VERSION 5.8 ;
BUSBITCHARS "[]" ;
DIVIDERCHAR "/" ;
UNITS
    DATABASE MICRONS 1000 ;
END UNITS

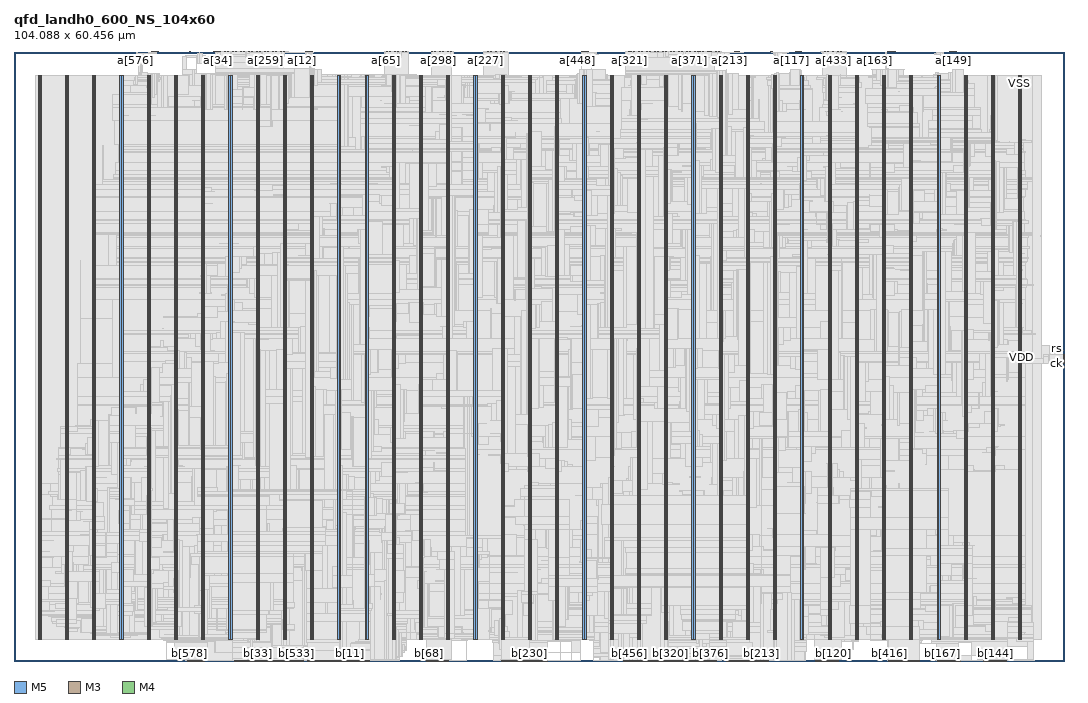
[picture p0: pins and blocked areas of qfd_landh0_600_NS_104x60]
MACRO qfd_landh0_600_NS_104x60
  FOREIGN qfd_landh0_600_NS_104x60 0 0 ;
  CLASS BLOCK ;
  SIZE 104.088 BY 60.456 ;
  PIN a[0]
    DIRECTION INPUT ;
    USE SIGNAL ;
    PORT
      LAYER M5 ;
        RECT  27.408 60.372 27.432 60.456 ;
    END
  END a[0]
  PIN a[100]
    DIRECTION INPUT ;
    USE SIGNAL ;
    PORT
      LAYER M5 ;
        RECT  75.408 60.372 75.432 60.456 ;
    END
  END a[100]
  PIN a[101]
    DIRECTION INPUT ;
    USE SIGNAL ;
    PORT
      LAYER M5 ;
        RECT  75.504 60.372 75.528 60.456 ;
    END
  END a[101]
  PIN a[102]
    DIRECTION INPUT ;
    USE SIGNAL ;
    PORT
      LAYER M5 ;
        RECT  75.6 60.372 75.624 60.456 ;
    END
  END a[102]
  PIN a[103]
    DIRECTION INPUT ;
    USE SIGNAL ;
    PORT
      LAYER M5 ;
        RECT  75.696 60.372 75.72 60.456 ;
    END
  END a[103]
  PIN a[104]
    DIRECTION INPUT ;
    USE SIGNAL ;
    PORT
      LAYER M5 ;
        RECT  75.792 60.372 75.816 60.456 ;
    END
  END a[104]
  PIN a[105]
    DIRECTION INPUT ;
    USE SIGNAL ;
    PORT
      LAYER M5 ;
        RECT  75.888 60.372 75.912 60.456 ;
    END
  END a[105]
  PIN a[106]
    DIRECTION INPUT ;
    USE SIGNAL ;
    PORT
      LAYER M5 ;
        RECT  75.984 60.372 76.008 60.456 ;
    END
  END a[106]
  PIN a[107]
    DIRECTION INPUT ;
    USE SIGNAL ;
    PORT
      LAYER M5 ;
        RECT  76.08 60.372 76.104 60.456 ;
    END
  END a[107]
  PIN a[108]
    DIRECTION INPUT ;
    USE SIGNAL ;
    PORT
      LAYER M5 ;
        RECT  76.176 60.372 76.2 60.456 ;
    END
  END a[108]
  PIN a[109]
    DIRECTION INPUT ;
    USE SIGNAL ;
    PORT
      LAYER M5 ;
        RECT  76.272 60.372 76.296 60.456 ;
    END
  END a[109]
  PIN a[10]
    DIRECTION INPUT ;
    USE SIGNAL ;
    PORT
      LAYER M5 ;
        RECT  28.368 60.372 28.392 60.456 ;
    END
  END a[10]
  PIN a[110]
    DIRECTION INPUT ;
    USE SIGNAL ;
    PORT
      LAYER M5 ;
        RECT  76.368 60.372 76.392 60.456 ;
    END
  END a[110]
  PIN a[111]
    DIRECTION INPUT ;
    USE SIGNAL ;
    PORT
      LAYER M5 ;
        RECT  76.464 60.372 76.488 60.456 ;
    END
  END a[111]
  PIN a[112]
    DIRECTION INPUT ;
    USE SIGNAL ;
    PORT
      LAYER M5 ;
        RECT  76.56 60.372 76.584 60.456 ;
    END
  END a[112]
  PIN a[113]
    DIRECTION INPUT ;
    USE SIGNAL ;
    PORT
      LAYER M5 ;
        RECT  76.656 60.372 76.68 60.456 ;
    END
  END a[113]
  PIN a[114]
    DIRECTION INPUT ;
    USE SIGNAL ;
    PORT
      LAYER M5 ;
        RECT  76.752 60.372 76.776 60.456 ;
    END
  END a[114]
  PIN a[115]
    DIRECTION INPUT ;
    USE SIGNAL ;
    PORT
      LAYER M5 ;
        RECT  76.848 60.372 76.872 60.456 ;
    END
  END a[115]
  PIN a[116]
    DIRECTION INPUT ;
    USE SIGNAL ;
    PORT
      LAYER M5 ;
        RECT  76.944 60.372 76.968 60.456 ;
    END
  END a[116]
  PIN a[117]
    DIRECTION INPUT ;
    USE SIGNAL ;
    PORT
      LAYER M5 ;
        RECT  77.04 60.372 77.064 60.456 ;
    END
  END a[117]
  PIN a[118]
    DIRECTION INPUT ;
    USE SIGNAL ;
    PORT
      LAYER M5 ;
        RECT  77.136 60.372 77.16 60.456 ;
    END
  END a[118]
  PIN a[119]
    DIRECTION INPUT ;
    USE SIGNAL ;
    PORT
      LAYER M5 ;
        RECT  77.232 60.372 77.256 60.456 ;
    END
  END a[119]
  PIN a[11]
    DIRECTION INPUT ;
    USE SIGNAL ;
    PORT
      LAYER M5 ;
        RECT  28.464 60.372 28.488 60.456 ;
    END
  END a[11]
  PIN a[120]
    DIRECTION INPUT ;
    USE SIGNAL ;
    PORT
      LAYER M5 ;
        RECT  77.328 60.372 77.352 60.456 ;
    END
  END a[120]
  PIN a[121]
    DIRECTION INPUT ;
    USE SIGNAL ;
    PORT
      LAYER M5 ;
        RECT  77.424 60.372 77.448 60.456 ;
    END
  END a[121]
  PIN a[122]
    DIRECTION INPUT ;
    USE SIGNAL ;
    PORT
      LAYER M5 ;
        RECT  77.52 60.372 77.544 60.456 ;
    END
  END a[122]
  PIN a[123]
    DIRECTION INPUT ;
    USE SIGNAL ;
    PORT
      LAYER M5 ;
        RECT  77.616 60.372 77.64 60.456 ;
    END
  END a[123]
  PIN a[124]
    DIRECTION INPUT ;
    USE SIGNAL ;
    PORT
      LAYER M5 ;
        RECT  77.712 60.372 77.736 60.456 ;
    END
  END a[124]
  PIN a[125]
    DIRECTION INPUT ;
    USE SIGNAL ;
    PORT
      LAYER M5 ;
        RECT  77.808 60.372 77.832 60.456 ;
    END
  END a[125]
  PIN a[126]
    DIRECTION INPUT ;
    USE SIGNAL ;
    PORT
      LAYER M5 ;
        RECT  77.904 60.372 77.928 60.456 ;
    END
  END a[126]
  PIN a[127]
    DIRECTION INPUT ;
    USE SIGNAL ;
    PORT
      LAYER M5 ;
        RECT  78 60.372 78.024 60.456 ;
    END
  END a[127]
  PIN a[128]
    DIRECTION INPUT ;
    USE SIGNAL ;
    PORT
      LAYER M5 ;
        RECT  91.152 60.372 91.176 60.456 ;
    END
  END a[128]
  PIN a[129]
    DIRECTION INPUT ;
    USE SIGNAL ;
    PORT
      LAYER M5 ;
        RECT  91.248 60.372 91.272 60.456 ;
    END
  END a[129]
  PIN a[12]
    DIRECTION INPUT ;
    USE SIGNAL ;
    PORT
      LAYER M5 ;
        RECT  28.56 60.372 28.584 60.456 ;
    END
  END a[12]
  PIN a[130]
    DIRECTION INPUT ;
    USE SIGNAL ;
    PORT
      LAYER M5 ;
        RECT  91.344 60.372 91.368 60.456 ;
    END
  END a[130]
  PIN a[131]
    DIRECTION INPUT ;
    USE SIGNAL ;
    PORT
      LAYER M5 ;
        RECT  91.44 60.372 91.464 60.456 ;
    END
  END a[131]
  PIN a[132]
    DIRECTION INPUT ;
    USE SIGNAL ;
    PORT
      LAYER M5 ;
        RECT  91.536 60.372 91.56 60.456 ;
    END
  END a[132]
  PIN a[133]
    DIRECTION INPUT ;
    USE SIGNAL ;
    PORT
      LAYER M5 ;
        RECT  91.632 60.372 91.656 60.456 ;
    END
  END a[133]
  PIN a[134]
    DIRECTION INPUT ;
    USE SIGNAL ;
    PORT
      LAYER M5 ;
        RECT  91.728 60.372 91.752 60.456 ;
    END
  END a[134]
  PIN a[135]
    DIRECTION INPUT ;
    USE SIGNAL ;
    PORT
      LAYER M5 ;
        RECT  91.824 60.372 91.848 60.456 ;
    END
  END a[135]
  PIN a[136]
    DIRECTION INPUT ;
    USE SIGNAL ;
    PORT
      LAYER M5 ;
        RECT  91.92 60.372 91.944 60.456 ;
    END
  END a[136]
  PIN a[137]
    DIRECTION INPUT ;
    USE SIGNAL ;
    PORT
      LAYER M5 ;
        RECT  92.016 60.372 92.04 60.456 ;
    END
  END a[137]
  PIN a[138]
    DIRECTION INPUT ;
    USE SIGNAL ;
    PORT
      LAYER M5 ;
        RECT  92.112 60.372 92.136 60.456 ;
    END
  END a[138]
  PIN a[139]
    DIRECTION INPUT ;
    USE SIGNAL ;
    PORT
      LAYER M5 ;
        RECT  92.208 60.372 92.232 60.456 ;
    END
  END a[139]
  PIN a[13]
    DIRECTION INPUT ;
    USE SIGNAL ;
    PORT
      LAYER M5 ;
        RECT  28.656 60.372 28.68 60.456 ;
    END
  END a[13]
  PIN a[140]
    DIRECTION INPUT ;
    USE SIGNAL ;
    PORT
      LAYER M5 ;
        RECT  92.304 60.372 92.328 60.456 ;
    END
  END a[140]
  PIN a[141]
    DIRECTION INPUT ;
    USE SIGNAL ;
    PORT
      LAYER M5 ;
        RECT  92.4 60.372 92.424 60.456 ;
    END
  END a[141]
  PIN a[142]
    DIRECTION INPUT ;
    USE SIGNAL ;
    PORT
      LAYER M5 ;
        RECT  92.496 60.372 92.52 60.456 ;
    END
  END a[142]
  PIN a[143]
    DIRECTION INPUT ;
    USE SIGNAL ;
    PORT
      LAYER M5 ;
        RECT  92.592 60.372 92.616 60.456 ;
    END
  END a[143]
  PIN a[144]
    DIRECTION INPUT ;
    USE SIGNAL ;
    PORT
      LAYER M5 ;
        RECT  92.688 60.372 92.712 60.456 ;
    END
  END a[144]
  PIN a[145]
    DIRECTION INPUT ;
    USE SIGNAL ;
    PORT
      LAYER M5 ;
        RECT  92.784 60.372 92.808 60.456 ;
    END
  END a[145]
  PIN a[146]
    DIRECTION INPUT ;
    USE SIGNAL ;
    PORT
      LAYER M5 ;
        RECT  92.88 60.372 92.904 60.456 ;
    END
  END a[146]
  PIN a[147]
    DIRECTION INPUT ;
    USE SIGNAL ;
    PORT
      LAYER M5 ;
        RECT  92.976 60.372 93 60.456 ;
    END
  END a[147]
  PIN a[148]
    DIRECTION INPUT ;
    USE SIGNAL ;
    PORT
      LAYER M5 ;
        RECT  93.072 60.372 93.096 60.456 ;
    END
  END a[148]
  PIN a[149]
    DIRECTION INPUT ;
    USE SIGNAL ;
    PORT
      LAYER M5 ;
        RECT  93.168 60.372 93.192 60.456 ;
    END
  END a[149]
  PIN a[14]
    DIRECTION INPUT ;
    USE SIGNAL ;
    PORT
      LAYER M5 ;
        RECT  28.752 60.372 28.776 60.456 ;
    END
  END a[14]
  PIN a[150]
    DIRECTION INPUT ;
    USE SIGNAL ;
    PORT
      LAYER M5 ;
        RECT  93.264 60.372 93.288 60.456 ;
    END
  END a[150]
  PIN a[151]
    DIRECTION INPUT ;
    USE SIGNAL ;
    PORT
      LAYER M5 ;
        RECT  93.36 60.372 93.384 60.456 ;
    END
  END a[151]
  PIN a[152]
    DIRECTION INPUT ;
    USE SIGNAL ;
    PORT
      LAYER M5 ;
        RECT  93.456 60.372 93.48 60.456 ;
    END
  END a[152]
  PIN a[153]
    DIRECTION INPUT ;
    USE SIGNAL ;
    PORT
      LAYER M5 ;
        RECT  93.552 60.372 93.576 60.456 ;
    END
  END a[153]
  PIN a[154]
    DIRECTION INPUT ;
    USE SIGNAL ;
    PORT
      LAYER M5 ;
        RECT  93.648 60.372 93.672 60.456 ;
    END
  END a[154]
  PIN a[155]
    DIRECTION INPUT ;
    USE SIGNAL ;
    PORT
      LAYER M5 ;
        RECT  93.744 60.372 93.768 60.456 ;
    END
  END a[155]
  PIN a[156]
    DIRECTION INPUT ;
    USE SIGNAL ;
    PORT
      LAYER M5 ;
        RECT  93.84 60.372 93.864 60.456 ;
    END
  END a[156]
  PIN a[157]
    DIRECTION INPUT ;
    USE SIGNAL ;
    PORT
      LAYER M5 ;
        RECT  93.936 60.372 93.96 60.456 ;
    END
  END a[157]
  PIN a[158]
    DIRECTION INPUT ;
    USE SIGNAL ;
    PORT
      LAYER M5 ;
        RECT  94.032 60.372 94.056 60.456 ;
    END
  END a[158]
  PIN a[159]
    DIRECTION INPUT ;
    USE SIGNAL ;
    PORT
      LAYER M5 ;
        RECT  94.128 60.372 94.152 60.456 ;
    END
  END a[159]
  PIN a[15]
    DIRECTION INPUT ;
    USE SIGNAL ;
    PORT
      LAYER M5 ;
        RECT  28.848 60.372 28.872 60.456 ;
    END
  END a[15]
  PIN a[160]
    DIRECTION INPUT ;
    USE SIGNAL ;
    PORT
      LAYER M5 ;
        RECT  85.008 60.372 85.032 60.456 ;
    END
  END a[160]
  PIN a[161]
    DIRECTION INPUT ;
    USE SIGNAL ;
    PORT
      LAYER M5 ;
        RECT  85.104 60.372 85.128 60.456 ;
    END
  END a[161]
  PIN a[162]
    DIRECTION INPUT ;
    USE SIGNAL ;
    PORT
      LAYER M5 ;
        RECT  85.2 60.372 85.224 60.456 ;
    END
  END a[162]
  PIN a[163]
    DIRECTION INPUT ;
    USE SIGNAL ;
    PORT
      LAYER M5 ;
        RECT  85.296 60.372 85.32 60.456 ;
    END
  END a[163]
  PIN a[164]
    DIRECTION INPUT ;
    USE SIGNAL ;
    PORT
      LAYER M5 ;
        RECT  85.392 60.372 85.416 60.456 ;
    END
  END a[164]
  PIN a[165]
    DIRECTION INPUT ;
    USE SIGNAL ;
    PORT
      LAYER M5 ;
        RECT  85.488 60.372 85.512 60.456 ;
    END
  END a[165]
  PIN a[166]
    DIRECTION INPUT ;
    USE SIGNAL ;
    PORT
      LAYER M5 ;
        RECT  85.584 60.372 85.608 60.456 ;
    END
  END a[166]
  PIN a[167]
    DIRECTION INPUT ;
    USE SIGNAL ;
    PORT
      LAYER M5 ;
        RECT  85.68 60.372 85.704 60.456 ;
    END
  END a[167]
  PIN a[168]
    DIRECTION INPUT ;
    USE SIGNAL ;
    PORT
      LAYER M5 ;
        RECT  85.776 60.372 85.8 60.456 ;
    END
  END a[168]
  PIN a[169]
    DIRECTION INPUT ;
    USE SIGNAL ;
    PORT
      LAYER M5 ;
        RECT  85.872 60.372 85.896 60.456 ;
    END
  END a[169]
  PIN a[16]
    DIRECTION INPUT ;
    USE SIGNAL ;
    PORT
      LAYER M5 ;
        RECT  28.944 60.372 28.968 60.456 ;
    END
  END a[16]
  PIN a[170]
    DIRECTION INPUT ;
    USE SIGNAL ;
    PORT
      LAYER M5 ;
        RECT  85.968 60.372 85.992 60.456 ;
    END
  END a[170]
  PIN a[171]
    DIRECTION INPUT ;
    USE SIGNAL ;
    PORT
      LAYER M5 ;
        RECT  86.064 60.372 86.088 60.456 ;
    END
  END a[171]
  PIN a[172]
    DIRECTION INPUT ;
    USE SIGNAL ;
    PORT
      LAYER M5 ;
        RECT  86.16 60.372 86.184 60.456 ;
    END
  END a[172]
  PIN a[173]
    DIRECTION INPUT ;
    USE SIGNAL ;
    PORT
      LAYER M5 ;
        RECT  86.256 60.372 86.28 60.456 ;
    END
  END a[173]
  PIN a[174]
    DIRECTION INPUT ;
    USE SIGNAL ;
    PORT
      LAYER M5 ;
        RECT  86.352 60.372 86.376 60.456 ;
    END
  END a[174]
  PIN a[175]
    DIRECTION INPUT ;
    USE SIGNAL ;
    PORT
      LAYER M5 ;
        RECT  86.448 60.372 86.472 60.456 ;
    END
  END a[175]
  PIN a[176]
    DIRECTION INPUT ;
    USE SIGNAL ;
    PORT
      LAYER M5 ;
        RECT  86.544 60.372 86.568 60.456 ;
    END
  END a[176]
  PIN a[177]
    DIRECTION INPUT ;
    USE SIGNAL ;
    PORT
      LAYER M5 ;
        RECT  86.64 60.372 86.664 60.456 ;
    END
  END a[177]
  PIN a[178]
    DIRECTION INPUT ;
    USE SIGNAL ;
    PORT
      LAYER M5 ;
        RECT  86.736 60.372 86.76 60.456 ;
    END
  END a[178]
  PIN a[179]
    DIRECTION INPUT ;
    USE SIGNAL ;
    PORT
      LAYER M5 ;
        RECT  86.832 60.372 86.856 60.456 ;
    END
  END a[179]
  PIN a[17]
    DIRECTION INPUT ;
    USE SIGNAL ;
    PORT
      LAYER M5 ;
        RECT  29.04 60.372 29.064 60.456 ;
    END
  END a[17]
  PIN a[180]
    DIRECTION INPUT ;
    USE SIGNAL ;
    PORT
      LAYER M5 ;
        RECT  86.928 60.372 86.952 60.456 ;
    END
  END a[180]
  PIN a[181]
    DIRECTION INPUT ;
    USE SIGNAL ;
    PORT
      LAYER M5 ;
        RECT  87.024 60.372 87.048 60.456 ;
    END
  END a[181]
  PIN a[182]
    DIRECTION INPUT ;
    USE SIGNAL ;
    PORT
      LAYER M5 ;
        RECT  87.12 60.372 87.144 60.456 ;
    END
  END a[182]
  PIN a[183]
    DIRECTION INPUT ;
    USE SIGNAL ;
    PORT
      LAYER M5 ;
        RECT  87.216 60.372 87.24 60.456 ;
    END
  END a[183]
  PIN a[184]
    DIRECTION INPUT ;
    USE SIGNAL ;
    PORT
      LAYER M5 ;
        RECT  87.312 60.372 87.336 60.456 ;
    END
  END a[184]
  PIN a[185]
    DIRECTION INPUT ;
    USE SIGNAL ;
    PORT
      LAYER M5 ;
        RECT  87.408 60.372 87.432 60.456 ;
    END
  END a[185]
  PIN a[186]
    DIRECTION INPUT ;
    USE SIGNAL ;
    PORT
      LAYER M5 ;
        RECT  87.504 60.372 87.528 60.456 ;
    END
  END a[186]
  PIN a[187]
    DIRECTION INPUT ;
    USE SIGNAL ;
    PORT
      LAYER M5 ;
        RECT  87.6 60.372 87.624 60.456 ;
    END
  END a[187]
  PIN a[188]
    DIRECTION INPUT ;
    USE SIGNAL ;
    PORT
      LAYER M5 ;
        RECT  87.696 60.372 87.72 60.456 ;
    END
  END a[188]
  PIN a[189]
    DIRECTION INPUT ;
    USE SIGNAL ;
    PORT
      LAYER M5 ;
        RECT  87.792 60.372 87.816 60.456 ;
    END
  END a[189]
  PIN a[18]
    DIRECTION INPUT ;
    USE SIGNAL ;
    PORT
      LAYER M5 ;
        RECT  29.136 60.372 29.16 60.456 ;
    END
  END a[18]
  PIN a[190]
    DIRECTION INPUT ;
    USE SIGNAL ;
    PORT
      LAYER M5 ;
        RECT  87.888 60.372 87.912 60.456 ;
    END
  END a[190]
  PIN a[191]
    DIRECTION INPUT ;
    USE SIGNAL ;
    PORT
      LAYER M5 ;
        RECT  87.984 60.372 88.008 60.456 ;
    END
  END a[191]
  PIN a[192]
    DIRECTION INPUT ;
    USE SIGNAL ;
    PORT
      LAYER M5 ;
        RECT  68.88 60.372 68.904 60.456 ;
    END
  END a[192]
  PIN a[193]
    DIRECTION INPUT ;
    USE SIGNAL ;
    PORT
      LAYER M5 ;
        RECT  68.976 60.372 69 60.456 ;
    END
  END a[193]
  PIN a[194]
    DIRECTION INPUT ;
    USE SIGNAL ;
    PORT
      LAYER M5 ;
        RECT  69.072 60.372 69.096 60.456 ;
    END
  END a[194]
  PIN a[195]
    DIRECTION INPUT ;
    USE SIGNAL ;
    PORT
      LAYER M5 ;
        RECT  69.168 60.372 69.192 60.456 ;
    END
  END a[195]
  PIN a[196]
    DIRECTION INPUT ;
    USE SIGNAL ;
    PORT
      LAYER M5 ;
        RECT  69.264 60.372 69.288 60.456 ;
    END
  END a[196]
  PIN a[197]
    DIRECTION INPUT ;
    USE SIGNAL ;
    PORT
      LAYER M5 ;
        RECT  69.36 60.372 69.384 60.456 ;
    END
  END a[197]
  PIN a[198]
    DIRECTION INPUT ;
    USE SIGNAL ;
    PORT
      LAYER M5 ;
        RECT  69.456 60.372 69.48 60.456 ;
    END
  END a[198]
  PIN a[199]
    DIRECTION INPUT ;
    USE SIGNAL ;
    PORT
      LAYER M5 ;
        RECT  69.552 60.372 69.576 60.456 ;
    END
  END a[199]
  PIN a[19]
    DIRECTION INPUT ;
    USE SIGNAL ;
    PORT
      LAYER M5 ;
        RECT  29.232 60.372 29.256 60.456 ;
    END
  END a[19]
  PIN a[1]
    DIRECTION INPUT ;
    USE SIGNAL ;
    PORT
      LAYER M5 ;
        RECT  27.504 60.372 27.528 60.456 ;
    END
  END a[1]
  PIN a[200]
    DIRECTION INPUT ;
    USE SIGNAL ;
    PORT
      LAYER M5 ;
        RECT  69.648 60.372 69.672 60.456 ;
    END
  END a[200]
  PIN a[201]
    DIRECTION INPUT ;
    USE SIGNAL ;
    PORT
      LAYER M5 ;
        RECT  69.744 60.372 69.768 60.456 ;
    END
  END a[201]
  PIN a[202]
    DIRECTION INPUT ;
    USE SIGNAL ;
    PORT
      LAYER M5 ;
        RECT  69.84 60.372 69.864 60.456 ;
    END
  END a[202]
  PIN a[203]
    DIRECTION INPUT ;
    USE SIGNAL ;
    PORT
      LAYER M5 ;
        RECT  69.936 60.372 69.96 60.456 ;
    END
  END a[203]
  PIN a[204]
    DIRECTION INPUT ;
    USE SIGNAL ;
    PORT
      LAYER M5 ;
        RECT  70.032 60.372 70.056 60.456 ;
    END
  END a[204]
  PIN a[205]
    DIRECTION INPUT ;
    USE SIGNAL ;
    PORT
      LAYER M5 ;
        RECT  70.128 60.372 70.152 60.456 ;
    END
  END a[205]
  PIN a[206]
    DIRECTION INPUT ;
    USE SIGNAL ;
    PORT
      LAYER M5 ;
        RECT  70.224 60.372 70.248 60.456 ;
    END
  END a[206]
  PIN a[207]
    DIRECTION INPUT ;
    USE SIGNAL ;
    PORT
      LAYER M5 ;
        RECT  70.32 60.372 70.344 60.456 ;
    END
  END a[207]
  PIN a[208]
    DIRECTION INPUT ;
    USE SIGNAL ;
    PORT
      LAYER M5 ;
        RECT  70.416 60.372 70.44 60.456 ;
    END
  END a[208]
  PIN a[209]
    DIRECTION INPUT ;
    USE SIGNAL ;
    PORT
      LAYER M5 ;
        RECT  70.512 60.372 70.536 60.456 ;
    END
  END a[209]
  PIN a[20]
    DIRECTION INPUT ;
    USE SIGNAL ;
    PORT
      LAYER M5 ;
        RECT  29.328 60.372 29.352 60.456 ;
    END
  END a[20]
  PIN a[210]
    DIRECTION INPUT ;
    USE SIGNAL ;
    PORT
      LAYER M5 ;
        RECT  70.608 60.372 70.632 60.456 ;
    END
  END a[210]
  PIN a[211]
    DIRECTION INPUT ;
    USE SIGNAL ;
    PORT
      LAYER M5 ;
        RECT  70.704 60.372 70.728 60.456 ;
    END
  END a[211]
  PIN a[212]
    DIRECTION INPUT ;
    USE SIGNAL ;
    PORT
      LAYER M5 ;
        RECT  70.8 60.372 70.824 60.456 ;
    END
  END a[212]
  PIN a[213]
    DIRECTION INPUT ;
    USE SIGNAL ;
    PORT
      LAYER M5 ;
        RECT  70.896 60.372 70.92 60.456 ;
    END
  END a[213]
  PIN a[214]
    DIRECTION INPUT ;
    USE SIGNAL ;
    PORT
      LAYER M5 ;
        RECT  70.992 60.372 71.016 60.456 ;
    END
  END a[214]
  PIN a[215]
    DIRECTION INPUT ;
    USE SIGNAL ;
    PORT
      LAYER M5 ;
        RECT  71.088 60.372 71.112 60.456 ;
    END
  END a[215]
  PIN a[216]
    DIRECTION INPUT ;
    USE SIGNAL ;
    PORT
      LAYER M5 ;
        RECT  71.184 60.372 71.208 60.456 ;
    END
  END a[216]
  PIN a[217]
    DIRECTION INPUT ;
    USE SIGNAL ;
    PORT
      LAYER M5 ;
        RECT  71.28 60.372 71.304 60.456 ;
    END
  END a[217]
  PIN a[218]
    DIRECTION INPUT ;
    USE SIGNAL ;
    PORT
      LAYER M5 ;
        RECT  71.376 60.372 71.4 60.456 ;
    END
  END a[218]
  PIN a[219]
    DIRECTION INPUT ;
    USE SIGNAL ;
    PORT
      LAYER M5 ;
        RECT  71.472 60.372 71.496 60.456 ;
    END
  END a[219]
  PIN a[21]
    DIRECTION INPUT ;
    USE SIGNAL ;
    PORT
      LAYER M5 ;
        RECT  29.424 60.372 29.448 60.456 ;
    END
  END a[21]
  PIN a[220]
    DIRECTION INPUT ;
    USE SIGNAL ;
    PORT
      LAYER M5 ;
        RECT  71.568 60.372 71.592 60.456 ;
    END
  END a[220]
  PIN a[221]
    DIRECTION INPUT ;
    USE SIGNAL ;
    PORT
      LAYER M5 ;
        RECT  71.664 60.372 71.688 60.456 ;
    END
  END a[221]
  PIN a[222]
    DIRECTION INPUT ;
    USE SIGNAL ;
    PORT
      LAYER M5 ;
        RECT  71.76 60.372 71.784 60.456 ;
    END
  END a[222]
  PIN a[223]
    DIRECTION INPUT ;
    USE SIGNAL ;
    PORT
      LAYER M5 ;
        RECT  71.856 60.372 71.88 60.456 ;
    END
  END a[223]
  PIN a[224]
    DIRECTION INPUT ;
    USE SIGNAL ;
    PORT
      LAYER M3 ;
        RECT  46.548 60.419 46.566 60.456 ;
    END
  END a[224]
  PIN a[225]
    DIRECTION INPUT ;
    USE SIGNAL ;
    PORT
      LAYER M3 ;
        RECT  46.62 60.419 46.638 60.456 ;
    END
  END a[225]
  PIN a[226]
    DIRECTION INPUT ;
    USE SIGNAL ;
    PORT
      LAYER M3 ;
        RECT  46.692 60.419 46.71 60.456 ;
    END
  END a[226]
  PIN a[227]
    DIRECTION INPUT ;
    USE SIGNAL ;
    PORT
      LAYER M3 ;
        RECT  46.764 60.419 46.782 60.456 ;
    END
  END a[227]
  PIN a[228]
    DIRECTION INPUT ;
    USE SIGNAL ;
    PORT
      LAYER M3 ;
        RECT  46.836 60.419 46.854 60.456 ;
    END
  END a[228]
  PIN a[229]
    DIRECTION INPUT ;
    USE SIGNAL ;
    PORT
      LAYER M3 ;
        RECT  46.908 60.419 46.926 60.456 ;
    END
  END a[229]
  PIN a[22]
    DIRECTION INPUT ;
    USE SIGNAL ;
    PORT
      LAYER M5 ;
        RECT  29.52 60.372 29.544 60.456 ;
    END
  END a[22]
  PIN a[230]
    DIRECTION INPUT ;
    USE SIGNAL ;
    PORT
      LAYER M3 ;
        RECT  46.98 60.419 46.998 60.456 ;
    END
  END a[230]
  PIN a[231]
    DIRECTION INPUT ;
    USE SIGNAL ;
    PORT
      LAYER M3 ;
        RECT  47.052 60.419 47.07 60.456 ;
    END
  END a[231]
  PIN a[232]
    DIRECTION INPUT ;
    USE SIGNAL ;
    PORT
      LAYER M3 ;
        RECT  47.124 60.419 47.142 60.456 ;
    END
  END a[232]
  PIN a[233]
    DIRECTION INPUT ;
    USE SIGNAL ;
    PORT
      LAYER M3 ;
        RECT  47.196 60.419 47.214 60.456 ;
    END
  END a[233]
  PIN a[234]
    DIRECTION INPUT ;
    USE SIGNAL ;
    PORT
      LAYER M3 ;
        RECT  47.268 60.419 47.286 60.456 ;
    END
  END a[234]
  PIN a[235]
    DIRECTION INPUT ;
    USE SIGNAL ;
    PORT
      LAYER M3 ;
        RECT  47.34 60.419 47.358 60.456 ;
    END
  END a[235]
  PIN a[236]
    DIRECTION INPUT ;
    USE SIGNAL ;
    PORT
      LAYER M3 ;
        RECT  47.412 60.419 47.43 60.456 ;
    END
  END a[236]
  PIN a[237]
    DIRECTION INPUT ;
    USE SIGNAL ;
    PORT
      LAYER M3 ;
        RECT  47.484 60.419 47.502 60.456 ;
    END
  END a[237]
  PIN a[238]
    DIRECTION INPUT ;
    USE SIGNAL ;
    PORT
      LAYER M3 ;
        RECT  47.556 60.419 47.574 60.456 ;
    END
  END a[238]
  PIN a[239]
    DIRECTION INPUT ;
    USE SIGNAL ;
    PORT
      LAYER M3 ;
        RECT  47.628 60.419 47.646 60.456 ;
    END
  END a[239]
  PIN a[23]
    DIRECTION INPUT ;
    USE SIGNAL ;
    PORT
      LAYER M5 ;
        RECT  29.616 60.372 29.64 60.456 ;
    END
  END a[23]
  PIN a[240]
    DIRECTION INPUT ;
    USE SIGNAL ;
    PORT
      LAYER M3 ;
        RECT  47.7 60.419 47.718 60.456 ;
    END
  END a[240]
  PIN a[241]
    DIRECTION INPUT ;
    USE SIGNAL ;
    PORT
      LAYER M3 ;
        RECT  47.772 60.419 47.79 60.456 ;
    END
  END a[241]
  PIN a[242]
    DIRECTION INPUT ;
    USE SIGNAL ;
    PORT
      LAYER M3 ;
        RECT  47.844 60.419 47.862 60.456 ;
    END
  END a[242]
  PIN a[243]
    DIRECTION INPUT ;
    USE SIGNAL ;
    PORT
      LAYER M3 ;
        RECT  47.916 60.419 47.934 60.456 ;
    END
  END a[243]
  PIN a[244]
    DIRECTION INPUT ;
    USE SIGNAL ;
    PORT
      LAYER M3 ;
        RECT  47.988 60.419 48.006 60.456 ;
    END
  END a[244]
  PIN a[245]
    DIRECTION INPUT ;
    USE SIGNAL ;
    PORT
      LAYER M3 ;
        RECT  48.06 60.419 48.078 60.456 ;
    END
  END a[245]
  PIN a[246]
    DIRECTION INPUT ;
    USE SIGNAL ;
    PORT
      LAYER M3 ;
        RECT  48.132 60.419 48.15 60.456 ;
    END
  END a[246]
  PIN a[247]
    DIRECTION INPUT ;
    USE SIGNAL ;
    PORT
      LAYER M3 ;
        RECT  48.204 60.419 48.222 60.456 ;
    END
  END a[247]
  PIN a[248]
    DIRECTION INPUT ;
    USE SIGNAL ;
    PORT
      LAYER M3 ;
        RECT  48.276 60.419 48.294 60.456 ;
    END
  END a[248]
  PIN a[249]
    DIRECTION INPUT ;
    USE SIGNAL ;
    PORT
      LAYER M3 ;
        RECT  48.348 60.419 48.366 60.456 ;
    END
  END a[249]
  PIN a[24]
    DIRECTION INPUT ;
    USE SIGNAL ;
    PORT
      LAYER M5 ;
        RECT  29.712 60.372 29.736 60.456 ;
    END
  END a[24]
  PIN a[250]
    DIRECTION INPUT ;
    USE SIGNAL ;
    PORT
      LAYER M3 ;
        RECT  48.42 60.419 48.438 60.456 ;
    END
  END a[250]
  PIN a[251]
    DIRECTION INPUT ;
    USE SIGNAL ;
    PORT
      LAYER M3 ;
        RECT  48.492 60.419 48.51 60.456 ;
    END
  END a[251]
  PIN a[252]
    DIRECTION INPUT ;
    USE SIGNAL ;
    PORT
      LAYER M3 ;
        RECT  48.564 60.419 48.582 60.456 ;
    END
  END a[252]
  PIN a[253]
    DIRECTION INPUT ;
    USE SIGNAL ;
    PORT
      LAYER M3 ;
        RECT  48.636 60.419 48.654 60.456 ;
    END
  END a[253]
  PIN a[254]
    DIRECTION INPUT ;
    USE SIGNAL ;
    PORT
      LAYER M3 ;
        RECT  48.708 60.419 48.726 60.456 ;
    END
  END a[254]
  PIN a[255]
    DIRECTION INPUT ;
    USE SIGNAL ;
    PORT
      LAYER M3 ;
        RECT  48.78 60.419 48.798 60.456 ;
    END
  END a[255]
  PIN a[256]
    DIRECTION INPUT ;
    USE SIGNAL ;
    PORT
      LAYER M3 ;
        RECT  24.66 60.419 24.678 60.456 ;
    END
  END a[256]
  PIN a[257]
    DIRECTION INPUT ;
    USE SIGNAL ;
    PORT
      LAYER M3 ;
        RECT  24.732 60.419 24.75 60.456 ;
    END
  END a[257]
  PIN a[258]
    DIRECTION INPUT ;
    USE SIGNAL ;
    PORT
      LAYER M3 ;
        RECT  24.804 60.419 24.822 60.456 ;
    END
  END a[258]
  PIN a[259]
    DIRECTION INPUT ;
    USE SIGNAL ;
    PORT
      LAYER M3 ;
        RECT  24.876 60.419 24.894 60.456 ;
    END
  END a[259]
  PIN a[25]
    DIRECTION INPUT ;
    USE SIGNAL ;
    PORT
      LAYER M5 ;
        RECT  29.808 60.372 29.832 60.456 ;
    END
  END a[25]
  PIN a[260]
    DIRECTION INPUT ;
    USE SIGNAL ;
    PORT
      LAYER M3 ;
        RECT  24.948 60.419 24.966 60.456 ;
    END
  END a[260]
  PIN a[261]
    DIRECTION INPUT ;
    USE SIGNAL ;
    PORT
      LAYER M3 ;
        RECT  25.02 60.419 25.038 60.456 ;
    END
  END a[261]
  PIN a[262]
    DIRECTION INPUT ;
    USE SIGNAL ;
    PORT
      LAYER M3 ;
        RECT  25.092 60.419 25.11 60.456 ;
    END
  END a[262]
  PIN a[263]
    DIRECTION INPUT ;
    USE SIGNAL ;
    PORT
      LAYER M3 ;
        RECT  25.164 60.419 25.182 60.456 ;
    END
  END a[263]
  PIN a[264]
    DIRECTION INPUT ;
    USE SIGNAL ;
    PORT
      LAYER M3 ;
        RECT  25.236 60.419 25.254 60.456 ;
    END
  END a[264]
  PIN a[265]
    DIRECTION INPUT ;
    USE SIGNAL ;
    PORT
      LAYER M3 ;
        RECT  25.308 60.419 25.326 60.456 ;
    END
  END a[265]
  PIN a[266]
    DIRECTION INPUT ;
    USE SIGNAL ;
    PORT
      LAYER M3 ;
        RECT  25.38 60.419 25.398 60.456 ;
    END
  END a[266]
  PIN a[267]
    DIRECTION INPUT ;
    USE SIGNAL ;
    PORT
      LAYER M3 ;
        RECT  25.452 60.419 25.47 60.456 ;
    END
  END a[267]
  PIN a[268]
    DIRECTION INPUT ;
    USE SIGNAL ;
    PORT
      LAYER M3 ;
        RECT  25.524 60.419 25.542 60.456 ;
    END
  END a[268]
  PIN a[269]
    DIRECTION INPUT ;
    USE SIGNAL ;
    PORT
      LAYER M3 ;
        RECT  25.596 60.419 25.614 60.456 ;
    END
  END a[269]
  PIN a[26]
    DIRECTION INPUT ;
    USE SIGNAL ;
    PORT
      LAYER M5 ;
        RECT  29.904 60.372 29.928 60.456 ;
    END
  END a[26]
  PIN a[270]
    DIRECTION INPUT ;
    USE SIGNAL ;
    PORT
      LAYER M3 ;
        RECT  25.668 60.419 25.686 60.456 ;
    END
  END a[270]
  PIN a[271]
    DIRECTION INPUT ;
    USE SIGNAL ;
    PORT
      LAYER M3 ;
        RECT  25.74 60.419 25.758 60.456 ;
    END
  END a[271]
  PIN a[272]
    DIRECTION INPUT ;
    USE SIGNAL ;
    PORT
      LAYER M3 ;
        RECT  25.812 60.419 25.83 60.456 ;
    END
  END a[272]
  PIN a[273]
    DIRECTION INPUT ;
    USE SIGNAL ;
    PORT
      LAYER M3 ;
        RECT  25.884 60.419 25.902 60.456 ;
    END
  END a[273]
  PIN a[274]
    DIRECTION INPUT ;
    USE SIGNAL ;
    PORT
      LAYER M3 ;
        RECT  25.956 60.419 25.974 60.456 ;
    END
  END a[274]
  PIN a[275]
    DIRECTION INPUT ;
    USE SIGNAL ;
    PORT
      LAYER M3 ;
        RECT  26.028 60.419 26.046 60.456 ;
    END
  END a[275]
  PIN a[276]
    DIRECTION INPUT ;
    USE SIGNAL ;
    PORT
      LAYER M3 ;
        RECT  26.1 60.419 26.118 60.456 ;
    END
  END a[276]
  PIN a[277]
    DIRECTION INPUT ;
    USE SIGNAL ;
    PORT
      LAYER M3 ;
        RECT  26.172 60.419 26.19 60.456 ;
    END
  END a[277]
  PIN a[278]
    DIRECTION INPUT ;
    USE SIGNAL ;
    PORT
      LAYER M3 ;
        RECT  26.244 60.419 26.262 60.456 ;
    END
  END a[278]
  PIN a[279]
    DIRECTION INPUT ;
    USE SIGNAL ;
    PORT
      LAYER M3 ;
        RECT  26.316 60.419 26.334 60.456 ;
    END
  END a[279]
  PIN a[27]
    DIRECTION INPUT ;
    USE SIGNAL ;
    PORT
      LAYER M5 ;
        RECT  30 60.372 30.024 60.456 ;
    END
  END a[27]
  PIN a[280]
    DIRECTION INPUT ;
    USE SIGNAL ;
    PORT
      LAYER M3 ;
        RECT  26.388 60.419 26.406 60.456 ;
    END
  END a[280]
  PIN a[281]
    DIRECTION INPUT ;
    USE SIGNAL ;
    PORT
      LAYER M3 ;
        RECT  26.46 60.419 26.478 60.456 ;
    END
  END a[281]
  PIN a[282]
    DIRECTION INPUT ;
    USE SIGNAL ;
    PORT
      LAYER M3 ;
        RECT  26.532 60.419 26.55 60.456 ;
    END
  END a[282]
  PIN a[283]
    DIRECTION INPUT ;
    USE SIGNAL ;
    PORT
      LAYER M3 ;
        RECT  26.604 60.419 26.622 60.456 ;
    END
  END a[283]
  PIN a[284]
    DIRECTION INPUT ;
    USE SIGNAL ;
    PORT
      LAYER M3 ;
        RECT  26.676 60.419 26.694 60.456 ;
    END
  END a[284]
  PIN a[285]
    DIRECTION INPUT ;
    USE SIGNAL ;
    PORT
      LAYER M3 ;
        RECT  26.748 60.419 26.766 60.456 ;
    END
  END a[285]
  PIN a[286]
    DIRECTION INPUT ;
    USE SIGNAL ;
    PORT
      LAYER M3 ;
        RECT  26.82 60.419 26.838 60.456 ;
    END
  END a[286]
  PIN a[287]
    DIRECTION INPUT ;
    USE SIGNAL ;
    PORT
      LAYER M3 ;
        RECT  26.892 60.419 26.91 60.456 ;
    END
  END a[287]
  PIN a[288]
    DIRECTION INPUT ;
    USE SIGNAL ;
    PORT
      LAYER M3 ;
        RECT  41.364 60.419 41.382 60.456 ;
    END
  END a[288]
  PIN a[289]
    DIRECTION INPUT ;
    USE SIGNAL ;
    PORT
      LAYER M3 ;
        RECT  41.436 60.419 41.454 60.456 ;
    END
  END a[289]
  PIN a[28]
    DIRECTION INPUT ;
    USE SIGNAL ;
    PORT
      LAYER M5 ;
        RECT  30.096 60.372 30.12 60.456 ;
    END
  END a[28]
  PIN a[290]
    DIRECTION INPUT ;
    USE SIGNAL ;
    PORT
      LAYER M3 ;
        RECT  41.508 60.419 41.526 60.456 ;
    END
  END a[290]
  PIN a[291]
    DIRECTION INPUT ;
    USE SIGNAL ;
    PORT
      LAYER M3 ;
        RECT  41.58 60.419 41.598 60.456 ;
    END
  END a[291]
  PIN a[292]
    DIRECTION INPUT ;
    USE SIGNAL ;
    PORT
      LAYER M3 ;
        RECT  41.652 60.419 41.67 60.456 ;
    END
  END a[292]
  PIN a[293]
    DIRECTION INPUT ;
    USE SIGNAL ;
    PORT
      LAYER M3 ;
        RECT  41.724 60.419 41.742 60.456 ;
    END
  END a[293]
  PIN a[294]
    DIRECTION INPUT ;
    USE SIGNAL ;
    PORT
      LAYER M3 ;
        RECT  41.796 60.419 41.814 60.456 ;
    END
  END a[294]
  PIN a[295]
    DIRECTION INPUT ;
    USE SIGNAL ;
    PORT
      LAYER M3 ;
        RECT  41.868 60.419 41.886 60.456 ;
    END
  END a[295]
  PIN a[296]
    DIRECTION INPUT ;
    USE SIGNAL ;
    PORT
      LAYER M3 ;
        RECT  41.94 60.419 41.958 60.456 ;
    END
  END a[296]
  PIN a[297]
    DIRECTION INPUT ;
    USE SIGNAL ;
    PORT
      LAYER M3 ;
        RECT  42.012 60.419 42.03 60.456 ;
    END
  END a[297]
  PIN a[298]
    DIRECTION INPUT ;
    USE SIGNAL ;
    PORT
      LAYER M3 ;
        RECT  42.084 60.419 42.102 60.456 ;
    END
  END a[298]
  PIN a[299]
    DIRECTION INPUT ;
    USE SIGNAL ;
    PORT
      LAYER M3 ;
        RECT  42.156 60.419 42.174 60.456 ;
    END
  END a[299]
  PIN a[29]
    DIRECTION INPUT ;
    USE SIGNAL ;
    PORT
      LAYER M5 ;
        RECT  30.192 60.372 30.216 60.456 ;
    END
  END a[29]
  PIN a[2]
    DIRECTION INPUT ;
    USE SIGNAL ;
    PORT
      LAYER M5 ;
        RECT  27.6 60.372 27.624 60.456 ;
    END
  END a[2]
  PIN a[300]
    DIRECTION INPUT ;
    USE SIGNAL ;
    PORT
      LAYER M3 ;
        RECT  42.228 60.419 42.246 60.456 ;
    END
  END a[300]
  PIN a[301]
    DIRECTION INPUT ;
    USE SIGNAL ;
    PORT
      LAYER M3 ;
        RECT  42.3 60.419 42.318 60.456 ;
    END
  END a[301]
  PIN a[302]
    DIRECTION INPUT ;
    USE SIGNAL ;
    PORT
      LAYER M3 ;
        RECT  42.372 60.419 42.39 60.456 ;
    END
  END a[302]
  PIN a[303]
    DIRECTION INPUT ;
    USE SIGNAL ;
    PORT
      LAYER M3 ;
        RECT  42.444 60.419 42.462 60.456 ;
    END
  END a[303]
  PIN a[304]
    DIRECTION INPUT ;
    USE SIGNAL ;
    PORT
      LAYER M3 ;
        RECT  42.516 60.419 42.534 60.456 ;
    END
  END a[304]
  PIN a[305]
    DIRECTION INPUT ;
    USE SIGNAL ;
    PORT
      LAYER M3 ;
        RECT  42.588 60.419 42.606 60.456 ;
    END
  END a[305]
  PIN a[306]
    DIRECTION INPUT ;
    USE SIGNAL ;
    PORT
      LAYER M3 ;
        RECT  42.66 60.419 42.678 60.456 ;
    END
  END a[306]
  PIN a[307]
    DIRECTION INPUT ;
    USE SIGNAL ;
    PORT
      LAYER M3 ;
        RECT  42.732 60.419 42.75 60.456 ;
    END
  END a[307]
  PIN a[308]
    DIRECTION INPUT ;
    USE SIGNAL ;
    PORT
      LAYER M3 ;
        RECT  42.804 60.419 42.822 60.456 ;
    END
  END a[308]
  PIN a[309]
    DIRECTION INPUT ;
    USE SIGNAL ;
    PORT
      LAYER M3 ;
        RECT  42.876 60.419 42.894 60.456 ;
    END
  END a[309]
  PIN a[30]
    DIRECTION INPUT ;
    USE SIGNAL ;
    PORT
      LAYER M5 ;
        RECT  30.288 60.372 30.312 60.456 ;
    END
  END a[30]
  PIN a[310]
    DIRECTION INPUT ;
    USE SIGNAL ;
    PORT
      LAYER M3 ;
        RECT  42.948 60.419 42.966 60.456 ;
    END
  END a[310]
  PIN a[311]
    DIRECTION INPUT ;
    USE SIGNAL ;
    PORT
      LAYER M3 ;
        RECT  43.02 60.419 43.038 60.456 ;
    END
  END a[311]
  PIN a[312]
    DIRECTION INPUT ;
    USE SIGNAL ;
    PORT
      LAYER M3 ;
        RECT  43.092 60.419 43.11 60.456 ;
    END
  END a[312]
  PIN a[313]
    DIRECTION INPUT ;
    USE SIGNAL ;
    PORT
      LAYER M3 ;
        RECT  43.164 60.419 43.182 60.456 ;
    END
  END a[313]
  PIN a[314]
    DIRECTION INPUT ;
    USE SIGNAL ;
    PORT
      LAYER M3 ;
        RECT  43.236 60.419 43.254 60.456 ;
    END
  END a[314]
  PIN a[315]
    DIRECTION INPUT ;
    USE SIGNAL ;
    PORT
      LAYER M3 ;
        RECT  43.308 60.419 43.326 60.456 ;
    END
  END a[315]
  PIN a[316]
    DIRECTION INPUT ;
    USE SIGNAL ;
    PORT
      LAYER M3 ;
        RECT  43.38 60.419 43.398 60.456 ;
    END
  END a[316]
  PIN a[317]
    DIRECTION INPUT ;
    USE SIGNAL ;
    PORT
      LAYER M3 ;
        RECT  43.452 60.419 43.47 60.456 ;
    END
  END a[317]
  PIN a[318]
    DIRECTION INPUT ;
    USE SIGNAL ;
    PORT
      LAYER M3 ;
        RECT  43.524 60.419 43.542 60.456 ;
    END
  END a[318]
  PIN a[319]
    DIRECTION INPUT ;
    USE SIGNAL ;
    PORT
      LAYER M3 ;
        RECT  43.596 60.419 43.614 60.456 ;
    END
  END a[319]
  PIN a[31]
    DIRECTION INPUT ;
    USE SIGNAL ;
    PORT
      LAYER M5 ;
        RECT  30.384 60.372 30.408 60.456 ;
    END
  END a[31]
  PIN a[320]
    DIRECTION INPUT ;
    USE SIGNAL ;
    PORT
      LAYER M3 ;
        RECT  60.948 60.419 60.966 60.456 ;
    END
  END a[320]
  PIN a[321]
    DIRECTION INPUT ;
    USE SIGNAL ;
    PORT
      LAYER M3 ;
        RECT  61.02 60.419 61.038 60.456 ;
    END
  END a[321]
  PIN a[322]
    DIRECTION INPUT ;
    USE SIGNAL ;
    PORT
      LAYER M3 ;
        RECT  61.092 60.419 61.11 60.456 ;
    END
  END a[322]
  PIN a[323]
    DIRECTION INPUT ;
    USE SIGNAL ;
    PORT
      LAYER M3 ;
        RECT  61.164 60.419 61.182 60.456 ;
    END
  END a[323]
  PIN a[324]
    DIRECTION INPUT ;
    USE SIGNAL ;
    PORT
      LAYER M3 ;
        RECT  61.236 60.419 61.254 60.456 ;
    END
  END a[324]
  PIN a[325]
    DIRECTION INPUT ;
    USE SIGNAL ;
    PORT
      LAYER M3 ;
        RECT  61.308 60.419 61.326 60.456 ;
    END
  END a[325]
  PIN a[326]
    DIRECTION INPUT ;
    USE SIGNAL ;
    PORT
      LAYER M3 ;
        RECT  61.38 60.419 61.398 60.456 ;
    END
  END a[326]
  PIN a[327]
    DIRECTION INPUT ;
    USE SIGNAL ;
    PORT
      LAYER M3 ;
        RECT  61.452 60.419 61.47 60.456 ;
    END
  END a[327]
  PIN a[328]
    DIRECTION INPUT ;
    USE SIGNAL ;
    PORT
      LAYER M3 ;
        RECT  61.524 60.419 61.542 60.456 ;
    END
  END a[328]
  PIN a[329]
    DIRECTION INPUT ;
    USE SIGNAL ;
    PORT
      LAYER M3 ;
        RECT  61.596 60.419 61.614 60.456 ;
    END
  END a[329]
  PIN a[32]
    DIRECTION INPUT ;
    USE SIGNAL ;
    PORT
      LAYER M3 ;
        RECT  20.052 60.419 20.07 60.456 ;
    END
  END a[32]
  PIN a[330]
    DIRECTION INPUT ;
    USE SIGNAL ;
    PORT
      LAYER M3 ;
        RECT  61.668 60.419 61.686 60.456 ;
    END
  END a[330]
  PIN a[331]
    DIRECTION INPUT ;
    USE SIGNAL ;
    PORT
      LAYER M3 ;
        RECT  61.74 60.419 61.758 60.456 ;
    END
  END a[331]
  PIN a[332]
    DIRECTION INPUT ;
    USE SIGNAL ;
    PORT
      LAYER M3 ;
        RECT  61.812 60.419 61.83 60.456 ;
    END
  END a[332]
  PIN a[333]
    DIRECTION INPUT ;
    USE SIGNAL ;
    PORT
      LAYER M3 ;
        RECT  61.884 60.419 61.902 60.456 ;
    END
  END a[333]
  PIN a[334]
    DIRECTION INPUT ;
    USE SIGNAL ;
    PORT
      LAYER M3 ;
        RECT  61.956 60.419 61.974 60.456 ;
    END
  END a[334]
  PIN a[335]
    DIRECTION INPUT ;
    USE SIGNAL ;
    PORT
      LAYER M3 ;
        RECT  62.028 60.419 62.046 60.456 ;
    END
  END a[335]
  PIN a[336]
    DIRECTION INPUT ;
    USE SIGNAL ;
    PORT
      LAYER M3 ;
        RECT  62.1 60.419 62.118 60.456 ;
    END
  END a[336]
  PIN a[337]
    DIRECTION INPUT ;
    USE SIGNAL ;
    PORT
      LAYER M3 ;
        RECT  62.172 60.419 62.19 60.456 ;
    END
  END a[337]
  PIN a[338]
    DIRECTION INPUT ;
    USE SIGNAL ;
    PORT
      LAYER M3 ;
        RECT  62.244 60.419 62.262 60.456 ;
    END
  END a[338]
  PIN a[339]
    DIRECTION INPUT ;
    USE SIGNAL ;
    PORT
      LAYER M3 ;
        RECT  62.316 60.419 62.334 60.456 ;
    END
  END a[339]
  PIN a[33]
    DIRECTION INPUT ;
    USE SIGNAL ;
    PORT
      LAYER M3 ;
        RECT  20.124 60.419 20.142 60.456 ;
    END
  END a[33]
  PIN a[340]
    DIRECTION INPUT ;
    USE SIGNAL ;
    PORT
      LAYER M3 ;
        RECT  62.388 60.419 62.406 60.456 ;
    END
  END a[340]
  PIN a[341]
    DIRECTION INPUT ;
    USE SIGNAL ;
    PORT
      LAYER M3 ;
        RECT  62.46 60.419 62.478 60.456 ;
    END
  END a[341]
  PIN a[342]
    DIRECTION INPUT ;
    USE SIGNAL ;
    PORT
      LAYER M3 ;
        RECT  62.532 60.419 62.55 60.456 ;
    END
  END a[342]
  PIN a[343]
    DIRECTION INPUT ;
    USE SIGNAL ;
    PORT
      LAYER M3 ;
        RECT  62.604 60.419 62.622 60.456 ;
    END
  END a[343]
  PIN a[344]
    DIRECTION INPUT ;
    USE SIGNAL ;
    PORT
      LAYER M3 ;
        RECT  62.676 60.419 62.694 60.456 ;
    END
  END a[344]
  PIN a[345]
    DIRECTION INPUT ;
    USE SIGNAL ;
    PORT
      LAYER M3 ;
        RECT  62.748 60.419 62.766 60.456 ;
    END
  END a[345]
  PIN a[346]
    DIRECTION INPUT ;
    USE SIGNAL ;
    PORT
      LAYER M3 ;
        RECT  62.82 60.419 62.838 60.456 ;
    END
  END a[346]
  PIN a[347]
    DIRECTION INPUT ;
    USE SIGNAL ;
    PORT
      LAYER M3 ;
        RECT  62.892 60.419 62.91 60.456 ;
    END
  END a[347]
  PIN a[348]
    DIRECTION INPUT ;
    USE SIGNAL ;
    PORT
      LAYER M3 ;
        RECT  62.964 60.419 62.982 60.456 ;
    END
  END a[348]
  PIN a[349]
    DIRECTION INPUT ;
    USE SIGNAL ;
    PORT
      LAYER M3 ;
        RECT  63.036 60.419 63.054 60.456 ;
    END
  END a[349]
  PIN a[34]
    DIRECTION INPUT ;
    USE SIGNAL ;
    PORT
      LAYER M3 ;
        RECT  20.196 60.419 20.214 60.456 ;
    END
  END a[34]
  PIN a[350]
    DIRECTION INPUT ;
    USE SIGNAL ;
    PORT
      LAYER M3 ;
        RECT  63.108 60.419 63.126 60.456 ;
    END
  END a[350]
  PIN a[351]
    DIRECTION INPUT ;
    USE SIGNAL ;
    PORT
      LAYER M3 ;
        RECT  63.18 60.419 63.198 60.456 ;
    END
  END a[351]
  PIN a[352]
    DIRECTION INPUT ;
    USE SIGNAL ;
    PORT
      LAYER M3 ;
        RECT  65.556 60.419 65.574 60.456 ;
    END
  END a[352]
  PIN a[353]
    DIRECTION INPUT ;
    USE SIGNAL ;
    PORT
      LAYER M3 ;
        RECT  65.628 60.419 65.646 60.456 ;
    END
  END a[353]
  PIN a[354]
    DIRECTION INPUT ;
    USE SIGNAL ;
    PORT
      LAYER M3 ;
        RECT  65.7 60.419 65.718 60.456 ;
    END
  END a[354]
  PIN a[355]
    DIRECTION INPUT ;
    USE SIGNAL ;
    PORT
      LAYER M3 ;
        RECT  65.772 60.419 65.79 60.456 ;
    END
  END a[355]
  PIN a[356]
    DIRECTION INPUT ;
    USE SIGNAL ;
    PORT
      LAYER M3 ;
        RECT  65.844 60.419 65.862 60.456 ;
    END
  END a[356]
  PIN a[357]
    DIRECTION INPUT ;
    USE SIGNAL ;
    PORT
      LAYER M3 ;
        RECT  65.916 60.419 65.934 60.456 ;
    END
  END a[357]
  PIN a[358]
    DIRECTION INPUT ;
    USE SIGNAL ;
    PORT
      LAYER M3 ;
        RECT  65.988 60.419 66.006 60.456 ;
    END
  END a[358]
  PIN a[359]
    DIRECTION INPUT ;
    USE SIGNAL ;
    PORT
      LAYER M3 ;
        RECT  66.06 60.419 66.078 60.456 ;
    END
  END a[359]
  PIN a[35]
    DIRECTION INPUT ;
    USE SIGNAL ;
    PORT
      LAYER M3 ;
        RECT  20.268 60.419 20.286 60.456 ;
    END
  END a[35]
  PIN a[360]
    DIRECTION INPUT ;
    USE SIGNAL ;
    PORT
      LAYER M3 ;
        RECT  66.132 60.419 66.15 60.456 ;
    END
  END a[360]
  PIN a[361]
    DIRECTION INPUT ;
    USE SIGNAL ;
    PORT
      LAYER M3 ;
        RECT  66.204 60.419 66.222 60.456 ;
    END
  END a[361]
  PIN a[362]
    DIRECTION INPUT ;
    USE SIGNAL ;
    PORT
      LAYER M3 ;
        RECT  66.276 60.419 66.294 60.456 ;
    END
  END a[362]
  PIN a[363]
    DIRECTION INPUT ;
    USE SIGNAL ;
    PORT
      LAYER M3 ;
        RECT  66.348 60.419 66.366 60.456 ;
    END
  END a[363]
  PIN a[364]
    DIRECTION INPUT ;
    USE SIGNAL ;
    PORT
      LAYER M3 ;
        RECT  66.42 60.419 66.438 60.456 ;
    END
  END a[364]
  PIN a[365]
    DIRECTION INPUT ;
    USE SIGNAL ;
    PORT
      LAYER M3 ;
        RECT  66.492 60.419 66.51 60.456 ;
    END
  END a[365]
  PIN a[366]
    DIRECTION INPUT ;
    USE SIGNAL ;
    PORT
      LAYER M3 ;
        RECT  66.564 60.419 66.582 60.456 ;
    END
  END a[366]
  PIN a[367]
    DIRECTION INPUT ;
    USE SIGNAL ;
    PORT
      LAYER M3 ;
        RECT  66.636 60.419 66.654 60.456 ;
    END
  END a[367]
  PIN a[368]
    DIRECTION INPUT ;
    USE SIGNAL ;
    PORT
      LAYER M3 ;
        RECT  66.708 60.419 66.726 60.456 ;
    END
  END a[368]
  PIN a[369]
    DIRECTION INPUT ;
    USE SIGNAL ;
    PORT
      LAYER M3 ;
        RECT  66.78 60.419 66.798 60.456 ;
    END
  END a[369]
  PIN a[36]
    DIRECTION INPUT ;
    USE SIGNAL ;
    PORT
      LAYER M3 ;
        RECT  20.34 60.419 20.358 60.456 ;
    END
  END a[36]
  PIN a[370]
    DIRECTION INPUT ;
    USE SIGNAL ;
    PORT
      LAYER M3 ;
        RECT  66.852 60.419 66.87 60.456 ;
    END
  END a[370]
  PIN a[371]
    DIRECTION INPUT ;
    USE SIGNAL ;
    PORT
      LAYER M3 ;
        RECT  66.924 60.419 66.942 60.456 ;
    END
  END a[371]
  PIN a[372]
    DIRECTION INPUT ;
    USE SIGNAL ;
    PORT
      LAYER M3 ;
        RECT  66.996 60.419 67.014 60.456 ;
    END
  END a[372]
  PIN a[373]
    DIRECTION INPUT ;
    USE SIGNAL ;
    PORT
      LAYER M3 ;
        RECT  67.068 60.419 67.086 60.456 ;
    END
  END a[373]
  PIN a[374]
    DIRECTION INPUT ;
    USE SIGNAL ;
    PORT
      LAYER M3 ;
        RECT  67.14 60.419 67.158 60.456 ;
    END
  END a[374]
  PIN a[375]
    DIRECTION INPUT ;
    USE SIGNAL ;
    PORT
      LAYER M3 ;
        RECT  67.212 60.419 67.23 60.456 ;
    END
  END a[375]
  PIN a[376]
    DIRECTION INPUT ;
    USE SIGNAL ;
    PORT
      LAYER M3 ;
        RECT  67.284 60.419 67.302 60.456 ;
    END
  END a[376]
  PIN a[377]
    DIRECTION INPUT ;
    USE SIGNAL ;
    PORT
      LAYER M3 ;
        RECT  67.356 60.419 67.374 60.456 ;
    END
  END a[377]
  PIN a[378]
    DIRECTION INPUT ;
    USE SIGNAL ;
    PORT
      LAYER M3 ;
        RECT  67.428 60.419 67.446 60.456 ;
    END
  END a[378]
  PIN a[379]
    DIRECTION INPUT ;
    USE SIGNAL ;
    PORT
      LAYER M3 ;
        RECT  67.5 60.419 67.518 60.456 ;
    END
  END a[379]
  PIN a[37]
    DIRECTION INPUT ;
    USE SIGNAL ;
    PORT
      LAYER M3 ;
        RECT  20.412 60.419 20.43 60.456 ;
    END
  END a[37]
  PIN a[380]
    DIRECTION INPUT ;
    USE SIGNAL ;
    PORT
      LAYER M3 ;
        RECT  67.572 60.419 67.59 60.456 ;
    END
  END a[380]
  PIN a[381]
    DIRECTION INPUT ;
    USE SIGNAL ;
    PORT
      LAYER M3 ;
        RECT  67.644 60.419 67.662 60.456 ;
    END
  END a[381]
  PIN a[382]
    DIRECTION INPUT ;
    USE SIGNAL ;
    PORT
      LAYER M3 ;
        RECT  67.716 60.419 67.734 60.456 ;
    END
  END a[382]
  PIN a[383]
    DIRECTION INPUT ;
    USE SIGNAL ;
    PORT
      LAYER M3 ;
        RECT  67.788 60.419 67.806 60.456 ;
    END
  END a[383]
  PIN a[384]
    DIRECTION INPUT ;
    USE SIGNAL ;
    PORT
      LAYER M3 ;
        RECT  67.86 60.419 67.878 60.456 ;
    END
  END a[384]
  PIN a[385]
    DIRECTION INPUT ;
    USE SIGNAL ;
    PORT
      LAYER M3 ;
        RECT  67.932 60.419 67.95 60.456 ;
    END
  END a[385]
  PIN a[386]
    DIRECTION INPUT ;
    USE SIGNAL ;
    PORT
      LAYER M3 ;
        RECT  68.004 60.419 68.022 60.456 ;
    END
  END a[386]
  PIN a[387]
    DIRECTION INPUT ;
    USE SIGNAL ;
    PORT
      LAYER M3 ;
        RECT  68.076 60.419 68.094 60.456 ;
    END
  END a[387]
  PIN a[388]
    DIRECTION INPUT ;
    USE SIGNAL ;
    PORT
      LAYER M3 ;
        RECT  68.148 60.419 68.166 60.456 ;
    END
  END a[388]
  PIN a[389]
    DIRECTION INPUT ;
    USE SIGNAL ;
    PORT
      LAYER M3 ;
        RECT  68.22 60.419 68.238 60.456 ;
    END
  END a[389]
  PIN a[38]
    DIRECTION INPUT ;
    USE SIGNAL ;
    PORT
      LAYER M3 ;
        RECT  20.484 60.419 20.502 60.456 ;
    END
  END a[38]
  PIN a[390]
    DIRECTION INPUT ;
    USE SIGNAL ;
    PORT
      LAYER M3 ;
        RECT  68.292 60.419 68.31 60.456 ;
    END
  END a[390]
  PIN a[391]
    DIRECTION INPUT ;
    USE SIGNAL ;
    PORT
      LAYER M3 ;
        RECT  68.364 60.419 68.382 60.456 ;
    END
  END a[391]
  PIN a[392]
    DIRECTION INPUT ;
    USE SIGNAL ;
    PORT
      LAYER M3 ;
        RECT  68.436 60.419 68.454 60.456 ;
    END
  END a[392]
  PIN a[393]
    DIRECTION INPUT ;
    USE SIGNAL ;
    PORT
      LAYER M3 ;
        RECT  68.508 60.419 68.526 60.456 ;
    END
  END a[393]
  PIN a[394]
    DIRECTION INPUT ;
    USE SIGNAL ;
    PORT
      LAYER M3 ;
        RECT  68.58 60.419 68.598 60.456 ;
    END
  END a[394]
  PIN a[395]
    DIRECTION INPUT ;
    USE SIGNAL ;
    PORT
      LAYER M3 ;
        RECT  68.652 60.419 68.67 60.456 ;
    END
  END a[395]
  PIN a[396]
    DIRECTION INPUT ;
    USE SIGNAL ;
    PORT
      LAYER M3 ;
        RECT  68.724 60.419 68.742 60.456 ;
    END
  END a[396]
  PIN a[397]
    DIRECTION INPUT ;
    USE SIGNAL ;
    PORT
      LAYER M3 ;
        RECT  68.796 60.419 68.814 60.456 ;
    END
  END a[397]
  PIN a[398]
    DIRECTION INPUT ;
    USE SIGNAL ;
    PORT
      LAYER M3 ;
        RECT  68.868 60.419 68.886 60.456 ;
    END
  END a[398]
  PIN a[399]
    DIRECTION INPUT ;
    USE SIGNAL ;
    PORT
      LAYER M3 ;
        RECT  68.94 60.419 68.958 60.456 ;
    END
  END a[399]
  PIN a[39]
    DIRECTION INPUT ;
    USE SIGNAL ;
    PORT
      LAYER M3 ;
        RECT  20.556 60.419 20.574 60.456 ;
    END
  END a[39]
  PIN a[3]
    DIRECTION INPUT ;
    USE SIGNAL ;
    PORT
      LAYER M5 ;
        RECT  27.696 60.372 27.72 60.456 ;
    END
  END a[3]
  PIN a[400]
    DIRECTION INPUT ;
    USE SIGNAL ;
    PORT
      LAYER M3 ;
        RECT  69.012 60.419 69.03 60.456 ;
    END
  END a[400]
  PIN a[401]
    DIRECTION INPUT ;
    USE SIGNAL ;
    PORT
      LAYER M3 ;
        RECT  69.084 60.419 69.102 60.456 ;
    END
  END a[401]
  PIN a[402]
    DIRECTION INPUT ;
    USE SIGNAL ;
    PORT
      LAYER M3 ;
        RECT  69.156 60.419 69.174 60.456 ;
    END
  END a[402]
  PIN a[403]
    DIRECTION INPUT ;
    USE SIGNAL ;
    PORT
      LAYER M3 ;
        RECT  69.228 60.419 69.246 60.456 ;
    END
  END a[403]
  PIN a[404]
    DIRECTION INPUT ;
    USE SIGNAL ;
    PORT
      LAYER M3 ;
        RECT  69.3 60.419 69.318 60.456 ;
    END
  END a[404]
  PIN a[405]
    DIRECTION INPUT ;
    USE SIGNAL ;
    PORT
      LAYER M3 ;
        RECT  69.372 60.419 69.39 60.456 ;
    END
  END a[405]
  PIN a[406]
    DIRECTION INPUT ;
    USE SIGNAL ;
    PORT
      LAYER M3 ;
        RECT  69.444 60.419 69.462 60.456 ;
    END
  END a[406]
  PIN a[407]
    DIRECTION INPUT ;
    USE SIGNAL ;
    PORT
      LAYER M3 ;
        RECT  69.516 60.419 69.534 60.456 ;
    END
  END a[407]
  PIN a[408]
    DIRECTION INPUT ;
    USE SIGNAL ;
    PORT
      LAYER M3 ;
        RECT  69.588 60.419 69.606 60.456 ;
    END
  END a[408]
  PIN a[409]
    DIRECTION INPUT ;
    USE SIGNAL ;
    PORT
      LAYER M3 ;
        RECT  69.66 60.419 69.678 60.456 ;
    END
  END a[409]
  PIN a[40]
    DIRECTION INPUT ;
    USE SIGNAL ;
    PORT
      LAYER M3 ;
        RECT  20.628 60.419 20.646 60.456 ;
    END
  END a[40]
  PIN a[410]
    DIRECTION INPUT ;
    USE SIGNAL ;
    PORT
      LAYER M3 ;
        RECT  69.732 60.419 69.75 60.456 ;
    END
  END a[410]
  PIN a[411]
    DIRECTION INPUT ;
    USE SIGNAL ;
    PORT
      LAYER M3 ;
        RECT  69.804 60.419 69.822 60.456 ;
    END
  END a[411]
  PIN a[412]
    DIRECTION INPUT ;
    USE SIGNAL ;
    PORT
      LAYER M3 ;
        RECT  69.876 60.419 69.894 60.456 ;
    END
  END a[412]
  PIN a[413]
    DIRECTION INPUT ;
    USE SIGNAL ;
    PORT
      LAYER M3 ;
        RECT  69.948 60.419 69.966 60.456 ;
    END
  END a[413]
  PIN a[414]
    DIRECTION INPUT ;
    USE SIGNAL ;
    PORT
      LAYER M3 ;
        RECT  70.02 60.419 70.038 60.456 ;
    END
  END a[414]
  PIN a[415]
    DIRECTION INPUT ;
    USE SIGNAL ;
    PORT
      LAYER M3 ;
        RECT  70.092 60.419 70.11 60.456 ;
    END
  END a[415]
  PIN a[416]
    DIRECTION INPUT ;
    USE SIGNAL ;
    PORT
      LAYER M3 ;
        RECT  79.956 60.419 79.974 60.456 ;
    END
  END a[416]
  PIN a[417]
    DIRECTION INPUT ;
    USE SIGNAL ;
    PORT
      LAYER M3 ;
        RECT  80.028 60.419 80.046 60.456 ;
    END
  END a[417]
  PIN a[418]
    DIRECTION INPUT ;
    USE SIGNAL ;
    PORT
      LAYER M3 ;
        RECT  80.1 60.419 80.118 60.456 ;
    END
  END a[418]
  PIN a[419]
    DIRECTION INPUT ;
    USE SIGNAL ;
    PORT
      LAYER M3 ;
        RECT  80.172 60.419 80.19 60.456 ;
    END
  END a[419]
  PIN a[41]
    DIRECTION INPUT ;
    USE SIGNAL ;
    PORT
      LAYER M3 ;
        RECT  20.7 60.419 20.718 60.456 ;
    END
  END a[41]
  PIN a[420]
    DIRECTION INPUT ;
    USE SIGNAL ;
    PORT
      LAYER M3 ;
        RECT  80.244 60.419 80.262 60.456 ;
    END
  END a[420]
  PIN a[421]
    DIRECTION INPUT ;
    USE SIGNAL ;
    PORT
      LAYER M3 ;
        RECT  80.316 60.419 80.334 60.456 ;
    END
  END a[421]
  PIN a[422]
    DIRECTION INPUT ;
    USE SIGNAL ;
    PORT
      LAYER M3 ;
        RECT  80.388 60.419 80.406 60.456 ;
    END
  END a[422]
  PIN a[423]
    DIRECTION INPUT ;
    USE SIGNAL ;
    PORT
      LAYER M3 ;
        RECT  80.46 60.419 80.478 60.456 ;
    END
  END a[423]
  PIN a[424]
    DIRECTION INPUT ;
    USE SIGNAL ;
    PORT
      LAYER M3 ;
        RECT  80.532 60.419 80.55 60.456 ;
    END
  END a[424]
  PIN a[425]
    DIRECTION INPUT ;
    USE SIGNAL ;
    PORT
      LAYER M3 ;
        RECT  80.604 60.419 80.622 60.456 ;
    END
  END a[425]
  PIN a[426]
    DIRECTION INPUT ;
    USE SIGNAL ;
    PORT
      LAYER M3 ;
        RECT  80.676 60.419 80.694 60.456 ;
    END
  END a[426]
  PIN a[427]
    DIRECTION INPUT ;
    USE SIGNAL ;
    PORT
      LAYER M3 ;
        RECT  80.748 60.419 80.766 60.456 ;
    END
  END a[427]
  PIN a[428]
    DIRECTION INPUT ;
    USE SIGNAL ;
    PORT
      LAYER M3 ;
        RECT  80.82 60.419 80.838 60.456 ;
    END
  END a[428]
  PIN a[429]
    DIRECTION INPUT ;
    USE SIGNAL ;
    PORT
      LAYER M3 ;
        RECT  80.892 60.419 80.91 60.456 ;
    END
  END a[429]
  PIN a[42]
    DIRECTION INPUT ;
    USE SIGNAL ;
    PORT
      LAYER M3 ;
        RECT  20.772 60.419 20.79 60.456 ;
    END
  END a[42]
  PIN a[430]
    DIRECTION INPUT ;
    USE SIGNAL ;
    PORT
      LAYER M3 ;
        RECT  80.964 60.419 80.982 60.456 ;
    END
  END a[430]
  PIN a[431]
    DIRECTION INPUT ;
    USE SIGNAL ;
    PORT
      LAYER M3 ;
        RECT  81.036 60.419 81.054 60.456 ;
    END
  END a[431]
  PIN a[432]
    DIRECTION INPUT ;
    USE SIGNAL ;
    PORT
      LAYER M3 ;
        RECT  81.108 60.419 81.126 60.456 ;
    END
  END a[432]
  PIN a[433]
    DIRECTION INPUT ;
    USE SIGNAL ;
    PORT
      LAYER M3 ;
        RECT  81.18 60.419 81.198 60.456 ;
    END
  END a[433]
  PIN a[434]
    DIRECTION INPUT ;
    USE SIGNAL ;
    PORT
      LAYER M3 ;
        RECT  81.252 60.419 81.27 60.456 ;
    END
  END a[434]
  PIN a[435]
    DIRECTION INPUT ;
    USE SIGNAL ;
    PORT
      LAYER M3 ;
        RECT  81.324 60.419 81.342 60.456 ;
    END
  END a[435]
  PIN a[436]
    DIRECTION INPUT ;
    USE SIGNAL ;
    PORT
      LAYER M3 ;
        RECT  81.396 60.419 81.414 60.456 ;
    END
  END a[436]
  PIN a[437]
    DIRECTION INPUT ;
    USE SIGNAL ;
    PORT
      LAYER M3 ;
        RECT  81.468 60.419 81.486 60.456 ;
    END
  END a[437]
  PIN a[438]
    DIRECTION INPUT ;
    USE SIGNAL ;
    PORT
      LAYER M3 ;
        RECT  81.54 60.419 81.558 60.456 ;
    END
  END a[438]
  PIN a[439]
    DIRECTION INPUT ;
    USE SIGNAL ;
    PORT
      LAYER M3 ;
        RECT  81.612 60.419 81.63 60.456 ;
    END
  END a[439]
  PIN a[43]
    DIRECTION INPUT ;
    USE SIGNAL ;
    PORT
      LAYER M3 ;
        RECT  20.844 60.419 20.862 60.456 ;
    END
  END a[43]
  PIN a[440]
    DIRECTION INPUT ;
    USE SIGNAL ;
    PORT
      LAYER M3 ;
        RECT  81.684 60.419 81.702 60.456 ;
    END
  END a[440]
  PIN a[441]
    DIRECTION INPUT ;
    USE SIGNAL ;
    PORT
      LAYER M3 ;
        RECT  81.756 60.419 81.774 60.456 ;
    END
  END a[441]
  PIN a[442]
    DIRECTION INPUT ;
    USE SIGNAL ;
    PORT
      LAYER M3 ;
        RECT  81.828 60.419 81.846 60.456 ;
    END
  END a[442]
  PIN a[443]
    DIRECTION INPUT ;
    USE SIGNAL ;
    PORT
      LAYER M3 ;
        RECT  81.9 60.419 81.918 60.456 ;
    END
  END a[443]
  PIN a[444]
    DIRECTION INPUT ;
    USE SIGNAL ;
    PORT
      LAYER M3 ;
        RECT  81.972 60.419 81.99 60.456 ;
    END
  END a[444]
  PIN a[445]
    DIRECTION INPUT ;
    USE SIGNAL ;
    PORT
      LAYER M3 ;
        RECT  82.044 60.419 82.062 60.456 ;
    END
  END a[445]
  PIN a[446]
    DIRECTION INPUT ;
    USE SIGNAL ;
    PORT
      LAYER M3 ;
        RECT  82.116 60.419 82.134 60.456 ;
    END
  END a[446]
  PIN a[447]
    DIRECTION INPUT ;
    USE SIGNAL ;
    PORT
      LAYER M3 ;
        RECT  82.188 60.419 82.206 60.456 ;
    END
  END a[447]
  PIN a[448]
    DIRECTION INPUT ;
    USE SIGNAL ;
    PORT
      LAYER M5 ;
        RECT  55.824 60.372 55.848 60.456 ;
    END
  END a[448]
  PIN a[449]
    DIRECTION INPUT ;
    USE SIGNAL ;
    PORT
      LAYER M5 ;
        RECT  55.92 60.372 55.944 60.456 ;
    END
  END a[449]
  PIN a[44]
    DIRECTION INPUT ;
    USE SIGNAL ;
    PORT
      LAYER M3 ;
        RECT  20.916 60.419 20.934 60.456 ;
    END
  END a[44]
  PIN a[450]
    DIRECTION INPUT ;
    USE SIGNAL ;
    PORT
      LAYER M5 ;
        RECT  56.016 60.372 56.04 60.456 ;
    END
  END a[450]
  PIN a[451]
    DIRECTION INPUT ;
    USE SIGNAL ;
    PORT
      LAYER M5 ;
        RECT  56.112 60.372 56.136 60.456 ;
    END
  END a[451]
  PIN a[452]
    DIRECTION INPUT ;
    USE SIGNAL ;
    PORT
      LAYER M5 ;
        RECT  56.208 60.372 56.232 60.456 ;
    END
  END a[452]
  PIN a[453]
    DIRECTION INPUT ;
    USE SIGNAL ;
    PORT
      LAYER M5 ;
        RECT  56.304 60.372 56.328 60.456 ;
    END
  END a[453]
  PIN a[454]
    DIRECTION INPUT ;
    USE SIGNAL ;
    PORT
      LAYER M5 ;
        RECT  56.4 60.372 56.424 60.456 ;
    END
  END a[454]
  PIN a[455]
    DIRECTION INPUT ;
    USE SIGNAL ;
    PORT
      LAYER M5 ;
        RECT  56.496 60.372 56.52 60.456 ;
    END
  END a[455]
  PIN a[456]
    DIRECTION INPUT ;
    USE SIGNAL ;
    PORT
      LAYER M5 ;
        RECT  56.592 60.372 56.616 60.456 ;
    END
  END a[456]
  PIN a[457]
    DIRECTION INPUT ;
    USE SIGNAL ;
    PORT
      LAYER M5 ;
        RECT  56.688 60.372 56.712 60.456 ;
    END
  END a[457]
  PIN a[458]
    DIRECTION INPUT ;
    USE SIGNAL ;
    PORT
      LAYER M5 ;
        RECT  56.784 60.372 56.808 60.456 ;
    END
  END a[458]
  PIN a[459]
    DIRECTION INPUT ;
    USE SIGNAL ;
    PORT
      LAYER M5 ;
        RECT  56.88 60.372 56.904 60.456 ;
    END
  END a[459]
  PIN a[45]
    DIRECTION INPUT ;
    USE SIGNAL ;
    PORT
      LAYER M3 ;
        RECT  20.988 60.419 21.006 60.456 ;
    END
  END a[45]
  PIN a[460]
    DIRECTION INPUT ;
    USE SIGNAL ;
    PORT
      LAYER M5 ;
        RECT  56.976 60.372 57 60.456 ;
    END
  END a[460]
  PIN a[461]
    DIRECTION INPUT ;
    USE SIGNAL ;
    PORT
      LAYER M5 ;
        RECT  57.072 60.372 57.096 60.456 ;
    END
  END a[461]
  PIN a[462]
    DIRECTION INPUT ;
    USE SIGNAL ;
    PORT
      LAYER M5 ;
        RECT  57.168 60.372 57.192 60.456 ;
    END
  END a[462]
  PIN a[463]
    DIRECTION INPUT ;
    USE SIGNAL ;
    PORT
      LAYER M5 ;
        RECT  57.264 60.372 57.288 60.456 ;
    END
  END a[463]
  PIN a[464]
    DIRECTION INPUT ;
    USE SIGNAL ;
    PORT
      LAYER M5 ;
        RECT  57.36 60.372 57.384 60.456 ;
    END
  END a[464]
  PIN a[465]
    DIRECTION INPUT ;
    USE SIGNAL ;
    PORT
      LAYER M5 ;
        RECT  57.456 60.372 57.48 60.456 ;
    END
  END a[465]
  PIN a[466]
    DIRECTION INPUT ;
    USE SIGNAL ;
    PORT
      LAYER M5 ;
        RECT  57.552 60.372 57.576 60.456 ;
    END
  END a[466]
  PIN a[467]
    DIRECTION INPUT ;
    USE SIGNAL ;
    PORT
      LAYER M5 ;
        RECT  57.648 60.372 57.672 60.456 ;
    END
  END a[467]
  PIN a[468]
    DIRECTION INPUT ;
    USE SIGNAL ;
    PORT
      LAYER M5 ;
        RECT  57.744 60.372 57.768 60.456 ;
    END
  END a[468]
  PIN a[469]
    DIRECTION INPUT ;
    USE SIGNAL ;
    PORT
      LAYER M5 ;
        RECT  57.84 60.372 57.864 60.456 ;
    END
  END a[469]
  PIN a[46]
    DIRECTION INPUT ;
    USE SIGNAL ;
    PORT
      LAYER M3 ;
        RECT  21.06 60.419 21.078 60.456 ;
    END
  END a[46]
  PIN a[470]
    DIRECTION INPUT ;
    USE SIGNAL ;
    PORT
      LAYER M5 ;
        RECT  57.936 60.372 57.96 60.456 ;
    END
  END a[470]
  PIN a[471]
    DIRECTION INPUT ;
    USE SIGNAL ;
    PORT
      LAYER M5 ;
        RECT  58.032 60.372 58.056 60.456 ;
    END
  END a[471]
  PIN a[472]
    DIRECTION INPUT ;
    USE SIGNAL ;
    PORT
      LAYER M5 ;
        RECT  58.128 60.372 58.152 60.456 ;
    END
  END a[472]
  PIN a[473]
    DIRECTION INPUT ;
    USE SIGNAL ;
    PORT
      LAYER M5 ;
        RECT  58.224 60.372 58.248 60.456 ;
    END
  END a[473]
  PIN a[474]
    DIRECTION INPUT ;
    USE SIGNAL ;
    PORT
      LAYER M5 ;
        RECT  58.32 60.372 58.344 60.456 ;
    END
  END a[474]
  PIN a[475]
    DIRECTION INPUT ;
    USE SIGNAL ;
    PORT
      LAYER M5 ;
        RECT  58.416 60.372 58.44 60.456 ;
    END
  END a[475]
  PIN a[476]
    DIRECTION INPUT ;
    USE SIGNAL ;
    PORT
      LAYER M5 ;
        RECT  58.512 60.372 58.536 60.456 ;
    END
  END a[476]
  PIN a[477]
    DIRECTION INPUT ;
    USE SIGNAL ;
    PORT
      LAYER M5 ;
        RECT  58.608 60.372 58.632 60.456 ;
    END
  END a[477]
  PIN a[478]
    DIRECTION INPUT ;
    USE SIGNAL ;
    PORT
      LAYER M5 ;
        RECT  58.704 60.372 58.728 60.456 ;
    END
  END a[478]
  PIN a[479]
    DIRECTION INPUT ;
    USE SIGNAL ;
    PORT
      LAYER M5 ;
        RECT  58.8 60.372 58.824 60.456 ;
    END
  END a[479]
  PIN a[47]
    DIRECTION INPUT ;
    USE SIGNAL ;
    PORT
      LAYER M3 ;
        RECT  21.132 60.419 21.15 60.456 ;
    END
  END a[47]
  PIN a[480]
    DIRECTION INPUT ;
    USE SIGNAL ;
    PORT
      LAYER M3 ;
        RECT  63.252 60.419 63.27 60.456 ;
    END
  END a[480]
  PIN a[481]
    DIRECTION INPUT ;
    USE SIGNAL ;
    PORT
      LAYER M3 ;
        RECT  63.324 60.419 63.342 60.456 ;
    END
  END a[481]
  PIN a[482]
    DIRECTION INPUT ;
    USE SIGNAL ;
    PORT
      LAYER M3 ;
        RECT  63.396 60.419 63.414 60.456 ;
    END
  END a[482]
  PIN a[483]
    DIRECTION INPUT ;
    USE SIGNAL ;
    PORT
      LAYER M3 ;
        RECT  63.468 60.419 63.486 60.456 ;
    END
  END a[483]
  PIN a[484]
    DIRECTION INPUT ;
    USE SIGNAL ;
    PORT
      LAYER M3 ;
        RECT  63.54 60.419 63.558 60.456 ;
    END
  END a[484]
  PIN a[485]
    DIRECTION INPUT ;
    USE SIGNAL ;
    PORT
      LAYER M3 ;
        RECT  63.612 60.419 63.63 60.456 ;
    END
  END a[485]
  PIN a[486]
    DIRECTION INPUT ;
    USE SIGNAL ;
    PORT
      LAYER M3 ;
        RECT  63.684 60.419 63.702 60.456 ;
    END
  END a[486]
  PIN a[487]
    DIRECTION INPUT ;
    USE SIGNAL ;
    PORT
      LAYER M3 ;
        RECT  63.756 60.419 63.774 60.456 ;
    END
  END a[487]
  PIN a[488]
    DIRECTION INPUT ;
    USE SIGNAL ;
    PORT
      LAYER M3 ;
        RECT  63.828 60.419 63.846 60.456 ;
    END
  END a[488]
  PIN a[489]
    DIRECTION INPUT ;
    USE SIGNAL ;
    PORT
      LAYER M3 ;
        RECT  63.9 60.419 63.918 60.456 ;
    END
  END a[489]
  PIN a[48]
    DIRECTION INPUT ;
    USE SIGNAL ;
    PORT
      LAYER M3 ;
        RECT  21.204 60.419 21.222 60.456 ;
    END
  END a[48]
  PIN a[490]
    DIRECTION INPUT ;
    USE SIGNAL ;
    PORT
      LAYER M3 ;
        RECT  63.972 60.419 63.99 60.456 ;
    END
  END a[490]
  PIN a[491]
    DIRECTION INPUT ;
    USE SIGNAL ;
    PORT
      LAYER M3 ;
        RECT  64.044 60.419 64.062 60.456 ;
    END
  END a[491]
  PIN a[492]
    DIRECTION INPUT ;
    USE SIGNAL ;
    PORT
      LAYER M3 ;
        RECT  64.116 60.419 64.134 60.456 ;
    END
  END a[492]
  PIN a[493]
    DIRECTION INPUT ;
    USE SIGNAL ;
    PORT
      LAYER M3 ;
        RECT  64.188 60.419 64.206 60.456 ;
    END
  END a[493]
  PIN a[494]
    DIRECTION INPUT ;
    USE SIGNAL ;
    PORT
      LAYER M3 ;
        RECT  64.26 60.419 64.278 60.456 ;
    END
  END a[494]
  PIN a[495]
    DIRECTION INPUT ;
    USE SIGNAL ;
    PORT
      LAYER M3 ;
        RECT  64.332 60.419 64.35 60.456 ;
    END
  END a[495]
  PIN a[496]
    DIRECTION INPUT ;
    USE SIGNAL ;
    PORT
      LAYER M3 ;
        RECT  64.404 60.419 64.422 60.456 ;
    END
  END a[496]
  PIN a[497]
    DIRECTION INPUT ;
    USE SIGNAL ;
    PORT
      LAYER M3 ;
        RECT  64.476 60.419 64.494 60.456 ;
    END
  END a[497]
  PIN a[498]
    DIRECTION INPUT ;
    USE SIGNAL ;
    PORT
      LAYER M3 ;
        RECT  64.548 60.419 64.566 60.456 ;
    END
  END a[498]
  PIN a[499]
    DIRECTION INPUT ;
    USE SIGNAL ;
    PORT
      LAYER M3 ;
        RECT  64.62 60.419 64.638 60.456 ;
    END
  END a[499]
  PIN a[49]
    DIRECTION INPUT ;
    USE SIGNAL ;
    PORT
      LAYER M3 ;
        RECT  21.276 60.419 21.294 60.456 ;
    END
  END a[49]
  PIN a[4]
    DIRECTION INPUT ;
    USE SIGNAL ;
    PORT
      LAYER M5 ;
        RECT  27.792 60.372 27.816 60.456 ;
    END
  END a[4]
  PIN a[500]
    DIRECTION INPUT ;
    USE SIGNAL ;
    PORT
      LAYER M3 ;
        RECT  64.692 60.419 64.71 60.456 ;
    END
  END a[500]
  PIN a[501]
    DIRECTION INPUT ;
    USE SIGNAL ;
    PORT
      LAYER M3 ;
        RECT  64.764 60.419 64.782 60.456 ;
    END
  END a[501]
  PIN a[502]
    DIRECTION INPUT ;
    USE SIGNAL ;
    PORT
      LAYER M3 ;
        RECT  64.836 60.419 64.854 60.456 ;
    END
  END a[502]
  PIN a[503]
    DIRECTION INPUT ;
    USE SIGNAL ;
    PORT
      LAYER M3 ;
        RECT  64.908 60.419 64.926 60.456 ;
    END
  END a[503]
  PIN a[504]
    DIRECTION INPUT ;
    USE SIGNAL ;
    PORT
      LAYER M3 ;
        RECT  64.98 60.419 64.998 60.456 ;
    END
  END a[504]
  PIN a[505]
    DIRECTION INPUT ;
    USE SIGNAL ;
    PORT
      LAYER M3 ;
        RECT  65.052 60.419 65.07 60.456 ;
    END
  END a[505]
  PIN a[506]
    DIRECTION INPUT ;
    USE SIGNAL ;
    PORT
      LAYER M3 ;
        RECT  65.124 60.419 65.142 60.456 ;
    END
  END a[506]
  PIN a[507]
    DIRECTION INPUT ;
    USE SIGNAL ;
    PORT
      LAYER M3 ;
        RECT  65.196 60.419 65.214 60.456 ;
    END
  END a[507]
  PIN a[508]
    DIRECTION INPUT ;
    USE SIGNAL ;
    PORT
      LAYER M3 ;
        RECT  65.268 60.419 65.286 60.456 ;
    END
  END a[508]
  PIN a[509]
    DIRECTION INPUT ;
    USE SIGNAL ;
    PORT
      LAYER M3 ;
        RECT  65.34 60.419 65.358 60.456 ;
    END
  END a[509]
  PIN a[50]
    DIRECTION INPUT ;
    USE SIGNAL ;
    PORT
      LAYER M3 ;
        RECT  21.348 60.419 21.366 60.456 ;
    END
  END a[50]
  PIN a[510]
    DIRECTION INPUT ;
    USE SIGNAL ;
    PORT
      LAYER M3 ;
        RECT  65.412 60.419 65.43 60.456 ;
    END
  END a[510]
  PIN a[511]
    DIRECTION INPUT ;
    USE SIGNAL ;
    PORT
      LAYER M3 ;
        RECT  65.484 60.419 65.502 60.456 ;
    END
  END a[511]
  PIN a[512]
    DIRECTION INPUT ;
    USE SIGNAL ;
    PORT
      LAYER M3 ;
        RECT  22.356 60.419 22.374 60.456 ;
    END
  END a[512]
  PIN a[513]
    DIRECTION INPUT ;
    USE SIGNAL ;
    PORT
      LAYER M3 ;
        RECT  22.428 60.419 22.446 60.456 ;
    END
  END a[513]
  PIN a[514]
    DIRECTION INPUT ;
    USE SIGNAL ;
    PORT
      LAYER M3 ;
        RECT  22.5 60.419 22.518 60.456 ;
    END
  END a[514]
  PIN a[515]
    DIRECTION INPUT ;
    USE SIGNAL ;
    PORT
      LAYER M3 ;
        RECT  22.572 60.419 22.59 60.456 ;
    END
  END a[515]
  PIN a[516]
    DIRECTION INPUT ;
    USE SIGNAL ;
    PORT
      LAYER M3 ;
        RECT  22.644 60.419 22.662 60.456 ;
    END
  END a[516]
  PIN a[517]
    DIRECTION INPUT ;
    USE SIGNAL ;
    PORT
      LAYER M3 ;
        RECT  22.716 60.419 22.734 60.456 ;
    END
  END a[517]
  PIN a[518]
    DIRECTION INPUT ;
    USE SIGNAL ;
    PORT
      LAYER M3 ;
        RECT  22.788 60.419 22.806 60.456 ;
    END
  END a[518]
  PIN a[519]
    DIRECTION INPUT ;
    USE SIGNAL ;
    PORT
      LAYER M3 ;
        RECT  22.86 60.419 22.878 60.456 ;
    END
  END a[519]
  PIN a[51]
    DIRECTION INPUT ;
    USE SIGNAL ;
    PORT
      LAYER M3 ;
        RECT  21.42 60.419 21.438 60.456 ;
    END
  END a[51]
  PIN a[520]
    DIRECTION INPUT ;
    USE SIGNAL ;
    PORT
      LAYER M3 ;
        RECT  22.932 60.419 22.95 60.456 ;
    END
  END a[520]
  PIN a[521]
    DIRECTION INPUT ;
    USE SIGNAL ;
    PORT
      LAYER M3 ;
        RECT  23.004 60.419 23.022 60.456 ;
    END
  END a[521]
  PIN a[522]
    DIRECTION INPUT ;
    USE SIGNAL ;
    PORT
      LAYER M3 ;
        RECT  23.076 60.419 23.094 60.456 ;
    END
  END a[522]
  PIN a[523]
    DIRECTION INPUT ;
    USE SIGNAL ;
    PORT
      LAYER M3 ;
        RECT  23.148 60.419 23.166 60.456 ;
    END
  END a[523]
  PIN a[524]
    DIRECTION INPUT ;
    USE SIGNAL ;
    PORT
      LAYER M3 ;
        RECT  23.22 60.419 23.238 60.456 ;
    END
  END a[524]
  PIN a[525]
    DIRECTION INPUT ;
    USE SIGNAL ;
    PORT
      LAYER M3 ;
        RECT  23.292 60.419 23.31 60.456 ;
    END
  END a[525]
  PIN a[526]
    DIRECTION INPUT ;
    USE SIGNAL ;
    PORT
      LAYER M3 ;
        RECT  23.364 60.419 23.382 60.456 ;
    END
  END a[526]
  PIN a[527]
    DIRECTION INPUT ;
    USE SIGNAL ;
    PORT
      LAYER M3 ;
        RECT  23.436 60.419 23.454 60.456 ;
    END
  END a[527]
  PIN a[528]
    DIRECTION INPUT ;
    USE SIGNAL ;
    PORT
      LAYER M3 ;
        RECT  23.508 60.419 23.526 60.456 ;
    END
  END a[528]
  PIN a[529]
    DIRECTION INPUT ;
    USE SIGNAL ;
    PORT
      LAYER M3 ;
        RECT  23.58 60.419 23.598 60.456 ;
    END
  END a[529]
  PIN a[52]
    DIRECTION INPUT ;
    USE SIGNAL ;
    PORT
      LAYER M3 ;
        RECT  21.492 60.419 21.51 60.456 ;
    END
  END a[52]
  PIN a[530]
    DIRECTION INPUT ;
    USE SIGNAL ;
    PORT
      LAYER M3 ;
        RECT  23.652 60.419 23.67 60.456 ;
    END
  END a[530]
  PIN a[531]
    DIRECTION INPUT ;
    USE SIGNAL ;
    PORT
      LAYER M3 ;
        RECT  23.724 60.419 23.742 60.456 ;
    END
  END a[531]
  PIN a[532]
    DIRECTION INPUT ;
    USE SIGNAL ;
    PORT
      LAYER M3 ;
        RECT  23.796 60.419 23.814 60.456 ;
    END
  END a[532]
  PIN a[533]
    DIRECTION INPUT ;
    USE SIGNAL ;
    PORT
      LAYER M3 ;
        RECT  23.868 60.419 23.886 60.456 ;
    END
  END a[533]
  PIN a[534]
    DIRECTION INPUT ;
    USE SIGNAL ;
    PORT
      LAYER M3 ;
        RECT  23.94 60.419 23.958 60.456 ;
    END
  END a[534]
  PIN a[535]
    DIRECTION INPUT ;
    USE SIGNAL ;
    PORT
      LAYER M3 ;
        RECT  24.012 60.419 24.03 60.456 ;
    END
  END a[535]
  PIN a[536]
    DIRECTION INPUT ;
    USE SIGNAL ;
    PORT
      LAYER M3 ;
        RECT  24.084 60.419 24.102 60.456 ;
    END
  END a[536]
  PIN a[537]
    DIRECTION INPUT ;
    USE SIGNAL ;
    PORT
      LAYER M3 ;
        RECT  24.156 60.419 24.174 60.456 ;
    END
  END a[537]
  PIN a[538]
    DIRECTION INPUT ;
    USE SIGNAL ;
    PORT
      LAYER M3 ;
        RECT  24.228 60.419 24.246 60.456 ;
    END
  END a[538]
  PIN a[539]
    DIRECTION INPUT ;
    USE SIGNAL ;
    PORT
      LAYER M3 ;
        RECT  24.3 60.419 24.318 60.456 ;
    END
  END a[539]
  PIN a[53]
    DIRECTION INPUT ;
    USE SIGNAL ;
    PORT
      LAYER M3 ;
        RECT  21.564 60.419 21.582 60.456 ;
    END
  END a[53]
  PIN a[540]
    DIRECTION INPUT ;
    USE SIGNAL ;
    PORT
      LAYER M3 ;
        RECT  24.372 60.419 24.39 60.456 ;
    END
  END a[540]
  PIN a[541]
    DIRECTION INPUT ;
    USE SIGNAL ;
    PORT
      LAYER M3 ;
        RECT  24.444 60.419 24.462 60.456 ;
    END
  END a[541]
  PIN a[542]
    DIRECTION INPUT ;
    USE SIGNAL ;
    PORT
      LAYER M3 ;
        RECT  24.516 60.419 24.534 60.456 ;
    END
  END a[542]
  PIN a[543]
    DIRECTION INPUT ;
    USE SIGNAL ;
    PORT
      LAYER M3 ;
        RECT  24.588 60.419 24.606 60.456 ;
    END
  END a[543]
  PIN a[544]
    DIRECTION INPUT ;
    USE SIGNAL ;
    PORT
      LAYER M5 ;
        RECT  17.424 60.372 17.448 60.456 ;
    END
  END a[544]
  PIN a[545]
    DIRECTION INPUT ;
    USE SIGNAL ;
    PORT
      LAYER M5 ;
        RECT  17.52 60.372 17.544 60.456 ;
    END
  END a[545]
  PIN a[546]
    DIRECTION INPUT ;
    USE SIGNAL ;
    PORT
      LAYER M5 ;
        RECT  17.616 60.372 17.64 60.456 ;
    END
  END a[546]
  PIN a[547]
    DIRECTION INPUT ;
    USE SIGNAL ;
    PORT
      LAYER M5 ;
        RECT  17.712 60.372 17.736 60.456 ;
    END
  END a[547]
  PIN a[548]
    DIRECTION INPUT ;
    USE SIGNAL ;
    PORT
      LAYER M5 ;
        RECT  17.808 60.372 17.832 60.456 ;
    END
  END a[548]
  PIN a[549]
    DIRECTION INPUT ;
    USE SIGNAL ;
    PORT
      LAYER M5 ;
        RECT  17.904 60.372 17.928 60.456 ;
    END
  END a[549]
  PIN a[54]
    DIRECTION INPUT ;
    USE SIGNAL ;
    PORT
      LAYER M3 ;
        RECT  21.636 60.419 21.654 60.456 ;
    END
  END a[54]
  PIN a[550]
    DIRECTION INPUT ;
    USE SIGNAL ;
    PORT
      LAYER M5 ;
        RECT  18 60.372 18.024 60.456 ;
    END
  END a[550]
  PIN a[551]
    DIRECTION INPUT ;
    USE SIGNAL ;
    PORT
      LAYER M5 ;
        RECT  18.096 60.372 18.12 60.456 ;
    END
  END a[551]
  PIN a[552]
    DIRECTION INPUT ;
    USE SIGNAL ;
    PORT
      LAYER M5 ;
        RECT  18.192 60.372 18.216 60.456 ;
    END
  END a[552]
  PIN a[553]
    DIRECTION INPUT ;
    USE SIGNAL ;
    PORT
      LAYER M5 ;
        RECT  18.288 60.372 18.312 60.456 ;
    END
  END a[553]
  PIN a[554]
    DIRECTION INPUT ;
    USE SIGNAL ;
    PORT
      LAYER M5 ;
        RECT  18.384 60.372 18.408 60.456 ;
    END
  END a[554]
  PIN a[555]
    DIRECTION INPUT ;
    USE SIGNAL ;
    PORT
      LAYER M5 ;
        RECT  18.48 60.372 18.504 60.456 ;
    END
  END a[555]
  PIN a[556]
    DIRECTION INPUT ;
    USE SIGNAL ;
    PORT
      LAYER M5 ;
        RECT  18.576 60.372 18.6 60.456 ;
    END
  END a[556]
  PIN a[557]
    DIRECTION INPUT ;
    USE SIGNAL ;
    PORT
      LAYER M5 ;
        RECT  18.672 60.372 18.696 60.456 ;
    END
  END a[557]
  PIN a[558]
    DIRECTION INPUT ;
    USE SIGNAL ;
    PORT
      LAYER M5 ;
        RECT  18.768 60.372 18.792 60.456 ;
    END
  END a[558]
  PIN a[559]
    DIRECTION INPUT ;
    USE SIGNAL ;
    PORT
      LAYER M5 ;
        RECT  18.864 60.372 18.888 60.456 ;
    END
  END a[559]
  PIN a[55]
    DIRECTION INPUT ;
    USE SIGNAL ;
    PORT
      LAYER M3 ;
        RECT  21.708 60.419 21.726 60.456 ;
    END
  END a[55]
  PIN a[560]
    DIRECTION INPUT ;
    USE SIGNAL ;
    PORT
      LAYER M5 ;
        RECT  18.96 60.372 18.984 60.456 ;
    END
  END a[560]
  PIN a[561]
    DIRECTION INPUT ;
    USE SIGNAL ;
    PORT
      LAYER M5 ;
        RECT  19.056 60.372 19.08 60.456 ;
    END
  END a[561]
  PIN a[562]
    DIRECTION INPUT ;
    USE SIGNAL ;
    PORT
      LAYER M5 ;
        RECT  19.152 60.372 19.176 60.456 ;
    END
  END a[562]
  PIN a[563]
    DIRECTION INPUT ;
    USE SIGNAL ;
    PORT
      LAYER M5 ;
        RECT  19.248 60.372 19.272 60.456 ;
    END
  END a[563]
  PIN a[564]
    DIRECTION INPUT ;
    USE SIGNAL ;
    PORT
      LAYER M5 ;
        RECT  19.344 60.372 19.368 60.456 ;
    END
  END a[564]
  PIN a[565]
    DIRECTION INPUT ;
    USE SIGNAL ;
    PORT
      LAYER M5 ;
        RECT  19.44 60.372 19.464 60.456 ;
    END
  END a[565]
  PIN a[566]
    DIRECTION INPUT ;
    USE SIGNAL ;
    PORT
      LAYER M5 ;
        RECT  19.536 60.372 19.56 60.456 ;
    END
  END a[566]
  PIN a[567]
    DIRECTION INPUT ;
    USE SIGNAL ;
    PORT
      LAYER M5 ;
        RECT  19.632 60.372 19.656 60.456 ;
    END
  END a[567]
  PIN a[568]
    DIRECTION INPUT ;
    USE SIGNAL ;
    PORT
      LAYER M5 ;
        RECT  19.728 60.372 19.752 60.456 ;
    END
  END a[568]
  PIN a[569]
    DIRECTION INPUT ;
    USE SIGNAL ;
    PORT
      LAYER M5 ;
        RECT  19.824 60.372 19.848 60.456 ;
    END
  END a[569]
  PIN a[56]
    DIRECTION INPUT ;
    USE SIGNAL ;
    PORT
      LAYER M3 ;
        RECT  21.78 60.419 21.798 60.456 ;
    END
  END a[56]
  PIN a[570]
    DIRECTION INPUT ;
    USE SIGNAL ;
    PORT
      LAYER M5 ;
        RECT  19.92 60.372 19.944 60.456 ;
    END
  END a[570]
  PIN a[571]
    DIRECTION INPUT ;
    USE SIGNAL ;
    PORT
      LAYER M5 ;
        RECT  20.016 60.372 20.04 60.456 ;
    END
  END a[571]
  PIN a[572]
    DIRECTION INPUT ;
    USE SIGNAL ;
    PORT
      LAYER M5 ;
        RECT  20.112 60.372 20.136 60.456 ;
    END
  END a[572]
  PIN a[573]
    DIRECTION INPUT ;
    USE SIGNAL ;
    PORT
      LAYER M5 ;
        RECT  20.208 60.372 20.232 60.456 ;
    END
  END a[573]
  PIN a[574]
    DIRECTION INPUT ;
    USE SIGNAL ;
    PORT
      LAYER M5 ;
        RECT  20.304 60.372 20.328 60.456 ;
    END
  END a[574]
  PIN a[575]
    DIRECTION INPUT ;
    USE SIGNAL ;
    PORT
      LAYER M5 ;
        RECT  20.4 60.372 20.424 60.456 ;
    END
  END a[575]
  PIN a[576]
    DIRECTION INPUT ;
    USE SIGNAL ;
    PORT
      LAYER M5 ;
        RECT  12.048 60.372 12.072 60.456 ;
    END
  END a[576]
  PIN a[577]
    DIRECTION INPUT ;
    USE SIGNAL ;
    PORT
      LAYER M5 ;
        RECT  12.144 60.372 12.168 60.456 ;
    END
  END a[577]
  PIN a[578]
    DIRECTION INPUT ;
    USE SIGNAL ;
    PORT
      LAYER M5 ;
        RECT  12.24 60.372 12.264 60.456 ;
    END
  END a[578]
  PIN a[579]
    DIRECTION INPUT ;
    USE SIGNAL ;
    PORT
      LAYER M5 ;
        RECT  12.336 60.372 12.36 60.456 ;
    END
  END a[579]
  PIN a[57]
    DIRECTION INPUT ;
    USE SIGNAL ;
    PORT
      LAYER M3 ;
        RECT  21.852 60.419 21.87 60.456 ;
    END
  END a[57]
  PIN a[580]
    DIRECTION INPUT ;
    USE SIGNAL ;
    PORT
      LAYER M5 ;
        RECT  12.432 60.372 12.456 60.456 ;
    END
  END a[580]
  PIN a[581]
    DIRECTION INPUT ;
    USE SIGNAL ;
    PORT
      LAYER M5 ;
        RECT  12.528 60.372 12.552 60.456 ;
    END
  END a[581]
  PIN a[582]
    DIRECTION INPUT ;
    USE SIGNAL ;
    PORT
      LAYER M5 ;
        RECT  12.624 60.372 12.648 60.456 ;
    END
  END a[582]
  PIN a[583]
    DIRECTION INPUT ;
    USE SIGNAL ;
    PORT
      LAYER M5 ;
        RECT  12.72 60.372 12.744 60.456 ;
    END
  END a[583]
  PIN a[584]
    DIRECTION INPUT ;
    USE SIGNAL ;
    PORT
      LAYER M5 ;
        RECT  12.816 60.372 12.84 60.456 ;
    END
  END a[584]
  PIN a[585]
    DIRECTION INPUT ;
    USE SIGNAL ;
    PORT
      LAYER M5 ;
        RECT  12.912 60.372 12.936 60.456 ;
    END
  END a[585]
  PIN a[586]
    DIRECTION INPUT ;
    USE SIGNAL ;
    PORT
      LAYER M5 ;
        RECT  13.008 60.372 13.032 60.456 ;
    END
  END a[586]
  PIN a[587]
    DIRECTION INPUT ;
    USE SIGNAL ;
    PORT
      LAYER M5 ;
        RECT  13.104 60.372 13.128 60.456 ;
    END
  END a[587]
  PIN a[588]
    DIRECTION INPUT ;
    USE SIGNAL ;
    PORT
      LAYER M5 ;
        RECT  13.2 60.372 13.224 60.456 ;
    END
  END a[588]
  PIN a[589]
    DIRECTION INPUT ;
    USE SIGNAL ;
    PORT
      LAYER M5 ;
        RECT  13.296 60.372 13.32 60.456 ;
    END
  END a[589]
  PIN a[58]
    DIRECTION INPUT ;
    USE SIGNAL ;
    PORT
      LAYER M3 ;
        RECT  21.924 60.419 21.942 60.456 ;
    END
  END a[58]
  PIN a[590]
    DIRECTION INPUT ;
    USE SIGNAL ;
    PORT
      LAYER M5 ;
        RECT  13.392 60.372 13.416 60.456 ;
    END
  END a[590]
  PIN a[591]
    DIRECTION INPUT ;
    USE SIGNAL ;
    PORT
      LAYER M5 ;
        RECT  13.488 60.372 13.512 60.456 ;
    END
  END a[591]
  PIN a[592]
    DIRECTION INPUT ;
    USE SIGNAL ;
    PORT
      LAYER M5 ;
        RECT  13.584 60.372 13.608 60.456 ;
    END
  END a[592]
  PIN a[593]
    DIRECTION INPUT ;
    USE SIGNAL ;
    PORT
      LAYER M5 ;
        RECT  13.68 60.372 13.704 60.456 ;
    END
  END a[593]
  PIN a[594]
    DIRECTION INPUT ;
    USE SIGNAL ;
    PORT
      LAYER M5 ;
        RECT  13.776 60.372 13.8 60.456 ;
    END
  END a[594]
  PIN a[595]
    DIRECTION INPUT ;
    USE SIGNAL ;
    PORT
      LAYER M5 ;
        RECT  13.872 60.372 13.896 60.456 ;
    END
  END a[595]
  PIN a[596]
    DIRECTION INPUT ;
    USE SIGNAL ;
    PORT
      LAYER M5 ;
        RECT  13.968 60.372 13.992 60.456 ;
    END
  END a[596]
  PIN a[597]
    DIRECTION INPUT ;
    USE SIGNAL ;
    PORT
      LAYER M5 ;
        RECT  14.064 60.372 14.088 60.456 ;
    END
  END a[597]
  PIN a[598]
    DIRECTION INPUT ;
    USE SIGNAL ;
    PORT
      LAYER M5 ;
        RECT  14.16 60.372 14.184 60.456 ;
    END
  END a[598]
  PIN a[599]
    DIRECTION INPUT ;
    USE SIGNAL ;
    PORT
      LAYER M5 ;
        RECT  14.256 60.372 14.28 60.456 ;
    END
  END a[599]
  PIN a[59]
    DIRECTION INPUT ;
    USE SIGNAL ;
    PORT
      LAYER M3 ;
        RECT  21.996 60.419 22.014 60.456 ;
    END
  END a[59]
  PIN a[5]
    DIRECTION INPUT ;
    USE SIGNAL ;
    PORT
      LAYER M5 ;
        RECT  27.888 60.372 27.912 60.456 ;
    END
  END a[5]
  PIN a[60]
    DIRECTION INPUT ;
    USE SIGNAL ;
    PORT
      LAYER M3 ;
        RECT  22.068 60.419 22.086 60.456 ;
    END
  END a[60]
  PIN a[61]
    DIRECTION INPUT ;
    USE SIGNAL ;
    PORT
      LAYER M3 ;
        RECT  22.14 60.419 22.158 60.456 ;
    END
  END a[61]
  PIN a[62]
    DIRECTION INPUT ;
    USE SIGNAL ;
    PORT
      LAYER M3 ;
        RECT  22.212 60.419 22.23 60.456 ;
    END
  END a[62]
  PIN a[63]
    DIRECTION INPUT ;
    USE SIGNAL ;
    PORT
      LAYER M3 ;
        RECT  22.284 60.419 22.302 60.456 ;
    END
  END a[63]
  PIN a[64]
    DIRECTION INPUT ;
    USE SIGNAL ;
    PORT
      LAYER M3 ;
        RECT  36.756 60.419 36.774 60.456 ;
    END
  END a[64]
  PIN a[65]
    DIRECTION INPUT ;
    USE SIGNAL ;
    PORT
      LAYER M3 ;
        RECT  36.828 60.419 36.846 60.456 ;
    END
  END a[65]
  PIN a[66]
    DIRECTION INPUT ;
    USE SIGNAL ;
    PORT
      LAYER M3 ;
        RECT  36.9 60.419 36.918 60.456 ;
    END
  END a[66]
  PIN a[67]
    DIRECTION INPUT ;
    USE SIGNAL ;
    PORT
      LAYER M3 ;
        RECT  36.972 60.419 36.99 60.456 ;
    END
  END a[67]
  PIN a[68]
    DIRECTION INPUT ;
    USE SIGNAL ;
    PORT
      LAYER M3 ;
        RECT  37.044 60.419 37.062 60.456 ;
    END
  END a[68]
  PIN a[69]
    DIRECTION INPUT ;
    USE SIGNAL ;
    PORT
      LAYER M3 ;
        RECT  37.116 60.419 37.134 60.456 ;
    END
  END a[69]
  PIN a[6]
    DIRECTION INPUT ;
    USE SIGNAL ;
    PORT
      LAYER M5 ;
        RECT  27.984 60.372 28.008 60.456 ;
    END
  END a[6]
  PIN a[70]
    DIRECTION INPUT ;
    USE SIGNAL ;
    PORT
      LAYER M3 ;
        RECT  37.188 60.419 37.206 60.456 ;
    END
  END a[70]
  PIN a[71]
    DIRECTION INPUT ;
    USE SIGNAL ;
    PORT
      LAYER M3 ;
        RECT  37.26 60.419 37.278 60.456 ;
    END
  END a[71]
  PIN a[72]
    DIRECTION INPUT ;
    USE SIGNAL ;
    PORT
      LAYER M3 ;
        RECT  37.332 60.419 37.35 60.456 ;
    END
  END a[72]
  PIN a[73]
    DIRECTION INPUT ;
    USE SIGNAL ;
    PORT
      LAYER M3 ;
        RECT  37.404 60.419 37.422 60.456 ;
    END
  END a[73]
  PIN a[74]
    DIRECTION INPUT ;
    USE SIGNAL ;
    PORT
      LAYER M3 ;
        RECT  37.476 60.419 37.494 60.456 ;
    END
  END a[74]
  PIN a[75]
    DIRECTION INPUT ;
    USE SIGNAL ;
    PORT
      LAYER M3 ;
        RECT  37.548 60.419 37.566 60.456 ;
    END
  END a[75]
  PIN a[76]
    DIRECTION INPUT ;
    USE SIGNAL ;
    PORT
      LAYER M3 ;
        RECT  37.62 60.419 37.638 60.456 ;
    END
  END a[76]
  PIN a[77]
    DIRECTION INPUT ;
    USE SIGNAL ;
    PORT
      LAYER M3 ;
        RECT  37.692 60.419 37.71 60.456 ;
    END
  END a[77]
  PIN a[78]
    DIRECTION INPUT ;
    USE SIGNAL ;
    PORT
      LAYER M3 ;
        RECT  37.764 60.419 37.782 60.456 ;
    END
  END a[78]
  PIN a[79]
    DIRECTION INPUT ;
    USE SIGNAL ;
    PORT
      LAYER M3 ;
        RECT  37.836 60.419 37.854 60.456 ;
    END
  END a[79]
  PIN a[7]
    DIRECTION INPUT ;
    USE SIGNAL ;
    PORT
      LAYER M5 ;
        RECT  28.08 60.372 28.104 60.456 ;
    END
  END a[7]
  PIN a[80]
    DIRECTION INPUT ;
    USE SIGNAL ;
    PORT
      LAYER M3 ;
        RECT  37.908 60.419 37.926 60.456 ;
    END
  END a[80]
  PIN a[81]
    DIRECTION INPUT ;
    USE SIGNAL ;
    PORT
      LAYER M3 ;
        RECT  37.98 60.419 37.998 60.456 ;
    END
  END a[81]
  PIN a[82]
    DIRECTION INPUT ;
    USE SIGNAL ;
    PORT
      LAYER M3 ;
        RECT  38.052 60.419 38.07 60.456 ;
    END
  END a[82]
  PIN a[83]
    DIRECTION INPUT ;
    USE SIGNAL ;
    PORT
      LAYER M3 ;
        RECT  38.124 60.419 38.142 60.456 ;
    END
  END a[83]
  PIN a[84]
    DIRECTION INPUT ;
    USE SIGNAL ;
    PORT
      LAYER M3 ;
        RECT  38.196 60.419 38.214 60.456 ;
    END
  END a[84]
  PIN a[85]
    DIRECTION INPUT ;
    USE SIGNAL ;
    PORT
      LAYER M3 ;
        RECT  38.268 60.419 38.286 60.456 ;
    END
  END a[85]
  PIN a[86]
    DIRECTION INPUT ;
    USE SIGNAL ;
    PORT
      LAYER M3 ;
        RECT  38.34 60.419 38.358 60.456 ;
    END
  END a[86]
  PIN a[87]
    DIRECTION INPUT ;
    USE SIGNAL ;
    PORT
      LAYER M3 ;
        RECT  38.412 60.419 38.43 60.456 ;
    END
  END a[87]
  PIN a[88]
    DIRECTION INPUT ;
    USE SIGNAL ;
    PORT
      LAYER M3 ;
        RECT  38.484 60.419 38.502 60.456 ;
    END
  END a[88]
  PIN a[89]
    DIRECTION INPUT ;
    USE SIGNAL ;
    PORT
      LAYER M3 ;
        RECT  38.556 60.419 38.574 60.456 ;
    END
  END a[89]
  PIN a[8]
    DIRECTION INPUT ;
    USE SIGNAL ;
    PORT
      LAYER M5 ;
        RECT  28.176 60.372 28.2 60.456 ;
    END
  END a[8]
  PIN a[90]
    DIRECTION INPUT ;
    USE SIGNAL ;
    PORT
      LAYER M3 ;
        RECT  38.628 60.419 38.646 60.456 ;
    END
  END a[90]
  PIN a[91]
    DIRECTION INPUT ;
    USE SIGNAL ;
    PORT
      LAYER M3 ;
        RECT  38.7 60.419 38.718 60.456 ;
    END
  END a[91]
  PIN a[92]
    DIRECTION INPUT ;
    USE SIGNAL ;
    PORT
      LAYER M3 ;
        RECT  38.772 60.419 38.79 60.456 ;
    END
  END a[92]
  PIN a[93]
    DIRECTION INPUT ;
    USE SIGNAL ;
    PORT
      LAYER M3 ;
        RECT  38.844 60.419 38.862 60.456 ;
    END
  END a[93]
  PIN a[94]
    DIRECTION INPUT ;
    USE SIGNAL ;
    PORT
      LAYER M3 ;
        RECT  38.916 60.419 38.934 60.456 ;
    END
  END a[94]
  PIN a[95]
    DIRECTION INPUT ;
    USE SIGNAL ;
    PORT
      LAYER M3 ;
        RECT  38.988 60.419 39.006 60.456 ;
    END
  END a[95]
  PIN a[96]
    DIRECTION INPUT ;
    USE SIGNAL ;
    PORT
      LAYER M5 ;
        RECT  75.024 60.372 75.048 60.456 ;
    END
  END a[96]
  PIN a[97]
    DIRECTION INPUT ;
    USE SIGNAL ;
    PORT
      LAYER M5 ;
        RECT  75.12 60.372 75.144 60.456 ;
    END
  END a[97]
  PIN a[98]
    DIRECTION INPUT ;
    USE SIGNAL ;
    PORT
      LAYER M5 ;
        RECT  75.216 60.372 75.24 60.456 ;
    END
  END a[98]
  PIN a[99]
    DIRECTION INPUT ;
    USE SIGNAL ;
    PORT
      LAYER M5 ;
        RECT  75.312 60.372 75.336 60.456 ;
    END
  END a[99]
  PIN a[9]
    DIRECTION INPUT ;
    USE SIGNAL ;
    PORT
      LAYER M5 ;
        RECT  28.272 60.372 28.296 60.456 ;
    END
  END a[9]
  PIN b[0]
    DIRECTION OUTPUT ;
    USE SIGNAL ;
    PORT
      LAYER M5 ;
        RECT  32.208 0 32.232 0.084 ;
    END
  END b[0]
  PIN b[100]
    DIRECTION OUTPUT ;
    USE SIGNAL ;
    PORT
      LAYER M3 ;
        RECT  79.74 0 79.758 0.037 ;
    END
  END b[100]
  PIN b[101]
    DIRECTION OUTPUT ;
    USE SIGNAL ;
    PORT
      LAYER M3 ;
        RECT  79.812 0 79.83 0.037 ;
    END
  END b[101]
  PIN b[102]
    DIRECTION OUTPUT ;
    USE SIGNAL ;
    PORT
      LAYER M3 ;
        RECT  79.884 0 79.902 0.037 ;
    END
  END b[102]
  PIN b[103]
    DIRECTION OUTPUT ;
    USE SIGNAL ;
    PORT
      LAYER M3 ;
        RECT  79.956 0 79.974 0.037 ;
    END
  END b[103]
  PIN b[104]
    DIRECTION OUTPUT ;
    USE SIGNAL ;
    PORT
      LAYER M3 ;
        RECT  80.028 0 80.046 0.037 ;
    END
  END b[104]
  PIN b[105]
    DIRECTION OUTPUT ;
    USE SIGNAL ;
    PORT
      LAYER M3 ;
        RECT  80.1 0 80.118 0.037 ;
    END
  END b[105]
  PIN b[106]
    DIRECTION OUTPUT ;
    USE SIGNAL ;
    PORT
      LAYER M3 ;
        RECT  80.172 0 80.19 0.037 ;
    END
  END b[106]
  PIN b[107]
    DIRECTION OUTPUT ;
    USE SIGNAL ;
    PORT
      LAYER M3 ;
        RECT  80.244 0 80.262 0.037 ;
    END
  END b[107]
  PIN b[108]
    DIRECTION OUTPUT ;
    USE SIGNAL ;
    PORT
      LAYER M3 ;
        RECT  80.316 0 80.334 0.037 ;
    END
  END b[108]
  PIN b[109]
    DIRECTION OUTPUT ;
    USE SIGNAL ;
    PORT
      LAYER M3 ;
        RECT  80.388 0 80.406 0.037 ;
    END
  END b[109]
  PIN b[10]
    DIRECTION OUTPUT ;
    USE SIGNAL ;
    PORT
      LAYER M5 ;
        RECT  33.168 0 33.192 0.084 ;
    END
  END b[10]
  PIN b[110]
    DIRECTION OUTPUT ;
    USE SIGNAL ;
    PORT
      LAYER M3 ;
        RECT  80.46 0 80.478 0.037 ;
    END
  END b[110]
  PIN b[111]
    DIRECTION OUTPUT ;
    USE SIGNAL ;
    PORT
      LAYER M3 ;
        RECT  80.532 0 80.55 0.037 ;
    END
  END b[111]
  PIN b[112]
    DIRECTION OUTPUT ;
    USE SIGNAL ;
    PORT
      LAYER M3 ;
        RECT  80.604 0 80.622 0.037 ;
    END
  END b[112]
  PIN b[113]
    DIRECTION OUTPUT ;
    USE SIGNAL ;
    PORT
      LAYER M3 ;
        RECT  80.676 0 80.694 0.037 ;
    END
  END b[113]
  PIN b[114]
    DIRECTION OUTPUT ;
    USE SIGNAL ;
    PORT
      LAYER M3 ;
        RECT  80.748 0 80.766 0.037 ;
    END
  END b[114]
  PIN b[115]
    DIRECTION OUTPUT ;
    USE SIGNAL ;
    PORT
      LAYER M3 ;
        RECT  80.82 0 80.838 0.037 ;
    END
  END b[115]
  PIN b[116]
    DIRECTION OUTPUT ;
    USE SIGNAL ;
    PORT
      LAYER M3 ;
        RECT  80.892 0 80.91 0.037 ;
    END
  END b[116]
  PIN b[117]
    DIRECTION OUTPUT ;
    USE SIGNAL ;
    PORT
      LAYER M3 ;
        RECT  80.964 0 80.982 0.037 ;
    END
  END b[117]
  PIN b[118]
    DIRECTION OUTPUT ;
    USE SIGNAL ;
    PORT
      LAYER M3 ;
        RECT  81.036 0 81.054 0.037 ;
    END
  END b[118]
  PIN b[119]
    DIRECTION OUTPUT ;
    USE SIGNAL ;
    PORT
      LAYER M3 ;
        RECT  81.108 0 81.126 0.037 ;
    END
  END b[119]
  PIN b[11]
    DIRECTION OUTPUT ;
    USE SIGNAL ;
    PORT
      LAYER M5 ;
        RECT  33.264 0 33.288 0.084 ;
    END
  END b[11]
  PIN b[120]
    DIRECTION OUTPUT ;
    USE SIGNAL ;
    PORT
      LAYER M3 ;
        RECT  81.18 0 81.198 0.037 ;
    END
  END b[120]
  PIN b[121]
    DIRECTION OUTPUT ;
    USE SIGNAL ;
    PORT
      LAYER M3 ;
        RECT  81.252 0 81.27 0.037 ;
    END
  END b[121]
  PIN b[122]
    DIRECTION OUTPUT ;
    USE SIGNAL ;
    PORT
      LAYER M3 ;
        RECT  81.324 0 81.342 0.037 ;
    END
  END b[122]
  PIN b[123]
    DIRECTION OUTPUT ;
    USE SIGNAL ;
    PORT
      LAYER M3 ;
        RECT  81.396 0 81.414 0.037 ;
    END
  END b[123]
  PIN b[124]
    DIRECTION OUTPUT ;
    USE SIGNAL ;
    PORT
      LAYER M3 ;
        RECT  81.468 0 81.486 0.037 ;
    END
  END b[124]
  PIN b[125]
    DIRECTION OUTPUT ;
    USE SIGNAL ;
    PORT
      LAYER M3 ;
        RECT  81.54 0 81.558 0.037 ;
    END
  END b[125]
  PIN b[126]
    DIRECTION OUTPUT ;
    USE SIGNAL ;
    PORT
      LAYER M3 ;
        RECT  81.612 0 81.63 0.037 ;
    END
  END b[126]
  PIN b[127]
    DIRECTION OUTPUT ;
    USE SIGNAL ;
    PORT
      LAYER M3 ;
        RECT  81.684 0 81.702 0.037 ;
    END
  END b[127]
  PIN b[128]
    DIRECTION OUTPUT ;
    USE SIGNAL ;
    PORT
      LAYER M3 ;
        RECT  96.156 0 96.174 0.037 ;
    END
  END b[128]
  PIN b[129]
    DIRECTION OUTPUT ;
    USE SIGNAL ;
    PORT
      LAYER M3 ;
        RECT  96.228 0 96.246 0.037 ;
    END
  END b[129]
  PIN b[12]
    DIRECTION OUTPUT ;
    USE SIGNAL ;
    PORT
      LAYER M5 ;
        RECT  33.36 0 33.384 0.084 ;
    END
  END b[12]
  PIN b[130]
    DIRECTION OUTPUT ;
    USE SIGNAL ;
    PORT
      LAYER M3 ;
        RECT  96.3 0 96.318 0.037 ;
    END
  END b[130]
  PIN b[131]
    DIRECTION OUTPUT ;
    USE SIGNAL ;
    PORT
      LAYER M3 ;
        RECT  96.372 0 96.39 0.037 ;
    END
  END b[131]
  PIN b[132]
    DIRECTION OUTPUT ;
    USE SIGNAL ;
    PORT
      LAYER M3 ;
        RECT  96.444 0 96.462 0.037 ;
    END
  END b[132]
  PIN b[133]
    DIRECTION OUTPUT ;
    USE SIGNAL ;
    PORT
      LAYER M3 ;
        RECT  96.516 0 96.534 0.037 ;
    END
  END b[133]
  PIN b[134]
    DIRECTION OUTPUT ;
    USE SIGNAL ;
    PORT
      LAYER M3 ;
        RECT  96.588 0 96.606 0.037 ;
    END
  END b[134]
  PIN b[135]
    DIRECTION OUTPUT ;
    USE SIGNAL ;
    PORT
      LAYER M3 ;
        RECT  96.66 0 96.678 0.037 ;
    END
  END b[135]
  PIN b[136]
    DIRECTION OUTPUT ;
    USE SIGNAL ;
    PORT
      LAYER M3 ;
        RECT  96.732 0 96.75 0.037 ;
    END
  END b[136]
  PIN b[137]
    DIRECTION OUTPUT ;
    USE SIGNAL ;
    PORT
      LAYER M3 ;
        RECT  96.804 0 96.822 0.037 ;
    END
  END b[137]
  PIN b[138]
    DIRECTION OUTPUT ;
    USE SIGNAL ;
    PORT
      LAYER M3 ;
        RECT  96.876 0 96.894 0.037 ;
    END
  END b[138]
  PIN b[139]
    DIRECTION OUTPUT ;
    USE SIGNAL ;
    PORT
      LAYER M3 ;
        RECT  96.948 0 96.966 0.037 ;
    END
  END b[139]
  PIN b[13]
    DIRECTION OUTPUT ;
    USE SIGNAL ;
    PORT
      LAYER M5 ;
        RECT  33.456 0 33.48 0.084 ;
    END
  END b[13]
  PIN b[140]
    DIRECTION OUTPUT ;
    USE SIGNAL ;
    PORT
      LAYER M3 ;
        RECT  97.02 0 97.038 0.037 ;
    END
  END b[140]
  PIN b[141]
    DIRECTION OUTPUT ;
    USE SIGNAL ;
    PORT
      LAYER M3 ;
        RECT  97.092 0 97.11 0.037 ;
    END
  END b[141]
  PIN b[142]
    DIRECTION OUTPUT ;
    USE SIGNAL ;
    PORT
      LAYER M3 ;
        RECT  97.164 0 97.182 0.037 ;
    END
  END b[142]
  PIN b[143]
    DIRECTION OUTPUT ;
    USE SIGNAL ;
    PORT
      LAYER M3 ;
        RECT  97.236 0 97.254 0.037 ;
    END
  END b[143]
  PIN b[144]
    DIRECTION OUTPUT ;
    USE SIGNAL ;
    PORT
      LAYER M3 ;
        RECT  97.308 0 97.326 0.037 ;
    END
  END b[144]
  PIN b[145]
    DIRECTION OUTPUT ;
    USE SIGNAL ;
    PORT
      LAYER M3 ;
        RECT  97.38 0 97.398 0.037 ;
    END
  END b[145]
  PIN b[146]
    DIRECTION OUTPUT ;
    USE SIGNAL ;
    PORT
      LAYER M3 ;
        RECT  97.452 0 97.47 0.037 ;
    END
  END b[146]
  PIN b[147]
    DIRECTION OUTPUT ;
    USE SIGNAL ;
    PORT
      LAYER M3 ;
        RECT  97.524 0 97.542 0.037 ;
    END
  END b[147]
  PIN b[148]
    DIRECTION OUTPUT ;
    USE SIGNAL ;
    PORT
      LAYER M3 ;
        RECT  97.596 0 97.614 0.037 ;
    END
  END b[148]
  PIN b[149]
    DIRECTION OUTPUT ;
    USE SIGNAL ;
    PORT
      LAYER M3 ;
        RECT  97.668 0 97.686 0.037 ;
    END
  END b[149]
  PIN b[14]
    DIRECTION OUTPUT ;
    USE SIGNAL ;
    PORT
      LAYER M5 ;
        RECT  33.552 0 33.576 0.084 ;
    END
  END b[14]
  PIN b[150]
    DIRECTION OUTPUT ;
    USE SIGNAL ;
    PORT
      LAYER M3 ;
        RECT  97.74 0 97.758 0.037 ;
    END
  END b[150]
  PIN b[151]
    DIRECTION OUTPUT ;
    USE SIGNAL ;
    PORT
      LAYER M3 ;
        RECT  97.812 0 97.83 0.037 ;
    END
  END b[151]
  PIN b[152]
    DIRECTION OUTPUT ;
    USE SIGNAL ;
    PORT
      LAYER M3 ;
        RECT  97.884 0 97.902 0.037 ;
    END
  END b[152]
  PIN b[153]
    DIRECTION OUTPUT ;
    USE SIGNAL ;
    PORT
      LAYER M3 ;
        RECT  97.956 0 97.974 0.037 ;
    END
  END b[153]
  PIN b[154]
    DIRECTION OUTPUT ;
    USE SIGNAL ;
    PORT
      LAYER M3 ;
        RECT  98.028 0 98.046 0.037 ;
    END
  END b[154]
  PIN b[155]
    DIRECTION OUTPUT ;
    USE SIGNAL ;
    PORT
      LAYER M3 ;
        RECT  98.1 0 98.118 0.037 ;
    END
  END b[155]
  PIN b[156]
    DIRECTION OUTPUT ;
    USE SIGNAL ;
    PORT
      LAYER M3 ;
        RECT  98.172 0 98.19 0.037 ;
    END
  END b[156]
  PIN b[157]
    DIRECTION OUTPUT ;
    USE SIGNAL ;
    PORT
      LAYER M3 ;
        RECT  98.244 0 98.262 0.037 ;
    END
  END b[157]
  PIN b[158]
    DIRECTION OUTPUT ;
    USE SIGNAL ;
    PORT
      LAYER M3 ;
        RECT  98.316 0 98.334 0.037 ;
    END
  END b[158]
  PIN b[159]
    DIRECTION OUTPUT ;
    USE SIGNAL ;
    PORT
      LAYER M3 ;
        RECT  98.388 0 98.406 0.037 ;
    END
  END b[159]
  PIN b[15]
    DIRECTION OUTPUT ;
    USE SIGNAL ;
    PORT
      LAYER M5 ;
        RECT  33.648 0 33.672 0.084 ;
    END
  END b[15]
  PIN b[160]
    DIRECTION OUTPUT ;
    USE SIGNAL ;
    PORT
      LAYER M3 ;
        RECT  91.548 0 91.566 0.037 ;
    END
  END b[160]
  PIN b[161]
    DIRECTION OUTPUT ;
    USE SIGNAL ;
    PORT
      LAYER M3 ;
        RECT  91.62 0 91.638 0.037 ;
    END
  END b[161]
  PIN b[162]
    DIRECTION OUTPUT ;
    USE SIGNAL ;
    PORT
      LAYER M3 ;
        RECT  91.692 0 91.71 0.037 ;
    END
  END b[162]
  PIN b[163]
    DIRECTION OUTPUT ;
    USE SIGNAL ;
    PORT
      LAYER M3 ;
        RECT  91.764 0 91.782 0.037 ;
    END
  END b[163]
  PIN b[164]
    DIRECTION OUTPUT ;
    USE SIGNAL ;
    PORT
      LAYER M3 ;
        RECT  91.836 0 91.854 0.037 ;
    END
  END b[164]
  PIN b[165]
    DIRECTION OUTPUT ;
    USE SIGNAL ;
    PORT
      LAYER M3 ;
        RECT  91.908 0 91.926 0.037 ;
    END
  END b[165]
  PIN b[166]
    DIRECTION OUTPUT ;
    USE SIGNAL ;
    PORT
      LAYER M3 ;
        RECT  91.98 0 91.998 0.037 ;
    END
  END b[166]
  PIN b[167]
    DIRECTION OUTPUT ;
    USE SIGNAL ;
    PORT
      LAYER M3 ;
        RECT  92.052 0 92.07 0.037 ;
    END
  END b[167]
  PIN b[168]
    DIRECTION OUTPUT ;
    USE SIGNAL ;
    PORT
      LAYER M3 ;
        RECT  92.124 0 92.142 0.037 ;
    END
  END b[168]
  PIN b[169]
    DIRECTION OUTPUT ;
    USE SIGNAL ;
    PORT
      LAYER M3 ;
        RECT  92.196 0 92.214 0.037 ;
    END
  END b[169]
  PIN b[16]
    DIRECTION OUTPUT ;
    USE SIGNAL ;
    PORT
      LAYER M5 ;
        RECT  33.744 0 33.768 0.084 ;
    END
  END b[16]
  PIN b[170]
    DIRECTION OUTPUT ;
    USE SIGNAL ;
    PORT
      LAYER M3 ;
        RECT  92.268 0 92.286 0.037 ;
    END
  END b[170]
  PIN b[171]
    DIRECTION OUTPUT ;
    USE SIGNAL ;
    PORT
      LAYER M3 ;
        RECT  92.34 0 92.358 0.037 ;
    END
  END b[171]
  PIN b[172]
    DIRECTION OUTPUT ;
    USE SIGNAL ;
    PORT
      LAYER M3 ;
        RECT  92.412 0 92.43 0.037 ;
    END
  END b[172]
  PIN b[173]
    DIRECTION OUTPUT ;
    USE SIGNAL ;
    PORT
      LAYER M3 ;
        RECT  92.484 0 92.502 0.037 ;
    END
  END b[173]
  PIN b[174]
    DIRECTION OUTPUT ;
    USE SIGNAL ;
    PORT
      LAYER M3 ;
        RECT  92.556 0 92.574 0.037 ;
    END
  END b[174]
  PIN b[175]
    DIRECTION OUTPUT ;
    USE SIGNAL ;
    PORT
      LAYER M3 ;
        RECT  92.628 0 92.646 0.037 ;
    END
  END b[175]
  PIN b[176]
    DIRECTION OUTPUT ;
    USE SIGNAL ;
    PORT
      LAYER M3 ;
        RECT  92.7 0 92.718 0.037 ;
    END
  END b[176]
  PIN b[177]
    DIRECTION OUTPUT ;
    USE SIGNAL ;
    PORT
      LAYER M3 ;
        RECT  92.772 0 92.79 0.037 ;
    END
  END b[177]
  PIN b[178]
    DIRECTION OUTPUT ;
    USE SIGNAL ;
    PORT
      LAYER M3 ;
        RECT  92.844 0 92.862 0.037 ;
    END
  END b[178]
  PIN b[179]
    DIRECTION OUTPUT ;
    USE SIGNAL ;
    PORT
      LAYER M3 ;
        RECT  92.916 0 92.934 0.037 ;
    END
  END b[179]
  PIN b[17]
    DIRECTION OUTPUT ;
    USE SIGNAL ;
    PORT
      LAYER M5 ;
        RECT  33.84 0 33.864 0.084 ;
    END
  END b[17]
  PIN b[180]
    DIRECTION OUTPUT ;
    USE SIGNAL ;
    PORT
      LAYER M3 ;
        RECT  92.988 0 93.006 0.037 ;
    END
  END b[180]
  PIN b[181]
    DIRECTION OUTPUT ;
    USE SIGNAL ;
    PORT
      LAYER M3 ;
        RECT  93.06 0 93.078 0.037 ;
    END
  END b[181]
  PIN b[182]
    DIRECTION OUTPUT ;
    USE SIGNAL ;
    PORT
      LAYER M3 ;
        RECT  93.132 0 93.15 0.037 ;
    END
  END b[182]
  PIN b[183]
    DIRECTION OUTPUT ;
    USE SIGNAL ;
    PORT
      LAYER M3 ;
        RECT  93.204 0 93.222 0.037 ;
    END
  END b[183]
  PIN b[184]
    DIRECTION OUTPUT ;
    USE SIGNAL ;
    PORT
      LAYER M3 ;
        RECT  93.276 0 93.294 0.037 ;
    END
  END b[184]
  PIN b[185]
    DIRECTION OUTPUT ;
    USE SIGNAL ;
    PORT
      LAYER M3 ;
        RECT  93.348 0 93.366 0.037 ;
    END
  END b[185]
  PIN b[186]
    DIRECTION OUTPUT ;
    USE SIGNAL ;
    PORT
      LAYER M3 ;
        RECT  93.42 0 93.438 0.037 ;
    END
  END b[186]
  PIN b[187]
    DIRECTION OUTPUT ;
    USE SIGNAL ;
    PORT
      LAYER M3 ;
        RECT  93.492 0 93.51 0.037 ;
    END
  END b[187]
  PIN b[188]
    DIRECTION OUTPUT ;
    USE SIGNAL ;
    PORT
      LAYER M3 ;
        RECT  93.564 0 93.582 0.037 ;
    END
  END b[188]
  PIN b[189]
    DIRECTION OUTPUT ;
    USE SIGNAL ;
    PORT
      LAYER M3 ;
        RECT  93.636 0 93.654 0.037 ;
    END
  END b[189]
  PIN b[18]
    DIRECTION OUTPUT ;
    USE SIGNAL ;
    PORT
      LAYER M5 ;
        RECT  33.936 0 33.96 0.084 ;
    END
  END b[18]
  PIN b[190]
    DIRECTION OUTPUT ;
    USE SIGNAL ;
    PORT
      LAYER M3 ;
        RECT  93.708 0 93.726 0.037 ;
    END
  END b[190]
  PIN b[191]
    DIRECTION OUTPUT ;
    USE SIGNAL ;
    PORT
      LAYER M3 ;
        RECT  93.78 0 93.798 0.037 ;
    END
  END b[191]
  PIN b[192]
    DIRECTION OUTPUT ;
    USE SIGNAL ;
    PORT
      LAYER M3 ;
        RECT  72.54 0 72.558 0.037 ;
    END
  END b[192]
  PIN b[193]
    DIRECTION OUTPUT ;
    USE SIGNAL ;
    PORT
      LAYER M3 ;
        RECT  72.612 0 72.63 0.037 ;
    END
  END b[193]
  PIN b[194]
    DIRECTION OUTPUT ;
    USE SIGNAL ;
    PORT
      LAYER M3 ;
        RECT  72.684 0 72.702 0.037 ;
    END
  END b[194]
  PIN b[195]
    DIRECTION OUTPUT ;
    USE SIGNAL ;
    PORT
      LAYER M3 ;
        RECT  72.756 0 72.774 0.037 ;
    END
  END b[195]
  PIN b[196]
    DIRECTION OUTPUT ;
    USE SIGNAL ;
    PORT
      LAYER M3 ;
        RECT  72.828 0 72.846 0.037 ;
    END
  END b[196]
  PIN b[197]
    DIRECTION OUTPUT ;
    USE SIGNAL ;
    PORT
      LAYER M3 ;
        RECT  72.9 0 72.918 0.037 ;
    END
  END b[197]
  PIN b[198]
    DIRECTION OUTPUT ;
    USE SIGNAL ;
    PORT
      LAYER M3 ;
        RECT  72.972 0 72.99 0.037 ;
    END
  END b[198]
  PIN b[199]
    DIRECTION OUTPUT ;
    USE SIGNAL ;
    PORT
      LAYER M3 ;
        RECT  73.044 0 73.062 0.037 ;
    END
  END b[199]
  PIN b[19]
    DIRECTION OUTPUT ;
    USE SIGNAL ;
    PORT
      LAYER M5 ;
        RECT  34.032 0 34.056 0.084 ;
    END
  END b[19]
  PIN b[1]
    DIRECTION OUTPUT ;
    USE SIGNAL ;
    PORT
      LAYER M5 ;
        RECT  32.304 0 32.328 0.084 ;
    END
  END b[1]
  PIN b[200]
    DIRECTION OUTPUT ;
    USE SIGNAL ;
    PORT
      LAYER M3 ;
        RECT  73.116 0 73.134 0.037 ;
    END
  END b[200]
  PIN b[201]
    DIRECTION OUTPUT ;
    USE SIGNAL ;
    PORT
      LAYER M3 ;
        RECT  73.188 0 73.206 0.037 ;
    END
  END b[201]
  PIN b[202]
    DIRECTION OUTPUT ;
    USE SIGNAL ;
    PORT
      LAYER M3 ;
        RECT  73.26 0 73.278 0.037 ;
    END
  END b[202]
  PIN b[203]
    DIRECTION OUTPUT ;
    USE SIGNAL ;
    PORT
      LAYER M3 ;
        RECT  73.332 0 73.35 0.037 ;
    END
  END b[203]
  PIN b[204]
    DIRECTION OUTPUT ;
    USE SIGNAL ;
    PORT
      LAYER M3 ;
        RECT  73.404 0 73.422 0.037 ;
    END
  END b[204]
  PIN b[205]
    DIRECTION OUTPUT ;
    USE SIGNAL ;
    PORT
      LAYER M3 ;
        RECT  73.476 0 73.494 0.037 ;
    END
  END b[205]
  PIN b[206]
    DIRECTION OUTPUT ;
    USE SIGNAL ;
    PORT
      LAYER M3 ;
        RECT  73.548 0 73.566 0.037 ;
    END
  END b[206]
  PIN b[207]
    DIRECTION OUTPUT ;
    USE SIGNAL ;
    PORT
      LAYER M3 ;
        RECT  73.62 0 73.638 0.037 ;
    END
  END b[207]
  PIN b[208]
    DIRECTION OUTPUT ;
    USE SIGNAL ;
    PORT
      LAYER M3 ;
        RECT  73.692 0 73.71 0.037 ;
    END
  END b[208]
  PIN b[209]
    DIRECTION OUTPUT ;
    USE SIGNAL ;
    PORT
      LAYER M3 ;
        RECT  73.764 0 73.782 0.037 ;
    END
  END b[209]
  PIN b[20]
    DIRECTION OUTPUT ;
    USE SIGNAL ;
    PORT
      LAYER M5 ;
        RECT  34.128 0 34.152 0.084 ;
    END
  END b[20]
  PIN b[210]
    DIRECTION OUTPUT ;
    USE SIGNAL ;
    PORT
      LAYER M3 ;
        RECT  73.836 0 73.854 0.037 ;
    END
  END b[210]
  PIN b[211]
    DIRECTION OUTPUT ;
    USE SIGNAL ;
    PORT
      LAYER M3 ;
        RECT  73.908 0 73.926 0.037 ;
    END
  END b[211]
  PIN b[212]
    DIRECTION OUTPUT ;
    USE SIGNAL ;
    PORT
      LAYER M3 ;
        RECT  73.98 0 73.998 0.037 ;
    END
  END b[212]
  PIN b[213]
    DIRECTION OUTPUT ;
    USE SIGNAL ;
    PORT
      LAYER M3 ;
        RECT  74.052 0 74.07 0.037 ;
    END
  END b[213]
  PIN b[214]
    DIRECTION OUTPUT ;
    USE SIGNAL ;
    PORT
      LAYER M3 ;
        RECT  74.124 0 74.142 0.037 ;
    END
  END b[214]
  PIN b[215]
    DIRECTION OUTPUT ;
    USE SIGNAL ;
    PORT
      LAYER M3 ;
        RECT  74.196 0 74.214 0.037 ;
    END
  END b[215]
  PIN b[216]
    DIRECTION OUTPUT ;
    USE SIGNAL ;
    PORT
      LAYER M3 ;
        RECT  74.268 0 74.286 0.037 ;
    END
  END b[216]
  PIN b[217]
    DIRECTION OUTPUT ;
    USE SIGNAL ;
    PORT
      LAYER M3 ;
        RECT  74.34 0 74.358 0.037 ;
    END
  END b[217]
  PIN b[218]
    DIRECTION OUTPUT ;
    USE SIGNAL ;
    PORT
      LAYER M3 ;
        RECT  74.412 0 74.43 0.037 ;
    END
  END b[218]
  PIN b[219]
    DIRECTION OUTPUT ;
    USE SIGNAL ;
    PORT
      LAYER M3 ;
        RECT  74.484 0 74.502 0.037 ;
    END
  END b[219]
  PIN b[21]
    DIRECTION OUTPUT ;
    USE SIGNAL ;
    PORT
      LAYER M5 ;
        RECT  34.224 0 34.248 0.084 ;
    END
  END b[21]
  PIN b[220]
    DIRECTION OUTPUT ;
    USE SIGNAL ;
    PORT
      LAYER M3 ;
        RECT  74.556 0 74.574 0.037 ;
    END
  END b[220]
  PIN b[221]
    DIRECTION OUTPUT ;
    USE SIGNAL ;
    PORT
      LAYER M3 ;
        RECT  74.628 0 74.646 0.037 ;
    END
  END b[221]
  PIN b[222]
    DIRECTION OUTPUT ;
    USE SIGNAL ;
    PORT
      LAYER M3 ;
        RECT  74.7 0 74.718 0.037 ;
    END
  END b[222]
  PIN b[223]
    DIRECTION OUTPUT ;
    USE SIGNAL ;
    PORT
      LAYER M3 ;
        RECT  74.772 0 74.79 0.037 ;
    END
  END b[223]
  PIN b[224]
    DIRECTION OUTPUT ;
    USE SIGNAL ;
    PORT
      LAYER M3 ;
        RECT  50.652 0 50.67 0.037 ;
    END
  END b[224]
  PIN b[225]
    DIRECTION OUTPUT ;
    USE SIGNAL ;
    PORT
      LAYER M3 ;
        RECT  50.724 0 50.742 0.037 ;
    END
  END b[225]
  PIN b[226]
    DIRECTION OUTPUT ;
    USE SIGNAL ;
    PORT
      LAYER M3 ;
        RECT  50.796 0 50.814 0.037 ;
    END
  END b[226]
  PIN b[227]
    DIRECTION OUTPUT ;
    USE SIGNAL ;
    PORT
      LAYER M3 ;
        RECT  50.868 0 50.886 0.037 ;
    END
  END b[227]
  PIN b[228]
    DIRECTION OUTPUT ;
    USE SIGNAL ;
    PORT
      LAYER M3 ;
        RECT  50.94 0 50.958 0.037 ;
    END
  END b[228]
  PIN b[229]
    DIRECTION OUTPUT ;
    USE SIGNAL ;
    PORT
      LAYER M3 ;
        RECT  51.012 0 51.03 0.037 ;
    END
  END b[229]
  PIN b[22]
    DIRECTION OUTPUT ;
    USE SIGNAL ;
    PORT
      LAYER M5 ;
        RECT  34.32 0 34.344 0.084 ;
    END
  END b[22]
  PIN b[230]
    DIRECTION OUTPUT ;
    USE SIGNAL ;
    PORT
      LAYER M3 ;
        RECT  51.084 0 51.102 0.037 ;
    END
  END b[230]
  PIN b[231]
    DIRECTION OUTPUT ;
    USE SIGNAL ;
    PORT
      LAYER M3 ;
        RECT  51.156 0 51.174 0.037 ;
    END
  END b[231]
  PIN b[232]
    DIRECTION OUTPUT ;
    USE SIGNAL ;
    PORT
      LAYER M3 ;
        RECT  51.228 0 51.246 0.037 ;
    END
  END b[232]
  PIN b[233]
    DIRECTION OUTPUT ;
    USE SIGNAL ;
    PORT
      LAYER M3 ;
        RECT  51.3 0 51.318 0.037 ;
    END
  END b[233]
  PIN b[234]
    DIRECTION OUTPUT ;
    USE SIGNAL ;
    PORT
      LAYER M3 ;
        RECT  51.372 0 51.39 0.037 ;
    END
  END b[234]
  PIN b[235]
    DIRECTION OUTPUT ;
    USE SIGNAL ;
    PORT
      LAYER M3 ;
        RECT  51.444 0 51.462 0.037 ;
    END
  END b[235]
  PIN b[236]
    DIRECTION OUTPUT ;
    USE SIGNAL ;
    PORT
      LAYER M3 ;
        RECT  51.516 0 51.534 0.037 ;
    END
  END b[236]
  PIN b[237]
    DIRECTION OUTPUT ;
    USE SIGNAL ;
    PORT
      LAYER M3 ;
        RECT  51.588 0 51.606 0.037 ;
    END
  END b[237]
  PIN b[238]
    DIRECTION OUTPUT ;
    USE SIGNAL ;
    PORT
      LAYER M3 ;
        RECT  51.66 0 51.678 0.037 ;
    END
  END b[238]
  PIN b[239]
    DIRECTION OUTPUT ;
    USE SIGNAL ;
    PORT
      LAYER M3 ;
        RECT  51.732 0 51.75 0.037 ;
    END
  END b[239]
  PIN b[23]
    DIRECTION OUTPUT ;
    USE SIGNAL ;
    PORT
      LAYER M5 ;
        RECT  34.416 0 34.44 0.084 ;
    END
  END b[23]
  PIN b[240]
    DIRECTION OUTPUT ;
    USE SIGNAL ;
    PORT
      LAYER M3 ;
        RECT  51.804 0 51.822 0.037 ;
    END
  END b[240]
  PIN b[241]
    DIRECTION OUTPUT ;
    USE SIGNAL ;
    PORT
      LAYER M3 ;
        RECT  51.876 0 51.894 0.037 ;
    END
  END b[241]
  PIN b[242]
    DIRECTION OUTPUT ;
    USE SIGNAL ;
    PORT
      LAYER M3 ;
        RECT  51.948 0 51.966 0.037 ;
    END
  END b[242]
  PIN b[243]
    DIRECTION OUTPUT ;
    USE SIGNAL ;
    PORT
      LAYER M3 ;
        RECT  52.02 0 52.038 0.037 ;
    END
  END b[243]
  PIN b[244]
    DIRECTION OUTPUT ;
    USE SIGNAL ;
    PORT
      LAYER M3 ;
        RECT  52.092 0 52.11 0.037 ;
    END
  END b[244]
  PIN b[245]
    DIRECTION OUTPUT ;
    USE SIGNAL ;
    PORT
      LAYER M3 ;
        RECT  52.164 0 52.182 0.037 ;
    END
  END b[245]
  PIN b[246]
    DIRECTION OUTPUT ;
    USE SIGNAL ;
    PORT
      LAYER M3 ;
        RECT  52.236 0 52.254 0.037 ;
    END
  END b[246]
  PIN b[247]
    DIRECTION OUTPUT ;
    USE SIGNAL ;
    PORT
      LAYER M3 ;
        RECT  52.308 0 52.326 0.037 ;
    END
  END b[247]
  PIN b[248]
    DIRECTION OUTPUT ;
    USE SIGNAL ;
    PORT
      LAYER M3 ;
        RECT  52.38 0 52.398 0.037 ;
    END
  END b[248]
  PIN b[249]
    DIRECTION OUTPUT ;
    USE SIGNAL ;
    PORT
      LAYER M3 ;
        RECT  52.452 0 52.47 0.037 ;
    END
  END b[249]
  PIN b[24]
    DIRECTION OUTPUT ;
    USE SIGNAL ;
    PORT
      LAYER M5 ;
        RECT  34.512 0 34.536 0.084 ;
    END
  END b[24]
  PIN b[250]
    DIRECTION OUTPUT ;
    USE SIGNAL ;
    PORT
      LAYER M3 ;
        RECT  52.524 0 52.542 0.037 ;
    END
  END b[250]
  PIN b[251]
    DIRECTION OUTPUT ;
    USE SIGNAL ;
    PORT
      LAYER M3 ;
        RECT  52.596 0 52.614 0.037 ;
    END
  END b[251]
  PIN b[252]
    DIRECTION OUTPUT ;
    USE SIGNAL ;
    PORT
      LAYER M3 ;
        RECT  52.668 0 52.686 0.037 ;
    END
  END b[252]
  PIN b[253]
    DIRECTION OUTPUT ;
    USE SIGNAL ;
    PORT
      LAYER M3 ;
        RECT  52.74 0 52.758 0.037 ;
    END
  END b[253]
  PIN b[254]
    DIRECTION OUTPUT ;
    USE SIGNAL ;
    PORT
      LAYER M3 ;
        RECT  52.812 0 52.83 0.037 ;
    END
  END b[254]
  PIN b[255]
    DIRECTION OUTPUT ;
    USE SIGNAL ;
    PORT
      LAYER M3 ;
        RECT  52.884 0 52.902 0.037 ;
    END
  END b[255]
  PIN b[256]
    DIRECTION OUTPUT ;
    USE SIGNAL ;
    PORT
      LAYER M5 ;
        RECT  29.136 0 29.16 0.084 ;
    END
  END b[256]
  PIN b[257]
    DIRECTION OUTPUT ;
    USE SIGNAL ;
    PORT
      LAYER M5 ;
        RECT  29.232 0 29.256 0.084 ;
    END
  END b[257]
  PIN b[258]
    DIRECTION OUTPUT ;
    USE SIGNAL ;
    PORT
      LAYER M5 ;
        RECT  29.328 0 29.352 0.084 ;
    END
  END b[258]
  PIN b[259]
    DIRECTION OUTPUT ;
    USE SIGNAL ;
    PORT
      LAYER M5 ;
        RECT  29.424 0 29.448 0.084 ;
    END
  END b[259]
  PIN b[25]
    DIRECTION OUTPUT ;
    USE SIGNAL ;
    PORT
      LAYER M5 ;
        RECT  34.608 0 34.632 0.084 ;
    END
  END b[25]
  PIN b[260]
    DIRECTION OUTPUT ;
    USE SIGNAL ;
    PORT
      LAYER M5 ;
        RECT  29.52 0 29.544 0.084 ;
    END
  END b[260]
  PIN b[261]
    DIRECTION OUTPUT ;
    USE SIGNAL ;
    PORT
      LAYER M5 ;
        RECT  29.616 0 29.64 0.084 ;
    END
  END b[261]
  PIN b[262]
    DIRECTION OUTPUT ;
    USE SIGNAL ;
    PORT
      LAYER M5 ;
        RECT  29.712 0 29.736 0.084 ;
    END
  END b[262]
  PIN b[263]
    DIRECTION OUTPUT ;
    USE SIGNAL ;
    PORT
      LAYER M5 ;
        RECT  29.808 0 29.832 0.084 ;
    END
  END b[263]
  PIN b[264]
    DIRECTION OUTPUT ;
    USE SIGNAL ;
    PORT
      LAYER M5 ;
        RECT  29.904 0 29.928 0.084 ;
    END
  END b[264]
  PIN b[265]
    DIRECTION OUTPUT ;
    USE SIGNAL ;
    PORT
      LAYER M5 ;
        RECT  30 0 30.024 0.084 ;
    END
  END b[265]
  PIN b[266]
    DIRECTION OUTPUT ;
    USE SIGNAL ;
    PORT
      LAYER M5 ;
        RECT  30.096 0 30.12 0.084 ;
    END
  END b[266]
  PIN b[267]
    DIRECTION OUTPUT ;
    USE SIGNAL ;
    PORT
      LAYER M5 ;
        RECT  30.192 0 30.216 0.084 ;
    END
  END b[267]
  PIN b[268]
    DIRECTION OUTPUT ;
    USE SIGNAL ;
    PORT
      LAYER M5 ;
        RECT  30.288 0 30.312 0.084 ;
    END
  END b[268]
  PIN b[269]
    DIRECTION OUTPUT ;
    USE SIGNAL ;
    PORT
      LAYER M5 ;
        RECT  30.384 0 30.408 0.084 ;
    END
  END b[269]
  PIN b[26]
    DIRECTION OUTPUT ;
    USE SIGNAL ;
    PORT
      LAYER M5 ;
        RECT  34.704 0 34.728 0.084 ;
    END
  END b[26]
  PIN b[270]
    DIRECTION OUTPUT ;
    USE SIGNAL ;
    PORT
      LAYER M5 ;
        RECT  30.48 0 30.504 0.084 ;
    END
  END b[270]
  PIN b[271]
    DIRECTION OUTPUT ;
    USE SIGNAL ;
    PORT
      LAYER M5 ;
        RECT  30.576 0 30.6 0.084 ;
    END
  END b[271]
  PIN b[272]
    DIRECTION OUTPUT ;
    USE SIGNAL ;
    PORT
      LAYER M5 ;
        RECT  30.672 0 30.696 0.084 ;
    END
  END b[272]
  PIN b[273]
    DIRECTION OUTPUT ;
    USE SIGNAL ;
    PORT
      LAYER M5 ;
        RECT  30.768 0 30.792 0.084 ;
    END
  END b[273]
  PIN b[274]
    DIRECTION OUTPUT ;
    USE SIGNAL ;
    PORT
      LAYER M5 ;
        RECT  30.864 0 30.888 0.084 ;
    END
  END b[274]
  PIN b[275]
    DIRECTION OUTPUT ;
    USE SIGNAL ;
    PORT
      LAYER M5 ;
        RECT  30.96 0 30.984 0.084 ;
    END
  END b[275]
  PIN b[276]
    DIRECTION OUTPUT ;
    USE SIGNAL ;
    PORT
      LAYER M5 ;
        RECT  31.056 0 31.08 0.084 ;
    END
  END b[276]
  PIN b[277]
    DIRECTION OUTPUT ;
    USE SIGNAL ;
    PORT
      LAYER M5 ;
        RECT  31.152 0 31.176 0.084 ;
    END
  END b[277]
  PIN b[278]
    DIRECTION OUTPUT ;
    USE SIGNAL ;
    PORT
      LAYER M5 ;
        RECT  31.248 0 31.272 0.084 ;
    END
  END b[278]
  PIN b[279]
    DIRECTION OUTPUT ;
    USE SIGNAL ;
    PORT
      LAYER M5 ;
        RECT  31.344 0 31.368 0.084 ;
    END
  END b[279]
  PIN b[27]
    DIRECTION OUTPUT ;
    USE SIGNAL ;
    PORT
      LAYER M5 ;
        RECT  34.8 0 34.824 0.084 ;
    END
  END b[27]
  PIN b[280]
    DIRECTION OUTPUT ;
    USE SIGNAL ;
    PORT
      LAYER M5 ;
        RECT  31.44 0 31.464 0.084 ;
    END
  END b[280]
  PIN b[281]
    DIRECTION OUTPUT ;
    USE SIGNAL ;
    PORT
      LAYER M5 ;
        RECT  31.536 0 31.56 0.084 ;
    END
  END b[281]
  PIN b[282]
    DIRECTION OUTPUT ;
    USE SIGNAL ;
    PORT
      LAYER M5 ;
        RECT  31.632 0 31.656 0.084 ;
    END
  END b[282]
  PIN b[283]
    DIRECTION OUTPUT ;
    USE SIGNAL ;
    PORT
      LAYER M5 ;
        RECT  31.728 0 31.752 0.084 ;
    END
  END b[283]
  PIN b[284]
    DIRECTION OUTPUT ;
    USE SIGNAL ;
    PORT
      LAYER M5 ;
        RECT  31.824 0 31.848 0.084 ;
    END
  END b[284]
  PIN b[285]
    DIRECTION OUTPUT ;
    USE SIGNAL ;
    PORT
      LAYER M5 ;
        RECT  31.92 0 31.944 0.084 ;
    END
  END b[285]
  PIN b[286]
    DIRECTION OUTPUT ;
    USE SIGNAL ;
    PORT
      LAYER M5 ;
        RECT  32.016 0 32.04 0.084 ;
    END
  END b[286]
  PIN b[287]
    DIRECTION OUTPUT ;
    USE SIGNAL ;
    PORT
      LAYER M5 ;
        RECT  32.112 0 32.136 0.084 ;
    END
  END b[287]
  PIN b[288]
    DIRECTION OUTPUT ;
    USE SIGNAL ;
    PORT
      LAYER M5 ;
        RECT  48.336 0 48.36 0.084 ;
    END
  END b[288]
  PIN b[289]
    DIRECTION OUTPUT ;
    USE SIGNAL ;
    PORT
      LAYER M5 ;
        RECT  48.432 0 48.456 0.084 ;
    END
  END b[289]
  PIN b[28]
    DIRECTION OUTPUT ;
    USE SIGNAL ;
    PORT
      LAYER M5 ;
        RECT  34.896 0 34.92 0.084 ;
    END
  END b[28]
  PIN b[290]
    DIRECTION OUTPUT ;
    USE SIGNAL ;
    PORT
      LAYER M5 ;
        RECT  48.528 0 48.552 0.084 ;
    END
  END b[290]
  PIN b[291]
    DIRECTION OUTPUT ;
    USE SIGNAL ;
    PORT
      LAYER M5 ;
        RECT  48.624 0 48.648 0.084 ;
    END
  END b[291]
  PIN b[292]
    DIRECTION OUTPUT ;
    USE SIGNAL ;
    PORT
      LAYER M5 ;
        RECT  48.72 0 48.744 0.084 ;
    END
  END b[292]
  PIN b[293]
    DIRECTION OUTPUT ;
    USE SIGNAL ;
    PORT
      LAYER M5 ;
        RECT  48.816 0 48.84 0.084 ;
    END
  END b[293]
  PIN b[294]
    DIRECTION OUTPUT ;
    USE SIGNAL ;
    PORT
      LAYER M5 ;
        RECT  48.912 0 48.936 0.084 ;
    END
  END b[294]
  PIN b[295]
    DIRECTION OUTPUT ;
    USE SIGNAL ;
    PORT
      LAYER M5 ;
        RECT  49.008 0 49.032 0.084 ;
    END
  END b[295]
  PIN b[296]
    DIRECTION OUTPUT ;
    USE SIGNAL ;
    PORT
      LAYER M5 ;
        RECT  49.104 0 49.128 0.084 ;
    END
  END b[296]
  PIN b[297]
    DIRECTION OUTPUT ;
    USE SIGNAL ;
    PORT
      LAYER M5 ;
        RECT  49.2 0 49.224 0.084 ;
    END
  END b[297]
  PIN b[298]
    DIRECTION OUTPUT ;
    USE SIGNAL ;
    PORT
      LAYER M5 ;
        RECT  49.296 0 49.32 0.084 ;
    END
  END b[298]
  PIN b[299]
    DIRECTION OUTPUT ;
    USE SIGNAL ;
    PORT
      LAYER M5 ;
        RECT  49.392 0 49.416 0.084 ;
    END
  END b[299]
  PIN b[29]
    DIRECTION OUTPUT ;
    USE SIGNAL ;
    PORT
      LAYER M5 ;
        RECT  34.992 0 35.016 0.084 ;
    END
  END b[29]
  PIN b[2]
    DIRECTION OUTPUT ;
    USE SIGNAL ;
    PORT
      LAYER M5 ;
        RECT  32.4 0 32.424 0.084 ;
    END
  END b[2]
  PIN b[300]
    DIRECTION OUTPUT ;
    USE SIGNAL ;
    PORT
      LAYER M5 ;
        RECT  49.488 0 49.512 0.084 ;
    END
  END b[300]
  PIN b[301]
    DIRECTION OUTPUT ;
    USE SIGNAL ;
    PORT
      LAYER M5 ;
        RECT  49.584 0 49.608 0.084 ;
    END
  END b[301]
  PIN b[302]
    DIRECTION OUTPUT ;
    USE SIGNAL ;
    PORT
      LAYER M5 ;
        RECT  49.68 0 49.704 0.084 ;
    END
  END b[302]
  PIN b[303]
    DIRECTION OUTPUT ;
    USE SIGNAL ;
    PORT
      LAYER M5 ;
        RECT  49.776 0 49.8 0.084 ;
    END
  END b[303]
  PIN b[304]
    DIRECTION OUTPUT ;
    USE SIGNAL ;
    PORT
      LAYER M5 ;
        RECT  49.872 0 49.896 0.084 ;
    END
  END b[304]
  PIN b[305]
    DIRECTION OUTPUT ;
    USE SIGNAL ;
    PORT
      LAYER M5 ;
        RECT  49.968 0 49.992 0.084 ;
    END
  END b[305]
  PIN b[306]
    DIRECTION OUTPUT ;
    USE SIGNAL ;
    PORT
      LAYER M5 ;
        RECT  50.064 0 50.088 0.084 ;
    END
  END b[306]
  PIN b[307]
    DIRECTION OUTPUT ;
    USE SIGNAL ;
    PORT
      LAYER M5 ;
        RECT  50.16 0 50.184 0.084 ;
    END
  END b[307]
  PIN b[308]
    DIRECTION OUTPUT ;
    USE SIGNAL ;
    PORT
      LAYER M5 ;
        RECT  50.256 0 50.28 0.084 ;
    END
  END b[308]
  PIN b[309]
    DIRECTION OUTPUT ;
    USE SIGNAL ;
    PORT
      LAYER M5 ;
        RECT  50.352 0 50.376 0.084 ;
    END
  END b[309]
  PIN b[30]
    DIRECTION OUTPUT ;
    USE SIGNAL ;
    PORT
      LAYER M5 ;
        RECT  35.088 0 35.112 0.084 ;
    END
  END b[30]
  PIN b[310]
    DIRECTION OUTPUT ;
    USE SIGNAL ;
    PORT
      LAYER M5 ;
        RECT  50.448 0 50.472 0.084 ;
    END
  END b[310]
  PIN b[311]
    DIRECTION OUTPUT ;
    USE SIGNAL ;
    PORT
      LAYER M5 ;
        RECT  50.544 0 50.568 0.084 ;
    END
  END b[311]
  PIN b[312]
    DIRECTION OUTPUT ;
    USE SIGNAL ;
    PORT
      LAYER M5 ;
        RECT  50.64 0 50.664 0.084 ;
    END
  END b[312]
  PIN b[313]
    DIRECTION OUTPUT ;
    USE SIGNAL ;
    PORT
      LAYER M5 ;
        RECT  50.736 0 50.76 0.084 ;
    END
  END b[313]
  PIN b[314]
    DIRECTION OUTPUT ;
    USE SIGNAL ;
    PORT
      LAYER M5 ;
        RECT  50.832 0 50.856 0.084 ;
    END
  END b[314]
  PIN b[315]
    DIRECTION OUTPUT ;
    USE SIGNAL ;
    PORT
      LAYER M5 ;
        RECT  50.928 0 50.952 0.084 ;
    END
  END b[315]
  PIN b[316]
    DIRECTION OUTPUT ;
    USE SIGNAL ;
    PORT
      LAYER M5 ;
        RECT  51.024 0 51.048 0.084 ;
    END
  END b[316]
  PIN b[317]
    DIRECTION OUTPUT ;
    USE SIGNAL ;
    PORT
      LAYER M5 ;
        RECT  51.12 0 51.144 0.084 ;
    END
  END b[317]
  PIN b[318]
    DIRECTION OUTPUT ;
    USE SIGNAL ;
    PORT
      LAYER M5 ;
        RECT  51.216 0 51.24 0.084 ;
    END
  END b[318]
  PIN b[319]
    DIRECTION OUTPUT ;
    USE SIGNAL ;
    PORT
      LAYER M5 ;
        RECT  51.312 0 51.336 0.084 ;
    END
  END b[319]
  PIN b[31]
    DIRECTION OUTPUT ;
    USE SIGNAL ;
    PORT
      LAYER M5 ;
        RECT  35.184 0 35.208 0.084 ;
    END
  END b[31]
  PIN b[320]
    DIRECTION OUTPUT ;
    USE SIGNAL ;
    PORT
      LAYER M3 ;
        RECT  65.052 0 65.07 0.037 ;
    END
  END b[320]
  PIN b[321]
    DIRECTION OUTPUT ;
    USE SIGNAL ;
    PORT
      LAYER M3 ;
        RECT  65.124 0 65.142 0.037 ;
    END
  END b[321]
  PIN b[322]
    DIRECTION OUTPUT ;
    USE SIGNAL ;
    PORT
      LAYER M3 ;
        RECT  65.196 0 65.214 0.037 ;
    END
  END b[322]
  PIN b[323]
    DIRECTION OUTPUT ;
    USE SIGNAL ;
    PORT
      LAYER M3 ;
        RECT  65.268 0 65.286 0.037 ;
    END
  END b[323]
  PIN b[324]
    DIRECTION OUTPUT ;
    USE SIGNAL ;
    PORT
      LAYER M3 ;
        RECT  65.34 0 65.358 0.037 ;
    END
  END b[324]
  PIN b[325]
    DIRECTION OUTPUT ;
    USE SIGNAL ;
    PORT
      LAYER M3 ;
        RECT  65.412 0 65.43 0.037 ;
    END
  END b[325]
  PIN b[326]
    DIRECTION OUTPUT ;
    USE SIGNAL ;
    PORT
      LAYER M3 ;
        RECT  65.484 0 65.502 0.037 ;
    END
  END b[326]
  PIN b[327]
    DIRECTION OUTPUT ;
    USE SIGNAL ;
    PORT
      LAYER M3 ;
        RECT  65.556 0 65.574 0.037 ;
    END
  END b[327]
  PIN b[328]
    DIRECTION OUTPUT ;
    USE SIGNAL ;
    PORT
      LAYER M3 ;
        RECT  65.628 0 65.646 0.037 ;
    END
  END b[328]
  PIN b[329]
    DIRECTION OUTPUT ;
    USE SIGNAL ;
    PORT
      LAYER M3 ;
        RECT  65.7 0 65.718 0.037 ;
    END
  END b[329]
  PIN b[32]
    DIRECTION OUTPUT ;
    USE SIGNAL ;
    PORT
      LAYER M3 ;
        RECT  24.156 0 24.174 0.037 ;
    END
  END b[32]
  PIN b[330]
    DIRECTION OUTPUT ;
    USE SIGNAL ;
    PORT
      LAYER M3 ;
        RECT  65.772 0 65.79 0.037 ;
    END
  END b[330]
  PIN b[331]
    DIRECTION OUTPUT ;
    USE SIGNAL ;
    PORT
      LAYER M3 ;
        RECT  65.844 0 65.862 0.037 ;
    END
  END b[331]
  PIN b[332]
    DIRECTION OUTPUT ;
    USE SIGNAL ;
    PORT
      LAYER M3 ;
        RECT  65.916 0 65.934 0.037 ;
    END
  END b[332]
  PIN b[333]
    DIRECTION OUTPUT ;
    USE SIGNAL ;
    PORT
      LAYER M3 ;
        RECT  65.988 0 66.006 0.037 ;
    END
  END b[333]
  PIN b[334]
    DIRECTION OUTPUT ;
    USE SIGNAL ;
    PORT
      LAYER M3 ;
        RECT  66.06 0 66.078 0.037 ;
    END
  END b[334]
  PIN b[335]
    DIRECTION OUTPUT ;
    USE SIGNAL ;
    PORT
      LAYER M3 ;
        RECT  66.132 0 66.15 0.037 ;
    END
  END b[335]
  PIN b[336]
    DIRECTION OUTPUT ;
    USE SIGNAL ;
    PORT
      LAYER M3 ;
        RECT  66.204 0 66.222 0.037 ;
    END
  END b[336]
  PIN b[337]
    DIRECTION OUTPUT ;
    USE SIGNAL ;
    PORT
      LAYER M3 ;
        RECT  66.276 0 66.294 0.037 ;
    END
  END b[337]
  PIN b[338]
    DIRECTION OUTPUT ;
    USE SIGNAL ;
    PORT
      LAYER M3 ;
        RECT  66.348 0 66.366 0.037 ;
    END
  END b[338]
  PIN b[339]
    DIRECTION OUTPUT ;
    USE SIGNAL ;
    PORT
      LAYER M3 ;
        RECT  66.42 0 66.438 0.037 ;
    END
  END b[339]
  PIN b[33]
    DIRECTION OUTPUT ;
    USE SIGNAL ;
    PORT
      LAYER M3 ;
        RECT  24.228 0 24.246 0.037 ;
    END
  END b[33]
  PIN b[340]
    DIRECTION OUTPUT ;
    USE SIGNAL ;
    PORT
      LAYER M3 ;
        RECT  66.492 0 66.51 0.037 ;
    END
  END b[340]
  PIN b[341]
    DIRECTION OUTPUT ;
    USE SIGNAL ;
    PORT
      LAYER M3 ;
        RECT  66.564 0 66.582 0.037 ;
    END
  END b[341]
  PIN b[342]
    DIRECTION OUTPUT ;
    USE SIGNAL ;
    PORT
      LAYER M3 ;
        RECT  66.636 0 66.654 0.037 ;
    END
  END b[342]
  PIN b[343]
    DIRECTION OUTPUT ;
    USE SIGNAL ;
    PORT
      LAYER M3 ;
        RECT  66.708 0 66.726 0.037 ;
    END
  END b[343]
  PIN b[344]
    DIRECTION OUTPUT ;
    USE SIGNAL ;
    PORT
      LAYER M3 ;
        RECT  66.78 0 66.798 0.037 ;
    END
  END b[344]
  PIN b[345]
    DIRECTION OUTPUT ;
    USE SIGNAL ;
    PORT
      LAYER M3 ;
        RECT  66.852 0 66.87 0.037 ;
    END
  END b[345]
  PIN b[346]
    DIRECTION OUTPUT ;
    USE SIGNAL ;
    PORT
      LAYER M3 ;
        RECT  66.924 0 66.942 0.037 ;
    END
  END b[346]
  PIN b[347]
    DIRECTION OUTPUT ;
    USE SIGNAL ;
    PORT
      LAYER M3 ;
        RECT  66.996 0 67.014 0.037 ;
    END
  END b[347]
  PIN b[348]
    DIRECTION OUTPUT ;
    USE SIGNAL ;
    PORT
      LAYER M3 ;
        RECT  67.068 0 67.086 0.037 ;
    END
  END b[348]
  PIN b[349]
    DIRECTION OUTPUT ;
    USE SIGNAL ;
    PORT
      LAYER M3 ;
        RECT  67.14 0 67.158 0.037 ;
    END
  END b[349]
  PIN b[34]
    DIRECTION OUTPUT ;
    USE SIGNAL ;
    PORT
      LAYER M3 ;
        RECT  24.3 0 24.318 0.037 ;
    END
  END b[34]
  PIN b[350]
    DIRECTION OUTPUT ;
    USE SIGNAL ;
    PORT
      LAYER M3 ;
        RECT  67.212 0 67.23 0.037 ;
    END
  END b[350]
  PIN b[351]
    DIRECTION OUTPUT ;
    USE SIGNAL ;
    PORT
      LAYER M3 ;
        RECT  67.284 0 67.302 0.037 ;
    END
  END b[351]
  PIN b[352]
    DIRECTION OUTPUT ;
    USE SIGNAL ;
    PORT
      LAYER M3 ;
        RECT  67.356 0 67.374 0.037 ;
    END
  END b[352]
  PIN b[353]
    DIRECTION OUTPUT ;
    USE SIGNAL ;
    PORT
      LAYER M3 ;
        RECT  67.428 0 67.446 0.037 ;
    END
  END b[353]
  PIN b[354]
    DIRECTION OUTPUT ;
    USE SIGNAL ;
    PORT
      LAYER M3 ;
        RECT  67.5 0 67.518 0.037 ;
    END
  END b[354]
  PIN b[355]
    DIRECTION OUTPUT ;
    USE SIGNAL ;
    PORT
      LAYER M3 ;
        RECT  67.572 0 67.59 0.037 ;
    END
  END b[355]
  PIN b[356]
    DIRECTION OUTPUT ;
    USE SIGNAL ;
    PORT
      LAYER M3 ;
        RECT  67.644 0 67.662 0.037 ;
    END
  END b[356]
  PIN b[357]
    DIRECTION OUTPUT ;
    USE SIGNAL ;
    PORT
      LAYER M3 ;
        RECT  67.716 0 67.734 0.037 ;
    END
  END b[357]
  PIN b[358]
    DIRECTION OUTPUT ;
    USE SIGNAL ;
    PORT
      LAYER M3 ;
        RECT  67.788 0 67.806 0.037 ;
    END
  END b[358]
  PIN b[359]
    DIRECTION OUTPUT ;
    USE SIGNAL ;
    PORT
      LAYER M3 ;
        RECT  67.86 0 67.878 0.037 ;
    END
  END b[359]
  PIN b[35]
    DIRECTION OUTPUT ;
    USE SIGNAL ;
    PORT
      LAYER M3 ;
        RECT  24.372 0 24.39 0.037 ;
    END
  END b[35]
  PIN b[360]
    DIRECTION OUTPUT ;
    USE SIGNAL ;
    PORT
      LAYER M3 ;
        RECT  67.932 0 67.95 0.037 ;
    END
  END b[360]
  PIN b[361]
    DIRECTION OUTPUT ;
    USE SIGNAL ;
    PORT
      LAYER M3 ;
        RECT  68.004 0 68.022 0.037 ;
    END
  END b[361]
  PIN b[362]
    DIRECTION OUTPUT ;
    USE SIGNAL ;
    PORT
      LAYER M3 ;
        RECT  68.076 0 68.094 0.037 ;
    END
  END b[362]
  PIN b[363]
    DIRECTION OUTPUT ;
    USE SIGNAL ;
    PORT
      LAYER M3 ;
        RECT  68.148 0 68.166 0.037 ;
    END
  END b[363]
  PIN b[364]
    DIRECTION OUTPUT ;
    USE SIGNAL ;
    PORT
      LAYER M3 ;
        RECT  68.22 0 68.238 0.037 ;
    END
  END b[364]
  PIN b[365]
    DIRECTION OUTPUT ;
    USE SIGNAL ;
    PORT
      LAYER M3 ;
        RECT  68.292 0 68.31 0.037 ;
    END
  END b[365]
  PIN b[366]
    DIRECTION OUTPUT ;
    USE SIGNAL ;
    PORT
      LAYER M3 ;
        RECT  68.364 0 68.382 0.037 ;
    END
  END b[366]
  PIN b[367]
    DIRECTION OUTPUT ;
    USE SIGNAL ;
    PORT
      LAYER M3 ;
        RECT  68.436 0 68.454 0.037 ;
    END
  END b[367]
  PIN b[368]
    DIRECTION OUTPUT ;
    USE SIGNAL ;
    PORT
      LAYER M3 ;
        RECT  68.508 0 68.526 0.037 ;
    END
  END b[368]
  PIN b[369]
    DIRECTION OUTPUT ;
    USE SIGNAL ;
    PORT
      LAYER M3 ;
        RECT  68.58 0 68.598 0.037 ;
    END
  END b[369]
  PIN b[36]
    DIRECTION OUTPUT ;
    USE SIGNAL ;
    PORT
      LAYER M3 ;
        RECT  24.444 0 24.462 0.037 ;
    END
  END b[36]
  PIN b[370]
    DIRECTION OUTPUT ;
    USE SIGNAL ;
    PORT
      LAYER M3 ;
        RECT  68.652 0 68.67 0.037 ;
    END
  END b[370]
  PIN b[371]
    DIRECTION OUTPUT ;
    USE SIGNAL ;
    PORT
      LAYER M3 ;
        RECT  68.724 0 68.742 0.037 ;
    END
  END b[371]
  PIN b[372]
    DIRECTION OUTPUT ;
    USE SIGNAL ;
    PORT
      LAYER M3 ;
        RECT  68.796 0 68.814 0.037 ;
    END
  END b[372]
  PIN b[373]
    DIRECTION OUTPUT ;
    USE SIGNAL ;
    PORT
      LAYER M3 ;
        RECT  68.868 0 68.886 0.037 ;
    END
  END b[373]
  PIN b[374]
    DIRECTION OUTPUT ;
    USE SIGNAL ;
    PORT
      LAYER M3 ;
        RECT  68.94 0 68.958 0.037 ;
    END
  END b[374]
  PIN b[375]
    DIRECTION OUTPUT ;
    USE SIGNAL ;
    PORT
      LAYER M3 ;
        RECT  69.012 0 69.03 0.037 ;
    END
  END b[375]
  PIN b[376]
    DIRECTION OUTPUT ;
    USE SIGNAL ;
    PORT
      LAYER M3 ;
        RECT  69.084 0 69.102 0.037 ;
    END
  END b[376]
  PIN b[377]
    DIRECTION OUTPUT ;
    USE SIGNAL ;
    PORT
      LAYER M3 ;
        RECT  69.156 0 69.174 0.037 ;
    END
  END b[377]
  PIN b[378]
    DIRECTION OUTPUT ;
    USE SIGNAL ;
    PORT
      LAYER M3 ;
        RECT  69.228 0 69.246 0.037 ;
    END
  END b[378]
  PIN b[379]
    DIRECTION OUTPUT ;
    USE SIGNAL ;
    PORT
      LAYER M3 ;
        RECT  69.3 0 69.318 0.037 ;
    END
  END b[379]
  PIN b[37]
    DIRECTION OUTPUT ;
    USE SIGNAL ;
    PORT
      LAYER M3 ;
        RECT  24.516 0 24.534 0.037 ;
    END
  END b[37]
  PIN b[380]
    DIRECTION OUTPUT ;
    USE SIGNAL ;
    PORT
      LAYER M3 ;
        RECT  69.372 0 69.39 0.037 ;
    END
  END b[380]
  PIN b[381]
    DIRECTION OUTPUT ;
    USE SIGNAL ;
    PORT
      LAYER M3 ;
        RECT  69.444 0 69.462 0.037 ;
    END
  END b[381]
  PIN b[382]
    DIRECTION OUTPUT ;
    USE SIGNAL ;
    PORT
      LAYER M3 ;
        RECT  69.516 0 69.534 0.037 ;
    END
  END b[382]
  PIN b[383]
    DIRECTION OUTPUT ;
    USE SIGNAL ;
    PORT
      LAYER M3 ;
        RECT  69.588 0 69.606 0.037 ;
    END
  END b[383]
  PIN b[384]
    DIRECTION OUTPUT ;
    USE SIGNAL ;
    PORT
      LAYER M5 ;
        RECT  70.608 0 70.632 0.084 ;
    END
  END b[384]
  PIN b[385]
    DIRECTION OUTPUT ;
    USE SIGNAL ;
    PORT
      LAYER M5 ;
        RECT  70.704 0 70.728 0.084 ;
    END
  END b[385]
  PIN b[386]
    DIRECTION OUTPUT ;
    USE SIGNAL ;
    PORT
      LAYER M5 ;
        RECT  70.8 0 70.824 0.084 ;
    END
  END b[386]
  PIN b[387]
    DIRECTION OUTPUT ;
    USE SIGNAL ;
    PORT
      LAYER M5 ;
        RECT  70.896 0 70.92 0.084 ;
    END
  END b[387]
  PIN b[388]
    DIRECTION OUTPUT ;
    USE SIGNAL ;
    PORT
      LAYER M5 ;
        RECT  70.992 0 71.016 0.084 ;
    END
  END b[388]
  PIN b[389]
    DIRECTION OUTPUT ;
    USE SIGNAL ;
    PORT
      LAYER M5 ;
        RECT  71.088 0 71.112 0.084 ;
    END
  END b[389]
  PIN b[38]
    DIRECTION OUTPUT ;
    USE SIGNAL ;
    PORT
      LAYER M3 ;
        RECT  24.588 0 24.606 0.037 ;
    END
  END b[38]
  PIN b[390]
    DIRECTION OUTPUT ;
    USE SIGNAL ;
    PORT
      LAYER M5 ;
        RECT  71.184 0 71.208 0.084 ;
    END
  END b[390]
  PIN b[391]
    DIRECTION OUTPUT ;
    USE SIGNAL ;
    PORT
      LAYER M5 ;
        RECT  71.28 0 71.304 0.084 ;
    END
  END b[391]
  PIN b[392]
    DIRECTION OUTPUT ;
    USE SIGNAL ;
    PORT
      LAYER M5 ;
        RECT  71.376 0 71.4 0.084 ;
    END
  END b[392]
  PIN b[393]
    DIRECTION OUTPUT ;
    USE SIGNAL ;
    PORT
      LAYER M5 ;
        RECT  71.472 0 71.496 0.084 ;
    END
  END b[393]
  PIN b[394]
    DIRECTION OUTPUT ;
    USE SIGNAL ;
    PORT
      LAYER M5 ;
        RECT  71.568 0 71.592 0.084 ;
    END
  END b[394]
  PIN b[395]
    DIRECTION OUTPUT ;
    USE SIGNAL ;
    PORT
      LAYER M5 ;
        RECT  71.664 0 71.688 0.084 ;
    END
  END b[395]
  PIN b[396]
    DIRECTION OUTPUT ;
    USE SIGNAL ;
    PORT
      LAYER M5 ;
        RECT  71.76 0 71.784 0.084 ;
    END
  END b[396]
  PIN b[397]
    DIRECTION OUTPUT ;
    USE SIGNAL ;
    PORT
      LAYER M5 ;
        RECT  71.856 0 71.88 0.084 ;
    END
  END b[397]
  PIN b[398]
    DIRECTION OUTPUT ;
    USE SIGNAL ;
    PORT
      LAYER M5 ;
        RECT  71.952 0 71.976 0.084 ;
    END
  END b[398]
  PIN b[399]
    DIRECTION OUTPUT ;
    USE SIGNAL ;
    PORT
      LAYER M5 ;
        RECT  72.048 0 72.072 0.084 ;
    END
  END b[399]
  PIN b[39]
    DIRECTION OUTPUT ;
    USE SIGNAL ;
    PORT
      LAYER M3 ;
        RECT  24.66 0 24.678 0.037 ;
    END
  END b[39]
  PIN b[3]
    DIRECTION OUTPUT ;
    USE SIGNAL ;
    PORT
      LAYER M5 ;
        RECT  32.496 0 32.52 0.084 ;
    END
  END b[3]
  PIN b[400]
    DIRECTION OUTPUT ;
    USE SIGNAL ;
    PORT
      LAYER M5 ;
        RECT  72.144 0 72.168 0.084 ;
    END
  END b[400]
  PIN b[401]
    DIRECTION OUTPUT ;
    USE SIGNAL ;
    PORT
      LAYER M5 ;
        RECT  72.24 0 72.264 0.084 ;
    END
  END b[401]
  PIN b[402]
    DIRECTION OUTPUT ;
    USE SIGNAL ;
    PORT
      LAYER M5 ;
        RECT  72.336 0 72.36 0.084 ;
    END
  END b[402]
  PIN b[403]
    DIRECTION OUTPUT ;
    USE SIGNAL ;
    PORT
      LAYER M5 ;
        RECT  72.432 0 72.456 0.084 ;
    END
  END b[403]
  PIN b[404]
    DIRECTION OUTPUT ;
    USE SIGNAL ;
    PORT
      LAYER M5 ;
        RECT  72.528 0 72.552 0.084 ;
    END
  END b[404]
  PIN b[405]
    DIRECTION OUTPUT ;
    USE SIGNAL ;
    PORT
      LAYER M5 ;
        RECT  72.624 0 72.648 0.084 ;
    END
  END b[405]
  PIN b[406]
    DIRECTION OUTPUT ;
    USE SIGNAL ;
    PORT
      LAYER M5 ;
        RECT  72.72 0 72.744 0.084 ;
    END
  END b[406]
  PIN b[407]
    DIRECTION OUTPUT ;
    USE SIGNAL ;
    PORT
      LAYER M5 ;
        RECT  72.816 0 72.84 0.084 ;
    END
  END b[407]
  PIN b[408]
    DIRECTION OUTPUT ;
    USE SIGNAL ;
    PORT
      LAYER M5 ;
        RECT  72.912 0 72.936 0.084 ;
    END
  END b[408]
  PIN b[409]
    DIRECTION OUTPUT ;
    USE SIGNAL ;
    PORT
      LAYER M5 ;
        RECT  73.008 0 73.032 0.084 ;
    END
  END b[409]
  PIN b[40]
    DIRECTION OUTPUT ;
    USE SIGNAL ;
    PORT
      LAYER M3 ;
        RECT  24.732 0 24.75 0.037 ;
    END
  END b[40]
  PIN b[410]
    DIRECTION OUTPUT ;
    USE SIGNAL ;
    PORT
      LAYER M5 ;
        RECT  73.104 0 73.128 0.084 ;
    END
  END b[410]
  PIN b[411]
    DIRECTION OUTPUT ;
    USE SIGNAL ;
    PORT
      LAYER M5 ;
        RECT  73.2 0 73.224 0.084 ;
    END
  END b[411]
  PIN b[412]
    DIRECTION OUTPUT ;
    USE SIGNAL ;
    PORT
      LAYER M5 ;
        RECT  73.296 0 73.32 0.084 ;
    END
  END b[412]
  PIN b[413]
    DIRECTION OUTPUT ;
    USE SIGNAL ;
    PORT
      LAYER M5 ;
        RECT  73.392 0 73.416 0.084 ;
    END
  END b[413]
  PIN b[414]
    DIRECTION OUTPUT ;
    USE SIGNAL ;
    PORT
      LAYER M5 ;
        RECT  73.488 0 73.512 0.084 ;
    END
  END b[414]
  PIN b[415]
    DIRECTION OUTPUT ;
    USE SIGNAL ;
    PORT
      LAYER M5 ;
        RECT  73.584 0 73.608 0.084 ;
    END
  END b[415]
  PIN b[416]
    DIRECTION OUTPUT ;
    USE SIGNAL ;
    PORT
      LAYER M5 ;
        RECT  86.736 0 86.76 0.084 ;
    END
  END b[416]
  PIN b[417]
    DIRECTION OUTPUT ;
    USE SIGNAL ;
    PORT
      LAYER M5 ;
        RECT  86.832 0 86.856 0.084 ;
    END
  END b[417]
  PIN b[418]
    DIRECTION OUTPUT ;
    USE SIGNAL ;
    PORT
      LAYER M5 ;
        RECT  86.928 0 86.952 0.084 ;
    END
  END b[418]
  PIN b[419]
    DIRECTION OUTPUT ;
    USE SIGNAL ;
    PORT
      LAYER M5 ;
        RECT  87.024 0 87.048 0.084 ;
    END
  END b[419]
  PIN b[41]
    DIRECTION OUTPUT ;
    USE SIGNAL ;
    PORT
      LAYER M3 ;
        RECT  24.804 0 24.822 0.037 ;
    END
  END b[41]
  PIN b[420]
    DIRECTION OUTPUT ;
    USE SIGNAL ;
    PORT
      LAYER M5 ;
        RECT  87.12 0 87.144 0.084 ;
    END
  END b[420]
  PIN b[421]
    DIRECTION OUTPUT ;
    USE SIGNAL ;
    PORT
      LAYER M5 ;
        RECT  87.216 0 87.24 0.084 ;
    END
  END b[421]
  PIN b[422]
    DIRECTION OUTPUT ;
    USE SIGNAL ;
    PORT
      LAYER M5 ;
        RECT  87.312 0 87.336 0.084 ;
    END
  END b[422]
  PIN b[423]
    DIRECTION OUTPUT ;
    USE SIGNAL ;
    PORT
      LAYER M5 ;
        RECT  87.408 0 87.432 0.084 ;
    END
  END b[423]
  PIN b[424]
    DIRECTION OUTPUT ;
    USE SIGNAL ;
    PORT
      LAYER M5 ;
        RECT  87.504 0 87.528 0.084 ;
    END
  END b[424]
  PIN b[425]
    DIRECTION OUTPUT ;
    USE SIGNAL ;
    PORT
      LAYER M5 ;
        RECT  87.6 0 87.624 0.084 ;
    END
  END b[425]
  PIN b[426]
    DIRECTION OUTPUT ;
    USE SIGNAL ;
    PORT
      LAYER M5 ;
        RECT  87.696 0 87.72 0.084 ;
    END
  END b[426]
  PIN b[427]
    DIRECTION OUTPUT ;
    USE SIGNAL ;
    PORT
      LAYER M5 ;
        RECT  87.792 0 87.816 0.084 ;
    END
  END b[427]
  PIN b[428]
    DIRECTION OUTPUT ;
    USE SIGNAL ;
    PORT
      LAYER M5 ;
        RECT  87.888 0 87.912 0.084 ;
    END
  END b[428]
  PIN b[429]
    DIRECTION OUTPUT ;
    USE SIGNAL ;
    PORT
      LAYER M5 ;
        RECT  87.984 0 88.008 0.084 ;
    END
  END b[429]
  PIN b[42]
    DIRECTION OUTPUT ;
    USE SIGNAL ;
    PORT
      LAYER M3 ;
        RECT  24.876 0 24.894 0.037 ;
    END
  END b[42]
  PIN b[430]
    DIRECTION OUTPUT ;
    USE SIGNAL ;
    PORT
      LAYER M5 ;
        RECT  88.08 0 88.104 0.084 ;
    END
  END b[430]
  PIN b[431]
    DIRECTION OUTPUT ;
    USE SIGNAL ;
    PORT
      LAYER M5 ;
        RECT  88.176 0 88.2 0.084 ;
    END
  END b[431]
  PIN b[432]
    DIRECTION OUTPUT ;
    USE SIGNAL ;
    PORT
      LAYER M5 ;
        RECT  88.272 0 88.296 0.084 ;
    END
  END b[432]
  PIN b[433]
    DIRECTION OUTPUT ;
    USE SIGNAL ;
    PORT
      LAYER M5 ;
        RECT  88.368 0 88.392 0.084 ;
    END
  END b[433]
  PIN b[434]
    DIRECTION OUTPUT ;
    USE SIGNAL ;
    PORT
      LAYER M5 ;
        RECT  88.464 0 88.488 0.084 ;
    END
  END b[434]
  PIN b[435]
    DIRECTION OUTPUT ;
    USE SIGNAL ;
    PORT
      LAYER M5 ;
        RECT  88.56 0 88.584 0.084 ;
    END
  END b[435]
  PIN b[436]
    DIRECTION OUTPUT ;
    USE SIGNAL ;
    PORT
      LAYER M5 ;
        RECT  88.656 0 88.68 0.084 ;
    END
  END b[436]
  PIN b[437]
    DIRECTION OUTPUT ;
    USE SIGNAL ;
    PORT
      LAYER M5 ;
        RECT  88.752 0 88.776 0.084 ;
    END
  END b[437]
  PIN b[438]
    DIRECTION OUTPUT ;
    USE SIGNAL ;
    PORT
      LAYER M5 ;
        RECT  88.848 0 88.872 0.084 ;
    END
  END b[438]
  PIN b[439]
    DIRECTION OUTPUT ;
    USE SIGNAL ;
    PORT
      LAYER M5 ;
        RECT  88.944 0 88.968 0.084 ;
    END
  END b[439]
  PIN b[43]
    DIRECTION OUTPUT ;
    USE SIGNAL ;
    PORT
      LAYER M3 ;
        RECT  24.948 0 24.966 0.037 ;
    END
  END b[43]
  PIN b[440]
    DIRECTION OUTPUT ;
    USE SIGNAL ;
    PORT
      LAYER M5 ;
        RECT  89.04 0 89.064 0.084 ;
    END
  END b[440]
  PIN b[441]
    DIRECTION OUTPUT ;
    USE SIGNAL ;
    PORT
      LAYER M5 ;
        RECT  89.136 0 89.16 0.084 ;
    END
  END b[441]
  PIN b[442]
    DIRECTION OUTPUT ;
    USE SIGNAL ;
    PORT
      LAYER M5 ;
        RECT  89.232 0 89.256 0.084 ;
    END
  END b[442]
  PIN b[443]
    DIRECTION OUTPUT ;
    USE SIGNAL ;
    PORT
      LAYER M5 ;
        RECT  89.328 0 89.352 0.084 ;
    END
  END b[443]
  PIN b[444]
    DIRECTION OUTPUT ;
    USE SIGNAL ;
    PORT
      LAYER M5 ;
        RECT  89.424 0 89.448 0.084 ;
    END
  END b[444]
  PIN b[445]
    DIRECTION OUTPUT ;
    USE SIGNAL ;
    PORT
      LAYER M5 ;
        RECT  89.52 0 89.544 0.084 ;
    END
  END b[445]
  PIN b[446]
    DIRECTION OUTPUT ;
    USE SIGNAL ;
    PORT
      LAYER M5 ;
        RECT  89.616 0 89.64 0.084 ;
    END
  END b[446]
  PIN b[447]
    DIRECTION OUTPUT ;
    USE SIGNAL ;
    PORT
      LAYER M5 ;
        RECT  89.712 0 89.736 0.084 ;
    END
  END b[447]
  PIN b[448]
    DIRECTION OUTPUT ;
    USE SIGNAL ;
    PORT
      LAYER M3 ;
        RECT  60.444 0 60.462 0.037 ;
    END
  END b[448]
  PIN b[449]
    DIRECTION OUTPUT ;
    USE SIGNAL ;
    PORT
      LAYER M3 ;
        RECT  60.516 0 60.534 0.037 ;
    END
  END b[449]
  PIN b[44]
    DIRECTION OUTPUT ;
    USE SIGNAL ;
    PORT
      LAYER M3 ;
        RECT  25.02 0 25.038 0.037 ;
    END
  END b[44]
  PIN b[450]
    DIRECTION OUTPUT ;
    USE SIGNAL ;
    PORT
      LAYER M3 ;
        RECT  60.588 0 60.606 0.037 ;
    END
  END b[450]
  PIN b[451]
    DIRECTION OUTPUT ;
    USE SIGNAL ;
    PORT
      LAYER M3 ;
        RECT  60.66 0 60.678 0.037 ;
    END
  END b[451]
  PIN b[452]
    DIRECTION OUTPUT ;
    USE SIGNAL ;
    PORT
      LAYER M3 ;
        RECT  60.732 0 60.75 0.037 ;
    END
  END b[452]
  PIN b[453]
    DIRECTION OUTPUT ;
    USE SIGNAL ;
    PORT
      LAYER M3 ;
        RECT  60.804 0 60.822 0.037 ;
    END
  END b[453]
  PIN b[454]
    DIRECTION OUTPUT ;
    USE SIGNAL ;
    PORT
      LAYER M3 ;
        RECT  60.876 0 60.894 0.037 ;
    END
  END b[454]
  PIN b[455]
    DIRECTION OUTPUT ;
    USE SIGNAL ;
    PORT
      LAYER M3 ;
        RECT  60.948 0 60.966 0.037 ;
    END
  END b[455]
  PIN b[456]
    DIRECTION OUTPUT ;
    USE SIGNAL ;
    PORT
      LAYER M3 ;
        RECT  61.02 0 61.038 0.037 ;
    END
  END b[456]
  PIN b[457]
    DIRECTION OUTPUT ;
    USE SIGNAL ;
    PORT
      LAYER M3 ;
        RECT  61.092 0 61.11 0.037 ;
    END
  END b[457]
  PIN b[458]
    DIRECTION OUTPUT ;
    USE SIGNAL ;
    PORT
      LAYER M3 ;
        RECT  61.164 0 61.182 0.037 ;
    END
  END b[458]
  PIN b[459]
    DIRECTION OUTPUT ;
    USE SIGNAL ;
    PORT
      LAYER M3 ;
        RECT  61.236 0 61.254 0.037 ;
    END
  END b[459]
  PIN b[45]
    DIRECTION OUTPUT ;
    USE SIGNAL ;
    PORT
      LAYER M3 ;
        RECT  25.092 0 25.11 0.037 ;
    END
  END b[45]
  PIN b[460]
    DIRECTION OUTPUT ;
    USE SIGNAL ;
    PORT
      LAYER M3 ;
        RECT  61.308 0 61.326 0.037 ;
    END
  END b[460]
  PIN b[461]
    DIRECTION OUTPUT ;
    USE SIGNAL ;
    PORT
      LAYER M3 ;
        RECT  61.38 0 61.398 0.037 ;
    END
  END b[461]
  PIN b[462]
    DIRECTION OUTPUT ;
    USE SIGNAL ;
    PORT
      LAYER M3 ;
        RECT  61.452 0 61.47 0.037 ;
    END
  END b[462]
  PIN b[463]
    DIRECTION OUTPUT ;
    USE SIGNAL ;
    PORT
      LAYER M3 ;
        RECT  61.524 0 61.542 0.037 ;
    END
  END b[463]
  PIN b[464]
    DIRECTION OUTPUT ;
    USE SIGNAL ;
    PORT
      LAYER M3 ;
        RECT  61.596 0 61.614 0.037 ;
    END
  END b[464]
  PIN b[465]
    DIRECTION OUTPUT ;
    USE SIGNAL ;
    PORT
      LAYER M3 ;
        RECT  61.668 0 61.686 0.037 ;
    END
  END b[465]
  PIN b[466]
    DIRECTION OUTPUT ;
    USE SIGNAL ;
    PORT
      LAYER M3 ;
        RECT  61.74 0 61.758 0.037 ;
    END
  END b[466]
  PIN b[467]
    DIRECTION OUTPUT ;
    USE SIGNAL ;
    PORT
      LAYER M3 ;
        RECT  61.812 0 61.83 0.037 ;
    END
  END b[467]
  PIN b[468]
    DIRECTION OUTPUT ;
    USE SIGNAL ;
    PORT
      LAYER M3 ;
        RECT  61.884 0 61.902 0.037 ;
    END
  END b[468]
  PIN b[469]
    DIRECTION OUTPUT ;
    USE SIGNAL ;
    PORT
      LAYER M3 ;
        RECT  61.956 0 61.974 0.037 ;
    END
  END b[469]
  PIN b[46]
    DIRECTION OUTPUT ;
    USE SIGNAL ;
    PORT
      LAYER M3 ;
        RECT  25.164 0 25.182 0.037 ;
    END
  END b[46]
  PIN b[470]
    DIRECTION OUTPUT ;
    USE SIGNAL ;
    PORT
      LAYER M3 ;
        RECT  62.028 0 62.046 0.037 ;
    END
  END b[470]
  PIN b[471]
    DIRECTION OUTPUT ;
    USE SIGNAL ;
    PORT
      LAYER M3 ;
        RECT  62.1 0 62.118 0.037 ;
    END
  END b[471]
  PIN b[472]
    DIRECTION OUTPUT ;
    USE SIGNAL ;
    PORT
      LAYER M3 ;
        RECT  62.172 0 62.19 0.037 ;
    END
  END b[472]
  PIN b[473]
    DIRECTION OUTPUT ;
    USE SIGNAL ;
    PORT
      LAYER M3 ;
        RECT  62.244 0 62.262 0.037 ;
    END
  END b[473]
  PIN b[474]
    DIRECTION OUTPUT ;
    USE SIGNAL ;
    PORT
      LAYER M3 ;
        RECT  62.316 0 62.334 0.037 ;
    END
  END b[474]
  PIN b[475]
    DIRECTION OUTPUT ;
    USE SIGNAL ;
    PORT
      LAYER M3 ;
        RECT  62.388 0 62.406 0.037 ;
    END
  END b[475]
  PIN b[476]
    DIRECTION OUTPUT ;
    USE SIGNAL ;
    PORT
      LAYER M3 ;
        RECT  62.46 0 62.478 0.037 ;
    END
  END b[476]
  PIN b[477]
    DIRECTION OUTPUT ;
    USE SIGNAL ;
    PORT
      LAYER M3 ;
        RECT  62.532 0 62.55 0.037 ;
    END
  END b[477]
  PIN b[478]
    DIRECTION OUTPUT ;
    USE SIGNAL ;
    PORT
      LAYER M3 ;
        RECT  62.604 0 62.622 0.037 ;
    END
  END b[478]
  PIN b[479]
    DIRECTION OUTPUT ;
    USE SIGNAL ;
    PORT
      LAYER M3 ;
        RECT  62.676 0 62.694 0.037 ;
    END
  END b[479]
  PIN b[47]
    DIRECTION OUTPUT ;
    USE SIGNAL ;
    PORT
      LAYER M3 ;
        RECT  25.236 0 25.254 0.037 ;
    END
  END b[47]
  PIN b[480]
    DIRECTION OUTPUT ;
    USE SIGNAL ;
    PORT
      LAYER M3 ;
        RECT  62.748 0 62.766 0.037 ;
    END
  END b[480]
  PIN b[481]
    DIRECTION OUTPUT ;
    USE SIGNAL ;
    PORT
      LAYER M3 ;
        RECT  62.82 0 62.838 0.037 ;
    END
  END b[481]
  PIN b[482]
    DIRECTION OUTPUT ;
    USE SIGNAL ;
    PORT
      LAYER M3 ;
        RECT  62.892 0 62.91 0.037 ;
    END
  END b[482]
  PIN b[483]
    DIRECTION OUTPUT ;
    USE SIGNAL ;
    PORT
      LAYER M3 ;
        RECT  62.964 0 62.982 0.037 ;
    END
  END b[483]
  PIN b[484]
    DIRECTION OUTPUT ;
    USE SIGNAL ;
    PORT
      LAYER M3 ;
        RECT  63.036 0 63.054 0.037 ;
    END
  END b[484]
  PIN b[485]
    DIRECTION OUTPUT ;
    USE SIGNAL ;
    PORT
      LAYER M3 ;
        RECT  63.108 0 63.126 0.037 ;
    END
  END b[485]
  PIN b[486]
    DIRECTION OUTPUT ;
    USE SIGNAL ;
    PORT
      LAYER M3 ;
        RECT  63.18 0 63.198 0.037 ;
    END
  END b[486]
  PIN b[487]
    DIRECTION OUTPUT ;
    USE SIGNAL ;
    PORT
      LAYER M3 ;
        RECT  63.252 0 63.27 0.037 ;
    END
  END b[487]
  PIN b[488]
    DIRECTION OUTPUT ;
    USE SIGNAL ;
    PORT
      LAYER M3 ;
        RECT  63.324 0 63.342 0.037 ;
    END
  END b[488]
  PIN b[489]
    DIRECTION OUTPUT ;
    USE SIGNAL ;
    PORT
      LAYER M3 ;
        RECT  63.396 0 63.414 0.037 ;
    END
  END b[489]
  PIN b[48]
    DIRECTION OUTPUT ;
    USE SIGNAL ;
    PORT
      LAYER M3 ;
        RECT  25.308 0 25.326 0.037 ;
    END
  END b[48]
  PIN b[490]
    DIRECTION OUTPUT ;
    USE SIGNAL ;
    PORT
      LAYER M3 ;
        RECT  63.468 0 63.486 0.037 ;
    END
  END b[490]
  PIN b[491]
    DIRECTION OUTPUT ;
    USE SIGNAL ;
    PORT
      LAYER M3 ;
        RECT  63.54 0 63.558 0.037 ;
    END
  END b[491]
  PIN b[492]
    DIRECTION OUTPUT ;
    USE SIGNAL ;
    PORT
      LAYER M3 ;
        RECT  63.612 0 63.63 0.037 ;
    END
  END b[492]
  PIN b[493]
    DIRECTION OUTPUT ;
    USE SIGNAL ;
    PORT
      LAYER M3 ;
        RECT  63.684 0 63.702 0.037 ;
    END
  END b[493]
  PIN b[494]
    DIRECTION OUTPUT ;
    USE SIGNAL ;
    PORT
      LAYER M3 ;
        RECT  63.756 0 63.774 0.037 ;
    END
  END b[494]
  PIN b[495]
    DIRECTION OUTPUT ;
    USE SIGNAL ;
    PORT
      LAYER M3 ;
        RECT  63.828 0 63.846 0.037 ;
    END
  END b[495]
  PIN b[496]
    DIRECTION OUTPUT ;
    USE SIGNAL ;
    PORT
      LAYER M3 ;
        RECT  63.9 0 63.918 0.037 ;
    END
  END b[496]
  PIN b[497]
    DIRECTION OUTPUT ;
    USE SIGNAL ;
    PORT
      LAYER M3 ;
        RECT  63.972 0 63.99 0.037 ;
    END
  END b[497]
  PIN b[498]
    DIRECTION OUTPUT ;
    USE SIGNAL ;
    PORT
      LAYER M3 ;
        RECT  64.044 0 64.062 0.037 ;
    END
  END b[498]
  PIN b[499]
    DIRECTION OUTPUT ;
    USE SIGNAL ;
    PORT
      LAYER M3 ;
        RECT  64.116 0 64.134 0.037 ;
    END
  END b[499]
  PIN b[49]
    DIRECTION OUTPUT ;
    USE SIGNAL ;
    PORT
      LAYER M3 ;
        RECT  25.38 0 25.398 0.037 ;
    END
  END b[49]
  PIN b[4]
    DIRECTION OUTPUT ;
    USE SIGNAL ;
    PORT
      LAYER M5 ;
        RECT  32.592 0 32.616 0.084 ;
    END
  END b[4]
  PIN b[500]
    DIRECTION OUTPUT ;
    USE SIGNAL ;
    PORT
      LAYER M3 ;
        RECT  64.188 0 64.206 0.037 ;
    END
  END b[500]
  PIN b[501]
    DIRECTION OUTPUT ;
    USE SIGNAL ;
    PORT
      LAYER M3 ;
        RECT  64.26 0 64.278 0.037 ;
    END
  END b[501]
  PIN b[502]
    DIRECTION OUTPUT ;
    USE SIGNAL ;
    PORT
      LAYER M3 ;
        RECT  64.332 0 64.35 0.037 ;
    END
  END b[502]
  PIN b[503]
    DIRECTION OUTPUT ;
    USE SIGNAL ;
    PORT
      LAYER M3 ;
        RECT  64.404 0 64.422 0.037 ;
    END
  END b[503]
  PIN b[504]
    DIRECTION OUTPUT ;
    USE SIGNAL ;
    PORT
      LAYER M3 ;
        RECT  64.476 0 64.494 0.037 ;
    END
  END b[504]
  PIN b[505]
    DIRECTION OUTPUT ;
    USE SIGNAL ;
    PORT
      LAYER M3 ;
        RECT  64.548 0 64.566 0.037 ;
    END
  END b[505]
  PIN b[506]
    DIRECTION OUTPUT ;
    USE SIGNAL ;
    PORT
      LAYER M3 ;
        RECT  64.62 0 64.638 0.037 ;
    END
  END b[506]
  PIN b[507]
    DIRECTION OUTPUT ;
    USE SIGNAL ;
    PORT
      LAYER M3 ;
        RECT  64.692 0 64.71 0.037 ;
    END
  END b[507]
  PIN b[508]
    DIRECTION OUTPUT ;
    USE SIGNAL ;
    PORT
      LAYER M3 ;
        RECT  64.764 0 64.782 0.037 ;
    END
  END b[508]
  PIN b[509]
    DIRECTION OUTPUT ;
    USE SIGNAL ;
    PORT
      LAYER M3 ;
        RECT  64.836 0 64.854 0.037 ;
    END
  END b[509]
  PIN b[50]
    DIRECTION OUTPUT ;
    USE SIGNAL ;
    PORT
      LAYER M3 ;
        RECT  25.452 0 25.47 0.037 ;
    END
  END b[50]
  PIN b[510]
    DIRECTION OUTPUT ;
    USE SIGNAL ;
    PORT
      LAYER M3 ;
        RECT  64.908 0 64.926 0.037 ;
    END
  END b[510]
  PIN b[511]
    DIRECTION OUTPUT ;
    USE SIGNAL ;
    PORT
      LAYER M3 ;
        RECT  64.98 0 64.998 0.037 ;
    END
  END b[511]
  PIN b[512]
    DIRECTION OUTPUT ;
    USE SIGNAL ;
    PORT
      LAYER M3 ;
        RECT  26.46 0 26.478 0.037 ;
    END
  END b[512]
  PIN b[513]
    DIRECTION OUTPUT ;
    USE SIGNAL ;
    PORT
      LAYER M3 ;
        RECT  26.532 0 26.55 0.037 ;
    END
  END b[513]
  PIN b[514]
    DIRECTION OUTPUT ;
    USE SIGNAL ;
    PORT
      LAYER M3 ;
        RECT  26.604 0 26.622 0.037 ;
    END
  END b[514]
  PIN b[515]
    DIRECTION OUTPUT ;
    USE SIGNAL ;
    PORT
      LAYER M3 ;
        RECT  26.676 0 26.694 0.037 ;
    END
  END b[515]
  PIN b[516]
    DIRECTION OUTPUT ;
    USE SIGNAL ;
    PORT
      LAYER M3 ;
        RECT  26.748 0 26.766 0.037 ;
    END
  END b[516]
  PIN b[517]
    DIRECTION OUTPUT ;
    USE SIGNAL ;
    PORT
      LAYER M3 ;
        RECT  26.82 0 26.838 0.037 ;
    END
  END b[517]
  PIN b[518]
    DIRECTION OUTPUT ;
    USE SIGNAL ;
    PORT
      LAYER M3 ;
        RECT  26.892 0 26.91 0.037 ;
    END
  END b[518]
  PIN b[519]
    DIRECTION OUTPUT ;
    USE SIGNAL ;
    PORT
      LAYER M3 ;
        RECT  26.964 0 26.982 0.037 ;
    END
  END b[519]
  PIN b[51]
    DIRECTION OUTPUT ;
    USE SIGNAL ;
    PORT
      LAYER M3 ;
        RECT  25.524 0 25.542 0.037 ;
    END
  END b[51]
  PIN b[520]
    DIRECTION OUTPUT ;
    USE SIGNAL ;
    PORT
      LAYER M3 ;
        RECT  27.036 0 27.054 0.037 ;
    END
  END b[520]
  PIN b[521]
    DIRECTION OUTPUT ;
    USE SIGNAL ;
    PORT
      LAYER M3 ;
        RECT  27.108 0 27.126 0.037 ;
    END
  END b[521]
  PIN b[522]
    DIRECTION OUTPUT ;
    USE SIGNAL ;
    PORT
      LAYER M3 ;
        RECT  27.18 0 27.198 0.037 ;
    END
  END b[522]
  PIN b[523]
    DIRECTION OUTPUT ;
    USE SIGNAL ;
    PORT
      LAYER M3 ;
        RECT  27.252 0 27.27 0.037 ;
    END
  END b[523]
  PIN b[524]
    DIRECTION OUTPUT ;
    USE SIGNAL ;
    PORT
      LAYER M3 ;
        RECT  27.324 0 27.342 0.037 ;
    END
  END b[524]
  PIN b[525]
    DIRECTION OUTPUT ;
    USE SIGNAL ;
    PORT
      LAYER M3 ;
        RECT  27.396 0 27.414 0.037 ;
    END
  END b[525]
  PIN b[526]
    DIRECTION OUTPUT ;
    USE SIGNAL ;
    PORT
      LAYER M3 ;
        RECT  27.468 0 27.486 0.037 ;
    END
  END b[526]
  PIN b[527]
    DIRECTION OUTPUT ;
    USE SIGNAL ;
    PORT
      LAYER M3 ;
        RECT  27.54 0 27.558 0.037 ;
    END
  END b[527]
  PIN b[528]
    DIRECTION OUTPUT ;
    USE SIGNAL ;
    PORT
      LAYER M3 ;
        RECT  27.612 0 27.63 0.037 ;
    END
  END b[528]
  PIN b[529]
    DIRECTION OUTPUT ;
    USE SIGNAL ;
    PORT
      LAYER M3 ;
        RECT  27.684 0 27.702 0.037 ;
    END
  END b[529]
  PIN b[52]
    DIRECTION OUTPUT ;
    USE SIGNAL ;
    PORT
      LAYER M3 ;
        RECT  25.596 0 25.614 0.037 ;
    END
  END b[52]
  PIN b[530]
    DIRECTION OUTPUT ;
    USE SIGNAL ;
    PORT
      LAYER M3 ;
        RECT  27.756 0 27.774 0.037 ;
    END
  END b[530]
  PIN b[531]
    DIRECTION OUTPUT ;
    USE SIGNAL ;
    PORT
      LAYER M3 ;
        RECT  27.828 0 27.846 0.037 ;
    END
  END b[531]
  PIN b[532]
    DIRECTION OUTPUT ;
    USE SIGNAL ;
    PORT
      LAYER M3 ;
        RECT  27.9 0 27.918 0.037 ;
    END
  END b[532]
  PIN b[533]
    DIRECTION OUTPUT ;
    USE SIGNAL ;
    PORT
      LAYER M3 ;
        RECT  27.972 0 27.99 0.037 ;
    END
  END b[533]
  PIN b[534]
    DIRECTION OUTPUT ;
    USE SIGNAL ;
    PORT
      LAYER M3 ;
        RECT  28.044 0 28.062 0.037 ;
    END
  END b[534]
  PIN b[535]
    DIRECTION OUTPUT ;
    USE SIGNAL ;
    PORT
      LAYER M3 ;
        RECT  28.116 0 28.134 0.037 ;
    END
  END b[535]
  PIN b[536]
    DIRECTION OUTPUT ;
    USE SIGNAL ;
    PORT
      LAYER M3 ;
        RECT  28.188 0 28.206 0.037 ;
    END
  END b[536]
  PIN b[537]
    DIRECTION OUTPUT ;
    USE SIGNAL ;
    PORT
      LAYER M3 ;
        RECT  28.26 0 28.278 0.037 ;
    END
  END b[537]
  PIN b[538]
    DIRECTION OUTPUT ;
    USE SIGNAL ;
    PORT
      LAYER M3 ;
        RECT  28.332 0 28.35 0.037 ;
    END
  END b[538]
  PIN b[539]
    DIRECTION OUTPUT ;
    USE SIGNAL ;
    PORT
      LAYER M3 ;
        RECT  28.404 0 28.422 0.037 ;
    END
  END b[539]
  PIN b[53]
    DIRECTION OUTPUT ;
    USE SIGNAL ;
    PORT
      LAYER M3 ;
        RECT  25.668 0 25.686 0.037 ;
    END
  END b[53]
  PIN b[540]
    DIRECTION OUTPUT ;
    USE SIGNAL ;
    PORT
      LAYER M3 ;
        RECT  28.476 0 28.494 0.037 ;
    END
  END b[540]
  PIN b[541]
    DIRECTION OUTPUT ;
    USE SIGNAL ;
    PORT
      LAYER M3 ;
        RECT  28.548 0 28.566 0.037 ;
    END
  END b[541]
  PIN b[542]
    DIRECTION OUTPUT ;
    USE SIGNAL ;
    PORT
      LAYER M3 ;
        RECT  28.62 0 28.638 0.037 ;
    END
  END b[542]
  PIN b[543]
    DIRECTION OUTPUT ;
    USE SIGNAL ;
    PORT
      LAYER M3 ;
        RECT  28.692 0 28.71 0.037 ;
    END
  END b[543]
  PIN b[544]
    DIRECTION OUTPUT ;
    USE SIGNAL ;
    PORT
      LAYER M3 ;
        RECT  21.852 0 21.87 0.037 ;
    END
  END b[544]
  PIN b[545]
    DIRECTION OUTPUT ;
    USE SIGNAL ;
    PORT
      LAYER M3 ;
        RECT  21.924 0 21.942 0.037 ;
    END
  END b[545]
  PIN b[546]
    DIRECTION OUTPUT ;
    USE SIGNAL ;
    PORT
      LAYER M3 ;
        RECT  21.996 0 22.014 0.037 ;
    END
  END b[546]
  PIN b[547]
    DIRECTION OUTPUT ;
    USE SIGNAL ;
    PORT
      LAYER M3 ;
        RECT  22.068 0 22.086 0.037 ;
    END
  END b[547]
  PIN b[548]
    DIRECTION OUTPUT ;
    USE SIGNAL ;
    PORT
      LAYER M3 ;
        RECT  22.14 0 22.158 0.037 ;
    END
  END b[548]
  PIN b[549]
    DIRECTION OUTPUT ;
    USE SIGNAL ;
    PORT
      LAYER M3 ;
        RECT  22.212 0 22.23 0.037 ;
    END
  END b[549]
  PIN b[54]
    DIRECTION OUTPUT ;
    USE SIGNAL ;
    PORT
      LAYER M3 ;
        RECT  25.74 0 25.758 0.037 ;
    END
  END b[54]
  PIN b[550]
    DIRECTION OUTPUT ;
    USE SIGNAL ;
    PORT
      LAYER M3 ;
        RECT  22.284 0 22.302 0.037 ;
    END
  END b[550]
  PIN b[551]
    DIRECTION OUTPUT ;
    USE SIGNAL ;
    PORT
      LAYER M3 ;
        RECT  22.356 0 22.374 0.037 ;
    END
  END b[551]
  PIN b[552]
    DIRECTION OUTPUT ;
    USE SIGNAL ;
    PORT
      LAYER M3 ;
        RECT  22.428 0 22.446 0.037 ;
    END
  END b[552]
  PIN b[553]
    DIRECTION OUTPUT ;
    USE SIGNAL ;
    PORT
      LAYER M3 ;
        RECT  22.5 0 22.518 0.037 ;
    END
  END b[553]
  PIN b[554]
    DIRECTION OUTPUT ;
    USE SIGNAL ;
    PORT
      LAYER M3 ;
        RECT  22.572 0 22.59 0.037 ;
    END
  END b[554]
  PIN b[555]
    DIRECTION OUTPUT ;
    USE SIGNAL ;
    PORT
      LAYER M3 ;
        RECT  22.644 0 22.662 0.037 ;
    END
  END b[555]
  PIN b[556]
    DIRECTION OUTPUT ;
    USE SIGNAL ;
    PORT
      LAYER M3 ;
        RECT  22.716 0 22.734 0.037 ;
    END
  END b[556]
  PIN b[557]
    DIRECTION OUTPUT ;
    USE SIGNAL ;
    PORT
      LAYER M3 ;
        RECT  22.788 0 22.806 0.037 ;
    END
  END b[557]
  PIN b[558]
    DIRECTION OUTPUT ;
    USE SIGNAL ;
    PORT
      LAYER M3 ;
        RECT  22.86 0 22.878 0.037 ;
    END
  END b[558]
  PIN b[559]
    DIRECTION OUTPUT ;
    USE SIGNAL ;
    PORT
      LAYER M3 ;
        RECT  22.932 0 22.95 0.037 ;
    END
  END b[559]
  PIN b[55]
    DIRECTION OUTPUT ;
    USE SIGNAL ;
    PORT
      LAYER M3 ;
        RECT  25.812 0 25.83 0.037 ;
    END
  END b[55]
  PIN b[560]
    DIRECTION OUTPUT ;
    USE SIGNAL ;
    PORT
      LAYER M3 ;
        RECT  23.004 0 23.022 0.037 ;
    END
  END b[560]
  PIN b[561]
    DIRECTION OUTPUT ;
    USE SIGNAL ;
    PORT
      LAYER M3 ;
        RECT  23.076 0 23.094 0.037 ;
    END
  END b[561]
  PIN b[562]
    DIRECTION OUTPUT ;
    USE SIGNAL ;
    PORT
      LAYER M3 ;
        RECT  23.148 0 23.166 0.037 ;
    END
  END b[562]
  PIN b[563]
    DIRECTION OUTPUT ;
    USE SIGNAL ;
    PORT
      LAYER M3 ;
        RECT  23.22 0 23.238 0.037 ;
    END
  END b[563]
  PIN b[564]
    DIRECTION OUTPUT ;
    USE SIGNAL ;
    PORT
      LAYER M3 ;
        RECT  23.292 0 23.31 0.037 ;
    END
  END b[564]
  PIN b[565]
    DIRECTION OUTPUT ;
    USE SIGNAL ;
    PORT
      LAYER M3 ;
        RECT  23.364 0 23.382 0.037 ;
    END
  END b[565]
  PIN b[566]
    DIRECTION OUTPUT ;
    USE SIGNAL ;
    PORT
      LAYER M3 ;
        RECT  23.436 0 23.454 0.037 ;
    END
  END b[566]
  PIN b[567]
    DIRECTION OUTPUT ;
    USE SIGNAL ;
    PORT
      LAYER M3 ;
        RECT  23.508 0 23.526 0.037 ;
    END
  END b[567]
  PIN b[568]
    DIRECTION OUTPUT ;
    USE SIGNAL ;
    PORT
      LAYER M3 ;
        RECT  23.58 0 23.598 0.037 ;
    END
  END b[568]
  PIN b[569]
    DIRECTION OUTPUT ;
    USE SIGNAL ;
    PORT
      LAYER M3 ;
        RECT  23.652 0 23.67 0.037 ;
    END
  END b[569]
  PIN b[56]
    DIRECTION OUTPUT ;
    USE SIGNAL ;
    PORT
      LAYER M3 ;
        RECT  25.884 0 25.902 0.037 ;
    END
  END b[56]
  PIN b[570]
    DIRECTION OUTPUT ;
    USE SIGNAL ;
    PORT
      LAYER M3 ;
        RECT  23.724 0 23.742 0.037 ;
    END
  END b[570]
  PIN b[571]
    DIRECTION OUTPUT ;
    USE SIGNAL ;
    PORT
      LAYER M3 ;
        RECT  23.796 0 23.814 0.037 ;
    END
  END b[571]
  PIN b[572]
    DIRECTION OUTPUT ;
    USE SIGNAL ;
    PORT
      LAYER M3 ;
        RECT  23.868 0 23.886 0.037 ;
    END
  END b[572]
  PIN b[573]
    DIRECTION OUTPUT ;
    USE SIGNAL ;
    PORT
      LAYER M3 ;
        RECT  23.94 0 23.958 0.037 ;
    END
  END b[573]
  PIN b[574]
    DIRECTION OUTPUT ;
    USE SIGNAL ;
    PORT
      LAYER M3 ;
        RECT  24.012 0 24.03 0.037 ;
    END
  END b[574]
  PIN b[575]
    DIRECTION OUTPUT ;
    USE SIGNAL ;
    PORT
      LAYER M3 ;
        RECT  24.084 0 24.102 0.037 ;
    END
  END b[575]
  PIN b[576]
    DIRECTION OUTPUT ;
    USE SIGNAL ;
    PORT
      LAYER M3 ;
        RECT  17.244 0 17.262 0.037 ;
    END
  END b[576]
  PIN b[577]
    DIRECTION OUTPUT ;
    USE SIGNAL ;
    PORT
      LAYER M3 ;
        RECT  17.316 0 17.334 0.037 ;
    END
  END b[577]
  PIN b[578]
    DIRECTION OUTPUT ;
    USE SIGNAL ;
    PORT
      LAYER M3 ;
        RECT  17.388 0 17.406 0.037 ;
    END
  END b[578]
  PIN b[579]
    DIRECTION OUTPUT ;
    USE SIGNAL ;
    PORT
      LAYER M3 ;
        RECT  17.46 0 17.478 0.037 ;
    END
  END b[579]
  PIN b[57]
    DIRECTION OUTPUT ;
    USE SIGNAL ;
    PORT
      LAYER M3 ;
        RECT  25.956 0 25.974 0.037 ;
    END
  END b[57]
  PIN b[580]
    DIRECTION OUTPUT ;
    USE SIGNAL ;
    PORT
      LAYER M3 ;
        RECT  17.532 0 17.55 0.037 ;
    END
  END b[580]
  PIN b[581]
    DIRECTION OUTPUT ;
    USE SIGNAL ;
    PORT
      LAYER M3 ;
        RECT  17.604 0 17.622 0.037 ;
    END
  END b[581]
  PIN b[582]
    DIRECTION OUTPUT ;
    USE SIGNAL ;
    PORT
      LAYER M3 ;
        RECT  17.676 0 17.694 0.037 ;
    END
  END b[582]
  PIN b[583]
    DIRECTION OUTPUT ;
    USE SIGNAL ;
    PORT
      LAYER M3 ;
        RECT  17.748 0 17.766 0.037 ;
    END
  END b[583]
  PIN b[584]
    DIRECTION OUTPUT ;
    USE SIGNAL ;
    PORT
      LAYER M3 ;
        RECT  17.82 0 17.838 0.037 ;
    END
  END b[584]
  PIN b[585]
    DIRECTION OUTPUT ;
    USE SIGNAL ;
    PORT
      LAYER M3 ;
        RECT  17.892 0 17.91 0.037 ;
    END
  END b[585]
  PIN b[586]
    DIRECTION OUTPUT ;
    USE SIGNAL ;
    PORT
      LAYER M3 ;
        RECT  17.964 0 17.982 0.037 ;
    END
  END b[586]
  PIN b[587]
    DIRECTION OUTPUT ;
    USE SIGNAL ;
    PORT
      LAYER M3 ;
        RECT  18.036 0 18.054 0.037 ;
    END
  END b[587]
  PIN b[588]
    DIRECTION OUTPUT ;
    USE SIGNAL ;
    PORT
      LAYER M3 ;
        RECT  18.108 0 18.126 0.037 ;
    END
  END b[588]
  PIN b[589]
    DIRECTION OUTPUT ;
    USE SIGNAL ;
    PORT
      LAYER M3 ;
        RECT  18.18 0 18.198 0.037 ;
    END
  END b[589]
  PIN b[58]
    DIRECTION OUTPUT ;
    USE SIGNAL ;
    PORT
      LAYER M3 ;
        RECT  26.028 0 26.046 0.037 ;
    END
  END b[58]
  PIN b[590]
    DIRECTION OUTPUT ;
    USE SIGNAL ;
    PORT
      LAYER M3 ;
        RECT  18.252 0 18.27 0.037 ;
    END
  END b[590]
  PIN b[591]
    DIRECTION OUTPUT ;
    USE SIGNAL ;
    PORT
      LAYER M3 ;
        RECT  18.324 0 18.342 0.037 ;
    END
  END b[591]
  PIN b[592]
    DIRECTION OUTPUT ;
    USE SIGNAL ;
    PORT
      LAYER M3 ;
        RECT  18.396 0 18.414 0.037 ;
    END
  END b[592]
  PIN b[593]
    DIRECTION OUTPUT ;
    USE SIGNAL ;
    PORT
      LAYER M3 ;
        RECT  18.468 0 18.486 0.037 ;
    END
  END b[593]
  PIN b[594]
    DIRECTION OUTPUT ;
    USE SIGNAL ;
    PORT
      LAYER M3 ;
        RECT  18.54 0 18.558 0.037 ;
    END
  END b[594]
  PIN b[595]
    DIRECTION OUTPUT ;
    USE SIGNAL ;
    PORT
      LAYER M3 ;
        RECT  18.612 0 18.63 0.037 ;
    END
  END b[595]
  PIN b[596]
    DIRECTION OUTPUT ;
    USE SIGNAL ;
    PORT
      LAYER M3 ;
        RECT  18.684 0 18.702 0.037 ;
    END
  END b[596]
  PIN b[597]
    DIRECTION OUTPUT ;
    USE SIGNAL ;
    PORT
      LAYER M3 ;
        RECT  18.756 0 18.774 0.037 ;
    END
  END b[597]
  PIN b[598]
    DIRECTION OUTPUT ;
    USE SIGNAL ;
    PORT
      LAYER M3 ;
        RECT  18.828 0 18.846 0.037 ;
    END
  END b[598]
  PIN b[599]
    DIRECTION OUTPUT ;
    USE SIGNAL ;
    PORT
      LAYER M3 ;
        RECT  18.9 0 18.918 0.037 ;
    END
  END b[599]
  PIN b[59]
    DIRECTION OUTPUT ;
    USE SIGNAL ;
    PORT
      LAYER M3 ;
        RECT  26.1 0 26.118 0.037 ;
    END
  END b[59]
  PIN b[5]
    DIRECTION OUTPUT ;
    USE SIGNAL ;
    PORT
      LAYER M5 ;
        RECT  32.688 0 32.712 0.084 ;
    END
  END b[5]
  PIN b[60]
    DIRECTION OUTPUT ;
    USE SIGNAL ;
    PORT
      LAYER M3 ;
        RECT  26.172 0 26.19 0.037 ;
    END
  END b[60]
  PIN b[61]
    DIRECTION OUTPUT ;
    USE SIGNAL ;
    PORT
      LAYER M3 ;
        RECT  26.244 0 26.262 0.037 ;
    END
  END b[61]
  PIN b[62]
    DIRECTION OUTPUT ;
    USE SIGNAL ;
    PORT
      LAYER M3 ;
        RECT  26.316 0 26.334 0.037 ;
    END
  END b[62]
  PIN b[63]
    DIRECTION OUTPUT ;
    USE SIGNAL ;
    PORT
      LAYER M3 ;
        RECT  26.388 0 26.406 0.037 ;
    END
  END b[63]
  PIN b[64]
    DIRECTION OUTPUT ;
    USE SIGNAL ;
    PORT
      LAYER M3 ;
        RECT  40.86 0 40.878 0.037 ;
    END
  END b[64]
  PIN b[65]
    DIRECTION OUTPUT ;
    USE SIGNAL ;
    PORT
      LAYER M3 ;
        RECT  40.932 0 40.95 0.037 ;
    END
  END b[65]
  PIN b[66]
    DIRECTION OUTPUT ;
    USE SIGNAL ;
    PORT
      LAYER M3 ;
        RECT  41.004 0 41.022 0.037 ;
    END
  END b[66]
  PIN b[67]
    DIRECTION OUTPUT ;
    USE SIGNAL ;
    PORT
      LAYER M3 ;
        RECT  41.076 0 41.094 0.037 ;
    END
  END b[67]
  PIN b[68]
    DIRECTION OUTPUT ;
    USE SIGNAL ;
    PORT
      LAYER M3 ;
        RECT  41.148 0 41.166 0.037 ;
    END
  END b[68]
  PIN b[69]
    DIRECTION OUTPUT ;
    USE SIGNAL ;
    PORT
      LAYER M3 ;
        RECT  41.22 0 41.238 0.037 ;
    END
  END b[69]
  PIN b[6]
    DIRECTION OUTPUT ;
    USE SIGNAL ;
    PORT
      LAYER M5 ;
        RECT  32.784 0 32.808 0.084 ;
    END
  END b[6]
  PIN b[70]
    DIRECTION OUTPUT ;
    USE SIGNAL ;
    PORT
      LAYER M3 ;
        RECT  41.292 0 41.31 0.037 ;
    END
  END b[70]
  PIN b[71]
    DIRECTION OUTPUT ;
    USE SIGNAL ;
    PORT
      LAYER M3 ;
        RECT  41.364 0 41.382 0.037 ;
    END
  END b[71]
  PIN b[72]
    DIRECTION OUTPUT ;
    USE SIGNAL ;
    PORT
      LAYER M3 ;
        RECT  41.436 0 41.454 0.037 ;
    END
  END b[72]
  PIN b[73]
    DIRECTION OUTPUT ;
    USE SIGNAL ;
    PORT
      LAYER M3 ;
        RECT  41.508 0 41.526 0.037 ;
    END
  END b[73]
  PIN b[74]
    DIRECTION OUTPUT ;
    USE SIGNAL ;
    PORT
      LAYER M3 ;
        RECT  41.58 0 41.598 0.037 ;
    END
  END b[74]
  PIN b[75]
    DIRECTION OUTPUT ;
    USE SIGNAL ;
    PORT
      LAYER M3 ;
        RECT  41.652 0 41.67 0.037 ;
    END
  END b[75]
  PIN b[76]
    DIRECTION OUTPUT ;
    USE SIGNAL ;
    PORT
      LAYER M3 ;
        RECT  41.724 0 41.742 0.037 ;
    END
  END b[76]
  PIN b[77]
    DIRECTION OUTPUT ;
    USE SIGNAL ;
    PORT
      LAYER M3 ;
        RECT  41.796 0 41.814 0.037 ;
    END
  END b[77]
  PIN b[78]
    DIRECTION OUTPUT ;
    USE SIGNAL ;
    PORT
      LAYER M3 ;
        RECT  41.868 0 41.886 0.037 ;
    END
  END b[78]
  PIN b[79]
    DIRECTION OUTPUT ;
    USE SIGNAL ;
    PORT
      LAYER M3 ;
        RECT  41.94 0 41.958 0.037 ;
    END
  END b[79]
  PIN b[7]
    DIRECTION OUTPUT ;
    USE SIGNAL ;
    PORT
      LAYER M5 ;
        RECT  32.88 0 32.904 0.084 ;
    END
  END b[7]
  PIN b[80]
    DIRECTION OUTPUT ;
    USE SIGNAL ;
    PORT
      LAYER M3 ;
        RECT  42.012 0 42.03 0.037 ;
    END
  END b[80]
  PIN b[81]
    DIRECTION OUTPUT ;
    USE SIGNAL ;
    PORT
      LAYER M3 ;
        RECT  42.084 0 42.102 0.037 ;
    END
  END b[81]
  PIN b[82]
    DIRECTION OUTPUT ;
    USE SIGNAL ;
    PORT
      LAYER M3 ;
        RECT  42.156 0 42.174 0.037 ;
    END
  END b[82]
  PIN b[83]
    DIRECTION OUTPUT ;
    USE SIGNAL ;
    PORT
      LAYER M3 ;
        RECT  42.228 0 42.246 0.037 ;
    END
  END b[83]
  PIN b[84]
    DIRECTION OUTPUT ;
    USE SIGNAL ;
    PORT
      LAYER M3 ;
        RECT  42.3 0 42.318 0.037 ;
    END
  END b[84]
  PIN b[85]
    DIRECTION OUTPUT ;
    USE SIGNAL ;
    PORT
      LAYER M3 ;
        RECT  42.372 0 42.39 0.037 ;
    END
  END b[85]
  PIN b[86]
    DIRECTION OUTPUT ;
    USE SIGNAL ;
    PORT
      LAYER M3 ;
        RECT  42.444 0 42.462 0.037 ;
    END
  END b[86]
  PIN b[87]
    DIRECTION OUTPUT ;
    USE SIGNAL ;
    PORT
      LAYER M3 ;
        RECT  42.516 0 42.534 0.037 ;
    END
  END b[87]
  PIN b[88]
    DIRECTION OUTPUT ;
    USE SIGNAL ;
    PORT
      LAYER M3 ;
        RECT  42.588 0 42.606 0.037 ;
    END
  END b[88]
  PIN b[89]
    DIRECTION OUTPUT ;
    USE SIGNAL ;
    PORT
      LAYER M3 ;
        RECT  42.66 0 42.678 0.037 ;
    END
  END b[89]
  PIN b[8]
    DIRECTION OUTPUT ;
    USE SIGNAL ;
    PORT
      LAYER M5 ;
        RECT  32.976 0 33 0.084 ;
    END
  END b[8]
  PIN b[90]
    DIRECTION OUTPUT ;
    USE SIGNAL ;
    PORT
      LAYER M3 ;
        RECT  42.732 0 42.75 0.037 ;
    END
  END b[90]
  PIN b[91]
    DIRECTION OUTPUT ;
    USE SIGNAL ;
    PORT
      LAYER M3 ;
        RECT  42.804 0 42.822 0.037 ;
    END
  END b[91]
  PIN b[92]
    DIRECTION OUTPUT ;
    USE SIGNAL ;
    PORT
      LAYER M3 ;
        RECT  42.876 0 42.894 0.037 ;
    END
  END b[92]
  PIN b[93]
    DIRECTION OUTPUT ;
    USE SIGNAL ;
    PORT
      LAYER M3 ;
        RECT  42.948 0 42.966 0.037 ;
    END
  END b[93]
  PIN b[94]
    DIRECTION OUTPUT ;
    USE SIGNAL ;
    PORT
      LAYER M3 ;
        RECT  43.02 0 43.038 0.037 ;
    END
  END b[94]
  PIN b[95]
    DIRECTION OUTPUT ;
    USE SIGNAL ;
    PORT
      LAYER M3 ;
        RECT  43.092 0 43.11 0.037 ;
    END
  END b[95]
  PIN b[96]
    DIRECTION OUTPUT ;
    USE SIGNAL ;
    PORT
      LAYER M3 ;
        RECT  79.452 0 79.47 0.037 ;
    END
  END b[96]
  PIN b[97]
    DIRECTION OUTPUT ;
    USE SIGNAL ;
    PORT
      LAYER M3 ;
        RECT  79.524 0 79.542 0.037 ;
    END
  END b[97]
  PIN b[98]
    DIRECTION OUTPUT ;
    USE SIGNAL ;
    PORT
      LAYER M3 ;
        RECT  79.596 0 79.614 0.037 ;
    END
  END b[98]
  PIN b[99]
    DIRECTION OUTPUT ;
    USE SIGNAL ;
    PORT
      LAYER M3 ;
        RECT  79.668 0 79.686 0.037 ;
    END
  END b[99]
  PIN b[9]
    DIRECTION OUTPUT ;
    USE SIGNAL ;
    PORT
      LAYER M5 ;
        RECT  33.072 0 33.096 0.084 ;
    END
  END b[9]
  PIN ck
    DIRECTION INPUT ;
    USE SIGNAL ;
    PORT
      LAYER M4 ;
        RECT  104.004 29.52 104.088 29.544 ;
    END
  END ck
  PIN ck_s
    DIRECTION INPUT ;
    USE SIGNAL ;
    PORT
      LAYER M4 ;
        RECT  104.004 29.616 104.088 29.64 ;
    END
  END ck_s
  PIN en
    DIRECTION INPUT ;
    USE SIGNAL ;
    PORT
      LAYER M4 ;
        RECT  104.004 29.712 104.088 29.736 ;
    END
  END en
  PIN fault
    DIRECTION OUTPUT ;
    USE SIGNAL ;
    PORT
      LAYER M4 ;
        RECT  104.004 29.808 104.088 29.832 ;
    END
  END fault
  PIN k0
    DIRECTION INPUT ;
    USE SIGNAL ;
    PORT
      LAYER M4 ;
        RECT  104.004 29.904 104.088 29.928 ;
    END
  END k0
  PIN k1
    DIRECTION INPUT ;
    USE SIGNAL ;
    PORT
      LAYER M4 ;
        RECT  104.004 30 104.088 30.024 ;
    END
  END k1
  PIN k2
    DIRECTION INPUT ;
    USE SIGNAL ;
    PORT
      LAYER M4 ;
        RECT  104.004 30.096 104.088 30.12 ;
    END
  END k2
  PIN rs
    DIRECTION INPUT ;
    USE SIGNAL ;
    PORT
      LAYER M4 ;
        RECT  104.004 30.192 104.088 30.216 ;
    END
  END rs
  PIN tie_hi
    DIRECTION OUTPUT ;
    USE SIGNAL ;
    PORT
      LAYER M4 ;
        RECT  104.004 30.288 104.088 30.312 ;
    END
  END tie_hi
  PIN tie_lo
    DIRECTION OUTPUT ;
    USE SIGNAL ;
    PORT
      LAYER M4 ;
        RECT  104.004 30.384 104.088 30.408 ;
    END
  END tie_lo
  PIN VDD
    DIRECTION INOUT ;
    USE POWER ;
    PORT
      LAYER M5 ;
        RECT  99.792 2.151 99.912 58.073 ;
        RECT  97.092 2.151 97.212 58.073 ;
        RECT  94.392 2.151 94.512 58.073 ;
        RECT  91.692 2.151 91.812 58.073 ;
        RECT  88.992 2.151 89.112 58.073 ;
        RECT  86.292 2.151 86.412 58.073 ;
        RECT  83.592 2.151 83.712 58.073 ;
        RECT  80.892 2.151 81.012 58.073 ;
        RECT  78.192 2.151 78.312 58.073 ;
        RECT  75.492 2.151 75.612 58.073 ;
        RECT  72.792 2.151 72.912 58.073 ;
        RECT  70.092 2.151 70.212 58.073 ;
        RECT  67.392 2.151 67.512 58.073 ;
        RECT  64.692 2.151 64.812 58.073 ;
        RECT  61.992 2.151 62.112 58.073 ;
        RECT  59.292 2.151 59.412 58.073 ;
        RECT  56.592 2.151 56.712 58.073 ;
        RECT  53.892 2.151 54.012 58.073 ;
        RECT  51.192 2.151 51.312 58.073 ;
        RECT  48.492 2.151 48.612 58.073 ;
        RECT  45.792 2.151 45.912 58.073 ;
        RECT  43.092 2.151 43.212 58.073 ;
        RECT  40.392 2.151 40.512 58.073 ;
        RECT  37.692 2.151 37.812 58.073 ;
        RECT  34.992 2.151 35.112 58.073 ;
        RECT  32.292 2.151 32.412 58.073 ;
        RECT  29.592 2.151 29.712 58.073 ;
        RECT  26.892 2.151 27.012 58.073 ;
        RECT  24.192 2.151 24.312 58.073 ;
        RECT  21.492 2.151 21.612 58.073 ;
        RECT  18.792 2.151 18.912 58.073 ;
        RECT  16.092 2.151 16.212 58.073 ;
        RECT  13.392 2.151 13.512 58.073 ;
        RECT  10.692 2.151 10.812 58.073 ;
        RECT  7.992 2.151 8.112 58.073 ;
        RECT  5.292 2.151 5.412 58.073 ;
        RECT  2.592 2.151 2.712 58.073 ;
    END
  END VDD
  PIN VSS
    DIRECTION INOUT ;
    USE GROUND ;
    PORT
      LAYER M5 ;
        RECT  99.6 2.137 99.72 58.059 ;
        RECT  96.9 2.137 97.02 58.059 ;
        RECT  94.2 2.137 94.32 58.059 ;
        RECT  91.5 2.137 91.62 58.059 ;
        RECT  88.8 2.137 88.92 58.059 ;
        RECT  86.1 2.137 86.22 58.059 ;
        RECT  83.4 2.137 83.52 58.059 ;
        RECT  80.7 2.137 80.82 58.059 ;
        RECT  78 2.137 78.12 58.059 ;
        RECT  75.3 2.137 75.42 58.059 ;
        RECT  72.6 2.137 72.72 58.059 ;
        RECT  69.9 2.137 70.02 58.059 ;
        RECT  67.2 2.137 67.32 58.059 ;
        RECT  64.5 2.137 64.62 58.059 ;
        RECT  61.8 2.137 61.92 58.059 ;
        RECT  59.1 2.137 59.22 58.059 ;
        RECT  56.4 2.137 56.52 58.059 ;
        RECT  53.7 2.137 53.82 58.059 ;
        RECT  51 2.137 51.12 58.059 ;
        RECT  48.3 2.137 48.42 58.059 ;
        RECT  45.6 2.137 45.72 58.059 ;
        RECT  42.9 2.137 43.02 58.059 ;
        RECT  40.2 2.137 40.32 58.059 ;
        RECT  37.5 2.137 37.62 58.059 ;
        RECT  34.8 2.137 34.92 58.059 ;
        RECT  32.1 2.137 32.22 58.059 ;
        RECT  29.4 2.137 29.52 58.059 ;
        RECT  26.7 2.137 26.82 58.059 ;
        RECT  24 2.137 24.12 58.059 ;
        RECT  21.3 2.137 21.42 58.059 ;
        RECT  18.6 2.137 18.72 58.059 ;
        RECT  15.9 2.137 16.02 58.059 ;
        RECT  13.2 2.137 13.32 58.059 ;
        RECT  10.5 2.137 10.62 58.059 ;
        RECT  7.8 2.137 7.92 58.059 ;
        RECT  5.1 2.137 5.22 58.059 ;
        RECT  2.4 2.137 2.52 58.059 ;
    END
  END VSS
  OBS
    LAYER RVTN ;
     RECT  2.16 2.16 101.898 2.295 ;
     RECT  2.16 2.565 101.898 2.835 ;
     RECT  2.16 3.105 101.898 3.375 ;
     RECT  2.16 3.645 101.898 3.915 ;
     RECT  2.16 4.185 101.898 4.455 ;
     RECT  2.16 4.725 101.898 4.995 ;
     RECT  2.16 5.265 101.898 5.535 ;
     RECT  2.16 5.805 101.898 6.075 ;
     RECT  2.16 6.345 101.898 6.615 ;
     RECT  2.16 6.885 101.898 7.155 ;
     RECT  2.16 7.425 101.898 7.695 ;
     RECT  2.16 7.965 101.898 8.235 ;
     RECT  2.16 8.505 101.898 8.775 ;
     RECT  2.16 9.045 101.898 9.315 ;
     RECT  2.16 9.585 101.898 9.855 ;
     RECT  2.16 10.125 101.898 10.395 ;
     RECT  2.16 10.665 101.898 10.935 ;
     RECT  2.16 11.205 101.898 11.475 ;
     RECT  2.16 11.745 101.898 12.015 ;
     RECT  2.16 12.285 101.898 12.555 ;
     RECT  2.16 12.825 101.898 13.095 ;
     RECT  2.16 13.365 101.898 13.635 ;
     RECT  2.16 13.905 101.898 14.175 ;
     RECT  2.16 14.445 101.898 14.715 ;
     RECT  2.16 14.985 101.898 15.255 ;
     RECT  2.16 15.525 101.898 15.795 ;
     RECT  2.16 16.065 101.898 16.335 ;
     RECT  2.16 16.605 101.898 16.875 ;
     RECT  2.16 17.145 101.898 17.415 ;
     RECT  2.16 17.685 101.898 17.955 ;
     RECT  2.16 18.225 101.898 18.495 ;
     RECT  2.16 18.765 101.898 19.035 ;
     RECT  2.16 19.305 101.898 19.575 ;
     RECT  2.16 19.845 101.898 20.115 ;
     RECT  2.16 20.385 101.898 20.655 ;
     RECT  2.16 20.925 101.898 21.195 ;
     RECT  2.16 21.465 101.898 21.735 ;
     RECT  2.16 22.005 101.898 22.275 ;
     RECT  2.16 22.545 101.898 22.815 ;
     RECT  2.16 23.085 101.898 23.355 ;
     RECT  2.16 23.625 101.898 23.895 ;
     RECT  2.16 24.165 101.898 24.435 ;
     RECT  2.16 24.705 101.898 24.975 ;
     RECT  2.16 25.245 101.898 25.515 ;
     RECT  2.16 25.785 101.898 26.055 ;
     RECT  2.16 26.325 101.898 26.595 ;
     RECT  2.16 26.865 101.898 27.135 ;
     RECT  2.16 27.405 101.898 27.675 ;
     RECT  2.16 27.945 101.898 28.215 ;
     RECT  2.16 28.485 101.898 28.755 ;
     RECT  2.16 29.025 101.898 29.295 ;
     RECT  2.16 29.565 101.898 29.835 ;
     RECT  2.16 30.105 101.898 30.375 ;
     RECT  2.16 30.645 101.898 30.915 ;
     RECT  2.16 31.185 101.898 31.455 ;
     RECT  2.16 31.725 101.898 31.995 ;
     RECT  2.16 32.265 101.898 32.535 ;
     RECT  2.16 32.805 101.898 33.075 ;
     RECT  2.16 33.345 101.898 33.615 ;
     RECT  2.16 33.885 101.898 34.155 ;
     RECT  2.16 34.425 101.898 34.695 ;
     RECT  2.16 34.965 101.898 35.235 ;
     RECT  2.16 35.505 101.898 35.775 ;
     RECT  2.16 36.045 101.898 36.315 ;
     RECT  2.16 36.585 101.898 36.855 ;
     RECT  2.16 37.125 101.898 37.395 ;
     RECT  2.16 37.665 101.898 37.935 ;
     RECT  2.16 38.205 101.898 38.475 ;
     RECT  2.16 38.745 101.898 39.015 ;
     RECT  2.16 39.285 101.898 39.555 ;
     RECT  2.16 39.825 101.898 40.095 ;
     RECT  2.16 40.365 101.898 40.635 ;
     RECT  2.16 40.905 101.898 41.175 ;
     RECT  2.16 41.445 101.898 41.715 ;
     RECT  2.16 41.985 101.898 42.255 ;
     RECT  2.16 42.525 101.898 42.795 ;
     RECT  2.16 43.065 101.898 43.335 ;
     RECT  2.16 43.605 101.898 43.875 ;
     RECT  2.16 44.145 101.898 44.415 ;
     RECT  2.16 44.685 101.898 44.955 ;
     RECT  2.16 45.225 101.898 45.495 ;
     RECT  2.16 45.765 101.898 46.035 ;
     RECT  2.16 46.305 101.898 46.575 ;
     RECT  2.16 46.845 101.898 47.115 ;
     RECT  2.16 47.385 101.898 47.655 ;
     RECT  2.16 47.925 101.898 48.195 ;
     RECT  2.16 48.465 101.898 48.735 ;
     RECT  2.16 49.005 101.898 49.275 ;
     RECT  2.16 49.545 101.898 49.815 ;
     RECT  2.16 50.085 101.898 50.355 ;
     RECT  2.16 50.625 101.898 50.895 ;
     RECT  2.16 51.165 101.898 51.435 ;
     RECT  2.16 51.705 101.898 51.975 ;
     RECT  2.16 52.245 101.898 52.515 ;
     RECT  2.16 52.785 101.898 53.055 ;
     RECT  2.16 53.325 101.898 53.595 ;
     RECT  2.16 53.865 101.898 54.135 ;
     RECT  2.16 54.405 101.898 54.675 ;
     RECT  2.16 54.945 101.898 55.215 ;
     RECT  2.16 55.485 101.898 55.755 ;
     RECT  2.16 56.025 101.898 56.295 ;
     RECT  2.16 56.565 101.898 56.835 ;
     RECT  2.16 57.105 101.898 57.375 ;
     RECT  2.16 57.645 101.898 57.915 ;
    LAYER RVTP ;
     RECT  2.16 2.295 101.898 2.565 ;
     RECT  2.16 2.835 101.898 3.105 ;
     RECT  2.16 3.375 101.898 3.645 ;
     RECT  2.16 3.915 101.898 4.185 ;
     RECT  2.16 4.455 101.898 4.725 ;
     RECT  2.16 4.995 101.898 5.265 ;
     RECT  2.16 5.535 101.898 5.805 ;
     RECT  2.16 6.075 101.898 6.345 ;
     RECT  2.16 6.615 101.898 6.885 ;
     RECT  2.16 7.155 101.898 7.425 ;
     RECT  2.16 7.695 101.898 7.965 ;
     RECT  2.16 8.235 101.898 8.505 ;
     RECT  2.16 8.775 101.898 9.045 ;
     RECT  2.16 9.315 101.898 9.585 ;
     RECT  2.16 9.855 101.898 10.125 ;
     RECT  2.16 10.395 101.898 10.665 ;
     RECT  2.16 10.935 101.898 11.205 ;
     RECT  2.16 11.475 101.898 11.745 ;
     RECT  2.16 12.015 101.898 12.285 ;
     RECT  2.16 12.555 101.898 12.825 ;
     RECT  2.16 13.095 101.898 13.365 ;
     RECT  2.16 13.635 101.898 13.905 ;
     RECT  2.16 14.175 101.898 14.445 ;
     RECT  2.16 14.715 101.898 14.985 ;
     RECT  2.16 15.255 101.898 15.525 ;
     RECT  2.16 15.795 101.898 16.065 ;
     RECT  2.16 16.335 101.898 16.605 ;
     RECT  2.16 16.875 101.898 17.145 ;
     RECT  2.16 17.415 101.898 17.685 ;
     RECT  2.16 17.955 101.898 18.225 ;
     RECT  2.16 18.495 101.898 18.765 ;
     RECT  2.16 19.035 101.898 19.305 ;
     RECT  2.16 19.575 101.898 19.845 ;
     RECT  2.16 20.115 101.898 20.385 ;
     RECT  2.16 20.655 101.898 20.925 ;
     RECT  2.16 21.195 101.898 21.465 ;
     RECT  2.16 21.735 101.898 22.005 ;
     RECT  2.16 22.275 101.898 22.545 ;
     RECT  2.16 22.815 101.898 23.085 ;
     RECT  2.16 23.355 101.898 23.625 ;
     RECT  2.16 23.895 101.898 24.165 ;
     RECT  2.16 24.435 101.898 24.705 ;
     RECT  2.16 24.975 101.898 25.245 ;
     RECT  2.16 25.515 101.898 25.785 ;
     RECT  2.16 26.055 101.898 26.325 ;
     RECT  2.16 26.595 101.898 26.865 ;
     RECT  2.16 27.135 101.898 27.405 ;
     RECT  2.16 27.675 101.898 27.945 ;
     RECT  2.16 28.215 101.898 28.485 ;
     RECT  2.16 28.755 101.898 29.025 ;
     RECT  2.16 29.295 101.898 29.565 ;
     RECT  2.16 29.835 101.898 30.105 ;
     RECT  2.16 30.375 101.898 30.645 ;
     RECT  2.16 30.915 101.898 31.185 ;
     RECT  2.16 31.455 101.898 31.725 ;
     RECT  2.16 31.995 101.898 32.265 ;
     RECT  2.16 32.535 101.898 32.805 ;
     RECT  2.16 33.075 101.898 33.345 ;
     RECT  2.16 33.615 101.898 33.885 ;
     RECT  2.16 34.155 101.898 34.425 ;
     RECT  2.16 34.695 101.898 34.965 ;
     RECT  2.16 35.235 101.898 35.505 ;
     RECT  2.16 35.775 101.898 36.045 ;
     RECT  2.16 36.315 101.898 36.585 ;
     RECT  2.16 36.855 101.898 37.125 ;
     RECT  2.16 37.395 101.898 37.665 ;
     RECT  2.16 37.935 101.898 38.205 ;
     RECT  2.16 38.475 101.898 38.745 ;
     RECT  2.16 39.015 101.898 39.285 ;
     RECT  2.16 39.555 101.898 39.825 ;
     RECT  2.16 40.095 101.898 40.365 ;
     RECT  2.16 40.635 101.898 40.905 ;
     RECT  2.16 41.175 101.898 41.445 ;
     RECT  2.16 41.715 101.898 41.985 ;
     RECT  2.16 42.255 101.898 42.525 ;
     RECT  2.16 42.795 101.898 43.065 ;
     RECT  2.16 43.335 101.898 43.605 ;
     RECT  2.16 43.875 101.898 44.145 ;
     RECT  2.16 44.415 101.898 44.685 ;
     RECT  2.16 44.955 101.898 45.225 ;
     RECT  2.16 45.495 101.898 45.765 ;
     RECT  2.16 46.035 101.898 46.305 ;
     RECT  2.16 46.575 101.898 46.845 ;
     RECT  2.16 47.115 101.898 47.385 ;
     RECT  2.16 47.655 101.898 47.925 ;
     RECT  2.16 48.195 101.898 48.465 ;
     RECT  2.16 48.735 101.898 49.005 ;
     RECT  2.16 49.275 101.898 49.545 ;
     RECT  2.16 49.815 101.898 50.085 ;
     RECT  2.16 50.355 101.898 50.625 ;
     RECT  2.16 50.895 101.898 51.165 ;
     RECT  2.16 51.435 101.898 51.705 ;
     RECT  2.16 51.975 101.898 52.245 ;
     RECT  2.16 52.515 101.898 52.785 ;
     RECT  2.16 53.055 101.898 53.325 ;
     RECT  2.16 53.595 101.898 53.865 ;
     RECT  2.16 54.135 101.898 54.405 ;
     RECT  2.16 54.675 101.898 54.945 ;
     RECT  2.16 55.215 101.898 55.485 ;
     RECT  2.16 55.755 101.898 56.025 ;
     RECT  2.16 56.295 101.898 56.565 ;
     RECT  2.16 56.835 101.898 57.105 ;
     RECT  2.16 57.375 101.898 57.645 ;
     RECT  2.16 57.915 101.898 58.05 ;
    LAYER M1 ;
     RECT  2.16 2.151 101.898 58.059 ;
    LAYER M2 ;
     RECT  2.16 2.151 14.647 58.059 ;
     RECT  14.647 2.106 14.827 58.059 ;
     RECT  14.827 2.07 15.187 58.059 ;
     RECT  15.115 0.18 15.871 0.198 ;
     RECT  15.871 0.108 16.303 0.198 ;
     RECT  16.303 0.108 17.023 0.864 ;
     RECT  15.187 1.881 17.095 58.059 ;
     RECT  17.023 0.036 17.167 0.864 ;
     RECT  17.095 1.836 17.167 58.059 ;
     RECT  20.191 60.39 20.227 60.408 ;
     RECT  20.227 60.354 20.551 60.408 ;
     RECT  20.551 60.201 20.731 60.408 ;
     RECT  20.731 60.156 21.343 60.408 ;
     RECT  21.343 59.814 21.631 60.408 ;
     RECT  21.631 59.742 22.703 60.408 ;
     RECT  22.703 60.201 22.811 60.408 ;
     RECT  22.811 60.39 23.575 60.408 ;
     RECT  23.575 60.318 23.675 60.408 ;
     RECT  17.167 0.036 23.935 58.059 ;
     RECT  23.935 0.036 24.079 58.104 ;
     RECT  24.079 0.036 24.179 58.176 ;
     RECT  23.675 60.354 24.431 60.408 ;
     RECT  24.179 0.036 24.827 0.324 ;
     RECT  24.827 0.036 25.115 0.279 ;
     RECT  24.431 60.39 25.231 60.408 ;
     RECT  25.115 0.036 25.259 0.126 ;
     RECT  24.179 1.152 25.295 58.176 ;
     RECT  25.231 60.318 25.411 60.408 ;
     RECT  25.295 2.034 25.447 58.176 ;
     RECT  25.447 2.034 25.511 58.716 ;
     RECT  25.411 60.246 25.835 60.408 ;
     RECT  25.259 0.036 26.275 0.054 ;
     RECT  25.835 60.318 26.375 60.408 ;
     RECT  25.295 1.152 26.447 1.278 ;
     RECT  26.375 60.318 26.519 60.336 ;
     RECT  25.511 2.151 26.527 58.716 ;
     RECT  26.275 0.036 27.175 0.126 ;
     RECT  26.527 1.422 27.275 58.716 ;
     RECT  27.275 1.422 27.571 58.14 ;
     RECT  27.571 1.224 27.679 58.14 ;
     RECT  27.175 0.036 27.823 0.162 ;
     RECT  27.823 0.036 27.895 0.198 ;
     RECT  27.895 0.036 28.255 0.279 ;
     RECT  27.679 1.152 28.255 58.14 ;
     RECT  28.255 0.036 28.499 58.14 ;
     RECT  28.499 0.036 28.643 0.549 ;
     RECT  28.643 0.072 29.731 0.549 ;
     RECT  28.499 1.422 29.731 58.14 ;
     RECT  29.731 0.072 31.127 58.14 ;
     RECT  31.127 0.144 31.559 58.14 ;
     RECT  31.559 0.846 31.919 58.14 ;
     RECT  32.503 0.036 32.791 0.054 ;
     RECT  31.919 0.846 32.791 0.9 ;
     RECT  31.919 1.728 32.791 58.14 ;
     RECT  32.791 0.036 33.071 58.14 ;
     RECT  33.071 1.728 33.431 58.14 ;
     RECT  33.071 0.036 34.375 0.9 ;
     RECT  33.431 1.728 34.375 58.104 ;
     RECT  34.375 0.036 34.475 58.104 ;
     RECT  34.475 1.836 35.167 58.104 ;
     RECT  35.167 1.836 35.375 58.14 ;
     RECT  34.475 0.036 36.383 0.9 ;
     RECT  36.383 0.882 36.499 0.9 ;
     RECT  35.375 1.881 36.499 58.14 ;
     RECT  36.499 0.882 36.599 58.14 ;
     RECT  36.599 1.881 36.779 58.14 ;
     RECT  36.751 60.246 36.895 60.264 ;
     RECT  36.895 60.246 37.075 60.408 ;
     RECT  37.075 59.778 37.247 60.408 ;
     RECT  36.383 0.036 37.931 0.126 ;
     RECT  37.931 0.036 38.003 0.09 ;
     RECT  38.003 0.072 38.219 0.09 ;
     RECT  37.247 60.246 38.335 60.408 ;
     RECT  38.335 59.778 38.435 60.408 ;
     RECT  38.435 60.246 38.507 60.408 ;
     RECT  36.599 0.882 38.687 0.9 ;
     RECT  36.779 1.962 38.903 58.14 ;
     RECT  38.507 60.39 39.155 60.408 ;
     RECT  38.903 2.151 39.263 58.14 ;
     RECT  39.263 2.151 39.947 58.104 ;
     RECT  41.035 0.18 41.071 0.198 ;
     RECT  41.071 0.18 41.143 0.234 ;
     RECT  41.143 0.108 41.215 0.234 ;
     RECT  39.947 2.151 41.431 58.059 ;
     RECT  41.431 2.106 41.683 58.059 ;
     RECT  41.683 1.8 41.719 58.059 ;
     RECT  41.719 1.728 41.863 58.059 ;
     RECT  41.863 1.728 41.927 58.104 ;
     RECT  41.927 2.034 41.935 58.104 ;
     RECT  41.971 60.318 42.007 60.336 ;
     RECT  41.935 2.034 42.035 58.176 ;
     RECT  42.007 60.246 42.107 60.336 ;
     RECT  42.107 60.246 42.115 60.3 ;
     RECT  41.215 0.036 42.655 0.234 ;
     RECT  42.655 0.036 42.755 0.324 ;
     RECT  42.115 60.156 42.827 60.3 ;
     RECT  42.827 60.246 42.835 60.3 ;
     RECT  42.835 60.246 42.943 60.336 ;
     RECT  42.943 60.246 43.079 60.408 ;
     RECT  42.035 2.034 43.087 58.059 ;
     RECT  43.087 2.034 43.259 58.14 ;
     RECT  42.755 0.036 43.295 0.126 ;
     RECT  43.295 0.108 43.331 0.126 ;
     RECT  43.079 60.246 43.331 60.264 ;
     RECT  43.259 2.034 44.663 58.059 ;
     RECT  44.663 2.07 44.951 58.059 ;
     RECT  44.951 2.106 45.203 58.059 ;
     RECT  46.759 60.246 46.831 60.264 ;
     RECT  46.831 60.246 46.903 60.336 ;
     RECT  45.203 2.151 47.155 58.059 ;
     RECT  46.903 60.246 47.291 60.408 ;
     RECT  47.155 2.106 47.407 58.059 ;
     RECT  47.407 1.836 47.947 58.059 ;
     RECT  47.291 60.318 48.947 60.408 ;
     RECT  48.947 60.318 48.983 60.336 ;
     RECT  47.947 1.8 49.559 58.059 ;
     RECT  49.559 1.836 50.279 58.059 ;
     RECT  47.731 0.036 50.719 0.054 ;
     RECT  50.279 2.034 51.035 58.059 ;
     RECT  50.719 0.036 51.439 0.198 ;
     RECT  50.827 1.152 51.439 1.17 ;
     RECT  51.439 0.036 51.647 1.17 ;
     RECT  51.035 2.151 52.087 58.059 ;
     RECT  51.647 0.036 52.403 0.864 ;
     RECT  52.087 2.034 52.447 58.059 ;
     RECT  52.403 0.036 54.203 0.09 ;
     RECT  54.203 0.036 55.319 0.054 ;
     RECT  52.447 1.962 55.355 58.059 ;
     RECT  52.403 0.846 55.787 0.864 ;
     RECT  55.355 2.151 56.731 58.059 ;
     RECT  56.731 2.106 57.019 58.059 ;
     RECT  57.019 2.034 57.487 58.059 ;
     RECT  57.955 1.116 57.991 1.134 ;
     RECT  57.415 0.036 58.027 0.054 ;
     RECT  57.991 0.846 58.027 1.134 ;
     RECT  58.027 0.036 58.099 1.134 ;
     RECT  57.487 1.881 58.099 58.059 ;
     RECT  58.099 0.036 60.539 58.059 ;
     RECT  60.655 60.39 60.971 60.408 ;
     RECT  60.539 0.072 61.339 58.059 ;
     RECT  62.383 59.778 62.483 59.796 ;
     RECT  61.339 0.036 62.491 58.059 ;
     RECT  62.635 59.814 62.743 59.832 ;
     RECT  62.743 59.814 62.771 60.408 ;
     RECT  62.771 60.246 63.059 60.408 ;
     RECT  63.059 60.246 63.275 60.264 ;
     RECT  62.491 0.036 63.347 58.716 ;
     RECT  63.751 59.778 63.851 59.796 ;
     RECT  63.347 0.036 64.759 58.059 ;
     RECT  64.759 0.036 64.895 58.14 ;
     RECT  64.895 0.036 65.111 58.059 ;
     RECT  65.011 60.282 65.119 60.3 ;
     RECT  65.119 60.201 65.299 60.3 ;
     RECT  65.299 60.156 65.371 60.3 ;
     RECT  65.371 60.156 65.435 60.408 ;
     RECT  65.435 60.282 65.795 60.3 ;
     RECT  65.111 0.072 66.199 58.059 ;
     RECT  66.199 0.036 66.407 58.059 ;
     RECT  66.271 60.246 66.559 60.264 ;
     RECT  66.559 60.246 66.991 60.408 ;
     RECT  66.991 60.201 67.091 60.408 ;
     RECT  66.407 0.036 67.135 0.279 ;
     RECT  66.407 1.152 67.135 58.059 ;
     RECT  67.091 60.246 67.199 60.408 ;
     RECT  67.199 60.246 67.235 60.3 ;
     RECT  67.235 60.246 67.667 60.264 ;
     RECT  67.135 0.036 68.287 58.059 ;
     RECT  68.287 0.036 68.711 58.176 ;
     RECT  68.711 2.151 68.863 58.176 ;
     RECT  68.071 60.39 68.863 60.408 ;
     RECT  68.711 0.036 68.927 1.314 ;
     RECT  68.863 2.151 68.963 58.212 ;
     RECT  68.863 60.318 69.079 60.408 ;
     RECT  69.079 60.246 69.467 60.408 ;
     RECT  68.927 0.036 70.123 1.278 ;
     RECT  68.963 2.151 70.123 58.059 ;
     RECT  70.123 0.036 70.151 58.059 ;
     RECT  70.151 0.576 71.051 58.059 ;
     RECT  71.051 1.224 71.303 58.059 ;
     RECT  71.303 1.224 71.735 1.242 ;
     RECT  71.303 2.106 72.139 58.059 ;
     RECT  72.139 2.07 72.391 58.059 ;
     RECT  72.607 0.576 72.643 0.594 ;
     RECT  72.643 0.18 72.679 0.594 ;
     RECT  72.391 1.836 72.751 58.059 ;
     RECT  72.679 0.18 73.039 0.666 ;
     RECT  72.751 1.422 73.039 58.059 ;
     RECT  73.039 0.18 73.255 58.059 ;
     RECT  73.255 0.108 73.327 58.059 ;
     RECT  73.327 0.036 74.831 58.059 ;
     RECT  74.831 0.108 75.011 58.059 ;
     RECT  75.011 0.18 77.027 58.059 ;
     RECT  77.027 0.846 77.927 58.059 ;
     RECT  77.927 0.846 78.359 1.008 ;
     RECT  78.359 0.99 78.539 1.008 ;
     RECT  77.927 1.836 78.575 58.059 ;
     RECT  79.339 0.18 79.519 0.198 ;
     RECT  79.519 0.108 79.591 0.198 ;
     RECT  79.591 0.036 79.691 0.198 ;
     RECT  79.951 60.39 80.023 60.408 ;
     RECT  80.023 60.318 80.159 60.408 ;
     RECT  80.159 60.318 80.195 60.336 ;
     RECT  78.575 2.151 80.383 58.059 ;
     RECT  79.691 0.036 80.455 0.054 ;
     RECT  80.383 2.106 81.175 58.059 ;
     RECT  80.455 0.036 81.239 0.594 ;
     RECT  81.175 2.106 81.247 58.176 ;
     RECT  81.247 2.034 81.391 58.176 ;
     RECT  81.391 2.034 81.463 58.716 ;
     RECT  81.319 60.39 81.607 60.408 ;
     RECT  81.239 0.036 81.779 0.126 ;
     RECT  81.463 1.962 81.887 58.716 ;
     RECT  81.607 60.318 81.895 60.408 ;
     RECT  81.779 0.108 81.995 0.126 ;
     RECT  81.895 60.246 82.067 60.408 ;
     RECT  81.887 1.962 82.283 58.176 ;
     RECT  82.067 60.39 82.499 60.408 ;
     RECT  81.319 1.152 83.183 1.17 ;
     RECT  82.283 1.962 83.723 58.059 ;
     RECT  83.723 2.151 86.575 58.059 ;
     RECT  86.575 2.106 86.935 58.059 ;
     RECT  86.935 2.034 88.007 58.059 ;
     RECT  88.007 2.106 88.735 58.059 ;
     RECT  88.735 2.034 90.095 58.059 ;
     RECT  90.095 2.106 91.471 58.059 ;
     RECT  91.471 1.728 91.571 58.059 ;
     RECT  91.435 0.036 91.759 0.054 ;
     RECT  91.571 2.106 92.407 58.059 ;
     RECT  91.759 0.036 92.551 0.198 ;
     RECT  92.407 2.034 92.983 58.059 ;
     RECT  92.983 1.998 93.055 58.059 ;
     RECT  93.055 1.926 93.343 58.059 ;
     RECT  92.551 0.036 94.955 0.594 ;
     RECT  94.955 0.036 96.367 0.09 ;
     RECT  93.343 1.881 96.511 58.059 ;
     RECT  96.367 0.036 96.727 0.126 ;
     RECT  96.727 0.036 96.863 0.279 ;
     RECT  96.511 1.728 96.907 58.059 ;
     RECT  96.863 0.036 97.151 0.234 ;
     RECT  96.907 1.422 97.231 58.059 ;
     RECT  97.231 1.224 97.303 58.059 ;
     RECT  97.303 1.152 97.475 58.059 ;
     RECT  97.151 0.036 98.311 0.126 ;
     RECT  98.311 0.036 98.411 0.234 ;
     RECT  98.411 0.036 98.483 0.126 ;
     RECT  98.483 0.036 100.327 0.09 ;
     RECT  100.327 0.036 100.715 0.162 ;
     RECT  100.715 0.144 100.859 0.162 ;
     RECT  97.475 1.422 100.931 58.059 ;
     RECT  100.931 2.151 101.898 58.059 ;
     RECT  101.898 29.88 102.623 31.248 ;
     RECT  102.623 30.006 102.659 31.248 ;
     RECT  102.659 30.618 103.199 31.248 ;
     RECT  103.199 31.23 103.235 31.248 ;
    LAYER M3 ;
     RECT  17.244 0.012 18.918 0.031 ;
     RECT  40.86 0.012 43.11 0.031 ;
     RECT  60.444 0.012 69.606 0.031 ;
     RECT  72.54 0.012 74.79 0.031 ;
     RECT  79.452 0.012 81.702 0.031 ;
     RECT  91.548 0.012 93.798 0.031 ;
     RECT  96.156 0.012 98.406 0.031 ;
     RECT  47.736 0.031 47.754 0.043 ;
     RECT  96.084 0.031 98.406 0.043 ;
     RECT  100.692 0.031 100.71 0.043 ;
     RECT  21.852 0.012 28.71 0.067 ;
     RECT  31.068 0.043 31.086 0.067 ;
     RECT  32.508 0.031 32.526 0.067 ;
     RECT  37.98 0.031 37.998 0.067 ;
     RECT  100.692 0.043 101.106 0.067 ;
     RECT  31.068 0.067 31.122 0.091 ;
     RECT  32.508 0.067 32.922 0.091 ;
     RECT  47.52 0.043 47.754 0.091 ;
     RECT  50.652 0.012 52.902 0.091 ;
     RECT  59.652 0.031 70.146 0.091 ;
     RECT  72.54 0.031 74.826 0.091 ;
     RECT  91.44 0.031 93.798 0.095 ;
     RECT  37.98 0.067 38.214 0.103 ;
     RECT  40.86 0.031 43.29 0.103 ;
     RECT  72.18 0.091 74.826 0.103 ;
     RECT  79.452 0.031 81.774 0.103 ;
     RECT  95.508 0.043 98.406 0.103 ;
     RECT  17.028 0.031 18.918 0.139 ;
     RECT  72.18 0.103 75.006 0.139 ;
     RECT  100.332 0.067 101.106 0.167 ;
     RECT  30.924 0.091 32.922 0.173 ;
     RECT  77.292 0.139 77.31 0.175 ;
     RECT  79.452 0.103 81.99 0.175 ;
     RECT  32.904 0.173 32.922 0.187 ;
     RECT  37.908 0.103 38.214 0.187 ;
     RECT  21.708 0.067 28.746 0.203 ;
     RECT  34.38 0.091 34.398 0.235 ;
     RECT  75.96 0.187 75.978 0.235 ;
     RECT  29.736 0.091 29.754 0.256 ;
     RECT  29.736 0.256 29.862 0.301 ;
     RECT  32.904 0.187 33.102 0.317 ;
     RECT  29.736 0.301 30.042 0.373 ;
     RECT  30.924 0.173 32.022 0.373 ;
     RECT  57.42 0.031 57.438 0.373 ;
     RECT  37.08 0.283 37.098 0.379 ;
     RECT  37.872 0.187 38.214 0.379 ;
     RECT  37.08 0.379 38.214 0.427 ;
     RECT  78.48 0.091 78.498 0.427 ;
     RECT  37.08 0.427 38.25 0.475 ;
     RECT  57.42 0.373 58.05 0.481 ;
     RECT  59.436 0.091 70.146 0.481 ;
     RECT  72.072 0.139 75.006 0.523 ;
     RECT  75.96 0.235 76.05 0.523 ;
     RECT  86.616 0.091 86.634 0.523 ;
     RECT  87.408 0.091 87.426 0.523 ;
     RECT  36.288 0.331 36.306 0.571 ;
     RECT  47.52 0.091 48.294 0.571 ;
     RECT  50.256 0.091 52.902 0.571 ;
     RECT  70.956 0.091 70.974 0.571 ;
     RECT  86.616 0.523 87.426 0.571 ;
     RECT  88.668 0.523 88.686 0.571 ;
     RECT  95.508 0.103 98.478 0.571 ;
     RECT  57.42 0.481 70.146 0.715 ;
     RECT  70.956 0.571 71.046 0.715 ;
     RECT  35.64 0.571 36.306 0.763 ;
     RECT  37.08 0.475 38.466 0.763 ;
     RECT  15.876 0.103 15.894 0.841 ;
     RECT  17.028 0.139 19.062 0.841 ;
     RECT  55.296 0.031 55.314 0.841 ;
     RECT  56.16 0.043 56.178 0.841 ;
     RECT  78.444 0.427 78.498 0.841 ;
     RECT  78.336 0.841 78.498 0.859 ;
     RECT  29.736 0.373 32.022 0.869 ;
     RECT  35.64 0.763 38.466 0.877 ;
     RECT  77.004 0.175 77.31 0.913 ;
     RECT  78.156 0.859 78.498 0.913 ;
     RECT  77.004 0.913 78.498 0.955 ;
     RECT  76.968 0.955 78.498 0.985 ;
     RECT  29.772 0.869 32.022 1.003 ;
     RECT  32.904 0.317 32.994 1.003 ;
     RECT  35.64 0.877 38.682 1.003 ;
     RECT  15.876 0.841 19.062 1.147 ;
     RECT  34.092 0.235 34.398 1.147 ;
     RECT  29.772 1.003 32.994 1.219 ;
     RECT  57.42 0.715 71.046 1.219 ;
     RECT  72.072 0.523 76.05 1.219 ;
     RECT  21.708 0.203 28.71 1.291 ;
     RECT  57.42 1.219 76.05 1.417 ;
     RECT  76.968 0.985 78.534 1.417 ;
     RECT  33.804 1.147 34.47 1.531 ;
     RECT  29.772 1.219 33.066 1.675 ;
     RECT  33.804 1.531 34.686 1.675 ;
     RECT  86.616 0.571 89.046 1.723 ;
     RECT  91.44 0.095 93.654 1.723 ;
     RECT  86.616 1.723 89.334 1.771 ;
     RECT  21.672 1.291 28.71 1.831 ;
     RECT  29.772 1.675 34.686 1.831 ;
     RECT  35.64 1.003 38.934 1.831 ;
     RECT  47.52 0.571 52.902 1.831 ;
     RECT  57.42 1.417 78.534 1.831 ;
     RECT  15.12 0.175 15.138 1.876 ;
     RECT  15.876 1.147 19.17 1.876 ;
     RECT  94.932 0.571 98.478 1.921 ;
     RECT  100.476 0.167 101.106 1.921 ;
     RECT  15.12 1.876 19.17 1.957 ;
     RECT  19.908 0.811 19.926 1.957 ;
     RECT  83.16 1.147 83.178 1.957 ;
     RECT  90.936 1.723 93.654 1.957 ;
     RECT  94.86 1.921 98.478 1.957 ;
     RECT  21.672 1.831 38.934 1.993 ;
     RECT  47.412 1.831 52.902 2.011 ;
     RECT  54.18 0.067 54.198 2.011 ;
     RECT  15.12 1.957 19.926 2.029 ;
     RECT  20.844 1.993 38.934 2.029 ;
     RECT  44.856 0.043 44.874 2.029 ;
     RECT  47.412 2.011 54.198 2.029 ;
     RECT  55.296 0.841 56.178 2.029 ;
     RECT  57.42 1.831 78.57 2.029 ;
     RECT  83.16 1.957 83.718 2.029 ;
     RECT  86.616 1.771 89.946 2.029 ;
     RECT  15.12 2.029 38.934 2.065 ;
     RECT  44.64 2.029 44.874 2.065 ;
     RECT  14.832 2.065 38.934 2.101 ;
     RECT  44.64 2.065 44.946 2.101 ;
     RECT  47.412 2.029 56.178 2.101 ;
     RECT  57.024 2.029 78.57 2.101 ;
     RECT  79.344 0.175 81.99 2.101 ;
     RECT  82.98 2.029 83.718 2.101 ;
     RECT  86.616 2.029 90.09 2.101 ;
     RECT  90.936 1.957 98.478 2.101 ;
     RECT  40.86 0.103 43.326 2.143 ;
     RECT  44.388 2.101 45.198 2.143 ;
     RECT  86.58 2.101 98.478 2.143 ;
     RECT  40.215 2.143 43.326 2.191 ;
     RECT  44.388 2.143 45.705 2.191 ;
     RECT  14.652 2.101 38.934 2.219 ;
     RECT  86.115 2.143 98.478 2.227 ;
     RECT  99.36 1.921 101.106 2.227 ;
     RECT  10.515 2.143 10.605 2.299 ;
     RECT  13.215 2.143 13.305 2.299 ;
     RECT  86.115 2.227 101.106 2.299 ;
     RECT  14.652 2.219 38.898 2.335 ;
     RECT  47.16 2.101 78.57 2.335 ;
     RECT  9.576 2.299 9.594 2.371 ;
     RECT  10.332 2.299 10.854 2.371 ;
     RECT  86.076 2.299 101.106 2.371 ;
     RECT  2.415 2.143 2.505 2.413 ;
     RECT  5.115 2.143 5.205 2.413 ;
     RECT  7.815 2.143 7.905 2.413 ;
     RECT  13.215 2.299 13.374 2.413 ;
     RECT  40.215 2.191 45.705 2.413 ;
     RECT  9.576 2.371 11.538 2.497 ;
     RECT  7.815 2.413 8.097 2.569 ;
     RECT  9.036 2.497 12.258 2.569 ;
     RECT  13.215 2.413 13.497 2.605 ;
     RECT  47.088 2.335 78.57 2.605 ;
     RECT  79.344 2.101 83.718 2.605 ;
     RECT  84.888 2.497 84.906 2.605 ;
     RECT  86.04 2.371 101.106 2.605 ;
     RECT  7.815 2.569 12.258 2.641 ;
     RECT  13.104 2.605 13.497 2.641 ;
     RECT  40.215 2.413 45.897 2.641 ;
     RECT  7.815 2.641 13.497 2.731 ;
     RECT  40.032 2.641 45.897 2.731 ;
     RECT  7.632 2.731 13.497 2.803 ;
     RECT  47.088 2.605 83.754 2.861 ;
     RECT  5.115 2.413 5.397 2.875 ;
     RECT  47.088 2.861 56.754 2.875 ;
     RECT  47.052 2.875 56.754 3.029 ;
     RECT  7.524 2.803 13.497 3.037 ;
     RECT  7.524 3.037 13.554 3.109 ;
     RECT  14.436 2.335 38.898 3.109 ;
     RECT  39.996 2.731 45.897 3.145 ;
     RECT  5.115 2.875 6.246 3.181 ;
     RECT  47.196 3.029 56.754 3.299 ;
     RECT  5.115 3.181 6.354 3.307 ;
     RECT  47.232 3.299 56.754 3.341 ;
     RECT  57.528 2.861 83.754 3.379 ;
     RECT  84.528 2.605 101.106 3.379 ;
     RECT  5.004 3.307 6.426 3.415 ;
     RECT  7.524 3.109 38.898 3.415 ;
     RECT  5.004 3.415 38.898 3.613 ;
     RECT  4.608 3.613 38.898 3.685 ;
     RECT  4.32 3.685 38.898 3.721 ;
     RECT  57.528 3.379 101.106 3.839 ;
     RECT  3.852 3.721 39.006 3.869 ;
     RECT  3.852 3.869 13.986 3.875 ;
     RECT  3.852 3.875 13.914 3.883 ;
     RECT  14.796 3.869 39.006 4.261 ;
     RECT  39.744 3.145 45.897 4.261 ;
     RECT  3.744 3.883 13.914 4.351 ;
     RECT  3.708 4.351 13.914 4.423 ;
     RECT  2.415 2.413 2.697 4.495 ;
     RECT  3.42 4.423 13.914 4.495 ;
     RECT  57.528 3.839 100.854 4.649 ;
     RECT  2.415 4.495 13.914 4.657 ;
     RECT  14.796 4.261 45.897 4.657 ;
     RECT  2.415 4.657 45.897 4.973 ;
     RECT  47.304 3.341 56.754 5.071 ;
     RECT  57.528 4.649 100.818 5.071 ;
     RECT  47.304 5.071 100.818 5.197 ;
     RECT  47.016 5.197 100.818 5.233 ;
     RECT  46.728 5.233 100.818 5.341 ;
     RECT  46.62 5.341 100.818 5.459 ;
     RECT  3.528 4.973 45.897 5.611 ;
     RECT  46.62 5.459 100.314 5.611 ;
     RECT  2.415 4.973 2.697 5.845 ;
     RECT  2.415 5.845 2.754 5.881 ;
     RECT  3.528 5.611 100.314 5.881 ;
     RECT  2.415 5.881 100.314 6.125 ;
     RECT  3.42 6.125 100.314 6.683 ;
     RECT  2.415 6.125 2.697 7.699 ;
     RECT  3.456 6.683 100.314 7.699 ;
     RECT  2.415 7.699 100.314 9.239 ;
     RECT  4.68 9.239 100.314 9.581 ;
     RECT  2.415 9.239 3.834 10.291 ;
     RECT  2.415 10.291 3.942 10.399 ;
     RECT  4.716 9.581 100.314 10.399 ;
     RECT  2.415 10.399 100.314 12.479 ;
     RECT  2.415 12.479 44.766 12.857 ;
     RECT  3.708 12.857 44.766 14.059 ;
     RECT  3.672 14.059 44.766 15.025 ;
     RECT  3.564 15.025 44.766 15.449 ;
     RECT  3.78 15.449 44.766 16.339 ;
     RECT  2.415 12.857 2.697 16.501 ;
     RECT  3.636 16.339 44.766 16.501 ;
     RECT  2.415 16.501 44.766 16.541 ;
     RECT  3.42 16.541 44.766 16.835 ;
     RECT  3.6 16.835 44.766 17.597 ;
     RECT  3.852 17.597 44.766 17.645 ;
     RECT  4.392 17.645 44.766 18.805 ;
     RECT  4.356 18.805 44.766 19.103 ;
     RECT  4.392 19.103 44.766 19.963 ;
     RECT  4.212 19.963 44.766 20.039 ;
     RECT  4.392 20.039 44.766 20.381 ;
     RECT  45.615 12.479 100.314 21.001 ;
     RECT  4.428 20.381 44.766 21.029 ;
     RECT  4.428 21.029 44.514 21.149 ;
     RECT  45.504 21.001 100.314 22.207 ;
     RECT  4.608 21.149 44.514 22.585 ;
     RECT  4.608 22.585 44.55 23.045 ;
     RECT  4.608 23.045 5.397 23.279 ;
     RECT  6.12 23.045 44.55 23.351 ;
     RECT  6.3 23.351 44.55 25.285 ;
     RECT  45.36 22.207 100.314 25.285 ;
     RECT  6.3 25.285 100.314 25.439 ;
     RECT  6.3 25.439 44.55 26.221 ;
     RECT  45.432 25.439 100.314 26.221 ;
     RECT  6.3 26.221 100.314 28.139 ;
     RECT  6.3 28.139 9.774 29.489 ;
     RECT  10.515 28.139 100.314 29.731 ;
     RECT  102.6 29.707 102.618 29.803 ;
     RECT  102.6 29.803 102.654 29.899 ;
     RECT  102.6 29.899 103.194 30.091 ;
     RECT  102.6 30.091 103.23 30.187 ;
     RECT  102.024 30.187 103.23 30.407 ;
     RECT  102.636 30.407 103.23 30.443 ;
     RECT  10.515 29.731 100.458 30.451 ;
     RECT  103.176 30.443 103.23 30.641 ;
     RECT  10.515 30.451 100.566 30.721 ;
     RECT  103.212 30.641 103.23 31.253 ;
     RECT  10.515 30.721 100.962 32.341 ;
     RECT  10.515 32.341 101.214 32.459 ;
     RECT  10.515 32.459 100.854 32.729 ;
     RECT  6.552 29.489 9.774 33.917 ;
     RECT  7.815 33.917 9.774 35.815 ;
     RECT  10.515 32.729 100.314 35.815 ;
     RECT  7.815 35.815 100.314 37.021 ;
     RECT  7.815 37.021 100.386 37.201 ;
     RECT  7.815 37.201 101.07 37.319 ;
     RECT  7.815 37.319 100.494 37.859 ;
     RECT  7.815 37.859 100.386 37.895 ;
     RECT  7.815 37.895 100.314 39.209 ;
     RECT  10.152 39.209 100.314 39.487 ;
     RECT  10.152 39.487 100.35 39.631 ;
     RECT  6.552 33.917 6.57 39.749 ;
     RECT  10.152 39.631 100.494 39.865 ;
     RECT  10.152 39.865 100.602 40.019 ;
     RECT  10.152 40.019 100.494 40.909 ;
     RECT  10.152 40.909 100.638 41.099 ;
     RECT  10.152 41.099 100.458 42.025 ;
     RECT  101.736 42.061 101.754 42.179 ;
     RECT  10.152 42.025 100.53 42.187 ;
     RECT  7.815 39.209 9.342 42.295 ;
     RECT  10.152 42.187 100.818 42.295 ;
     RECT  7.815 42.295 100.818 42.331 ;
     RECT  7.815 42.331 100.962 42.449 ;
     RECT  7.815 42.449 100.746 42.485 ;
     RECT  7.815 42.485 100.134 43.411 ;
     RECT  7.815 43.411 100.566 43.673 ;
     RECT  7.815 43.673 100.314 43.799 ;
     RECT  7.815 43.799 100.134 44.609 ;
     RECT  7.815 44.609 100.062 45.967 ;
     RECT  7.815 45.967 100.17 46.075 ;
     RECT  7.815 46.075 100.314 46.741 ;
     RECT  7.815 46.741 100.494 47.219 ;
     RECT  8.82 47.219 100.494 47.551 ;
     RECT  8.82 47.551 100.926 47.759 ;
     RECT  9.9 47.759 100.926 47.849 ;
     RECT  9.9 47.849 100.818 47.885 ;
     RECT  9.9 47.885 100.242 48.227 ;
     RECT  10.08 48.227 100.242 48.659 ;
     RECT  10.08 48.659 100.206 49.379 ;
     RECT  10.404 49.379 100.206 50.359 ;
     RECT  10.404 50.359 100.242 50.549 ;
     RECT  10.404 50.549 100.098 50.729 ;
     RECT  34.776 50.729 100.098 50.819 ;
     RECT  10.404 50.729 33.894 50.999 ;
     RECT  8.82 47.759 8.838 51.089 ;
     RECT  84.708 50.819 100.098 51.125 ;
     RECT  10.404 50.999 32.397 51.205 ;
     RECT  34.776 50.819 83.697 51.269 ;
     RECT  84.96 51.125 100.098 51.355 ;
     RECT  84.96 51.355 100.71 51.389 ;
     RECT  84.96 51.389 98.694 51.395 ;
     RECT  99.576 51.389 100.71 51.395 ;
     RECT  99.615 51.395 100.71 51.403 ;
     RECT  98.496 51.395 98.694 51.431 ;
     RECT  98.676 51.431 98.694 51.467 ;
     RECT  84.96 51.395 97.722 51.539 ;
     RECT  84.96 51.539 97.47 51.629 ;
     RECT  99.615 51.403 100.854 51.629 ;
     RECT  79.92 51.269 83.697 51.637 ;
     RECT  99.615 51.629 100.242 51.665 ;
     RECT  34.776 51.269 79.182 51.773 ;
     RECT  79.92 51.637 83.718 51.809 ;
     RECT  84.96 51.629 97.197 51.809 ;
     RECT  33.12 50.999 33.894 51.899 ;
     RECT  85.032 51.809 97.197 51.935 ;
     RECT  34.776 51.773 59.397 52.015 ;
     RECT  60.12 51.773 79.182 52.015 ;
     RECT  79.92 51.809 83.697 52.015 ;
     RECT  60.12 52.015 83.697 52.439 ;
     RECT  90.648 51.935 97.197 52.439 ;
     RECT  96.66 52.439 97.197 52.511 ;
     RECT  60.12 52.439 74.43 52.709 ;
     RECT  90.648 52.439 95.886 52.709 ;
     RECT  96.732 52.511 97.197 52.709 ;
     RECT  90.648 52.709 95.85 52.817 ;
     RECT  85.032 51.935 89.802 52.861 ;
     RECT  84.852 52.861 89.802 52.987 ;
     RECT  34.308 52.015 59.397 53.249 ;
     RECT  84.636 52.987 89.802 53.249 ;
     RECT  60.192 52.709 74.43 53.519 ;
     RECT  75.24 52.439 83.697 53.519 ;
     RECT  9.936 51.205 32.397 53.563 ;
     RECT  90.648 52.817 95.058 53.627 ;
     RECT  34.308 53.249 54.306 53.789 ;
     RECT  60.192 53.519 73.854 53.789 ;
     RECT  96.768 52.709 97.197 54.059 ;
     RECT  91.008 53.627 95.058 54.103 ;
     RECT  95.832 52.817 95.85 54.103 ;
     RECT  34.308 53.789 54.162 54.329 ;
     RECT  84.636 53.249 89.55 54.329 ;
     RECT  34.308 54.329 40.77 54.509 ;
     RECT  90.144 54.445 90.162 54.679 ;
     RECT  91.008 54.103 95.85 54.679 ;
     RECT  9.792 53.563 32.397 54.869 ;
     RECT  34.38 54.509 40.77 54.869 ;
     RECT  79.884 53.519 83.697 54.869 ;
     RECT  84.636 54.329 89.19 54.869 ;
     RECT  90.144 54.679 95.85 54.869 ;
     RECT  15.192 54.869 32.397 54.941 ;
     RECT  9.792 54.869 14.238 55.139 ;
     RECT  80.172 54.869 83.697 55.139 ;
     RECT  84.636 54.869 89.097 55.255 ;
     RECT  73.8 53.789 73.854 55.409 ;
     RECT  41.508 54.329 54.162 55.517 ;
     RECT  60.192 53.789 73.062 55.525 ;
     RECT  73.836 55.409 73.854 55.679 ;
     RECT  45.615 55.517 54.162 55.795 ;
     RECT  55.116 53.249 59.397 55.795 ;
     RECT  15.336 54.941 32.397 55.949 ;
     RECT  33.12 51.899 33.57 55.993 ;
     RECT  34.815 54.869 40.77 55.993 ;
     RECT  84.42 55.255 89.097 56.065 ;
     RECT  90.144 54.869 95.238 56.065 ;
     RECT  9.792 55.139 14.202 56.129 ;
     RECT  45.615 55.795 59.397 56.219 ;
     RECT  52.74 56.219 59.397 56.291 ;
     RECT  80.244 55.139 83.697 56.335 ;
     RECT  10.515 56.129 14.202 56.399 ;
     RECT  52.74 56.291 54.81 56.489 ;
     RECT  75.24 53.519 79.11 56.605 ;
     RECT  75.204 56.605 79.11 56.759 ;
     RECT  84.42 56.065 95.238 56.759 ;
     RECT  60.192 55.525 73.098 56.867 ;
     RECT  41.508 55.517 44.658 56.875 ;
     RECT  80.136 56.335 83.697 56.875 ;
     RECT  33.12 55.993 40.77 56.911 ;
     RECT  41.508 56.875 44.766 56.911 ;
     RECT  11.52 56.399 14.202 57.029 ;
     RECT  75.204 56.759 78.93 57.029 ;
     RECT  75.204 57.029 78.75 57.073 ;
     RECT  52.776 56.489 54.81 57.145 ;
     RECT  55.584 56.291 59.397 57.145 ;
     RECT  15.915 55.949 32.397 57.181 ;
     RECT  33.12 56.911 44.766 57.181 ;
     RECT  85.068 56.759 95.238 57.209 ;
     RECT  80.136 56.875 84.006 57.299 ;
     RECT  15.915 57.181 44.766 57.379 ;
     RECT  45.615 56.219 51.678 57.379 ;
     RECT  80.136 57.299 83.79 57.415 ;
     RECT  11.556 57.029 14.202 57.451 ;
     RECT  11.556 57.451 14.418 57.569 ;
     RECT  52.776 57.145 59.397 57.569 ;
     RECT  74.736 57.073 78.75 57.569 ;
     RECT  85.068 57.209 94.59 57.569 ;
     RECT  11.7 57.569 14.418 57.581 ;
     RECT  15.915 57.379 51.678 57.641 ;
     RECT  11.988 57.581 14.418 57.685 ;
     RECT  33.12 57.641 51.678 57.685 ;
     RECT  74.736 57.569 78.354 57.685 ;
     RECT  80.1 57.415 83.79 57.685 ;
     RECT  2.415 16.541 2.697 57.797 ;
     RECT  5.115 23.279 5.397 57.797 ;
     RECT  7.815 47.219 8.097 57.797 ;
     RECT  10.515 56.399 10.797 57.797 ;
     RECT  15.915 57.641 32.397 57.797 ;
     RECT  33.12 57.685 51.858 57.797 ;
     RECT  96.915 54.059 97.197 57.797 ;
     RECT  99.615 51.665 99.897 57.797 ;
     RECT  51.156 57.797 51.858 57.811 ;
     RECT  60.552 56.867 73.098 57.811 ;
     RECT  85.068 57.569 94.554 57.811 ;
     RECT  11.988 57.685 14.526 57.839 ;
     RECT  33.12 57.797 50.418 57.839 ;
     RECT  51.156 57.811 52.398 57.839 ;
     RECT  53.388 57.569 59.397 57.839 ;
     RECT  74.556 57.685 78.354 57.839 ;
     RECT  79.56 57.685 83.79 57.839 ;
     RECT  84.744 57.811 94.554 57.839 ;
     RECT  16.107 57.797 32.397 57.875 ;
     RECT  33.12 57.839 50.346 57.875 ;
     RECT  75.168 57.839 78.354 57.875 ;
     RECT  83.304 57.839 83.697 57.875 ;
     RECT  84.744 57.839 90.054 57.875 ;
     RECT  51.156 57.839 51.297 57.911 ;
     RECT  52.38 57.839 52.398 57.911 ;
     RECT  55.044 57.839 59.397 57.911 ;
     RECT  60.552 57.811 73.53 57.911 ;
     RECT  84.744 57.875 89.097 57.911 ;
     RECT  33.12 57.875 33.426 57.92 ;
     RECT  34.236 57.875 35.694 57.947 ;
     RECT  36.432 57.875 43.614 57.947 ;
     RECT  45.807 57.875 50.346 57.947 ;
     RECT  89.928 57.875 90.054 57.947 ;
     RECT  49.788 57.947 49.806 57.983 ;
     RECT  55.332 57.911 59.397 57.983 ;
     RECT  12.06 57.839 14.418 58.013 ;
     RECT  36.684 57.947 43.614 58.013 ;
     RECT  44.352 57.875 44.37 58.013 ;
     RECT  60.552 57.911 72.897 58.013 ;
     RECT  10.656 57.797 10.797 58.019 ;
     RECT  34.704 57.947 35.694 58.019 ;
     RECT  36.684 58.013 43.326 58.019 ;
     RECT  53.388 57.839 53.997 58.019 ;
     RECT  60.552 58.013 71.802 58.019 ;
     RECT  79.668 57.839 82.494 58.019 ;
     RECT  85.068 57.911 89.097 58.019 ;
     RECT  89.928 57.947 89.946 58.019 ;
     RECT  2.607 57.797 2.697 58.067 ;
     RECT  5.307 57.797 5.397 58.067 ;
     RECT  8.007 57.797 8.097 58.067 ;
     RECT  10.707 58.019 10.797 58.067 ;
     RECT  16.107 57.875 30.438 58.067 ;
     RECT  32.148 57.875 32.397 58.067 ;
     RECT  36.684 58.019 40.497 58.067 ;
     RECT  45.807 57.947 48.978 58.067 ;
     RECT  51.207 57.911 51.297 58.067 ;
     RECT  53.907 58.019 53.997 58.067 ;
     RECT  55.764 57.983 59.397 58.067 ;
     RECT  72.807 58.013 72.897 58.067 ;
     RECT  75.204 57.875 78.297 58.067 ;
     RECT  83.607 57.875 83.697 58.067 ;
     RECT  89.007 58.019 89.097 58.067 ;
     RECT  91.188 57.839 94.497 58.067 ;
     RECT  97.107 57.797 97.197 58.067 ;
     RECT  99.807 57.797 99.897 58.067 ;
     RECT  32.148 58.067 32.166 58.109 ;
     RECT  34.704 58.019 35.19 58.109 ;
     RECT  36.684 58.067 39.942 58.109 ;
     RECT  55.764 58.067 58.806 58.109 ;
     RECT  33.408 57.92 33.426 58.145 ;
     RECT  35.172 58.109 35.19 58.145 ;
     RECT  36.756 58.109 39.258 58.145 ;
     RECT  16.668 58.067 30.438 58.157 ;
     RECT  55.764 58.109 58.734 58.157 ;
     RECT  60.66 58.019 71.802 58.157 ;
     RECT  75.204 58.067 77.994 58.157 ;
     RECT  91.188 58.067 94.158 58.157 ;
     RECT  12.348 58.013 14.418 58.205 ;
     RECT  18.936 58.157 28.278 58.205 ;
     RECT  55.908 58.157 57.402 58.205 ;
     RECT  58.248 58.157 58.482 58.205 ;
     RECT  71.712 58.157 71.73 58.205 ;
     RECT  75.456 58.157 75.798 58.205 ;
     RECT  91.332 58.157 94.158 58.205 ;
     RECT  12.348 58.205 13.698 58.253 ;
     RECT  19.08 58.205 19.098 58.253 ;
     RECT  20.016 58.205 28.278 58.253 ;
     RECT  29.052 58.157 30.438 58.253 ;
     RECT  60.66 58.157 70.794 58.253 ;
     RECT  91.404 58.205 94.158 58.253 ;
     RECT  12.348 58.253 13.158 58.301 ;
     RECT  20.016 58.253 27.99 58.301 ;
     RECT  75.744 58.205 75.762 58.301 ;
     RECT  76.896 58.157 77.994 58.301 ;
     RECT  91.404 58.253 91.422 58.301 ;
     RECT  92.844 58.253 94.158 58.301 ;
     RECT  60.66 58.253 70.614 58.445 ;
     RECT  60.66 58.445 69.786 58.541 ;
     RECT  77.148 58.301 77.994 58.541 ;
     RECT  93.204 58.301 94.158 58.589 ;
     RECT  29.232 58.253 30.438 58.637 ;
     RECT  77.148 58.541 77.958 58.637 ;
     RECT  16.668 58.157 18.09 58.685 ;
     RECT  29.304 58.637 30.438 58.685 ;
     RECT  56.124 58.205 57.402 58.685 ;
     RECT  58.248 58.205 58.266 58.685 ;
     RECT  70.596 58.445 70.614 58.685 ;
     RECT  77.148 58.637 77.886 58.685 ;
     RECT  85.068 58.019 88.218 58.685 ;
     RECT  93.24 58.589 94.158 58.685 ;
     RECT  20.016 58.301 27.81 58.721 ;
     RECT  27.792 58.721 27.81 58.733 ;
     RECT  86.436 58.685 86.67 58.733 ;
     RECT  12.348 58.301 12.726 59.309 ;
     RECT  18.072 58.685 18.09 59.309 ;
     RECT  20.016 58.721 26.694 59.309 ;
     RECT  29.34 58.685 29.358 59.309 ;
     RECT  12.42 59.309 12.726 59.357 ;
     RECT  60.66 58.541 69.462 59.803 ;
     RECT  41.364 58.019 43.326 59.851 ;
     RECT  60.66 59.803 70.038 59.851 ;
     RECT  12.42 59.357 12.438 59.885 ;
     RECT  16.668 58.685 17.082 59.885 ;
     RECT  56.268 58.685 56.286 59.885 ;
     RECT  20.052 59.309 26.694 59.899 ;
     RECT  41.364 59.851 43.398 59.899 ;
     RECT  16.668 59.885 17.01 59.933 ;
     RECT  41.364 59.899 43.542 59.947 ;
     RECT  16.992 59.933 17.01 59.981 ;
     RECT  18.18 59.851 18.198 60.029 ;
     RECT  18.972 59.851 18.99 60.029 ;
     RECT  76.212 59.995 76.23 60.043 ;
     RECT  29.448 59.947 29.466 60.091 ;
     RECT  29.376 60.091 29.466 60.139 ;
     RECT  57.276 58.685 57.294 60.139 ;
     RECT  75.672 60.043 76.23 60.173 ;
     RECT  75.672 60.173 75.69 60.221 ;
     RECT  14.004 60.187 14.022 60.235 ;
     RECT  56.88 60.139 57.294 60.235 ;
     RECT  92.052 60.091 92.07 60.235 ;
     RECT  20.052 59.899 26.766 60.283 ;
     RECT  80.1 58.019 82.494 60.313 ;
     RECT  14.004 60.235 14.094 60.317 ;
     RECT  46.548 58.067 48.978 60.341 ;
     RECT  12.168 60.187 12.186 60.365 ;
     RECT  14.076 60.317 14.094 60.365 ;
     RECT  18.36 60.187 18.378 60.365 ;
     RECT  28.944 60.139 29.61 60.365 ;
     RECT  56.88 60.235 57.546 60.365 ;
     RECT  76.5 60.235 76.518 60.365 ;
     RECT  86.436 58.733 86.454 60.365 ;
     RECT  91.44 60.235 92.07 60.365 ;
     RECT  80.028 60.313 82.494 60.385 ;
     RECT  36.756 58.145 39.15 60.413 ;
     RECT  46.548 60.341 48.942 60.413 ;
     RECT  60.66 59.851 70.11 60.413 ;
     RECT  79.956 60.385 82.494 60.413 ;
     RECT  20.052 60.283 26.91 60.444 ;
     RECT  36.756 60.413 39.006 60.444 ;
     RECT  41.364 59.947 43.614 60.444 ;
     RECT  46.548 60.413 48.798 60.444 ;
     RECT  60.948 60.413 70.11 60.444 ;
     RECT  79.956 60.413 82.206 60.444 ;
    LAYER M4 ;
     RECT  2.408 2.148 2.512 57.792 ;
     RECT  2.512 2.418 2.6 57.792 ;
     RECT  2.6 2.418 2.704 58.062 ;
     RECT  2.704 10.848 3.521 10.872 ;
     RECT  2.704 7.392 3.629 7.992 ;
     RECT  2.704 6.096 3.701 6.12 ;
     RECT  2.704 11.952 3.917 11.976 ;
     RECT  2.704 4.944 4.061 4.968 ;
     RECT  3.733 3.888 4.172 3.912 ;
     RECT  4.172 3.888 4.213 4.104 ;
     RECT  2.704 16.512 4.345 16.536 ;
     RECT  2.704 17.568 4.417 17.592 ;
     RECT  4.345 15.984 4.453 16.536 ;
     RECT  4.417 17.568 4.453 18.456 ;
     RECT  4.453 15.984 4.645 18.456 ;
     RECT  4.201 19.968 4.645 19.992 ;
     RECT  4.129 8.688 4.669 8.856 ;
     RECT  3.629 7.392 4.957 7.416 ;
     RECT  4.669 8.688 4.957 9.576 ;
     RECT  4.213 3.408 5.108 4.104 ;
     RECT  4.129 5.184 5.108 5.736 ;
     RECT  4.957 7.392 5.108 9.576 ;
     RECT  2.704 14.064 5.108 14.088 ;
     RECT  4.645 15.984 5.108 19.992 ;
     RECT  4.417 21.12 5.108 21.144 ;
     RECT  5.108 2.148 5.212 57.792 ;
     RECT  5.212 2.418 5.3 57.792 ;
     RECT  5.3 2.418 5.404 58.062 ;
     RECT  5.404 20.448 5.555 21.144 ;
     RECT  5.404 5.184 5.861 9.72 ;
     RECT  5.404 10.848 5.861 11.448 ;
     RECT  5.555 21.12 5.933 21.144 ;
     RECT  5.861 5.184 6.179 9.576 ;
     RECT  5.404 13.92 6.179 18.696 ;
     RECT  5.404 22.8 6.329 23.256 ;
     RECT  6.179 5.712 6.401 9.576 ;
     RECT  5.404 3.312 6.565 4.008 ;
     RECT  6.179 15.936 6.613 18.696 ;
     RECT  6.179 13.92 6.617 14.856 ;
     RECT  6.565 2.832 6.721 4.008 ;
     RECT  6.617 14.832 6.833 14.856 ;
     RECT  6.757 20.976 7.052 21 ;
     RECT  7.052 20.448 7.081 21 ;
     RECT  6.613 15.936 7.093 18.84 ;
     RECT  7.093 15.936 7.141 19.272 ;
     RECT  7.081 20.448 7.297 21.528 ;
     RECT  6.401 5.76 7.429 9.576 ;
     RECT  5.861 11.424 7.429 11.448 ;
     RECT  7.429 5.76 7.585 11.448 ;
     RECT  6.329 23.232 7.585 23.256 ;
     RECT  6.613 12.528 7.621 12.552 ;
     RECT  6.937 13.824 7.621 13.848 ;
     RECT  7.141 15.84 7.801 19.272 ;
     RECT  7.297 20.448 7.801 22.2 ;
     RECT  6.721 2.832 7.808 4.2 ;
     RECT  7.585 5.28 7.808 11.448 ;
     RECT  7.621 12.528 7.808 13.848 ;
     RECT  7.801 15.84 7.808 22.2 ;
     RECT  7.585 23.232 7.808 23.976 ;
     RECT  7.808 2.148 7.912 57.792 ;
     RECT  7.912 2.418 8 57.792 ;
     RECT  8 2.418 8.104 58.062 ;
     RECT  8.104 12.72 8.243 17.112 ;
     RECT  8.104 19.248 8.345 23.88 ;
     RECT  8.104 3.408 8.885 9.096 ;
     RECT  8.104 11.472 9.097 11.688 ;
     RECT  8.885 6.624 9.107 9.096 ;
     RECT  8.104 10.224 9.109 10.248 ;
     RECT  9.097 11.232 9.109 11.688 ;
     RECT  8.104 18.192 9.145 18.216 ;
     RECT  9.109 10.224 9.155 11.688 ;
     RECT  8.885 3.408 9.169 5.64 ;
     RECT  9.107 6.672 9.209 9.096 ;
     RECT  8.243 12.72 9.277 16.872 ;
     RECT  8.345 19.344 9.349 23.88 ;
     RECT  9.349 19.344 9.443 24.408 ;
     RECT  9.277 12.72 9.461 17.16 ;
     RECT  9.443 19.344 9.484 23.304 ;
     RECT  9.169 2.736 9.533 5.64 ;
     RECT  9.209 7.104 9.637 9.096 ;
     RECT  9.443 24.384 9.665 24.408 ;
     RECT  9.484 19.344 9.673 21.672 ;
     RECT  9.637 7.104 10.22 9.72 ;
     RECT  9.155 10.752 10.22 11.688 ;
     RECT  9.461 17.088 10.309 17.16 ;
     RECT  9.673 18.48 10.309 21.672 ;
     RECT  10.309 17.088 10.501 21.672 ;
     RECT  9.484 22.8 10.501 23.304 ;
     RECT  9.533 2.736 10.508 5.592 ;
     RECT  10.22 7.104 10.508 11.688 ;
     RECT  9.461 12.72 10.508 16.104 ;
     RECT  10.501 17.088 10.508 23.304 ;
     RECT  9.665 24.384 10.508 25.128 ;
     RECT  10.508 2.148 10.612 57.792 ;
     RECT  10.612 2.418 10.7 57.792 ;
     RECT  10.7 2.418 10.804 58.062 ;
     RECT  10.804 6.864 10.865 9.528 ;
     RECT  10.804 13.056 10.865 20.088 ;
     RECT  10.804 24.384 10.865 25.272 ;
     RECT  10.865 19.344 11.116 20.088 ;
     RECT  10.804 54.096 11.341 54.12 ;
     RECT  10.865 13.056 11.507 18.216 ;
     RECT  11.116 19.344 11.507 20.04 ;
     RECT  11.507 19.824 11.548 20.04 ;
     RECT  11.507 14.496 11.603 18.216 ;
     RECT  11.548 19.824 11.603 19.848 ;
     RECT  10.804 57.024 11.837 57.576 ;
     RECT  10.804 2.832 11.901 5.832 ;
     RECT  10.865 6.864 11.977 9.096 ;
     RECT  10.804 10.56 11.977 11.928 ;
     RECT  11.603 14.496 11.987 17.688 ;
     RECT  10.865 25.104 12.013 25.272 ;
     RECT  11.837 57.168 12.044 57.576 ;
     RECT  11.901 4.992 12.085 5.832 ;
     RECT  11.977 6.864 12.085 11.928 ;
     RECT  12.085 4.992 12.089 11.928 ;
     RECT  10.804 21.12 12.089 23.352 ;
     RECT  12.013 24.528 12.097 25.272 ;
     RECT  12.085 60.096 12.113 60.12 ;
     RECT  12.089 23.328 12.124 23.352 ;
     RECT  12.113 60.096 12.133 60.36 ;
     RECT  12.089 4.992 12.197 7.416 ;
     RECT  12.133 59.904 12.197 60.36 ;
     RECT  12.044 57.168 12.227 58.008 ;
     RECT  11.507 13.056 12.229 13.08 ;
     RECT  12.197 59.904 12.337 60.264 ;
     RECT  12.229 13.008 12.517 13.08 ;
     RECT  11.987 14.496 12.517 14.52 ;
     RECT  12.373 58.08 12.517 58.152 ;
     RECT  12.337 59.28 12.517 60.264 ;
     RECT  10.804 26.736 12.553 26.76 ;
     RECT  12.517 58.08 12.659 60.264 ;
     RECT  11.987 15.84 12.661 17.688 ;
     RECT  12.089 8.448 12.769 11.928 ;
     RECT  12.517 13.008 12.769 14.52 ;
     RECT  12.659 59.28 12.851 60.264 ;
     RECT  12.553 26.736 12.877 27.384 ;
     RECT  12.089 21.12 13.093 22.248 ;
     RECT  12.097 25.248 13.165 25.272 ;
     RECT  12.659 58.08 13.187 58.296 ;
     RECT  12.985 19.248 13.201 19.272 ;
     RECT  13.093 20.4 13.201 22.248 ;
     RECT  11.901 2.832 13.208 3.96 ;
     RECT  12.197 4.992 13.208 5.064 ;
     RECT  12.197 6.24 13.208 7.416 ;
     RECT  12.769 8.448 13.208 14.52 ;
     RECT  12.661 15.84 13.208 18.168 ;
     RECT  13.201 19.248 13.208 22.248 ;
     RECT  13.165 25.2 13.208 25.272 ;
     RECT  12.877 26.736 13.208 27.912 ;
     RECT  13.093 56.88 13.208 56.904 ;
     RECT  13.187 58.08 13.208 58.248 ;
     RECT  13.208 2.148 13.312 58.248 ;
     RECT  12.851 59.328 13.331 60.264 ;
     RECT  13.331 60.192 13.381 60.264 ;
     RECT  13.312 2.418 13.504 58.248 ;
     RECT  13.504 14.976 13.619 23.16 ;
     RECT  13.504 55.248 13.619 58.248 ;
     RECT  13.504 3.408 13.637 7.368 ;
     RECT  13.504 8.688 13.645 13.704 ;
     RECT  13.637 3.408 13.667 7.272 ;
     RECT  13.645 8.688 13.667 12.264 ;
     RECT  13.504 24.528 13.673 29.064 ;
     RECT  13.619 55.824 13.715 58.248 ;
     RECT  13.667 3.408 13.745 7.224 ;
     RECT  13.667 8.688 13.817 10.296 ;
     RECT  13.817 8.784 13.853 10.296 ;
     RECT  13.715 55.824 13.907 58.2 ;
     RECT  13.381 60.192 14.021 60.312 ;
     RECT  13.745 3.84 14.033 7.224 ;
     RECT  13.504 54.096 14.051 54.12 ;
     RECT  14.021 60.192 14.051 60.36 ;
     RECT  13.619 15.84 14.069 22.824 ;
     RECT  14.051 60.24 14.105 60.36 ;
     RECT  14.033 3.84 14.141 3.864 ;
     RECT  13.907 56.112 14.147 58.2 ;
     RECT  14.105 60.24 14.147 60.264 ;
     RECT  14.147 57.024 14.177 58.2 ;
     RECT  14.033 5.088 14.213 7.224 ;
     RECT  14.177 57.6 14.285 58.2 ;
     RECT  13.853 8.976 14.387 10.296 ;
     RECT  14.285 58.176 14.429 58.2 ;
     RECT  13.673 25.632 14.465 29.064 ;
     RECT  13.504 31.104 14.497 31.128 ;
     RECT  13.667 11.28 14.645 12.264 ;
     RECT  14.465 28.608 14.677 29.064 ;
     RECT  14.645 11.952 14.741 12.264 ;
     RECT  14.497 24.24 14.749 24.264 ;
     RECT  14.465 25.632 14.749 25.704 ;
     RECT  14.387 8.976 14.753 9.528 ;
     RECT  14.677 28.608 14.764 29.496 ;
     RECT  14.213 6.288 14.785 7.224 ;
     RECT  14.753 8.976 14.789 9.048 ;
     RECT  14.497 31.104 14.819 31.8 ;
     RECT  14.069 21.312 14.821 22.824 ;
     RECT  14.749 24.24 14.821 25.704 ;
     RECT  14.741 32.928 14.825 32.952 ;
     RECT  14.069 15.84 14.857 20.184 ;
     RECT  13.645 13.68 15.001 13.704 ;
     RECT  14.764 29.472 15.001 29.496 ;
     RECT  15.001 13.584 15.109 13.704 ;
     RECT  14.213 5.088 15.181 5.256 ;
     RECT  14.741 11.952 15.253 12.552 ;
     RECT  15.109 13.584 15.253 13.992 ;
     RECT  14.819 31.104 15.253 31.128 ;
     RECT  14.857 15.072 15.349 20.184 ;
     RECT  14.821 21.312 15.349 25.704 ;
     RECT  14.785 6.288 15.361 7.8 ;
     RECT  14.789 8.976 15.361 9 ;
     RECT  15.349 15.072 15.505 25.704 ;
     RECT  15.505 15.072 15.589 26.28 ;
     RECT  14.465 27.312 15.589 27.384 ;
     RECT  14.857 10.8 15.793 10.824 ;
     RECT  15.253 11.952 15.793 13.992 ;
     RECT  14.965 2.592 15.908 2.616 ;
     RECT  15.181 4.992 15.908 5.256 ;
     RECT  15.361 6.288 15.908 9 ;
     RECT  15.793 10.8 15.908 13.992 ;
     RECT  15.589 15.072 15.908 27.384 ;
     RECT  15.001 29.472 15.908 29.784 ;
     RECT  15.253 30.816 15.908 31.128 ;
     RECT  14.773 34.08 15.908 34.104 ;
     RECT  15.908 2.148 16.012 57.792 ;
     RECT  16.012 2.418 16.1 57.792 ;
     RECT  16.1 2.418 16.204 58.062 ;
     RECT  16.204 21.408 16.265 24.936 ;
     RECT  16.204 19.296 16.355 19.896 ;
     RECT  16.204 46.368 16.355 46.392 ;
     RECT  16.204 29.04 16.409 30.744 ;
     RECT  16.204 2.544 16.445 12.072 ;
     RECT  16.445 2.544 16.697 11.976 ;
     RECT  16.355 19.296 16.697 19.368 ;
     RECT  16.409 29.04 16.877 30.648 ;
     RECT  16.697 19.296 16.913 19.32 ;
     RECT  16.657 59.904 16.981 59.928 ;
     RECT  16.981 59.904 17.053 59.976 ;
     RECT  16.877 29.04 17.057 30.552 ;
     RECT  16.204 56.112 17.267 58.008 ;
     RECT  16.204 32.016 17.269 32.04 ;
     RECT  16.265 21.408 17.305 24.84 ;
     RECT  16.204 26.016 17.305 27.624 ;
     RECT  17.053 0.24 17.341 0.264 ;
     RECT  17.341 0.048 17.345 0.264 ;
     RECT  17.305 21.408 17.363 27.624 ;
     RECT  16.697 2.544 17.381 11.4 ;
     RECT  17.267 57.024 17.413 58.008 ;
     RECT  17.269 32.016 17.449 32.472 ;
     RECT  17.345 0.048 17.489 0.072 ;
     RECT  17.363 25.248 17.557 27.624 ;
     RECT  17.057 29.04 17.557 30.12 ;
     RECT  17.557 25.248 17.597 30.12 ;
     RECT  16.204 15.84 17.629 17.736 ;
     RECT  16.204 13.584 17.665 13.608 ;
     RECT  17.629 15.84 17.701 18.264 ;
     RECT  17.413 57.024 17.737 58.152 ;
     RECT  17.381 10.56 17.845 11.4 ;
     RECT  17.66 55.536 17.852 55.56 ;
     RECT  17.701 15.84 17.917 19.08 ;
     RECT  17.737 57.024 17.939 58.68 ;
     RECT  17.449 31.968 17.953 32.472 ;
     RECT  17.053 59.856 18.061 59.976 ;
     RECT  18.061 59.28 18.13 59.976 ;
     RECT  16.204 34.08 18.169 34.104 ;
     RECT  18.13 59.28 18.229 60.024 ;
     RECT  17.381 2.544 18.277 9.576 ;
     RECT  18.229 59.28 18.349 60.264 ;
     RECT  18.277 2.352 18.38 9.576 ;
     RECT  17.845 10.56 18.38 11.448 ;
     RECT  18.14 12.48 18.421 12.504 ;
     RECT  17.665 13.584 18.421 14.232 ;
     RECT  18.349 59.28 18.433 60.36 ;
     RECT  17.363 21.408 18.469 24.12 ;
     RECT  17.953 31.152 18.469 32.472 ;
     RECT  17.852 55.008 18.469 55.56 ;
     RECT  18.38 2.352 18.608 11.448 ;
     RECT  18.421 12.48 18.608 14.232 ;
     RECT  17.917 15.408 18.608 19.08 ;
     RECT  18.469 20.976 18.608 24.12 ;
     RECT  17.597 25.248 18.608 29.592 ;
     RECT  18.469 30.864 18.608 32.472 ;
     RECT  18.169 34.08 18.608 34.488 ;
     RECT  18.421 36.48 18.608 36.504 ;
     RECT  18.457 38.16 18.608 38.184 ;
     RECT  18.469 55.008 18.608 55.848 ;
     RECT  17.939 57.024 18.608 58.2 ;
     RECT  18.433 59.28 18.707 60.264 ;
     RECT  18.608 2.148 18.712 58.2 ;
     RECT  18.712 2.352 18.749 58.2 ;
     RECT  18.749 2.418 18.904 58.2 ;
     RECT  18.904 54.72 18.949 58.2 ;
     RECT  18.707 59.28 19.001 60.024 ;
     RECT  18.904 13.104 19.037 13.656 ;
     RECT  18.904 36.48 19.043 39.432 ;
     RECT  18.949 54.72 19.109 58.248 ;
     RECT  18.904 2.592 19.145 11.496 ;
     RECT  19.145 4.224 19.379 11.496 ;
     RECT  18.904 30.72 19.469 32.472 ;
     RECT  19.043 36.48 19.469 38.232 ;
     RECT  19.469 37.536 19.497 38.232 ;
     RECT  19.109 54.72 19.516 58.2 ;
     RECT  18.904 46.56 19.571 46.92 ;
     RECT  19.469 36.48 19.577 36.504 ;
     RECT  19.379 4.224 19.613 7.368 ;
     RECT  18.904 45.312 19.667 45.336 ;
     RECT  19.469 31.92 19.67 32.472 ;
     RECT  19.516 54.72 19.715 58.152 ;
     RECT  19.379 8.448 19.763 11.496 ;
     RECT  18.904 21.408 19.793 29.736 ;
     RECT  19.469 30.72 19.829 30.744 ;
     RECT  19.037 13.104 19.897 13.416 ;
     RECT  19.571 46.56 19.901 46.584 ;
     RECT  19.715 55.152 19.937 58.152 ;
     RECT  19.001 59.28 20.005 59.928 ;
     RECT  19.793 21.408 20.009 28.248 ;
     RECT  18.904 14.832 20.081 19.032 ;
     RECT  19.67 31.968 20.113 32.472 ;
     RECT  20.005 59.28 20.147 60.312 ;
     RECT  19.497 38.16 20.149 38.232 ;
     RECT  19.043 39.36 20.149 39.432 ;
     RECT  18.904 34.032 20.189 35.112 ;
     RECT  19.793 29.472 20.257 29.736 ;
     RECT  20.257 29.472 20.297 30.504 ;
     RECT  20.147 59.856 20.444 60.312 ;
     RECT  20.113 31.968 20.509 32.568 ;
     RECT  19.763 8.496 20.533 11.496 ;
     RECT  19.897 12.528 20.533 13.416 ;
     RECT  20.533 36.336 20.617 36.36 ;
     RECT  19.937 55.152 20.876 58.008 ;
     RECT  20.189 34.656 20.941 35.112 ;
     RECT  20.617 36.192 20.941 36.36 ;
     RECT  19.145 2.592 21.013 3.096 ;
     RECT  20.009 21.408 21.013 27.624 ;
     RECT  20.297 29.616 21.013 30.504 ;
     RECT  20.509 31.968 21.013 33.672 ;
     RECT  20.149 38.16 21.013 39.432 ;
     RECT  21.013 2.592 21.049 3.144 ;
     RECT  19.613 4.224 21.049 5.16 ;
     RECT  20.081 14.928 21.049 19.032 ;
     RECT  21.013 21.408 21.049 27.72 ;
     RECT  20.876 54.672 21.085 58.008 ;
     RECT  20.941 34.656 21.157 36.456 ;
     RECT  21.085 54.672 21.164 58.152 ;
     RECT  20.533 8.496 21.193 13.416 ;
     RECT  21.049 14.928 21.193 19.272 ;
     RECT  21.049 2.592 21.308 5.16 ;
     RECT  19.613 6.336 21.308 7.368 ;
     RECT  21.193 8.496 21.308 19.272 ;
     RECT  18.904 20.304 21.308 20.328 ;
     RECT  21.049 21.408 21.308 28.536 ;
     RECT  21.013 29.616 21.308 33.672 ;
     RECT  21.157 34.656 21.308 37.176 ;
     RECT  21.013 38.16 21.308 40.104 ;
     RECT  20.329 41.376 21.308 41.4 ;
     RECT  21.164 54.672 21.308 58.2 ;
     RECT  21.308 2.148 21.435 58.2 ;
     RECT  20.444 59.856 21.449 60.408 ;
     RECT  21.435 2.148 21.517 58.248 ;
     RECT  21.517 2.016 21.539 58.248 ;
     RECT  21.449 59.904 21.593 60.408 ;
     RECT  21.539 2.016 21.604 58.152 ;
     RECT  21.604 11.952 21.701 32.568 ;
     RECT  21.604 36.864 21.701 36.888 ;
     RECT  21.604 33.552 21.881 33.672 ;
     RECT  21.604 34.704 21.881 35.832 ;
     RECT  21.604 56.64 22.141 58.152 ;
     RECT  22.141 56.64 22.205 58.008 ;
     RECT  21.701 11.952 22.259 19.416 ;
     RECT  22.259 19.008 22.277 19.416 ;
     RECT  21.604 41.376 22.277 41.4 ;
     RECT  21.604 38.496 22.349 40.104 ;
     RECT  21.604 8.4 22.385 10.68 ;
     RECT  22.259 11.952 22.421 18.024 ;
     RECT  22.277 19.392 22.457 19.416 ;
     RECT  21.701 20.4 22.493 32.568 ;
     RECT  22.421 11.952 22.565 14.856 ;
     RECT  22.349 38.88 22.601 40.104 ;
     RECT  21.604 55.248 22.604 55.272 ;
     RECT  22.205 56.64 22.604 56.904 ;
     RECT  21.881 34.704 22.637 35.544 ;
     RECT  22.604 54.672 22.645 55.272 ;
     RECT  22.604 56.352 22.645 56.904 ;
     RECT  22.493 20.4 22.669 21.672 ;
     RECT  22.385 8.4 22.673 9.624 ;
     RECT  22.645 54.672 22.691 56.904 ;
     RECT  22.691 55.152 22.781 56.904 ;
     RECT  21.604 2.016 22.789 7.416 ;
     RECT  22.673 8.4 22.789 9.384 ;
     RECT  22.493 22.8 22.853 32.568 ;
     RECT  22.565 11.952 22.889 14.52 ;
     RECT  22.669 20.016 22.889 21.672 ;
     RECT  21.593 60.096 22.949 60.408 ;
     RECT  22.601 39.264 23.033 40.104 ;
     RECT  22.949 59.856 23.033 60.408 ;
     RECT  19.897 0.816 23.101 0.84 ;
     RECT  22.789 2.016 23.173 9.384 ;
     RECT  23.065 37.104 23.173 37.896 ;
     RECT  21.881 33.552 23.245 33.576 ;
     RECT  23.101 0.048 23.249 0.84 ;
     RECT  22.781 56.88 23.309 56.904 ;
     RECT  22.205 57.984 23.309 58.008 ;
     RECT  23.309 56.88 23.317 58.008 ;
     RECT  23.173 37.056 23.353 37.896 ;
     RECT  23.033 60.24 23.363 60.408 ;
     RECT  22.385 10.656 23.425 10.68 ;
     RECT  22.889 11.952 23.425 12.84 ;
     RECT  23.249 0.816 23.461 0.84 ;
     RECT  23.173 1.92 23.461 9.384 ;
     RECT  22.421 15.984 23.461 18.024 ;
     RECT  23.461 0.816 23.609 9.384 ;
     RECT  22.889 14.304 23.641 14.52 ;
     RECT  23.461 15.84 23.641 18.024 ;
     RECT  22.781 55.152 23.701 55.896 ;
     RECT  22.889 20.16 23.713 21.672 ;
     RECT  22.853 22.8 23.713 31.992 ;
     RECT  23.033 40.08 23.785 40.104 ;
     RECT  23.609 1.92 23.797 9.384 ;
     RECT  23.701 54.72 23.845 55.896 ;
     RECT  23.317 56.88 23.845 58.152 ;
     RECT  23.353 36.48 23.885 37.896 ;
     RECT  23.713 20.16 23.929 31.992 ;
     RECT  23.797 1.92 24.008 9.576 ;
     RECT  23.425 10.656 24.008 12.84 ;
     RECT  23.641 14.304 24.008 18.024 ;
     RECT  23.929 19.344 24.008 31.992 ;
     RECT  23.245 33.312 24.008 33.576 ;
     RECT  22.637 34.704 24.008 34.92 ;
     RECT  23.885 36 24.008 37.896 ;
     RECT  23.785 40.08 24.008 41.064 ;
     RECT  23.845 46.608 24.008 46.632 ;
     RECT  23.845 54.72 24.008 58.152 ;
     RECT  24.008 1.92 24.304 58.152 ;
     RECT  24.304 19.248 24.329 31.992 ;
     RECT  24.304 54.864 24.419 58.152 ;
     RECT  24.304 4.416 24.437 18.216 ;
     RECT  24.329 19.248 24.437 30.84 ;
     RECT  23.609 0.816 24.473 0.84 ;
     RECT  23.363 60.288 24.577 60.408 ;
     RECT  24.577 60.192 24.613 60.408 ;
     RECT  24.304 39.264 24.797 40.44 ;
     RECT  24.437 4.656 24.833 18.216 ;
     RECT  24.437 19.248 24.905 30.744 ;
     RECT  24.419 55.152 25.057 58.152 ;
     RECT  24.833 4.656 25.139 13.656 ;
     RECT  25.139 9.36 25.157 13.656 ;
     RECT  24.329 31.92 25.265 31.992 ;
     RECT  25.139 4.656 25.283 8.328 ;
     RECT  24.905 26.88 25.283 30.744 ;
     RECT  24.833 15.456 25.285 18.216 ;
     RECT  24.905 19.248 25.285 25.56 ;
     RECT  25.283 4.944 25.301 8.328 ;
     RECT  25.157 11.856 25.373 13.656 ;
     RECT  25.057 55.152 25.381 58.056 ;
     RECT  24.304 52.992 25.436 53.016 ;
     RECT  25.381 54.72 25.436 58.056 ;
     RECT  24.304 1.92 25.441 3.336 ;
     RECT  24.304 33.072 25.477 34.92 ;
     RECT  24.304 36 25.477 38.184 ;
     RECT  25.441 1.92 25.484 3.624 ;
     RECT  25.436 52.992 25.523 58.056 ;
     RECT  25.484 1.152 25.571 3.624 ;
     RECT  24.304 46.608 25.589 47.208 ;
     RECT  25.523 52.992 25.589 53.592 ;
     RECT  25.571 1.248 25.625 3.624 ;
     RECT  24.797 39.312 25.669 40.44 ;
     RECT  25.301 4.992 25.697 8.328 ;
     RECT  25.283 26.928 25.981 30.744 ;
     RECT  25.669 39.312 26.117 40.536 ;
     RECT  25.157 9.36 26.149 10.872 ;
     RECT  25.373 11.856 26.149 12.84 ;
     RECT  25.477 33.072 26.149 38.184 ;
     RECT  26.117 39.168 26.149 40.536 ;
     RECT  25.523 54.72 26.269 58.056 ;
     RECT  26.269 54.72 26.353 58.152 ;
     RECT  26.149 33.072 26.377 40.536 ;
     RECT  25.625 1.488 26.54 3.624 ;
     RECT  25.697 4.992 26.54 5.016 ;
     RECT  24.613 59.856 26.561 60.408 ;
     RECT  26.149 9.36 26.665 12.84 ;
     RECT  26.54 1.488 26.708 5.016 ;
     RECT  25.697 6.048 26.708 8.328 ;
     RECT  26.665 9.36 26.708 13.128 ;
     RECT  25.285 15.456 26.708 25.56 ;
     RECT  25.981 26.928 26.708 30.84 ;
     RECT  25.265 31.968 26.708 31.992 ;
     RECT  26.377 33.072 26.708 41.4 ;
     RECT  25.765 46.176 26.708 46.2 ;
     RECT  25.589 47.184 26.708 47.208 ;
     RECT  25.589 53.568 26.708 53.592 ;
     RECT  26.353 54.72 26.708 58.062 ;
     RECT  26.561 59.904 26.777 60.408 ;
     RECT  26.708 1.488 27.004 58.062 ;
     RECT  27.004 33.024 27.173 37.752 ;
     RECT  27.004 39.312 27.173 39.336 ;
     RECT  26.777 60.288 27.203 60.408 ;
     RECT  27.004 55.248 27.251 58.062 ;
     RECT  27.004 12 27.281 14.904 ;
     RECT  27.251 55.728 27.299 58.062 ;
     RECT  27.173 33.072 27.317 37.752 ;
     RECT  27.004 1.488 27.353 7.992 ;
     RECT  27.004 16.32 27.389 28.968 ;
     RECT  27.299 55.824 27.397 58.062 ;
     RECT  27.397 55.824 27.493 58.152 ;
     RECT  27.389 20.352 27.605 28.968 ;
     RECT  27.004 30.432 27.605 31.992 ;
     RECT  27.605 20.352 27.628 25.704 ;
     RECT  27.281 12.096 27.749 14.904 ;
     RECT  27.493 55.824 27.781 58.248 ;
     RECT  27.004 10.608 27.785 11.016 ;
     RECT  27.749 12.096 28.037 12.12 ;
     RECT  27.389 16.32 28.037 19.368 ;
     RECT  27.004 42.72 28.105 42.744 ;
     RECT  27.749 13.536 28.177 14.904 ;
     RECT  28.037 16.32 28.177 18.984 ;
     RECT  27.605 30.624 28.213 31.992 ;
     RECT  27.317 33.072 28.213 33.096 ;
     RECT  28.105 42.72 28.249 42.792 ;
     RECT  28.177 13.536 28.289 18.984 ;
     RECT  28.213 30.624 28.393 33.096 ;
     RECT  27.004 9.36 28.501 9.384 ;
     RECT  27.628 20.544 28.573 25.704 ;
     RECT  27.605 26.784 28.573 28.968 ;
     RECT  27.353 1.488 28.609 7.944 ;
     RECT  28.501 8.976 28.609 9.384 ;
     RECT  27.203 60.288 28.837 60.312 ;
     RECT  28.609 1.488 28.844 9.384 ;
     RECT  27.785 10.608 28.844 10.968 ;
     RECT  28.573 20.544 28.861 28.968 ;
     RECT  28.393 30.624 28.861 33.192 ;
     RECT  28.177 40.176 28.861 40.2 ;
     RECT  27.004 41.376 28.861 41.4 ;
     RECT  28.837 60.288 28.885 60.36 ;
     RECT  28.861 20.544 28.892 33.192 ;
     RECT  28.892 20.208 28.897 33.192 ;
     RECT  27.317 34.464 28.897 37.752 ;
     RECT  28.885 60.144 28.981 60.36 ;
     RECT  28.981 60.048 29.173 60.36 ;
     RECT  28.681 0.048 29.269 0.072 ;
     RECT  27.781 55.824 29.329 58.728 ;
     RECT  29.173 59.952 29.329 60.36 ;
     RECT  28.861 40.176 29.401 41.4 ;
     RECT  28.844 1.488 29.408 10.968 ;
     RECT  28.933 11.952 29.408 11.976 ;
     RECT  28.289 14.496 29.408 18.984 ;
     RECT  28.897 20.208 29.408 37.752 ;
     RECT  29.401 40.176 29.408 41.688 ;
     RECT  28.249 42.72 29.408 43.368 ;
     RECT  29.329 55.824 29.408 60.36 ;
     RECT  29.269 0.048 29.509 0.168 ;
     RECT  29.408 1.488 29.509 60.36 ;
     RECT  29.509 0.048 29.621 60.36 ;
     RECT  29.621 60.336 29.651 60.36 ;
     RECT  29.621 0.048 29.704 59.304 ;
     RECT  29.704 57.024 29.747 59.304 ;
     RECT  29.704 28.224 29.837 38.712 ;
     RECT  29.704 20.304 29.909 27.192 ;
     RECT  29.837 28.704 30.017 38.712 ;
     RECT  29.747 57.024 30.053 58.68 ;
     RECT  29.704 54.72 30.125 54.744 ;
     RECT  30.017 28.704 30.161 38.184 ;
     RECT  29.704 39.888 30.275 44.04 ;
     RECT  30.053 57.312 30.449 58.68 ;
     RECT  30.449 57.312 30.485 57.912 ;
     RECT  30.275 39.888 30.593 41.064 ;
     RECT  29.704 12.576 30.629 12.936 ;
     RECT  30.275 42.144 30.629 44.04 ;
     RECT  30.629 42.144 30.665 42.888 ;
     RECT  29.909 20.304 30.701 26.904 ;
     RECT  30.593 39.888 30.701 41.016 ;
     RECT  29.704 15.216 30.769 18.984 ;
     RECT  30.701 20.304 30.769 24.408 ;
     RECT  30.665 42.144 30.773 42.84 ;
     RECT  30.697 13.056 30.949 13.32 ;
     RECT  30.629 44.016 30.985 44.04 ;
     RECT  30.701 25.44 30.989 26.904 ;
     RECT  29.704 0.048 31.097 11.448 ;
     RECT  30.161 30.624 31.309 38.184 ;
     RECT  30.985 44.016 31.333 44.088 ;
     RECT  31.292 45.312 31.333 45.336 ;
     RECT  30.161 28.704 31.345 29.064 ;
     RECT  30.949 13.056 31.669 13.896 ;
     RECT  30.769 15.216 31.669 24.408 ;
     RECT  31.669 13.056 31.909 24.408 ;
     RECT  30.989 25.44 31.909 26.808 ;
     RECT  31.345 27.984 31.949 29.064 ;
     RECT  31.309 30.576 31.949 38.184 ;
     RECT  31.333 44.016 31.957 45.336 ;
     RECT  31.909 13.056 32.029 26.808 ;
     RECT  31.949 27.984 32.065 38.184 ;
     RECT  31.097 0.096 32.108 11.448 ;
     RECT  32.029 12.48 32.108 26.808 ;
     RECT  32.065 27.984 32.108 38.808 ;
     RECT  30.701 39.888 32.108 40.968 ;
     RECT  30.773 42.144 32.108 42.744 ;
     RECT  31.957 43.824 32.108 45.336 ;
     RECT  31.333 47.328 32.108 47.352 ;
     RECT  30.485 57.6 32.108 57.912 ;
     RECT  32.108 0.096 32.3 57.912 ;
     RECT  32.3 0.096 32.404 58.062 ;
     RECT  32.404 20.928 32.465 26.904 ;
     RECT  32.404 47.328 32.465 47.352 ;
     RECT  32.404 57.6 32.501 57.912 ;
     RECT  32.404 0.096 32.537 19.368 ;
     RECT  32.404 44.16 32.537 45 ;
     RECT  32.537 16.032 32.609 19.368 ;
     RECT  32.404 27.888 32.681 41.112 ;
     RECT  32.681 27.888 32.825 39.24 ;
     RECT  32.825 27.888 32.861 38.808 ;
     RECT  32.537 0.096 32.933 14.76 ;
     RECT  32.933 10.272 33.005 14.76 ;
     RECT  32.609 16.032 33.005 18.504 ;
     RECT  32.861 27.888 33.1 38.424 ;
     RECT  32.681 40.848 33.149 41.112 ;
     RECT  32.501 57.84 33.149 57.912 ;
     RECT  33.005 17.04 33.155 18.504 ;
     RECT  33.149 40.944 33.185 41.112 ;
     RECT  33.1 27.888 33.251 35.496 ;
     RECT  33.185 40.944 33.257 40.968 ;
     RECT  32.465 20.928 33.365 24.6 ;
     RECT  33.365 20.928 33.433 24.216 ;
     RECT  32.465 25.776 33.469 26.904 ;
     RECT  33.251 27.888 33.469 35.352 ;
     RECT  33.433 20.064 33.577 24.216 ;
     RECT  33.005 10.272 33.635 14.52 ;
     RECT  32.537 44.16 33.649 44.952 ;
     RECT  33.469 25.776 33.653 35.352 ;
     RECT  33.577 19.296 33.689 24.216 ;
     RECT  33.155 17.04 33.731 18.264 ;
     RECT  33.635 10.272 33.797 13.368 ;
     RECT  33.797 13.056 33.833 13.368 ;
     RECT  32.404 42.144 34.081 42.312 ;
     RECT  33.1 36.48 34.153 38.424 ;
     RECT  34.081 42.144 34.153 42.744 ;
     RECT  34.153 36.48 34.172 39 ;
     RECT  33.653 31.344 34.225 35.352 ;
     RECT  34.172 36.48 34.225 39.864 ;
     RECT  34.225 31.344 34.364 39.864 ;
     RECT  34.153 41.424 34.364 42.744 ;
     RECT  33.653 25.776 34.405 30.36 ;
     RECT  33.649 44.16 34.585 45 ;
     RECT  32.404 46.176 34.585 46.2 ;
     RECT  34.405 25.584 34.765 30.36 ;
     RECT  34.765 25.296 34.801 30.36 ;
     RECT  34.364 31.344 34.801 42.744 ;
     RECT  32.933 0.096 34.808 9.048 ;
     RECT  33.797 10.272 34.808 11.64 ;
     RECT  33.833 13.104 34.808 13.368 ;
     RECT  33.635 14.4 34.808 14.52 ;
     RECT  33.005 16.032 34.808 16.056 ;
     RECT  33.731 17.04 34.808 18.216 ;
     RECT  33.689 19.296 34.808 24.12 ;
     RECT  34.801 25.296 34.808 42.744 ;
     RECT  34.585 44.16 34.808 46.2 ;
     RECT  33.149 57.84 34.808 57.864 ;
     RECT  34.808 0.096 35 57.864 ;
     RECT  35 0.096 35.104 58.062 ;
     RECT  35.104 44.976 35.165 46.2 ;
     RECT  35.104 11.904 35.219 11.928 ;
     RECT  35.104 34.128 35.219 35.208 ;
     RECT  35.104 31.968 35.245 33.048 ;
     RECT  35.104 0.096 35.363 10.728 ;
     RECT  35.104 14.448 35.363 18.744 ;
     RECT  35.104 28.416 35.381 30.888 ;
     RECT  35.104 20.064 35.417 26.856 ;
     RECT  35.363 14.448 35.597 16.584 ;
     RECT  35.417 20.736 35.597 26.856 ;
     RECT  35.363 0.192 35.705 10.728 ;
     RECT  35.597 22.464 35.741 26.856 ;
     RECT  35.363 17.616 35.843 18.744 ;
     RECT  35.597 14.448 35.891 16.248 ;
     RECT  35.891 14.448 35.921 16.152 ;
     RECT  35.741 25.104 35.939 26.856 ;
     RECT  35.104 47.28 36.029 47.304 ;
     RECT  35.381 28.608 36.065 30.888 ;
     RECT  35.741 22.464 36.137 23.928 ;
     RECT  36.065 28.608 36.137 30.84 ;
     RECT  35.104 13.008 36.205 13.128 ;
     RECT  35.165 45.552 36.229 46.2 ;
     RECT  35.843 17.856 36.245 18.744 ;
     RECT  36.229 45.312 36.275 46.2 ;
     RECT  36.245 18.288 36.421 18.744 ;
     RECT  36.413 57.024 36.421 57.048 ;
     RECT  35.597 20.736 36.467 21.288 ;
     RECT  36.38 55.536 36.467 55.56 ;
     RECT  36.421 11.712 36.469 11.736 ;
     RECT  36.205 12.72 36.469 13.128 ;
     RECT  36.275 45.312 36.469 46.104 ;
     RECT  35.104 40.32 36.515 43.56 ;
     RECT  35.921 14.592 36.533 16.152 ;
     RECT  35.705 9.024 36.565 10.728 ;
     RECT  36.469 11.712 36.565 13.128 ;
     RECT  35.705 0.192 36.745 7.896 ;
     RECT  36.421 59.952 36.745 59.976 ;
     RECT  36.565 9.024 36.764 13.128 ;
     RECT  36.421 57.024 36.781 57.192 ;
     RECT  36.745 59.952 36.851 60.408 ;
     RECT  36.781 57.024 36.853 58.104 ;
     RECT  36.745 0.192 36.889 7.944 ;
     RECT  36.764 9.024 36.889 13.32 ;
     RECT  36.533 14.592 36.889 16.056 ;
     RECT  36.851 59.952 36.901 59.976 ;
     RECT  36.853 57.024 36.947 58.152 ;
     RECT  36.457 48.96 36.949 48.984 ;
     RECT  36.901 59.856 37.072 59.976 ;
     RECT  36.889 0.192 37.141 13.32 ;
     RECT  36.889 14.448 37.141 16.056 ;
     RECT  36.949 48.384 37.177 49.032 ;
     RECT  37.072 59.808 37.253 59.976 ;
     RECT  36.137 22.464 37.349 23.112 ;
     RECT  36.947 57.024 37.381 58.104 ;
     RECT  36.137 28.848 37.429 30.84 ;
     RECT  37.141 0.192 37.508 16.056 ;
     RECT  36.421 18.288 37.508 19.656 ;
     RECT  37.349 21.648 37.508 23.112 ;
     RECT  35.939 25.104 37.508 25.32 ;
     RECT  35.939 26.4 37.508 26.856 ;
     RECT  37.429 28.176 37.508 30.84 ;
     RECT  35.245 31.968 37.508 32.76 ;
     RECT  35.219 34.896 37.508 35.208 ;
     RECT  35.104 36.48 37.508 39.336 ;
     RECT  36.515 40.32 37.508 43.32 ;
     RECT  36.469 45.12 37.508 46.104 ;
     RECT  37.177 47.904 37.508 49.032 ;
     RECT  36.764 55.248 37.508 55.272 ;
     RECT  37.381 56.496 37.508 58.104 ;
     RECT  37.508 0.192 37.804 58.104 ;
     RECT  37.804 0.192 37.901 3.384 ;
     RECT  37.804 31.968 37.955 32.328 ;
     RECT  37.804 33.648 37.955 35.448 ;
     RECT  37.804 55.008 37.955 58.104 ;
     RECT  37.253 59.856 37.997 59.976 ;
     RECT  37.804 14.112 38.045 17.64 ;
     RECT  37.901 0.432 38.081 3.144 ;
     RECT  37.804 29.04 38.147 30.36 ;
     RECT  37.997 59.856 38.185 60.36 ;
     RECT  37.804 44.88 38.189 49.368 ;
     RECT  37.804 36.576 38.195 39.72 ;
     RECT  37.955 55.296 38.213 58.104 ;
     RECT  38.045 14.448 38.225 17.64 ;
     RECT  38.081 0.432 38.261 2.856 ;
     RECT  37.804 4.992 38.261 12.264 ;
     RECT  37.804 22.032 38.291 27.384 ;
     RECT  38.213 55.296 38.297 58.152 ;
     RECT  38.185 59.856 38.369 60.408 ;
     RECT  38.261 0.48 38.405 2.856 ;
     RECT  38.405 0.48 38.477 1.608 ;
     RECT  37.804 41.136 38.579 43.272 ;
     RECT  38.291 22.032 38.585 26.904 ;
     RECT  38.585 23.76 38.693 26.904 ;
     RECT  38.477 1.008 38.729 1.608 ;
     RECT  38.585 22.032 38.765 22.776 ;
     RECT  38.297 55.296 38.765 58.008 ;
     RECT  38.225 14.496 38.771 17.64 ;
     RECT  38.771 14.496 38.801 15.336 ;
     RECT  38.765 22.608 38.801 22.776 ;
     RECT  38.147 29.472 38.801 30.36 ;
     RECT  38.189 47.328 38.801 49.368 ;
     RECT  38.729 1.008 38.837 1.416 ;
     RECT  38.261 4.992 38.837 11.736 ;
     RECT  38.765 57.024 38.837 58.008 ;
     RECT  38.369 60.336 38.845 60.408 ;
     RECT  38.693 24.528 38.873 26.904 ;
     RECT  38.195 36.816 38.909 39.288 ;
     RECT  38.837 1.008 38.945 1.032 ;
     RECT  38.845 60.336 38.963 60.36 ;
     RECT  38.771 16.416 39.011 17.64 ;
     RECT  37.804 18.672 39.011 18.696 ;
     RECT  37.955 34.416 39.121 35.448 ;
     RECT  39.121 34.416 39.157 35.496 ;
     RECT  38.909 38.4 39.157 39.288 ;
     RECT  38.189 44.88 39.157 46.248 ;
     RECT  38.801 47.328 39.157 49.272 ;
     RECT  38.765 55.296 39.203 55.848 ;
     RECT  38.579 41.424 39.229 43.272 ;
     RECT  38.837 9.36 39.445 11.736 ;
     RECT  38.797 12.96 39.445 12.984 ;
     RECT  39.493 50.496 39.517 50.52 ;
     RECT  39.229 41.424 39.637 43.896 ;
     RECT  38.405 2.832 39.805 2.856 ;
     RECT  39.011 17.616 39.805 17.64 ;
     RECT  39.157 38.4 39.949 40.152 ;
     RECT  39.637 41.184 39.949 43.896 ;
     RECT  38.909 36.816 40.021 37.416 ;
     RECT  39.949 38.4 40.021 43.896 ;
     RECT  38.873 24.528 40.069 26.856 ;
     RECT  39.805 2.832 40.208 3.864 ;
     RECT  38.837 4.992 40.208 8.28 ;
     RECT  39.445 9.36 40.208 12.984 ;
     RECT  38.801 14.496 40.208 14.952 ;
     RECT  39.011 16.416 40.208 16.44 ;
     RECT  39.805 17.616 40.208 17.736 ;
     RECT  37.804 20.592 40.208 20.616 ;
     RECT  38.801 22.752 40.208 22.776 ;
     RECT  40.069 24.528 40.208 27.384 ;
     RECT  38.801 29.568 40.208 30.36 ;
     RECT  37.955 31.968 40.208 32.28 ;
     RECT  39.157 33.6 40.208 35.496 ;
     RECT  40.021 36.816 40.208 43.896 ;
     RECT  39.157 44.88 40.208 49.272 ;
     RECT  39.517 50.496 40.208 50.712 ;
     RECT  39.193 53.04 40.208 53.064 ;
     RECT  39.203 55.296 40.208 55.56 ;
     RECT  38.837 57.024 40.208 57.72 ;
     RECT  40.208 2.148 40.312 57.792 ;
     RECT  40.312 2.418 40.4 57.792 ;
     RECT  40.4 2.418 40.504 58.062 ;
     RECT  40.504 31.968 40.529 32.28 ;
     RECT  40.504 16.656 40.565 17.64 ;
     RECT  40.504 34.368 40.565 35.496 ;
     RECT  40.504 3.312 40.643 12.024 ;
     RECT  40.643 3.312 40.673 8.904 ;
     RECT  40.643 10.32 40.739 12.024 ;
     RECT  40.504 20.352 40.745 20.904 ;
     RECT  40.673 8.88 40.853 8.904 ;
     RECT  40.565 16.656 40.961 16.68 ;
     RECT  40.673 3.312 41.033 7.656 ;
     RECT  41.033 4.368 41.069 7.656 ;
     RECT  40.504 42.72 41.123 49.272 ;
     RECT  41.069 4.416 41.213 7.656 ;
     RECT  40.739 10.368 41.249 12.024 ;
     RECT  41.123 42.72 41.357 45.864 ;
     RECT  41.249 10.368 41.393 11.256 ;
     RECT  40.504 26.832 41.501 27.912 ;
     RECT  41.357 42.72 41.533 45.816 ;
     RECT  41.533 42.192 41.557 45.816 ;
     RECT  40.504 18.816 41.564 19.176 ;
     RECT  40.504 22.176 41.605 22.776 ;
     RECT  40.504 51.648 41.605 51.672 ;
     RECT  40.565 34.368 41.641 35.304 ;
     RECT  41.605 22.128 41.645 22.776 ;
     RECT  41.605 51.648 41.645 51.768 ;
     RECT  41.564 18.816 41.651 19.656 ;
     RECT  40.745 20.88 41.651 20.904 ;
     RECT  41.645 22.128 41.689 22.44 ;
     RECT  40.504 37.104 41.701 40.44 ;
     RECT  41.701 37.104 41.747 41.064 ;
     RECT  41.557 42.144 41.749 45.816 ;
     RECT  41.645 51.744 41.821 51.768 ;
     RECT  41.123 46.992 41.843 49.272 ;
     RECT  41.747 37.104 41.857 39.768 ;
     RECT  41.749 42.096 41.861 45.816 ;
     RECT  41.501 27.888 41.9 27.912 ;
     RECT  41.641 34.368 41.929 35.4 ;
     RECT  41.845 57.984 41.932 58.008 ;
     RECT  41.393 10.368 41.989 10.872 ;
     RECT  41.033 3.312 42.001 3.384 ;
     RECT  41.989 57.6 42.001 57.624 ;
     RECT  42.001 2.448 42.109 3.384 ;
     RECT  41.857 9.072 42.133 9.096 ;
     RECT  41.989 10.08 42.133 10.872 ;
     RECT  41.821 51.744 42.14 52.488 ;
     RECT  40.504 25.2 42.421 25.272 ;
     RECT  41.929 34.176 42.421 35.4 ;
     RECT  41.857 37.056 42.421 39.768 ;
     RECT  41.861 42.144 42.421 45.816 ;
     RECT  40.529 31.968 42.433 31.992 ;
     RECT  42.289 33.12 42.433 33.144 ;
     RECT  41.9 27.888 42.577 28.488 ;
     RECT  40.504 29.568 42.577 30.36 ;
     RECT  41.689 22.176 42.613 22.44 ;
     RECT  41.213 4.416 42.649 6.936 ;
     RECT  41.785 7.92 42.649 7.944 ;
     RECT  41.948 55.824 42.649 55.848 ;
     RECT  42.109 2.352 42.721 3.384 ;
     RECT  42.649 55.824 42.757 56.04 ;
     RECT  42.001 57.024 42.757 57.624 ;
     RECT  42.757 55.824 42.793 57.624 ;
     RECT  42.721 2.256 42.908 3.384 ;
     RECT  42.649 4.416 42.908 7.944 ;
     RECT  42.133 9.072 42.908 10.872 ;
     RECT  41.651 18.816 42.908 18.84 ;
     RECT  41.857 20.592 42.908 20.664 ;
     RECT  42.613 22.176 42.908 22.776 ;
     RECT  42.421 25.056 42.908 25.272 ;
     RECT  41.501 26.832 42.908 26.856 ;
     RECT  42.577 27.888 42.908 30.36 ;
     RECT  42.433 31.968 42.908 33.144 ;
     RECT  42.421 34.176 42.908 39.768 ;
     RECT  41.747 41.04 42.908 41.064 ;
     RECT  42.421 42.144 42.908 46.008 ;
     RECT  41.843 47.328 42.908 49.272 ;
     RECT  42.14 51.744 42.908 53.16 ;
     RECT  42.181 54.144 42.908 54.168 ;
     RECT  42.793 55.68 42.908 57.624 ;
     RECT  42.908 2.148 43.012 57.792 ;
     RECT  43.012 2.256 43.1 57.792 ;
     RECT  43.1 2.256 43.204 58.062 ;
     RECT  41.785 59.856 43.253 59.88 ;
     RECT  43.204 25.2 43.331 25.272 ;
     RECT  43.204 47.28 43.331 50.472 ;
     RECT  43.204 51.504 43.331 58.008 ;
     RECT  43.331 52.896 43.345 58.008 ;
     RECT  43.204 4.512 43.373 11.4 ;
     RECT  43.345 54.096 43.379 58.008 ;
     RECT  43.204 31.968 43.481 46.104 ;
     RECT  43.253 59.856 43.523 60.408 ;
     RECT  43.204 3.312 43.525 3.432 ;
     RECT  43.481 33.12 43.619 46.104 ;
     RECT  43.523 59.856 43.619 59.976 ;
     RECT  43.204 2.256 43.667 2.28 ;
     RECT  43.619 59.904 43.715 59.976 ;
     RECT  43.619 34.704 43.733 46.104 ;
     RECT  43.733 34.704 43.805 44.616 ;
     RECT  43.379 54.096 43.859 54.12 ;
     RECT  43.204 26.832 43.9 30.792 ;
     RECT  43.805 34.704 43.907 39.624 ;
     RECT  43.715 59.952 43.907 59.976 ;
     RECT  43.9 26.832 43.949 30.696 ;
     RECT  43.805 41.088 43.955 44.616 ;
     RECT  43.949 26.832 43.985 30.6 ;
     RECT  43.907 34.704 44.092 39.336 ;
     RECT  43.373 4.56 44.237 11.4 ;
     RECT  43.525 3.312 44.341 3.384 ;
     RECT  43.331 47.28 44.377 48.504 ;
     RECT  43.331 49.536 44.377 50.472 ;
     RECT  43.331 51.504 44.377 51.768 ;
     RECT  43.345 52.896 44.377 52.92 ;
     RECT  43.379 55.248 44.381 58.008 ;
     RECT  44.341 2.832 44.417 3.384 ;
     RECT  44.377 47.28 44.435 50.472 ;
     RECT  44.435 47.712 44.483 50.472 ;
     RECT  44.377 51.504 44.483 52.92 ;
     RECT  43.619 33.12 44.557 33.336 ;
     RECT  44.417 2.832 44.561 2.856 ;
     RECT  44.381 55.248 44.561 57.048 ;
     RECT  44.557 33.024 44.593 33.336 ;
     RECT  44.237 4.56 44.633 9.048 ;
     RECT  44.237 10.368 44.821 11.4 ;
     RECT  43.481 31.968 44.821 31.992 ;
     RECT  44.593 33.024 44.821 33.672 ;
     RECT  44.437 54.144 44.881 54.168 ;
     RECT  43.081 0.048 44.885 0.072 ;
     RECT  44.092 38.4 45.025 39.336 ;
     RECT  43.955 41.088 45.025 44.184 ;
     RECT  45.025 38.4 45.133 44.184 ;
     RECT  44.821 10.368 45.529 12.216 ;
     RECT  44.633 5.136 45.565 9.048 ;
     RECT  45.529 10.08 45.565 12.216 ;
     RECT  45.565 5.136 45.608 12.216 ;
     RECT  43.204 22.56 45.608 22.584 ;
     RECT  43.331 25.248 45.608 25.272 ;
     RECT  43.985 26.832 45.608 30.36 ;
     RECT  44.821 31.968 45.608 33.672 ;
     RECT  44.092 34.704 45.608 37.32 ;
     RECT  45.133 38.4 45.608 44.712 ;
     RECT  43.733 46.08 45.608 46.104 ;
     RECT  44.483 47.712 45.608 48.648 ;
     RECT  44.483 49.872 45.608 50.472 ;
     RECT  44.483 51.504 45.608 51.96 ;
     RECT  44.881 54.096 45.608 54.168 ;
     RECT  44.561 55.248 45.608 55.896 ;
     RECT  44.561 57.024 45.608 57.048 ;
     RECT  45.608 2.148 45.712 57.792 ;
     RECT  45.712 2.418 45.8 57.792 ;
     RECT  45.8 2.418 45.904 58.062 ;
     RECT  45.904 5.232 46.019 6.12 ;
     RECT  45.904 47.856 46.019 51.336 ;
     RECT  45.904 7.392 46.029 12.168 ;
     RECT  45.904 21.504 46.045 23.544 ;
     RECT  46.029 7.92 46.163 12.168 ;
     RECT  45.904 20.496 46.181 20.52 ;
     RECT  46.019 50.64 46.181 51.336 ;
     RECT  46.163 10.08 46.325 12.168 ;
     RECT  45.904 36 46.403 42.216 ;
     RECT  46.403 36 46.433 40.968 ;
     RECT  46.019 47.856 46.433 49.368 ;
     RECT  46.163 8.448 46.505 8.76 ;
     RECT  45.904 53.376 46.787 54.744 ;
     RECT  46.045 23.52 46.865 23.544 ;
     RECT  45.904 25.248 46.897 25.272 ;
     RECT  45.904 46.512 46.94 46.536 ;
     RECT  46.433 47.856 46.94 48.456 ;
     RECT  46.325 10.224 46.973 12.168 ;
     RECT  46.403 42.192 47.029 42.216 ;
     RECT  45.904 43.296 47.029 44.712 ;
     RECT  46.019 5.232 47.045 6.024 ;
     RECT  46.045 21.504 47.045 22.248 ;
     RECT  47.029 42.192 47.075 44.712 ;
     RECT  47.045 21.504 47.081 21.528 ;
     RECT  46.787 54.72 47.081 54.744 ;
     RECT  46.787 53.376 47.18 53.4 ;
     RECT  47.077 60.288 47.18 60.312 ;
     RECT  45.904 31.968 47.221 34.776 ;
     RECT  47.18 52.56 47.267 53.4 ;
     RECT  46.181 50.64 47.324 50.712 ;
     RECT  47.221 3.312 47.329 3.336 ;
     RECT  47.324 50.64 47.329 50.856 ;
     RECT  47.221 31.968 47.333 34.92 ;
     RECT  46.433 40.752 47.333 40.968 ;
     RECT  47.221 23.856 47.365 23.88 ;
     RECT  46.897 25.248 47.365 25.56 ;
     RECT  45.904 26.832 47.401 30.36 ;
     RECT  47.401 26.832 47.437 30.456 ;
     RECT  47.075 44.448 47.545 44.712 ;
     RECT  47.221 57.984 47.557 58.008 ;
     RECT  46.433 36.24 47.589 39.624 ;
     RECT  47.545 44.448 47.605 45.192 ;
     RECT  46.94 46.512 47.605 48.456 ;
     RECT  47.329 2.784 47.653 3.336 ;
     RECT  47.269 55.296 47.66 55.56 ;
     RECT  47.557 57.696 47.761 58.008 ;
     RECT  47.589 36 47.797 39.624 ;
     RECT  47.365 23.856 47.833 25.56 ;
     RECT  47.797 35.472 47.893 39.624 ;
     RECT  47.075 42.192 47.893 43.32 ;
     RECT  47.605 44.448 47.893 48.456 ;
     RECT  47.18 60.288 47.941 60.408 ;
     RECT  47.66 55.296 48.037 55.608 ;
     RECT  47.653 2.496 48.049 4.056 ;
     RECT  48.049 1.728 48.085 4.056 ;
     RECT  48.085 1.152 48.121 4.056 ;
     RECT  48.037 55.296 48.133 56.28 ;
     RECT  47.761 57.696 48.133 58.152 ;
     RECT  47.329 50.496 48.181 50.856 ;
     RECT  47.893 41.952 48.193 43.32 ;
     RECT  47.893 44.448 48.193 49.032 ;
     RECT  47.005 20.4 48.229 20.424 ;
     RECT  47.257 22.512 48.229 22.536 ;
     RECT  47.941 59.856 48.233 60.408 ;
     RECT  47.509 0.048 48.265 0.072 ;
     RECT  47.267 53.376 48.301 53.4 ;
     RECT  48.121 1.152 48.308 4.2 ;
     RECT  47.045 5.28 48.308 6.024 ;
     RECT  46.505 8.736 48.308 8.76 ;
     RECT  46.973 10.416 48.308 12.168 ;
     RECT  48.229 19.536 48.308 20.424 ;
     RECT  48.229 21.792 48.308 22.536 ;
     RECT  47.833 23.856 48.308 25.8 ;
     RECT  47.437 26.832 48.308 30.984 ;
     RECT  47.333 31.968 48.308 34.44 ;
     RECT  47.893 35.472 48.308 39.864 ;
     RECT  47.333 40.848 48.308 40.968 ;
     RECT  48.193 41.952 48.308 49.032 ;
     RECT  48.181 50.496 48.308 50.904 ;
     RECT  48.301 53.376 48.308 53.64 ;
     RECT  48.133 55.152 48.308 56.28 ;
     RECT  48.133 57.6 48.308 58.152 ;
     RECT  48.233 59.904 48.377 60.408 ;
     RECT  48.308 1.152 48.604 58.152 ;
     RECT  48.265 0.048 48.613 0.12 ;
     RECT  48.604 1.152 48.613 6.408 ;
     RECT  48.604 35.472 48.629 42.216 ;
     RECT  48.604 31.968 48.665 34.392 ;
     RECT  48.377 60.288 48.755 60.408 ;
     RECT  48.604 49.728 48.773 51.864 ;
     RECT  48.604 58.128 48.803 58.152 ;
     RECT  48.755 60.384 48.803 60.408 ;
     RECT  48.604 44.784 48.917 48.264 ;
     RECT  48.604 20.592 48.945 30.984 ;
     RECT  48.604 18.768 49.043 19.56 ;
     RECT  48.604 55.248 49.043 57.048 ;
     RECT  49.043 19.008 49.061 19.56 ;
     RECT  49.043 55.248 49.097 56.472 ;
     RECT  49.097 55.536 49.241 56.472 ;
     RECT  49.241 55.632 49.285 56.472 ;
     RECT  48.604 53.568 49.324 53.832 ;
     RECT  48.629 35.856 49.475 42.216 ;
     RECT  48.773 49.728 49.493 50.856 ;
     RECT  48.604 15.36 49.573 15.384 ;
     RECT  48.945 30.336 49.597 30.984 ;
     RECT  48.665 31.968 49.597 34.2 ;
     RECT  49.475 35.856 49.597 36.84 ;
     RECT  49.573 15.36 49.619 16.008 ;
     RECT  49.285 56.448 49.637 56.472 ;
     RECT  48.604 14.256 49.669 14.28 ;
     RECT  48.773 51.84 49.676 51.864 ;
     RECT  48.945 20.592 49.745 29.208 ;
     RECT  49.597 35.76 49.745 36.84 ;
     RECT  49.676 51.84 49.745 52.344 ;
     RECT  49.669 13.584 49.756 14.28 ;
     RECT  49.745 52.32 49.763 52.344 ;
     RECT  48.917 47.28 49.813 48.264 ;
     RECT  49.493 49.728 49.813 49.752 ;
     RECT  48.604 10.416 49.817 12.504 ;
     RECT  49.061 19.008 49.817 19.32 ;
     RECT  48.613 0.048 49.885 6.408 ;
     RECT  49.475 37.968 49.885 42.216 ;
     RECT  48.604 43.296 49.885 43.656 ;
     RECT  48.917 44.784 49.925 45.72 ;
     RECT  48.604 8.736 49.961 8.76 ;
     RECT  49.324 53.568 49.961 53.592 ;
     RECT  49.619 15.984 50.197 16.008 ;
     RECT  49.745 24.48 50.197 29.208 ;
     RECT  49.597 30.336 50.197 34.2 ;
     RECT  49.813 47.28 50.209 49.752 ;
     RECT  49.493 50.832 50.245 50.856 ;
     RECT  49.925 44.928 50.309 45.72 ;
     RECT  50.209 46.752 50.309 49.752 ;
     RECT  50.197 24.48 50.351 34.2 ;
     RECT  49.885 0.048 50.387 7.032 ;
     RECT  50.387 1.2 50.641 7.032 ;
     RECT  50.641 1.2 50.675 7.128 ;
     RECT  49.745 35.856 50.677 36.84 ;
     RECT  49.885 37.968 50.677 43.656 ;
     RECT  50.636 14.544 50.713 14.568 ;
     RECT  50.197 15.984 50.713 17.112 ;
     RECT  50.309 44.928 50.773 49.752 ;
     RECT  50.245 50.832 50.773 51.336 ;
     RECT  50.713 14.544 50.785 17.112 ;
     RECT  50.351 24.48 50.785 34.728 ;
     RECT  50.677 35.856 50.785 43.656 ;
     RECT  50.773 44.928 50.821 51.336 ;
     RECT  50.497 13.44 50.869 13.464 ;
     RECT  50.785 14.496 50.869 17.112 ;
     RECT  49.817 19.008 50.869 19.272 ;
     RECT  49.745 20.592 50.869 23.448 ;
     RECT  49.817 10.416 50.893 12.264 ;
     RECT  50.869 13.44 50.893 17.112 ;
     RECT  50.785 24.48 50.893 43.656 ;
     RECT  50.821 44.928 50.893 52.296 ;
     RECT  50.675 1.92 51.008 7.128 ;
     RECT  50.893 10.416 51.008 17.112 ;
     RECT  50.869 18.768 51.008 19.272 ;
     RECT  50.869 20.256 51.008 23.448 ;
     RECT  50.893 24.48 51.008 52.296 ;
     RECT  51.008 1.92 51.059 57.792 ;
     RECT  51.059 2.016 51.2 57.792 ;
     RECT  51.2 2.016 51.304 58.062 ;
     RECT  50.387 0.048 51.443 0.168 ;
     RECT  51.304 43.104 51.491 47.4 ;
     RECT  51.304 40.848 51.509 41.064 ;
     RECT  51.304 36.96 51.635 39.864 ;
     RECT  51.304 2.016 51.689 7.752 ;
     RECT  51.304 14.064 51.689 16.296 ;
     RECT  51.304 32.976 51.725 35.304 ;
     RECT  51.304 10.416 51.731 13.08 ;
     RECT  51.689 14.064 51.797 16.248 ;
     RECT  51.725 33.024 51.797 35.304 ;
     RECT  51.689 2.016 51.869 6.6 ;
     RECT  51.443 0.048 52.013 0.12 ;
     RECT  51.304 17.328 52.013 17.688 ;
     RECT  51.304 25.056 52.013 31.992 ;
     RECT  52.013 25.104 52.049 31.992 ;
     RECT  51.304 19.296 52.085 20.616 ;
     RECT  51.797 33.072 52.121 35.304 ;
     RECT  51.304 9.072 52.193 9.096 ;
     RECT  51.689 7.728 52.297 7.752 ;
     RECT  51.635 36.96 52.301 37.08 ;
     RECT  51.304 49.008 52.307 52.488 ;
     RECT  51.635 38.208 52.309 39.864 ;
     RECT  51.509 40.848 52.309 40.968 ;
     RECT  52.121 33.696 52.333 35.304 ;
     RECT  51.304 21.792 52.405 22.296 ;
     RECT  52.049 25.104 52.445 27.336 ;
     RECT  52.405 21.648 52.513 22.296 ;
     RECT  51.797 15.168 52.589 16.248 ;
     RECT  51.731 11.232 52.657 13.08 ;
     RECT  51.797 14.064 52.657 14.088 ;
     RECT  52.307 49.008 52.657 50.616 ;
     RECT  52.085 19.296 52.693 20.088 ;
     RECT  52.513 21.12 52.693 22.296 ;
     RECT  51.304 23.328 52.693 23.352 ;
     RECT  52.309 38.208 52.693 40.968 ;
     RECT  52.657 11.232 52.765 14.088 ;
     RECT  51.491 43.104 52.776 47.304 ;
     RECT  52.693 38.112 52.885 41.064 ;
     RECT  52.776 42.576 52.943 47.304 ;
     RECT  52.693 21.12 52.945 23.352 ;
     RECT  52.765 11.136 53.169 14.088 ;
     RECT  52.589 15.984 53.173 16.248 ;
     RECT  52.013 17.328 53.173 17.64 ;
     RECT  51.869 2.016 53.341 2.616 ;
     RECT  51.869 3.936 53.341 6.6 ;
     RECT  52.945 21.12 53.341 23.4 ;
     RECT  52.333 33.696 53.341 35.592 ;
     RECT  52.301 36.96 53.341 37.032 ;
     RECT  52.943 42.576 53.413 47.688 ;
     RECT  52.657 48.72 53.413 50.616 ;
     RECT  53.341 2.016 53.525 6.6 ;
     RECT  52.445 25.584 53.557 27.336 ;
     RECT  52.049 28.704 53.557 31.992 ;
     RECT  53.413 42.576 53.557 50.616 ;
     RECT  52.307 51.648 53.557 51.672 ;
     RECT  53.557 42.576 53.593 51.672 ;
     RECT  53.557 52.944 53.593 52.968 ;
     RECT  53.557 25.584 53.665 31.992 ;
     RECT  53.525 2.148 53.708 6.6 ;
     RECT  52.297 7.728 53.708 8.136 ;
     RECT  52.297 9.984 53.708 10.008 ;
     RECT  53.169 11.136 53.708 14.856 ;
     RECT  53.173 15.984 53.708 17.64 ;
     RECT  52.693 19.104 53.708 20.088 ;
     RECT  53.341 21.12 53.708 23.688 ;
     RECT  53.665 25.536 53.708 31.992 ;
     RECT  53.341 33.696 53.708 37.032 ;
     RECT  52.885 38.112 53.708 41.208 ;
     RECT  53.593 42.576 53.708 52.968 ;
     RECT  53.708 2.148 53.812 57.792 ;
     RECT  53.812 2.352 53.9 57.792 ;
     RECT  53.9 2.352 54.004 58.062 ;
     RECT  54.004 50.064 54.065 51.672 ;
     RECT  54.004 10.224 54.137 16.008 ;
     RECT  54.137 10.224 54.179 10.248 ;
     RECT  54.137 11.232 54.179 16.008 ;
     RECT  54.004 18.816 54.317 19.896 ;
     RECT  54.179 11.232 54.323 15.048 ;
     RECT  54.323 11.232 54.353 13.848 ;
     RECT  54.004 2.352 54.425 2.376 ;
     RECT  54.317 19.296 54.569 19.896 ;
     RECT  54.004 38.208 54.604 42.792 ;
     RECT  54.004 47.568 54.611 49.032 ;
     RECT  54.004 3.408 54.713 8.472 ;
     RECT  54.611 47.856 54.785 49.032 ;
     RECT  54.323 15.024 54.821 15.048 ;
     RECT  54.004 21.12 54.821 27.192 ;
     RECT  54.004 31.92 54.821 32.088 ;
     RECT  54.569 19.296 54.857 19.8 ;
     RECT  54.821 21.216 54.893 27.192 ;
     RECT  54.713 4.128 54.899 8.472 ;
     RECT  54.893 21.984 54.947 27.192 ;
     RECT  54.899 4.128 54.965 8.232 ;
     RECT  54.004 28.176 54.997 30.36 ;
     RECT  54.965 4.128 55.001 4.488 ;
     RECT  54.065 50.064 55.033 50.664 ;
     RECT  54.604 38.208 55.037 41.256 ;
     RECT  54.065 51.648 55.037 51.672 ;
     RECT  54.965 5.472 55.091 8.232 ;
     RECT  54.947 24.912 55.141 27.192 ;
     RECT  54.997 28.176 55.141 30.84 ;
     RECT  54.821 31.92 55.141 31.992 ;
     RECT  55.037 38.208 55.141 39.336 ;
     RECT  54.004 44.304 55.141 44.328 ;
     RECT  55.141 37.584 55.187 39.336 ;
     RECT  54.604 42.48 55.213 42.792 ;
     RECT  55.141 24.912 55.283 31.992 ;
     RECT  54.004 45.984 55.285 46.104 ;
     RECT  54.947 21.984 55.289 23.928 ;
     RECT  55.033 49.584 55.321 50.664 ;
     RECT  54.353 11.232 55.397 13.08 ;
     RECT  54.857 19.296 55.397 19.512 ;
     RECT  55.283 24.912 55.397 28.392 ;
     RECT  55.187 37.584 55.397 38.232 ;
     RECT  55.285 45.984 55.397 46.776 ;
     RECT  55.141 44.304 55.429 44.424 ;
     RECT  55.532 56.352 55.573 56.376 ;
     RECT  55.429 44.064 55.609 44.424 ;
     RECT  55.397 45.984 55.609 46.104 ;
     RECT  55.573 55.776 55.621 56.376 ;
     RECT  55.573 57.6 55.621 57.624 ;
     RECT  54.785 47.856 55.753 48.552 ;
     RECT  55.321 49.584 55.753 51.336 ;
     RECT  55.621 55.776 55.753 57.624 ;
     RECT  55.753 55.776 55.82 58.152 ;
     RECT  55.82 55.248 55.858 58.152 ;
     RECT  54.004 34.608 55.861 36.312 ;
     RECT  55.091 5.76 56.005 8.232 ;
     RECT  55.858 55.248 56.069 58.2 ;
     RECT  56.077 9.792 56.113 9.816 ;
     RECT  55.397 11.232 56.113 12.024 ;
     RECT  55.397 13.008 56.113 13.08 ;
     RECT  52.013 0.048 56.189 0.072 ;
     RECT  55.141 33.168 56.221 33.192 ;
     RECT  56.245 60.288 56.257 60.312 ;
     RECT  55.187 39.312 56.329 39.336 ;
     RECT  55.289 21.984 56.401 22.152 ;
     RECT  55.001 4.464 56.408 4.488 ;
     RECT  56.005 5.76 56.408 8.664 ;
     RECT  56.113 9.792 56.408 12.024 ;
     RECT  56.113 13.008 56.408 13.944 ;
     RECT  55.645 16.368 56.408 16.392 ;
     RECT  54.004 17.616 56.408 17.64 ;
     RECT  55.397 19.296 56.408 19.32 ;
     RECT  56.401 21.984 56.408 22.248 ;
     RECT  55.289 23.28 56.408 23.688 ;
     RECT  55.397 25.008 56.408 28.392 ;
     RECT  55.283 29.616 56.408 31.992 ;
     RECT  56.221 33.168 56.408 33.288 ;
     RECT  55.861 34.368 56.408 36.312 ;
     RECT  55.397 37.632 56.408 38.232 ;
     RECT  56.329 39.216 56.408 39.336 ;
     RECT  55.037 41.136 56.408 41.256 ;
     RECT  55.213 42.48 56.408 43.032 ;
     RECT  55.609 44.064 56.408 44.472 ;
     RECT  55.609 45.696 56.408 46.104 ;
     RECT  55.753 47.856 56.408 51.336 ;
     RECT  56.069 55.248 56.408 58.68 ;
     RECT  56.408 2.148 56.512 58.68 ;
     RECT  56.512 2.418 56.704 58.68 ;
     RECT  56.704 47.856 56.765 51.912 ;
     RECT  56.704 36.288 56.801 36.312 ;
     RECT  56.257 59.856 56.869 60.312 ;
     RECT  56.765 47.856 56.945 49.032 ;
     RECT  56.765 50.064 56.981 51.912 ;
     RECT  56.981 50.064 57.011 51.24 ;
     RECT  56.704 37.68 57.125 43.176 ;
     RECT  56.704 26.064 57.197 35.304 ;
     RECT  57.125 41.136 57.197 43.176 ;
     RECT  56.704 44.16 57.269 46.68 ;
     RECT  56.704 55.008 57.349 58.68 ;
     RECT  57.197 26.064 57.374 30.888 ;
     RECT  56.704 16.032 57.377 17.208 ;
     RECT  56.704 2.418 57.517 2.856 ;
     RECT  56.869 59.856 57.59 60.36 ;
     RECT  56.704 19.92 57.635 22.248 ;
     RECT  57.197 41.184 57.635 43.176 ;
     RECT  57.349 55.008 57.673 56.376 ;
     RECT  57.59 59.856 57.683 60.312 ;
     RECT  57.377 16.032 57.697 16.056 ;
     RECT  56.945 47.856 57.701 47.88 ;
     RECT  57.673 56.352 57.779 56.376 ;
     RECT  57.683 60.144 57.779 60.312 ;
     RECT  57.269 44.16 57.817 46.152 ;
     RECT  57.197 31.968 57.841 35.304 ;
     RECT  56.704 4.464 57.868 12.504 ;
     RECT  57.868 4.464 57.875 8.472 ;
     RECT  57.817 44.16 57.875 46.104 ;
     RECT  57.868 9.792 57.877 12.504 ;
     RECT  56.704 13.632 57.877 14.28 ;
     RECT  57.877 9.792 57.913 14.28 ;
     RECT  57.697 15.456 57.913 16.056 ;
     RECT  57.875 8.112 57.917 8.472 ;
     RECT  56.704 23.28 57.953 24.936 ;
     RECT  57.841 31.968 57.953 35.4 ;
     RECT  57.779 60.144 57.971 60.168 ;
     RECT  57.011 50.16 57.973 50.616 ;
     RECT  57.769 52.464 58.019 52.488 ;
     RECT  57.517 2.064 58.057 2.856 ;
     RECT  57.125 37.68 58.117 40.056 ;
     RECT  58.057 1.44 58.165 2.856 ;
     RECT  57.377 17.184 58.165 17.208 ;
     RECT  57.953 33.024 58.165 35.4 ;
     RECT  56.945 49.008 58.165 49.032 ;
     RECT  57.973 50.16 58.165 51.24 ;
     RECT  57.913 9.792 58.381 16.056 ;
     RECT  58.165 17.184 58.381 17.64 ;
     RECT  58.165 33.024 58.489 35.496 ;
     RECT  58.117 36.48 58.489 36.504 ;
     RECT  58.117 37.68 58.489 40.152 ;
     RECT  57.875 4.464 58.561 6.936 ;
     RECT  57.349 57.6 58.643 58.68 ;
     RECT  58.489 33.024 58.669 40.152 ;
     RECT  57.635 41.184 58.669 42.84 ;
     RECT  57.733 47.136 58.669 47.784 ;
     RECT  58.643 57.6 58.78 58.152 ;
     RECT  57.374 26.112 58.837 30.888 ;
     RECT  58.669 33.024 58.837 42.84 ;
     RECT  57.875 44.352 58.837 46.104 ;
     RECT  58.78 57.6 58.861 58.104 ;
     RECT  58.165 0.816 58.885 2.856 ;
     RECT  58.561 4.224 58.885 6.936 ;
     RECT  58.381 9.792 58.933 17.64 ;
     RECT  58.669 47.088 58.981 47.784 ;
     RECT  58.165 49.008 58.981 51.24 ;
     RECT  58.885 0.192 59.108 2.856 ;
     RECT  58.885 3.984 59.108 6.936 ;
     RECT  57.917 8.304 59.108 8.472 ;
     RECT  58.933 9.792 59.108 18.216 ;
     RECT  57.635 20.208 59.108 22.248 ;
     RECT  57.953 24.144 59.108 24.936 ;
     RECT  58.837 26.064 59.108 30.888 ;
     RECT  57.953 31.968 59.108 31.992 ;
     RECT  58.837 33.024 59.108 46.104 ;
     RECT  58.981 47.088 59.108 51.24 ;
     RECT  57.673 55.008 59.108 55.032 ;
     RECT  58.861 57.6 59.108 58.062 ;
     RECT  59.108 0.192 59.404 58.062 ;
     RECT  59.404 0.192 59.425 15.576 ;
     RECT  59.404 33.024 59.465 38.808 ;
     RECT  59.404 19.248 59.537 19.272 ;
     RECT  59.404 20.4 59.555 31.992 ;
     RECT  59.404 44.352 59.555 50.76 ;
     RECT  59.404 40.032 59.651 42.84 ;
     RECT  59.555 21.024 59.692 31.992 ;
     RECT  59.555 45.168 59.825 48.792 ;
     RECT  59.692 23.664 59.897 31.992 ;
     RECT  59.825 45.168 60.113 48.456 ;
     RECT  59.692 21.024 60.185 22.632 ;
     RECT  59.651 42.72 60.185 42.84 ;
     RECT  59.425 0.096 60.217 15.576 ;
     RECT  60.185 42.72 60.221 42.744 ;
     RECT  59.404 16.56 60.293 17.928 ;
     RECT  60.113 45.168 60.329 48.12 ;
     RECT  59.897 24.384 60.437 31.992 ;
     RECT  59.555 49.776 60.437 50.76 ;
     RECT  60.217 0.048 60.469 15.576 ;
     RECT  60.293 16.56 60.469 16.776 ;
     RECT  59.465 33.024 60.469 38.76 ;
     RECT  59.651 40.032 60.469 41.064 ;
     RECT  60.437 24.384 60.473 24.456 ;
     RECT  60.437 49.776 60.617 50.04 ;
     RECT  60.437 26.016 60.689 31.992 ;
     RECT  60.469 33.024 60.725 41.064 ;
     RECT  60.293 17.904 60.757 17.928 ;
     RECT  60.329 45.168 60.829 47.832 ;
     RECT  60.689 31.776 60.833 31.992 ;
     RECT  60.757 17.904 60.937 18.12 ;
     RECT  60.86 54.096 61.045 54.12 ;
     RECT  60.901 57.072 61.045 57.096 ;
     RECT  60.469 0.048 61.049 16.776 ;
     RECT  60.937 17.904 61.093 19.32 ;
     RECT  61.045 54.096 61.148 54.696 ;
     RECT  61.045 57.024 61.153 57.096 ;
     RECT  60.649 42.288 61.189 42.312 ;
     RECT  61.148 54.096 61.189 55.56 ;
     RECT  61.153 57.024 61.189 57.576 ;
     RECT  61.189 54.096 61.225 57.576 ;
     RECT  60.185 21.12 61.261 22.632 ;
     RECT  61.196 60.384 61.283 60.408 ;
     RECT  61.049 0.096 61.297 16.776 ;
     RECT  61.093 17.904 61.297 20.136 ;
     RECT  61.285 60.288 61.372 60.312 ;
     RECT  60.473 24.432 61.405 24.456 ;
     RECT  60.689 26.016 61.405 30.36 ;
     RECT  61.405 24.432 61.441 30.36 ;
     RECT  61.429 59.904 61.513 60.072 ;
     RECT  61.441 23.952 61.669 30.36 ;
     RECT  60.725 33.312 61.669 41.064 ;
     RECT  61.189 42.288 61.669 42.456 ;
     RECT  61.261 21.12 61.693 22.776 ;
     RECT  61.669 23.952 61.693 30.936 ;
     RECT  60.829 44.448 61.765 47.832 ;
     RECT  61.297 0.096 61.808 20.136 ;
     RECT  61.693 21.12 61.808 30.936 ;
     RECT  60.833 31.968 61.808 31.992 ;
     RECT  61.669 33.312 61.808 42.456 ;
     RECT  61.765 44.448 61.808 47.88 ;
     RECT  60.617 49.872 61.808 50.04 ;
     RECT  61.669 51.36 61.808 51.384 ;
     RECT  61.225 54.096 61.808 58.152 ;
     RECT  61.513 59.856 62.057 60.072 ;
     RECT  61.808 0.096 62.101 58.152 ;
     RECT  62.101 0.096 62.104 58.2 ;
     RECT  62.104 57.168 62.188 58.2 ;
     RECT  62.104 54.672 62.243 55.272 ;
     RECT  62.104 0.096 62.273 13.368 ;
     RECT  62.104 25.632 62.435 26.04 ;
     RECT  62.104 14.928 62.453 15.864 ;
     RECT  62.104 32.976 62.633 50.712 ;
     RECT  62.057 59.856 62.665 59.928 ;
     RECT  62.453 15.024 62.669 15.864 ;
     RECT  62.188 57.168 62.716 58.008 ;
     RECT  62.669 15.024 62.741 15.48 ;
     RECT  62.665 59.808 62.777 59.928 ;
     RECT  62.104 53.664 62.785 53.688 ;
     RECT  62.104 17.04 62.819 23.736 ;
     RECT  62.104 27.168 63.029 31.992 ;
     RECT  63.061 60.336 63.197 60.36 ;
     RECT  62.633 49.008 63.281 50.712 ;
     RECT  63.197 60.336 63.281 60.408 ;
     RECT  62.243 55.248 63.292 55.272 ;
     RECT  62.819 17.616 63.317 23.736 ;
     RECT  62.633 32.976 63.425 48.024 ;
     RECT  63.425 32.976 63.461 40.056 ;
     RECT  62.273 12.24 63.529 13.368 ;
     RECT  62.435 25.632 63.529 25.656 ;
     RECT  63.529 25.056 63.745 25.656 ;
     RECT  63.029 27.168 63.745 27.192 ;
     RECT  63.281 60.336 63.745 60.36 ;
     RECT  63.529 12.24 63.829 13.896 ;
     RECT  62.741 15.168 63.829 15.48 ;
     RECT  63.425 44.016 63.925 48.024 ;
     RECT  63.281 49.008 63.925 50.136 ;
     RECT  62.716 57.6 63.961 58.008 ;
     RECT  63.029 28.8 64.021 31.992 ;
     RECT  63.461 32.976 64.021 33.336 ;
     RECT  62.273 0.096 64.073 11.016 ;
     RECT  63.317 17.616 64.249 18.552 ;
     RECT  63.745 59.856 64.357 60.36 ;
     RECT  63.961 56.976 64.405 58.008 ;
     RECT  63.925 44.016 64.429 50.136 ;
     RECT  64.073 0.816 64.508 11.016 ;
     RECT  63.829 12.24 64.508 15.48 ;
     RECT  64.249 17.472 64.508 18.552 ;
     RECT  63.317 20.112 64.508 23.736 ;
     RECT  63.745 25.056 64.508 27.192 ;
     RECT  64.021 28.8 64.508 33.336 ;
     RECT  63.461 34.368 64.508 40.056 ;
     RECT  63.425 41.04 64.508 42.792 ;
     RECT  64.429 44.016 64.508 50.952 ;
     RECT  64.405 56.976 64.508 58.152 ;
     RECT  64.357 59.856 64.577 60.408 ;
     RECT  64.508 0.816 64.804 58.152 ;
     RECT  64.804 55.008 64.825 58.152 ;
     RECT  64.804 0.816 64.865 10.824 ;
     RECT  64.825 55.008 64.909 58.2 ;
     RECT  64.577 59.904 64.931 60.408 ;
     RECT  64.804 38.736 64.937 40.056 ;
     RECT  64.804 14.112 64.973 15.48 ;
     RECT  64.865 2.496 65.009 10.824 ;
     RECT  64.804 36.048 65.081 37.704 ;
     RECT  64.804 20.112 65.117 23.688 ;
     RECT  64.804 45.36 65.117 48.696 ;
     RECT  65.081 36.048 65.123 36.696 ;
     RECT  64.937 38.784 65.123 40.056 ;
     RECT  65.009 10.128 65.189 10.824 ;
     RECT  64.973 14.112 65.225 15.432 ;
     RECT  65.117 21.504 65.225 23.688 ;
     RECT  65.117 45.552 65.225 48.696 ;
     RECT  65.189 10.128 65.261 10.392 ;
     RECT  64.804 41.424 65.267 44.376 ;
     RECT  64.804 17.472 65.297 17.736 ;
     RECT  65.225 45.552 65.315 48.504 ;
     RECT  65.009 2.496 65.369 8.52 ;
     RECT  64.804 29.088 65.405 30.936 ;
     RECT  65.123 40.032 65.405 40.056 ;
     RECT  65.261 10.128 65.513 10.152 ;
     RECT  65.405 29.136 65.621 30.936 ;
     RECT  64.865 0.816 65.729 1.416 ;
     RECT  64.804 31.92 65.765 34.92 ;
     RECT  65.267 44.064 65.765 44.376 ;
     RECT  64.804 50.112 65.797 50.952 ;
     RECT  64.804 27.072 65.833 28.104 ;
     RECT  65.765 31.968 65.837 34.92 ;
     RECT  65.797 50.112 65.845 51.336 ;
     RECT  64.804 25.056 65.869 25.08 ;
     RECT  64.909 55.008 65.9 58.152 ;
     RECT  65.297 17.472 65.945 17.64 ;
     RECT  65.765 44.064 65.945 44.088 ;
     RECT  65.845 50.688 65.945 51.336 ;
     RECT  65.869 25.056 65.989 25.272 ;
     RECT  65.989 25.056 66.049 25.752 ;
     RECT  65.833 26.736 66.049 28.104 ;
     RECT  65.117 20.112 66.085 20.136 ;
     RECT  65.225 21.504 66.085 21.528 ;
     RECT  65.081 37.68 66.085 37.704 ;
     RECT  65.123 38.784 66.085 38.808 ;
     RECT  65.267 41.424 66.085 42.792 ;
     RECT  66.085 41.136 66.14 42.792 ;
     RECT  65.9 54.672 66.14 58.152 ;
     RECT  65.123 36.048 66.161 36.648 ;
     RECT  65.315 48.384 66.205 48.504 ;
     RECT  66.14 54.48 66.227 58.152 ;
     RECT  65.729 0.816 66.229 0.84 ;
     RECT  66.013 16.848 66.229 16.872 ;
     RECT  66.14 41.088 66.265 42.792 ;
     RECT  64.931 60.096 66.373 60.408 ;
     RECT  64.804 11.952 66.421 13.08 ;
     RECT  65.225 14.496 66.421 15.432 ;
     RECT  65.621 29.28 66.481 30.936 ;
     RECT  65.315 45.552 66.517 47.016 ;
     RECT  66.229 0.048 66.521 0.84 ;
     RECT  66.373 59.856 66.521 60.408 ;
     RECT  66.085 20.112 66.524 21.528 ;
     RECT  65.369 2.496 66.553 6.36 ;
     RECT  65.369 7.728 66.553 8.52 ;
     RECT  66.421 11.952 66.553 15.432 ;
     RECT  66.524 19.632 66.565 21.528 ;
     RECT  66.085 37.68 66.572 39.96 ;
     RECT  66.265 40.944 66.572 42.792 ;
     RECT  66.049 25.056 66.589 28.104 ;
     RECT  66.481 29.28 66.589 30.984 ;
     RECT  66.589 25.056 66.625 30.984 ;
     RECT  66.517 45.552 66.757 47.976 ;
     RECT  66.161 36.288 66.805 36.648 ;
     RECT  66.572 37.68 66.805 42.792 ;
     RECT  66.521 0.816 66.881 0.84 ;
     RECT  65.225 22.752 66.949 23.688 ;
     RECT  66.625 24.768 66.949 30.984 ;
     RECT  66.553 2.496 67.045 8.52 ;
     RECT  65.837 31.968 67.129 34.824 ;
     RECT  67.129 31.968 67.165 34.92 ;
     RECT  67.045 2.496 67.208 8.856 ;
     RECT  66.553 11.136 67.208 15.432 ;
     RECT  66.229 16.512 67.208 16.872 ;
     RECT  66.949 18.24 67.208 18.264 ;
     RECT  66.565 19.248 67.208 21.528 ;
     RECT  66.949 22.752 67.208 30.984 ;
     RECT  67.165 31.968 67.208 35.016 ;
     RECT  66.805 36.288 67.208 42.792 ;
     RECT  66.757 45.216 67.208 47.976 ;
     RECT  66.265 49.008 67.208 49.128 ;
     RECT  65.945 50.688 67.208 50.76 ;
     RECT  66.227 55.248 67.208 58.152 ;
     RECT  67.208 2.148 67.285 58.152 ;
     RECT  67.285 2.148 67.372 58.2 ;
     RECT  67.372 2.148 67.504 58.062 ;
     RECT  67.504 2.148 67.601 12.6 ;
     RECT  67.504 50.784 67.619 53.304 ;
     RECT  67.601 2.148 67.669 12.552 ;
     RECT  67.504 29.04 67.709 30.984 ;
     RECT  67.504 21.216 67.781 27.912 ;
     RECT  67.669 1.728 67.85 12.552 ;
     RECT  66.521 59.904 67.877 60.408 ;
     RECT  67.561 0.048 67.921 0.6 ;
     RECT  67.85 1.728 67.921 8.952 ;
     RECT  67.504 31.968 67.925 40.152 ;
     RECT  67.504 44.352 67.925 49.608 ;
     RECT  67.781 21.216 67.997 22.824 ;
     RECT  67.504 18.24 68.033 18.264 ;
     RECT  67.85 9.936 68.147 12.552 ;
     RECT  67.925 44.352 68.185 49.08 ;
     RECT  67.997 21.216 68.213 22.488 ;
     RECT  67.504 19.248 68.249 20.184 ;
     RECT  67.709 29.088 68.285 30.984 ;
     RECT  67.921 0.048 68.291 8.952 ;
     RECT  68.291 0.048 68.393 1.272 ;
     RECT  67.504 13.632 68.393 16.872 ;
     RECT  68.185 48 68.393 49.08 ;
     RECT  67.781 23.904 68.429 27.912 ;
     RECT  68.393 13.632 68.465 14.808 ;
     RECT  68.393 16.368 68.465 16.872 ;
     RECT  67.504 54.48 68.492 58.008 ;
     RECT  67.619 50.784 68.569 50.856 ;
     RECT  67.925 31.968 68.627 39.384 ;
     RECT  68.465 14.784 68.645 14.808 ;
     RECT  68.185 44.352 68.645 46.824 ;
     RECT  68.147 10.176 68.681 12.552 ;
     RECT  68.645 44.496 68.681 46.824 ;
     RECT  68.393 0.048 68.723 1.176 ;
     RECT  68.429 25.488 68.797 27.912 ;
     RECT  68.492 54.096 68.869 58.008 ;
     RECT  68.723 1.152 68.897 1.176 ;
     RECT  68.723 0.048 68.915 0.072 ;
     RECT  68.291 2.352 68.933 8.952 ;
     RECT  67.504 42.144 68.965 43.368 ;
     RECT  68.869 54.096 68.965 58.152 ;
     RECT  68.569 50.736 69.001 50.856 ;
     RECT  67.619 52.416 69.001 52.44 ;
     RECT  68.249 19.68 69.013 20.184 ;
     RECT  68.213 21.216 69.013 21.576 ;
     RECT  68.627 34.704 69.068 39.384 ;
     RECT  68.393 48.672 69.073 49.08 ;
     RECT  69.068 34.704 69.109 40.104 ;
     RECT  69.001 50.736 69.109 52.44 ;
     RECT  68.929 17.472 69.145 17.496 ;
     RECT  69.109 34.704 69.145 40.632 ;
     RECT  68.965 42 69.145 43.368 ;
     RECT  67.877 59.856 69.155 60.408 ;
     RECT  69.073 48.672 69.205 49.752 ;
     RECT  69.109 50.736 69.205 52.776 ;
     RECT  68.429 23.904 69.253 24.456 ;
     RECT  69.145 17.472 69.289 18.216 ;
     RECT  69.013 19.68 69.289 21.576 ;
     RECT  68.965 53.952 69.289 58.2 ;
     RECT  69.145 34.704 69.349 43.368 ;
     RECT  68.933 7.968 69.541 8.952 ;
     RECT  69.205 48.672 69.577 52.776 ;
     RECT  69.253 23.376 69.613 24.456 ;
     RECT  69.289 53.952 69.685 58.248 ;
     RECT  68.465 13.632 69.733 13.656 ;
     RECT  68.465 16.368 69.733 16.392 ;
     RECT  69.289 17.472 69.733 21.576 ;
     RECT  68.627 31.968 69.733 33.576 ;
     RECT  69.685 53.952 69.733 58.44 ;
     RECT  69.155 59.856 69.733 60.312 ;
     RECT  69.733 31.968 69.781 33.672 ;
     RECT  69.349 34.704 69.781 43.416 ;
     RECT  68.681 44.928 69.781 46.824 ;
     RECT  69.733 53.952 69.781 58.536 ;
     RECT  68.285 29.088 69.793 30.792 ;
     RECT  68.933 2.352 69.908 6.792 ;
     RECT  69.541 7.968 69.908 9.096 ;
     RECT  68.681 10.176 69.908 12.504 ;
     RECT  69.733 13.632 69.908 14.232 ;
     RECT  69.733 16.368 69.908 21.576 ;
     RECT  69.613 23.04 69.908 24.456 ;
     RECT  68.797 25.488 69.908 25.512 ;
     RECT  68.797 26.64 69.908 27.912 ;
     RECT  69.793 29.04 69.908 30.792 ;
     RECT  69.781 31.968 69.908 46.824 ;
     RECT  69.577 48.384 69.908 52.776 ;
     RECT  69.781 53.904 69.908 58.536 ;
     RECT  69.733 59.808 70.049 60.312 ;
     RECT  69.908 2.148 70.204 58.536 ;
     RECT  70.204 31.68 70.337 34.776 ;
     RECT  70.204 14.208 70.381 16.872 ;
     RECT  70.204 19.92 70.409 30.36 ;
     RECT  70.049 59.856 70.451 60.312 ;
     RECT  70.204 50.112 70.492 58.536 ;
     RECT  70.337 32.016 70.517 34.776 ;
     RECT  70.492 50.16 70.585 58.536 ;
     RECT  70.204 39.744 70.589 40.68 ;
     RECT  70.409 19.92 70.595 22.728 ;
     RECT  70.204 2.148 70.597 8.52 ;
     RECT  70.585 50.16 70.669 58.68 ;
     RECT  70.597 1.968 70.693 8.52 ;
     RECT  70.693 1.728 70.697 8.52 ;
     RECT  70.697 1.728 70.733 3.672 ;
     RECT  70.697 4.656 70.733 8.52 ;
     RECT  70.204 10.368 70.733 12.648 ;
     RECT  70.669 50.16 70.733 58.248 ;
     RECT  70.733 54.096 70.739 58.248 ;
     RECT  70.409 23.904 70.787 30.36 ;
     RECT  70.381 14.208 70.805 14.232 ;
     RECT  70.787 23.904 70.805 27.096 ;
     RECT  70.739 54.144 70.805 58.248 ;
     RECT  70.787 28.512 70.841 30.36 ;
     RECT  70.451 59.904 70.883 60.312 ;
     RECT  70.733 1.728 70.981 2.904 ;
     RECT  70.805 25.056 71.021 27.096 ;
     RECT  70.789 0.096 71.077 0.12 ;
     RECT  70.981 1.392 71.077 2.904 ;
     RECT  70.733 50.16 71.129 52.968 ;
     RECT  70.204 35.808 71.173 36.36 ;
     RECT  70.204 37.344 71.173 37.512 ;
     RECT  70.204 45.312 71.197 46.824 ;
     RECT  70.381 15.6 71.233 16.872 ;
     RECT  70.204 17.856 71.233 18.216 ;
     RECT  70.204 44.064 71.233 44.088 ;
     RECT  71.197 45.312 71.233 46.872 ;
     RECT  70.805 54.144 71.267 58.2 ;
     RECT  70.517 32.208 71.305 34.776 ;
     RECT  71.173 35.808 71.305 37.512 ;
     RECT  70.204 38.736 71.305 38.76 ;
     RECT  70.204 42 71.305 42.552 ;
     RECT  70.733 10.512 71.345 12.648 ;
     RECT  71.345 10.512 71.381 12.024 ;
     RECT  70.841 28.608 71.381 30.36 ;
     RECT  70.595 20.064 71.413 22.728 ;
     RECT  70.805 23.904 71.413 23.928 ;
     RECT  70.204 48.432 71.413 49.08 ;
     RECT  71.413 47.856 71.5 49.08 ;
     RECT  71.129 50.16 71.509 52.488 ;
     RECT  71.5 47.904 71.564 49.08 ;
     RECT  71.509 50.064 71.564 52.488 ;
     RECT  71.305 32.208 71.593 38.76 ;
     RECT  71.305 42 71.593 42.648 ;
     RECT  71.233 15.6 71.665 18.216 ;
     RECT  71.593 32.208 71.701 38.856 ;
     RECT  70.883 60.288 71.747 60.312 ;
     RECT  71.665 14.88 71.773 18.216 ;
     RECT  71.381 29.28 71.773 30.36 ;
     RECT  71.701 31.872 71.773 38.856 ;
     RECT  71.267 54.672 71.795 58.2 ;
     RECT  71.413 20.064 71.804 23.928 ;
     RECT  71.795 54.672 71.813 58.152 ;
     RECT  71.077 0.096 71.845 2.904 ;
     RECT  70.733 4.992 71.845 8.52 ;
     RECT  71.593 42 71.845 42.792 ;
     RECT  71.233 44.064 71.845 46.872 ;
     RECT  71.021 25.728 71.948 27.096 ;
     RECT  71.845 0.096 72.092 3.144 ;
     RECT  71.845 4.512 72.092 8.52 ;
     RECT  71.845 60.336 72.275 60.36 ;
     RECT  71.564 47.904 72.341 52.488 ;
     RECT  71.773 14.784 72.349 18.216 ;
     RECT  70.589 40.032 72.38 40.68 ;
     RECT  71.845 42 72.38 46.872 ;
     RECT  72.349 14.784 72.457 18.792 ;
     RECT  71.804 20.064 72.457 24.312 ;
     RECT  72.236 9.504 72.469 9.528 ;
     RECT  72.092 0.096 72.608 8.52 ;
     RECT  72.469 9.504 72.608 9.624 ;
     RECT  71.381 10.704 72.608 12.024 ;
     RECT  72.457 14.784 72.608 24.312 ;
     RECT  71.948 25.728 72.608 27.816 ;
     RECT  71.773 29.28 72.608 38.856 ;
     RECT  72.38 40.032 72.608 46.872 ;
     RECT  72.341 47.904 72.608 52.92 ;
     RECT  71.813 54.672 72.608 58.008 ;
     RECT  72.608 0.096 72.8 58.008 ;
     RECT  72.8 0.096 72.904 58.062 ;
     RECT  72.904 51.936 72.965 52.056 ;
     RECT  72.904 28.464 73.043 39.48 ;
     RECT  72.904 45.552 73.073 46.344 ;
     RECT  72.904 47.904 73.073 50.952 ;
     RECT  72.904 21.072 73.217 22.104 ;
     RECT  72.904 44.064 73.217 44.424 ;
     RECT  72.904 10.944 73.253 12.552 ;
     RECT  72.965 51.984 73.289 52.056 ;
     RECT  72.904 3.84 73.325 9.624 ;
     RECT  72.904 23.088 73.325 24.744 ;
     RECT  72.904 41.472 73.361 42.792 ;
     RECT  73.217 44.064 73.612 44.376 ;
     RECT  73.073 47.904 73.619 49.656 ;
     RECT  72.904 15.168 73.649 20.088 ;
     RECT  73.325 23.28 73.901 24.744 ;
     RECT  73.649 15.456 73.933 20.088 ;
     RECT  73.217 21.072 73.933 22.056 ;
     RECT  73.253 11.376 73.937 12.552 ;
     RECT  73.619 47.904 73.973 48.504 ;
     RECT  73.289 51.984 73.973 52.008 ;
     RECT  72.904 0.096 74.041 2.808 ;
     RECT  73.325 3.84 74.041 9.096 ;
     RECT  73.933 15.456 74.117 22.056 ;
     RECT  74.041 47.328 74.125 47.352 ;
     RECT  72.904 26.064 74.149 27.096 ;
     RECT  74.117 18.144 74.189 22.056 ;
     RECT  73.619 49.584 74.221 49.656 ;
     RECT  74.041 0.096 74.261 9.096 ;
     RECT  73.043 28.464 74.285 33.624 ;
     RECT  73.043 34.704 74.285 39.48 ;
     RECT  73.937 11.376 74.293 11.4 ;
     RECT  73.901 24.672 74.329 24.744 ;
     RECT  74.149 26.064 74.329 27.384 ;
     RECT  73.361 41.472 74.329 42.552 ;
     RECT  74.293 10.992 74.333 11.4 ;
     RECT  74.221 49.584 74.545 49.8 ;
     RECT  73.073 50.832 74.545 50.952 ;
     RECT  73.612 44.064 74.653 44.088 ;
     RECT  73.073 45.552 74.653 45.576 ;
     RECT  74.285 28.464 74.677 39.48 ;
     RECT  74.329 41.04 74.917 42.552 ;
     RECT  74.653 44.064 74.917 45.576 ;
     RECT  74.677 28.416 75.013 39.48 ;
     RECT  73.973 48.432 75.013 48.504 ;
     RECT  75.013 56.784 75.061 56.808 ;
     RECT  74.545 49.584 75.085 50.952 ;
     RECT  75.061 56.784 75.109 57.48 ;
     RECT  74.917 41.04 75.121 45.576 ;
     RECT  74.653 13.104 75.157 13.128 ;
     RECT  73.901 23.28 75.157 23.304 ;
     RECT  74.329 24.672 75.157 27.384 ;
     RECT  75.085 49.536 75.157 50.952 ;
     RECT  75.061 60.288 75.301 60.312 ;
     RECT  74.261 0.096 75.308 8.568 ;
     RECT  74.333 10.992 75.308 11.016 ;
     RECT  75.157 12.24 75.308 13.128 ;
     RECT  74.117 15.456 75.308 16.968 ;
     RECT  74.189 18.144 75.308 20.184 ;
     RECT  74.189 21.168 75.308 22.056 ;
     RECT  75.157 23.28 75.308 27.384 ;
     RECT  75.013 28.416 75.308 40.056 ;
     RECT  75.121 41.04 75.308 46.344 ;
     RECT  75.013 47.904 75.308 48.504 ;
     RECT  75.157 49.536 75.308 51.24 ;
     RECT  75.109 56.784 75.308 58.152 ;
     RECT  75.301 60.096 75.397 60.312 ;
     RECT  75.308 0.096 75.404 58.152 ;
     RECT  75.397 60 75.493 60.312 ;
     RECT  75.404 0.096 75.541 58.2 ;
     RECT  75.541 0.096 75.604 58.296 ;
     RECT  75.604 14.208 75.629 17.064 ;
     RECT  75.604 50.832 75.629 51.912 ;
     RECT  75.604 29.28 75.731 42.216 ;
     RECT  75.493 59.856 75.731 60.312 ;
     RECT  75.604 54.48 75.773 58.296 ;
     RECT  75.604 18.72 75.779 22.2 ;
     RECT  75.731 34.032 75.781 38.568 ;
     RECT  75.731 29.28 75.817 33.048 ;
     RECT  75.773 54.48 75.853 58.2 ;
     RECT  75.731 39.888 75.881 42.216 ;
     RECT  75.604 47.904 75.881 48.504 ;
     RECT  75.781 36.528 75.989 38.568 ;
     RECT  75.881 47.904 75.989 47.928 ;
     RECT  75.604 11.328 76.019 13.128 ;
     RECT  75.629 15.552 76.061 17.064 ;
     RECT  76.061 16.224 76.067 17.064 ;
     RECT  75.629 50.976 76.067 51.912 ;
     RECT  76.067 16.512 76.097 17.064 ;
     RECT  75.629 14.208 76.105 14.52 ;
     RECT  76.019 11.328 76.169 12.6 ;
     RECT  75.881 41.04 76.177 42.216 ;
     RECT  75.853 54.48 76.211 55.56 ;
     RECT  75.731 59.904 76.211 60.312 ;
     RECT  76.211 60 76.259 60.312 ;
     RECT  75.817 31.392 76.277 33.048 ;
     RECT  75.604 44.736 76.307 46.776 ;
     RECT  76.259 60.24 76.357 60.312 ;
     RECT  76.307 44.976 76.421 46.776 ;
     RECT  75.779 20.88 76.499 22.2 ;
     RECT  76.177 41.04 76.499 42.024 ;
     RECT  76.067 51.888 76.529 51.912 ;
     RECT  76.357 60.24 76.55 60.36 ;
     RECT  76.105 14.304 76.565 14.52 ;
     RECT  76.211 54.48 76.595 55.272 ;
     RECT  75.604 23.904 76.601 26.616 ;
     RECT  76.601 23.904 76.633 24.696 ;
     RECT  76.499 41.376 76.637 42.024 ;
     RECT  75.604 0.096 76.643 9 ;
     RECT  76.601 26.064 76.669 26.616 ;
     RECT  76.499 21.168 76.693 22.2 ;
     RECT  76.633 23.376 76.693 24.696 ;
     RECT  76.643 0.096 76.709 7.896 ;
     RECT  76.693 21.168 76.739 24.696 ;
     RECT  76.55 60.288 76.739 60.312 ;
     RECT  76.421 44.976 76.745 46.2 ;
     RECT  76.739 22.464 76.78 24.696 ;
     RECT  76.643 8.976 76.817 9 ;
     RECT  76.637 41.376 76.817 41.784 ;
     RECT  75.853 57.024 76.837 58.2 ;
     RECT  75.881 39.888 76.853 39.912 ;
     RECT  75.604 43.296 76.853 43.32 ;
     RECT  75.781 34.032 76.921 35.304 ;
     RECT  75.989 36.528 76.921 38.52 ;
     RECT  76.837 57.024 76.933 58.296 ;
     RECT  75.817 29.28 76.957 30.216 ;
     RECT  76.277 31.776 76.997 33.048 ;
     RECT  76.709 0.096 77.027 6.84 ;
     RECT  76.745 45.024 77.041 46.2 ;
     RECT  76.633 17.712 77.209 17.736 ;
     RECT  75.779 18.72 77.209 19.224 ;
     RECT  76.705 49.008 77.209 49.032 ;
     RECT  76.169 11.952 77.245 12.6 ;
     RECT  77.027 0.096 77.357 6.072 ;
     RECT  76.669 26.064 77.461 26.76 ;
     RECT  76.957 28.992 77.468 30.216 ;
     RECT  76.921 34.032 77.533 38.52 ;
     RECT  76.997 31.968 77.564 33.048 ;
     RECT  77.533 34.032 77.564 39.096 ;
     RECT  76.739 21.168 77.569 21.192 ;
     RECT  77.209 48.48 77.677 49.032 ;
     RECT  76.78 22.8 77.749 24.696 ;
     RECT  77.357 2.064 77.825 6.072 ;
     RECT  77.041 45.744 77.893 46.2 ;
     RECT  76.595 54.672 77.893 55.272 ;
     RECT  76.933 57.024 77.897 58.68 ;
     RECT  77.677 48.48 77.929 49.896 ;
     RECT  76.097 16.512 77.965 16.584 ;
     RECT  77.209 17.712 77.965 19.224 ;
     RECT  77.897 57.024 77.969 58.632 ;
     RECT  77.969 57.024 78.005 58.536 ;
     RECT  77.825 2.148 78.008 6.072 ;
     RECT  76.709 7.872 78.008 7.896 ;
     RECT  77.893 10.464 78.008 10.488 ;
     RECT  77.245 11.952 78.008 12.792 ;
     RECT  77.965 16.512 78.008 19.224 ;
     RECT  77.569 20.976 78.008 21.192 ;
     RECT  77.749 22.8 78.008 24.936 ;
     RECT  77.461 26.064 78.008 27.336 ;
     RECT  77.468 28.944 78.008 30.216 ;
     RECT  77.564 31.968 78.008 39.096 ;
     RECT  77.137 40.08 78.008 40.344 ;
     RECT  76.817 41.376 78.008 41.688 ;
     RECT  77.929 42.768 78.008 42.792 ;
     RECT  77.893 45.744 78.008 47.352 ;
     RECT  77.929 48.48 78.008 50.136 ;
     RECT  77.893 54.672 78.008 55.56 ;
     RECT  78.005 57.024 78.008 58.488 ;
     RECT  78.008 2.148 78.035 58.488 ;
     RECT  78.035 2.148 78.112 58.062 ;
     RECT  78.112 2.418 78.304 58.062 ;
     RECT  78.304 22.752 78.365 26.808 ;
     RECT  77.357 0.096 78.401 0.936 ;
     RECT  78.304 9.072 78.419 11.4 ;
     RECT  78.304 14.64 78.419 14.664 ;
     RECT  78.304 15.648 78.419 18.744 ;
     RECT  78.304 54.672 78.419 54.696 ;
     RECT  78.304 57.024 78.419 57.048 ;
     RECT  78.401 0.096 78.473 0.456 ;
     RECT  78.473 0.096 78.509 0.12 ;
     RECT  78.304 47.664 78.515 50.136 ;
     RECT  78.515 47.808 78.545 50.136 ;
     RECT  78.365 22.752 78.659 24.648 ;
     RECT  78.304 36.432 78.689 41.688 ;
     RECT  78.304 42.768 78.689 42.792 ;
     RECT  78.304 2.64 78.803 2.664 ;
     RECT  78.304 4.416 78.803 5.496 ;
     RECT  78.304 44.448 78.905 45.624 ;
     RECT  78.545 49.584 78.905 50.136 ;
     RECT  78.419 16.56 79.013 18.744 ;
     RECT  78.689 41.04 79.013 41.688 ;
     RECT  79.013 17.184 79.043 18.744 ;
     RECT  78.304 19.776 79.043 21.288 ;
     RECT  78.545 47.808 79.049 48.504 ;
     RECT  78.905 45.6 79.121 45.624 ;
     RECT  78.304 34.704 79.441 35.352 ;
     RECT  78.689 36.432 79.441 39.912 ;
     RECT  79.043 20.544 79.445 21.288 ;
     RECT  79.441 34.704 79.445 39.912 ;
     RECT  78.419 9.648 79.481 11.4 ;
     RECT  78.905 44.448 79.484 44.472 ;
     RECT  79.484 44.016 79.525 44.472 ;
     RECT  79.481 9.648 79.553 9.672 ;
     RECT  79.525 43.296 79.571 44.472 ;
     RECT  79.481 11.232 79.58 11.4 ;
     RECT  78.304 12.528 79.58 12.888 ;
     RECT  78.304 30.816 79.585 30.84 ;
     RECT  79.049 47.808 79.585 47.88 ;
     RECT  78.304 28.464 79.621 29.736 ;
     RECT  79.58 11.232 79.657 12.888 ;
     RECT  79.621 27.936 79.657 29.736 ;
     RECT  79.585 30.816 79.657 30.888 ;
     RECT  79.585 15.696 79.693 15.72 ;
     RECT  79.585 46.896 79.693 47.88 ;
     RECT  78.365 25.776 79.729 26.808 ;
     RECT  78.659 22.752 79.765 23.928 ;
     RECT  79.729 25.68 79.765 26.808 ;
     RECT  79.693 15.312 79.873 15.72 ;
     RECT  78.803 4.704 79.937 5.496 ;
     RECT  78.304 31.968 79.945 33.048 ;
     RECT  79.693 46.752 79.945 47.88 ;
     RECT  79.765 22.752 79.981 26.808 ;
     RECT  79.571 43.296 79.981 43.32 ;
     RECT  79.873 14.976 80.053 15.72 ;
     RECT  79.937 4.512 80.089 5.496 ;
     RECT  80.161 60.384 80.197 60.408 ;
     RECT  80.197 59.904 80.233 60.408 ;
     RECT  78.905 50.112 80.269 50.136 ;
     RECT  80.197 57.024 80.293 57.048 ;
     RECT  79.909 2.496 80.305 2.52 ;
     RECT  80.017 6.96 80.341 7.128 ;
     RECT  79.945 46.128 80.341 47.88 ;
     RECT  80.293 55.536 80.341 55.56 ;
     RECT  80.341 55.536 80.485 55.656 ;
     RECT  80.293 57.024 80.485 57.72 ;
     RECT  80.341 45.552 80.492 47.88 ;
     RECT  80.269 48.96 80.492 48.984 ;
     RECT  79.013 41.664 80.521 41.688 ;
     RECT  80.089 3.552 80.533 5.496 ;
     RECT  80.485 55.536 80.533 57.72 ;
     RECT  80.521 41.664 80.557 41.784 ;
     RECT  79.981 42.768 80.581 43.32 ;
     RECT  79.571 44.448 80.581 44.472 ;
     RECT  80.437 54.48 80.581 54.504 ;
     RECT  80.533 55.536 80.581 57.96 ;
     RECT  79.043 17.184 80.665 18.264 ;
     RECT  80.593 19.536 80.665 19.56 ;
     RECT  80.557 41.472 80.665 41.784 ;
     RECT  80.581 42.768 80.665 44.472 ;
     RECT  80.305 2.352 80.708 2.52 ;
     RECT  80.533 3.552 80.708 5.976 ;
     RECT  80.341 6.96 80.708 7.368 ;
     RECT  79.657 11.232 80.708 12.936 ;
     RECT  80.053 14.112 80.708 15.72 ;
     RECT  80.665 17.184 80.708 19.56 ;
     RECT  79.445 21.168 80.708 21.288 ;
     RECT  79.981 22.752 80.708 26.904 ;
     RECT  79.657 27.936 80.708 30.888 ;
     RECT  79.945 31.968 80.708 33.672 ;
     RECT  79.445 34.704 80.708 39.192 ;
     RECT  80.629 40.32 80.708 40.344 ;
     RECT  80.665 41.472 80.708 44.472 ;
     RECT  80.492 45.552 80.708 48.984 ;
     RECT  80.269 50.112 80.708 50.424 ;
     RECT  80.549 52.032 80.708 52.056 ;
     RECT  80.581 54.096 80.708 54.504 ;
     RECT  80.581 55.536 80.708 58.152 ;
     RECT  80.708 2.148 80.777 58.152 ;
     RECT  80.777 2.148 80.812 58.062 ;
     RECT  80.812 2.304 81.004 58.062 ;
     RECT  81.004 46.896 81.029 49.368 ;
     RECT  81.004 15.648 81.101 19.56 ;
     RECT  81.004 41.136 81.173 43.32 ;
     RECT  81.101 15.648 81.216 17.208 ;
     RECT  81.004 44.448 81.245 45.576 ;
     RECT  81.004 10.992 81.389 11.4 ;
     RECT  81.029 47.28 81.461 49.368 ;
     RECT  81.004 50.4 81.491 50.424 ;
     RECT  80.233 59.856 81.497 60.408 ;
     RECT  81.173 41.136 81.533 42.792 ;
     RECT  81.101 18.192 81.605 19.56 ;
     RECT  81.004 27.888 81.713 38.76 ;
     RECT  81.004 54.672 81.713 58.062 ;
     RECT  81.533 41.136 81.749 41.784 ;
     RECT  81.713 55.728 81.749 58.062 ;
     RECT  81.216 15.648 81.82 16.392 ;
     RECT  81.605 18.192 81.821 19.032 ;
     RECT  81.749 41.664 81.857 41.784 ;
     RECT  81.749 57.024 81.889 58.062 ;
     RECT  81.713 27.888 81.893 30.6 ;
     RECT  81.004 7.344 81.929 8.568 ;
     RECT  81.461 48.864 81.965 49.368 ;
     RECT  81.713 54.672 81.971 54.696 ;
     RECT  81.889 57.024 81.973 58.152 ;
     RECT  81.004 21.168 81.997 22.152 ;
     RECT  81.749 55.872 82.009 55.896 ;
     RECT  81.713 31.968 82.021 38.76 ;
     RECT  81.004 39.888 82.021 40.008 ;
     RECT  82.021 31.968 82.067 40.008 ;
     RECT  82.067 31.968 82.108 39.48 ;
     RECT  82.021 54.48 82.108 54.504 ;
     RECT  81.497 60.384 82.108 60.408 ;
     RECT  81.821 18.192 82.181 18.744 ;
     RECT  81.004 24.912 82.213 26.76 ;
     RECT  81.893 27.888 82.213 30.264 ;
     RECT  81.004 2.304 82.361 5.88 ;
     RECT  82.213 24.912 82.361 30.264 ;
     RECT  81.929 7.92 82.393 8.568 ;
     RECT  82.393 7.92 82.433 9.144 ;
     RECT  81.533 42.768 82.537 42.792 ;
     RECT  81.245 44.448 82.537 45.192 ;
     RECT  82.537 42.768 82.609 45.192 ;
     RECT  82.361 24.912 82.645 30.216 ;
     RECT  81.82 15.984 82.837 16.392 ;
     RECT  82.361 2.544 82.933 5.88 ;
     RECT  82.837 15.216 82.969 16.392 ;
     RECT  82.181 18.192 82.969 18.216 ;
     RECT  81.997 21.168 82.969 22.824 ;
     RECT  82.645 23.952 82.969 30.216 ;
     RECT  82.609 42.768 83.185 45.48 ;
     RECT  82.933 2.544 83.408 6.312 ;
     RECT  82.433 7.92 83.408 7.944 ;
     RECT  82.433 9.12 83.408 9.144 ;
     RECT  81.389 11.376 83.408 11.4 ;
     RECT  82.969 14.4 83.408 16.392 ;
     RECT  82.969 17.904 83.408 18.216 ;
     RECT  82.969 21.168 83.408 30.216 ;
     RECT  82.108 31.968 83.408 33.576 ;
     RECT  82.108 34.704 83.408 39.48 ;
     RECT  81.857 41.664 83.408 41.688 ;
     RECT  83.185 42.768 83.408 45.528 ;
     RECT  81.461 47.28 83.408 47.304 ;
     RECT  81.965 48.864 83.408 48.936 ;
     RECT  83.173 55.248 83.408 55.272 ;
     RECT  81.973 57.024 83.408 57.72 ;
     RECT  83.408 2.148 83.512 57.792 ;
     RECT  83.512 2.418 83.6 57.792 ;
     RECT  83.6 2.418 83.704 58.062 ;
     RECT  83.704 35.76 83.765 39.048 ;
     RECT  83.704 12.336 83.873 12.888 ;
     RECT  83.704 17.088 83.987 19.944 ;
     RECT  83.704 14.4 84.053 14.424 ;
     RECT  83.765 35.808 84.089 39.048 ;
     RECT  83.704 3.408 84.197 4.152 ;
     RECT  83.704 11.28 84.233 11.304 ;
     RECT  83.704 7.92 84.269 9.576 ;
     RECT  83.704 5.184 84.305 6.312 ;
     RECT  83.704 21.168 84.323 23.496 ;
     RECT  84.323 23.088 84.349 23.496 ;
     RECT  83.704 25.728 84.377 29.64 ;
     RECT  84.269 7.92 84.515 9 ;
     RECT  84.349 23.088 84.521 23.112 ;
     RECT  84.515 7.92 84.556 7.944 ;
     RECT  83.704 41.52 84.665 41.784 ;
     RECT  83.704 24.48 84.697 24.504 ;
     RECT  84.377 27.744 84.701 29.64 ;
     RECT  84.665 41.568 84.707 41.784 ;
     RECT  83.704 50.928 84.737 50.952 ;
     RECT  83.704 45.168 84.769 45.624 ;
     RECT  83.704 47.856 84.769 47.88 ;
     RECT  83.704 49.392 84.769 49.416 ;
     RECT  83.987 17.088 84.805 18.216 ;
     RECT  84.089 36.336 84.805 39.048 ;
     RECT  83.704 40.272 84.805 40.296 ;
     RECT  83.704 42.816 84.805 42.84 ;
     RECT  84.769 45.168 84.805 46.2 ;
     RECT  84.323 21.168 84.853 22.056 ;
     RECT  84.805 45.024 84.853 46.2 ;
     RECT  83.704 31.824 84.913 34.776 ;
     RECT  84.769 47.856 84.947 49.416 ;
     RECT  84.697 24.48 84.949 24.744 ;
     RECT  84.377 25.728 84.949 26.712 ;
     RECT  84.805 42.816 84.949 43.32 ;
     RECT  84.805 16.272 84.995 18.216 ;
     RECT  84.947 47.856 85.061 47.88 ;
     RECT  84.805 36.336 85.093 40.296 ;
     RECT  84.997 58.656 85.093 58.68 ;
     RECT  85.093 58.608 85.148 58.68 ;
     RECT  84.913 10.848 85.237 10.872 ;
     RECT  85.093 36 85.237 40.296 ;
     RECT  85.103 30.672 85.273 30.696 ;
     RECT  84.913 31.824 85.273 34.824 ;
     RECT  83.873 12.336 85.477 12.36 ;
     RECT  85.309 14.064 85.477 14.088 ;
     RECT  85.148 58.128 85.477 58.68 ;
     RECT  85.273 30.672 85.525 34.824 ;
     RECT  85.237 35.856 85.525 40.296 ;
     RECT  84.949 42.576 85.813 43.32 ;
     RECT  84.197 3.408 85.849 3.72 ;
     RECT  84.995 18.192 85.868 18.216 ;
     RECT  83.987 19.344 85.868 19.944 ;
     RECT  84.853 21.12 85.868 22.056 ;
     RECT  85.477 12.336 85.921 13.08 ;
     RECT  85.477 14.064 85.921 14.232 ;
     RECT  85.477 57.552 85.921 58.68 ;
     RECT  85.669 15.264 85.993 15.288 ;
     RECT  85.237 10.848 86.029 10.968 ;
     RECT  85.921 12.336 86.029 14.232 ;
     RECT  84.305 5.184 86.065 5.496 ;
     RECT  85.868 18.192 86.101 22.056 ;
     RECT  85.957 23.376 86.101 23.4 ;
     RECT  84.901 2.064 86.108 2.088 ;
     RECT  85.849 3.408 86.108 3.912 ;
     RECT  86.065 5.184 86.108 5.592 ;
     RECT  84.515 8.976 86.108 9 ;
     RECT  86.029 10.848 86.108 14.232 ;
     RECT  85.993 15.216 86.108 15.288 ;
     RECT  84.995 16.272 86.108 17.112 ;
     RECT  86.101 18.192 86.108 23.4 ;
     RECT  84.949 24.48 86.108 26.712 ;
     RECT  84.701 27.888 86.108 29.64 ;
     RECT  85.525 30.672 86.108 40.296 ;
     RECT  85.813 42 86.108 43.32 ;
     RECT  84.853 45.024 86.108 46.104 ;
     RECT  84.947 48.96 86.108 49.416 ;
     RECT  85.957 54.672 86.108 54.696 ;
     RECT  85.921 57.024 86.108 58.68 ;
     RECT  86.108 2.064 86.404 58.68 ;
     RECT  86.425 60.336 86.509 60.36 ;
     RECT  86.404 15.216 86.531 17.4 ;
     RECT  86.404 56.88 86.597 58.68 ;
     RECT  86.404 30.672 86.609 34.872 ;
     RECT  86.609 31.2 86.627 34.872 ;
     RECT  86.404 44.304 86.627 46.776 ;
     RECT  86.404 54.48 86.627 54.696 ;
     RECT  86.531 15.216 86.637 17.112 ;
     RECT  86.404 50.736 86.645 51.288 ;
     RECT  86.597 56.88 86.681 58.728 ;
     RECT  86.627 31.2 86.717 34.728 ;
     RECT  86.404 2.064 86.725 6.552 ;
     RECT  86.605 0.096 86.749 0.12 ;
     RECT  86.404 23.904 86.819 28.2 ;
     RECT  86.725 1.728 87.041 6.552 ;
     RECT  86.404 7.92 87.049 10.584 ;
     RECT  86.404 40.368 87.149 41.16 ;
     RECT  86.404 38.88 87.203 39.048 ;
     RECT  86.819 23.904 87.221 27.336 ;
     RECT  86.404 18.816 87.244 18.84 ;
     RECT  86.404 48.432 87.251 49.32 ;
     RECT  86.749 0.096 87.253 0.552 ;
     RECT  87.041 1.728 87.253 5.832 ;
     RECT  86.404 12.528 87.257 14.232 ;
     RECT  86.404 36.24 87.257 37.656 ;
     RECT  87.203 38.88 87.257 38.904 ;
     RECT  86.404 42.576 87.299 43.32 ;
     RECT  87.049 7.92 87.329 7.944 ;
     RECT  86.637 15.216 87.329 15.816 ;
     RECT  87.257 12.528 87.34 13.992 ;
     RECT  87.049 8.976 87.433 10.584 ;
     RECT  87.253 0.096 87.437 5.832 ;
     RECT  86.681 56.88 87.473 58.68 ;
     RECT  87.433 8.976 87.509 10.824 ;
     RECT  87.509 9.264 87.541 10.824 ;
     RECT  87.221 23.904 87.541 26.664 ;
     RECT  87.299 42.576 87.545 42.744 ;
     RECT  87.257 36.48 87.587 37.656 ;
     RECT  86.627 44.304 87.644 46.584 ;
     RECT  86.404 29.28 87.685 29.64 ;
     RECT  86.717 31.2 87.685 34.584 ;
     RECT  86.404 19.872 87.689 22.104 ;
     RECT  86.637 16.896 87.713 17.112 ;
     RECT  87.644 44.304 87.731 46.968 ;
     RECT  87.473 57.456 87.731 58.68 ;
     RECT  86.627 54.48 87.733 54.504 ;
     RECT  87.731 58.608 87.761 58.68 ;
     RECT  87.689 19.872 87.779 22.008 ;
     RECT  87.541 23.328 87.779 26.664 ;
     RECT  87.649 56.448 87.779 56.472 ;
     RECT  87.685 29.28 87.781 34.584 ;
     RECT  87.731 44.688 87.793 46.968 ;
     RECT  87.713 16.896 87.797 17.64 ;
     RECT  87.781 29.28 87.827 34.632 ;
     RECT  87.397 38.832 87.901 38.856 ;
     RECT  87.827 31.104 87.973 34.632 ;
     RECT  87.793 44.688 87.973 47.208 ;
     RECT  87.973 44.688 88.009 47.352 ;
     RECT  87.251 48.96 88.213 49.32 ;
     RECT  86.645 51.264 88.213 51.288 ;
     RECT  87.761 58.656 88.229 58.68 ;
     RECT  87.541 9.264 88.261 10.92 ;
     RECT  87.437 0.528 88.693 5.832 ;
     RECT  87.827 29.28 88.729 30.072 ;
     RECT  88.693 0.144 88.787 5.832 ;
     RECT  88.787 1.728 88.808 5.832 ;
     RECT  88.369 6.816 88.808 6.84 ;
     RECT  88.405 7.968 88.808 7.992 ;
     RECT  88.261 9.264 88.808 11.448 ;
     RECT  87.34 12.864 88.808 13.992 ;
     RECT  87.329 15.792 88.808 15.816 ;
     RECT  87.797 16.896 88.808 16.92 ;
     RECT  87.779 19.872 88.808 20.328 ;
     RECT  87.779 21.696 88.808 22.008 ;
     RECT  87.779 23.568 88.808 26.664 ;
     RECT  88.729 29.04 88.808 30.072 ;
     RECT  87.973 31.104 88.808 34.824 ;
     RECT  87.587 36.48 88.808 37.368 ;
     RECT  87.901 38.736 88.808 38.856 ;
     RECT  87.149 40.368 88.808 40.392 ;
     RECT  87.545 42.576 88.808 42.648 ;
     RECT  88.009 44.688 88.808 47.88 ;
     RECT  88.213 48.96 88.808 51.288 ;
     RECT  87.733 54.48 88.808 55.032 ;
     RECT  87.731 57.456 88.808 57.48 ;
     RECT  88.787 0.144 88.883 0.648 ;
     RECT  88.808 1.728 89.104 58.062 ;
     RECT  89.104 9.264 89.165 10.92 ;
     RECT  89.104 43.344 89.165 46.632 ;
     RECT  88.883 0.528 89.171 0.648 ;
     RECT  89.165 9.264 89.201 10.104 ;
     RECT  89.104 21.072 89.219 26.952 ;
     RECT  89.171 0.528 89.267 0.552 ;
     RECT  89.219 22.608 89.353 26.952 ;
     RECT  89.104 16.848 89.363 16.92 ;
     RECT  89.104 1.728 89.459 1.848 ;
     RECT  89.353 23.856 89.459 26.952 ;
     RECT  89.104 41.616 89.459 42.168 ;
     RECT  89.104 29.04 89.489 30.072 ;
     RECT  89.104 50.688 89.596 50.712 ;
     RECT  89.104 3.024 89.633 4.008 ;
     RECT  89.104 12.864 89.669 13.656 ;
     RECT  89.165 43.344 89.777 44.472 ;
     RECT  89.104 5.184 89.891 6.12 ;
     RECT  89.104 49.536 89.891 49.608 ;
     RECT  89.459 1.728 89.957 1.8 ;
     RECT  89.459 26.256 90.029 26.952 ;
     RECT  89.777 43.872 90.083 44.472 ;
     RECT  89.104 34.704 90.085 40.2 ;
     RECT  89.104 31.632 90.092 33.288 ;
     RECT  89.219 21.072 90.097 21.096 ;
     RECT  89.104 51.84 90.101 51.864 ;
     RECT  90.092 31.632 90.133 33.384 ;
     RECT  90.085 34.704 90.133 40.632 ;
     RECT  89.459 23.856 90.137 24.792 ;
     RECT  89.353 22.608 90.173 22.632 ;
     RECT  89.633 3.12 90.209 4.008 ;
     RECT  90.133 31.632 90.245 40.632 ;
     RECT  89.165 45.504 90.245 46.632 ;
     RECT  90.029 26.592 90.38 26.952 ;
     RECT  89.891 5.184 90.385 5.496 ;
     RECT  89.363 16.896 90.421 16.92 ;
     RECT  90.38 19.44 90.421 19.464 ;
     RECT  90.097 20.544 90.421 21.096 ;
     RECT  89.489 29.04 90.421 29.64 ;
     RECT  90.245 36.384 90.425 40.632 ;
     RECT  90.421 19.44 90.467 21.096 ;
     RECT  90.137 24.288 90.529 24.792 ;
     RECT  90.425 36.384 90.533 37.464 ;
     RECT  90.245 31.632 90.565 34.824 ;
     RECT  89.669 13.056 90.613 13.656 ;
     RECT  89.104 15.168 90.613 15.816 ;
     RECT  90.421 16.896 90.613 17.112 ;
     RECT  90.421 28.992 90.613 29.64 ;
     RECT  90.565 30.768 90.613 34.824 ;
     RECT  89.891 49.536 90.637 49.56 ;
     RECT  90.349 51.408 90.637 51.432 ;
     RECT  90.469 6.816 90.709 6.84 ;
     RECT  90.709 6.816 90.817 7.416 ;
     RECT  90.637 51.36 90.853 51.432 ;
     RECT  89.201 9.504 90.889 10.104 ;
     RECT  90.313 11.136 90.889 11.16 ;
     RECT  89.957 1.728 90.965 1.752 ;
     RECT  90.709 22.752 91.141 22.776 ;
     RECT  90.529 24.288 91.141 24.984 ;
     RECT  90.613 28.992 91.141 34.824 ;
     RECT  90.245 45.504 91.237 46.296 ;
     RECT  91.237 60.096 91.285 60.12 ;
     RECT  91.141 58.128 91.321 58.152 ;
     RECT  90.613 13.056 91.357 17.112 ;
     RECT  91.285 56.784 91.381 56.808 ;
     RECT  91.285 60.096 91.381 60.216 ;
     RECT  91.141 22.752 91.393 24.984 ;
     RECT  91.321 58.128 91.393 58.2 ;
     RECT  91.381 60.096 91.429 60.264 ;
     RECT  89.459 42.144 91.465 42.168 ;
     RECT  90.209 3.12 91.508 3.864 ;
     RECT  90.385 4.944 91.508 5.496 ;
     RECT  90.817 6.816 91.508 7.512 ;
     RECT  90.709 8.496 91.508 8.52 ;
     RECT  90.889 9.504 91.508 11.16 ;
     RECT  91.357 12.528 91.508 17.112 ;
     RECT  90.467 20.352 91.508 21.096 ;
     RECT  91.393 22.56 91.508 24.984 ;
     RECT  90.38 26.592 91.508 27.336 ;
     RECT  91.141 28.416 91.508 34.824 ;
     RECT  90.533 36.384 91.508 37.368 ;
     RECT  90.425 38.736 91.508 40.632 ;
     RECT  91.465 42.144 91.508 42.744 ;
     RECT  90.083 44.448 91.508 44.472 ;
     RECT  91.237 45.504 91.508 46.728 ;
     RECT  89.104 47.856 91.508 47.88 ;
     RECT  90.637 49.44 91.508 49.56 ;
     RECT  90.853 51.216 91.508 51.432 ;
     RECT  91.381 56.784 91.508 56.904 ;
     RECT  91.393 58.128 91.508 58.296 ;
     RECT  91.508 2.148 91.612 58.296 ;
     RECT  91.612 2.418 91.667 58.296 ;
     RECT  91.667 2.418 91.804 58.248 ;
     RECT  91.429 60.096 91.813 60.36 ;
     RECT  91.804 56.352 91.865 58.248 ;
     RECT  91.804 44.304 91.996 48.456 ;
     RECT  91.813 60.048 92.042 60.36 ;
     RECT  91.804 22.56 92.045 24.648 ;
     RECT  91.804 7.968 92.081 12.552 ;
     RECT  91.804 42.72 92.081 42.888 ;
     RECT  92.045 22.56 92.117 22.824 ;
     RECT  92.042 60.096 92.147 60.36 ;
     RECT  91.804 14.784 92.153 14.808 ;
     RECT  92.147 60.096 92.195 60.12 ;
     RECT  91.804 28.416 92.297 40.632 ;
     RECT  91.996 44.304 92.297 48.408 ;
     RECT  92.045 23.808 92.333 24.648 ;
     RECT  91.865 56.352 92.333 56.424 ;
     RECT  92.333 23.808 92.339 24.312 ;
     RECT  92.297 30.72 92.387 40.632 ;
     RECT  92.081 42.72 92.405 42.744 ;
     RECT  92.297 46.128 92.441 48.408 ;
     RECT  92.441 46.512 92.477 48.408 ;
     RECT  92.339 23.808 92.513 23.832 ;
     RECT  92.081 7.968 92.621 12.408 ;
     RECT  92.387 30.72 92.621 35.64 ;
     RECT  91.804 13.776 92.627 13.8 ;
     RECT  91.804 18.96 92.627 20.376 ;
     RECT  91.865 57.6 92.677 58.248 ;
     RECT  91.804 2.418 92.689 5.544 ;
     RECT  92.621 30.816 92.729 35.64 ;
     RECT  92.729 30.816 92.801 33.144 ;
     RECT  92.477 46.512 92.819 47.352 ;
     RECT  91.804 50.688 92.869 51.864 ;
     RECT  92.333 56.4 92.869 56.424 ;
     RECT  92.677 57.6 92.869 58.296 ;
     RECT  92.819 46.512 92.899 46.68 ;
     RECT  92.297 28.416 92.941 29.64 ;
     RECT  92.801 30.816 92.945 32.808 ;
     RECT  92.387 36.672 92.945 40.632 ;
     RECT  91.804 49.536 92.972 49.56 ;
     RECT  92.869 50.592 92.972 51.864 ;
     RECT  92.689 2.304 93.049 5.544 ;
     RECT  91.804 26.592 93.049 26.664 ;
     RECT  92.941 27.84 93.049 29.64 ;
     RECT  92.945 40.176 93.049 40.632 ;
     RECT  92.972 49.536 93.059 51.864 ;
     RECT  92.869 56.4 93.061 58.296 ;
     RECT  92.477 48.384 93.085 48.408 ;
     RECT  93.049 2.304 93.089 5.736 ;
     RECT  93.049 40.176 93.121 41.4 ;
     RECT  92.117 22.56 93.157 22.776 ;
     RECT  92.621 9.648 93.161 12.408 ;
     RECT  93.121 40.176 93.229 41.64 ;
     RECT  93.061 56.4 93.349 58.68 ;
     RECT  93.157 22.56 93.445 22.824 ;
     RECT  93.049 26.592 93.445 29.64 ;
     RECT  93.229 40.176 93.445 41.784 ;
     RECT  92.297 44.304 93.445 45.048 ;
     RECT  92.899 46.512 93.445 46.632 ;
     RECT  93.445 26.208 93.925 29.64 ;
     RECT  92.945 30.816 93.925 32.76 ;
     RECT  93.925 26.208 93.949 32.76 ;
     RECT  92.621 7.968 94.069 8.52 ;
     RECT  93.161 9.648 94.069 11.784 ;
     RECT  93.949 25.296 94.069 32.76 ;
     RECT  92.945 36.672 94.069 37.608 ;
     RECT  92.945 38.736 94.069 39.048 ;
     RECT  93.445 40.176 94.069 42.168 ;
     RECT  93.059 50.592 94.069 50.616 ;
     RECT  93.085 48.384 94.129 49.08 ;
     RECT  94.069 50.544 94.129 50.616 ;
     RECT  93.349 56.352 94.169 58.68 ;
     RECT  93.089 2.304 94.208 2.328 ;
     RECT  93.089 3.312 94.208 5.736 ;
     RECT  94.069 7.968 94.208 11.784 ;
     RECT  92.627 18.96 94.208 18.984 ;
     RECT  92.627 20.352 94.208 20.376 ;
     RECT  93.445 22.08 94.208 22.824 ;
     RECT  94.069 24.192 94.208 32.76 ;
     RECT  92.729 34.128 94.208 35.64 ;
     RECT  94.069 36.672 94.208 42.168 ;
     RECT  93.229 43.248 94.208 43.272 ;
     RECT  93.445 44.304 94.208 46.632 ;
     RECT  94.129 48.384 94.208 50.616 ;
     RECT  93.059 51.84 94.208 51.864 ;
     RECT  94.169 56.352 94.208 58.062 ;
     RECT  94.208 2.148 94.312 58.062 ;
     RECT  94.312 2.418 94.504 58.062 ;
     RECT  94.504 44.928 94.601 51.288 ;
     RECT  94.504 22.8 94.637 23.592 ;
     RECT  94.504 11.424 94.709 11.784 ;
     RECT  94.601 44.928 94.709 47.928 ;
     RECT  94.601 49.056 94.709 51.288 ;
     RECT  94.709 49.152 94.781 51.288 ;
     RECT  94.504 24.624 94.925 25.32 ;
     RECT  94.504 3.552 95.075 6.36 ;
     RECT  94.504 18.816 95.105 19.368 ;
     RECT  94.504 31.872 95.105 32.856 ;
     RECT  94.709 46.608 95.113 47.928 ;
     RECT  94.504 27.936 95.123 29.64 ;
     RECT  94.709 11.424 95.213 11.448 ;
     RECT  95.105 18.816 95.213 19.032 ;
     RECT  94.781 50.016 95.249 51.288 ;
     RECT  94.504 36.48 95.315 42.456 ;
     RECT  95.315 36.48 95.356 39.432 ;
     RECT  95.315 40.416 95.356 41.256 ;
     RECT  95.075 5.472 95.429 6.36 ;
     RECT  94.504 8.16 95.429 8.184 ;
     RECT  92.833 0.048 95.537 0.072 ;
     RECT  94.925 25.008 95.605 25.32 ;
     RECT  94.504 26.592 95.605 26.664 ;
     RECT  95.605 25.008 95.681 26.664 ;
     RECT  95.123 28.848 95.713 29.64 ;
     RECT  94.637 23.136 95.753 23.592 ;
     RECT  95.356 36.48 95.857 37.656 ;
     RECT  95.857 43.824 95.929 43.848 ;
     RECT  95.681 26.208 96.037 26.664 ;
     RECT  94.504 34.08 96.073 35.352 ;
     RECT  95.857 36.336 96.073 37.656 ;
     RECT  96.073 34.08 96.085 37.656 ;
     RECT  95.753 23.568 96.253 23.592 ;
     RECT  96.181 24.672 96.253 24.696 ;
     RECT  95.249 50.736 96.284 51.288 ;
     RECT  95.075 3.552 96.289 3.576 ;
     RECT  96.037 26.208 96.325 27.624 ;
     RECT  95.713 28.848 96.325 30.456 ;
     RECT  96.037 20.64 96.361 20.664 ;
     RECT  95.356 38.64 96.469 39.432 ;
     RECT  95.356 40.416 96.469 40.632 ;
     RECT  95.105 31.872 96.577 32.52 ;
     RECT  95.113 46.608 96.613 47.16 ;
     RECT  96.577 31.776 96.721 32.52 ;
     RECT  95.929 43.152 96.757 43.848 ;
     RECT  94.709 44.928 96.757 45.48 ;
     RECT  96.325 26.208 96.793 30.456 ;
     RECT  96.721 31.728 96.793 32.52 ;
     RECT  96.361 20.64 96.901 21.192 ;
     RECT  96.289 2.88 96.908 3.576 ;
     RECT  95.429 5.472 96.908 6.024 ;
     RECT  95.213 18.816 96.908 18.84 ;
     RECT  96.901 20.352 96.908 21.192 ;
     RECT  96.253 23.568 96.908 24.696 ;
     RECT  96.793 26.208 96.908 32.52 ;
     RECT  96.085 33.504 96.908 37.656 ;
     RECT  96.469 38.64 96.908 40.632 ;
     RECT  96.757 43.152 96.908 45.48 ;
     RECT  96.613 46.608 96.908 47.688 ;
     RECT  96.284 50.016 96.908 51.288 ;
     RECT  96.908 2.148 97.012 57.792 ;
     RECT  97.012 2.304 97.1 57.792 ;
     RECT  96.865 0.048 97.153 0.072 ;
     RECT  97.1 2.304 97.204 58.062 ;
     RECT  97.204 5.184 97.265 6.024 ;
     RECT  97.265 5.184 97.301 5.496 ;
     RECT  97.204 18.816 97.301 19.368 ;
     RECT  97.204 42.768 97.301 49.608 ;
     RECT  97.204 20.352 97.331 21.288 ;
     RECT  97.301 42.768 97.373 49.512 ;
     RECT  97.331 21.168 97.475 21.288 ;
     RECT  97.204 22.8 97.481 25.08 ;
     RECT  97.204 26.736 97.517 26.76 ;
     RECT  97.204 31.104 97.517 35.736 ;
     RECT  97.481 23.28 97.571 25.08 ;
     RECT  97.204 38.208 97.571 40.824 ;
     RECT  97.301 5.472 97.581 5.496 ;
     RECT  97.571 25.056 97.589 25.08 ;
     RECT  97.475 21.264 97.625 21.288 ;
     RECT  97.517 31.248 97.625 35.736 ;
     RECT  97.625 31.344 97.697 35.736 ;
     RECT  97.373 44.448 97.715 49.512 ;
     RECT  97.571 23.28 97.769 23.4 ;
     RECT  97.697 31.344 98.099 35.544 ;
     RECT  97.204 36.768 98.099 37.032 ;
     RECT  97.571 38.208 98.099 39.528 ;
     RECT  97.715 44.448 98.129 48.936 ;
     RECT  97.769 23.376 98.165 23.4 ;
     RECT  98.129 44.736 98.165 48.936 ;
     RECT  97.301 19.008 98.173 19.368 ;
     RECT  97.204 28.416 98.377 30.12 ;
     RECT  97.373 42.768 98.377 43.176 ;
     RECT  97.204 50.736 98.377 50.76 ;
     RECT  98.165 45.888 98.381 48.936 ;
     RECT  98.377 27.888 98.437 30.12 ;
     RECT  98.437 27.744 98.524 30.12 ;
     RECT  97.204 2.304 98.525 3.96 ;
     RECT  98.099 31.344 98.531 31.896 ;
     RECT  98.531 31.344 98.561 31.752 ;
     RECT  97.571 40.608 98.593 40.824 ;
     RECT  98.377 42.24 98.593 43.176 ;
     RECT  98.525 3.84 98.629 3.96 ;
     RECT  98.629 3.84 98.633 4.296 ;
     RECT  98.524 27.888 98.633 30.12 ;
     RECT  98.593 40.608 98.701 43.176 ;
     RECT  98.413 6.24 98.953 6.264 ;
     RECT  98.701 40.512 99.013 43.176 ;
     RECT  98.099 38.208 99.097 39.24 ;
     RECT  99.013 40.512 99.097 43.56 ;
     RECT  98.377 50.256 99.133 50.76 ;
     RECT  98.099 33.024 99.241 35.544 ;
     RECT  98.099 37.008 99.241 37.032 ;
     RECT  99.241 33.024 99.253 37.032 ;
     RECT  99.253 33.024 99.349 37.08 ;
     RECT  99.097 38.208 99.349 43.56 ;
     RECT  98.381 45.888 99.493 46.392 ;
     RECT  98.381 47.712 99.493 48.936 ;
     RECT  98.561 31.728 99.529 31.752 ;
     RECT  99.349 33.024 99.529 43.56 ;
     RECT  98.525 2.304 99.608 2.856 ;
     RECT  98.633 3.936 99.608 4.296 ;
     RECT  98.953 5.664 99.608 6.264 ;
     RECT  98.173 19.008 99.608 19.032 ;
     RECT  98.633 28.608 99.608 30.12 ;
     RECT  99.529 31.728 99.608 43.56 ;
     RECT  98.165 44.736 99.608 44.76 ;
     RECT  99.493 45.888 99.608 48.936 ;
     RECT  99.133 50.256 99.608 51.384 ;
     RECT  99.608 2.148 99.712 57.792 ;
     RECT  99.712 2.418 99.8 57.792 ;
     RECT  99.8 2.418 99.904 58.062 ;
     RECT  99.904 32.496 99.965 33.048 ;
     RECT  99.904 38.688 99.965 38.808 ;
     RECT  99.904 42.192 99.965 42.312 ;
     RECT  99.904 29.52 100.001 30.12 ;
     RECT  99.904 35.424 100.019 35.448 ;
     RECT  99.965 33.024 100.109 33.048 ;
     RECT  99.904 2.592 100.145 2.808 ;
     RECT  99.904 40.416 100.181 40.44 ;
     RECT  100.145 2.784 100.253 2.808 ;
     RECT  99.904 46.8 100.361 46.824 ;
     RECT  97.153 0.048 100.505 0.12 ;
     RECT  99.904 47.856 100.685 47.88 ;
     RECT  99.904 51.36 100.721 51.384 ;
     RECT  99.965 42.192 100.829 42.216 ;
     RECT  100.505 0.048 101.117 0.072 ;
     RECT  100.001 29.52 102.013 30.024 ;
     RECT  102.013 29.52 102.589 30.216 ;
     RECT  102.589 29.52 102.625 30.312 ;
     RECT  102.625 29.52 104.028 30.408 ;
    LAYER M5 ;
     RECT  48.336 0.016 51.336 0.037 ;
     RECT  29.136 0.016 35.208 0.085 ;
     RECT  48.336 0.037 51.432 0.179 ;
     RECT  70.608 0.016 73.608 0.229 ;
     RECT  70.608 0.229 74.28 0.419 ;
     RECT  70.608 0.419 73.512 0.563 ;
     RECT  68.88 0.037 68.904 0.565 ;
     RECT  29.136 0.085 35.352 0.995 ;
     RECT  33.264 0.995 35.352 1.139 ;
     RECT  25.536 1.141 25.56 1.283 ;
     RECT  68.688 0.565 68.904 1.717 ;
     RECT  33.36 1.139 35.352 1.763 ;
     RECT  33.456 1.763 35.352 1.811 ;
     RECT  70.608 0.563 73.224 1.811 ;
     RECT  33.744 1.811 35.352 1.859 ;
     RECT  29.136 0.995 32.232 1.861 ;
     RECT  33.84 1.859 35.352 1.955 ;
     RECT  34.128 1.955 35.352 2.099 ;
     RECT  23.184 1.909 23.208 2.137 ;
     RECT  48.336 0.179 51.144 2.137 ;
     RECT  58.896 0.181 58.92 2.137 ;
     RECT  59.904 0.229 59.928 2.137 ;
     RECT  68.256 1.717 68.904 2.137 ;
     RECT  70.608 1.811 72.912 2.137 ;
     RECT  86.736 0.016 89.736 2.137 ;
     RECT  2.4 2.137 2.52 2.151 ;
     RECT  5.1 2.137 5.22 2.151 ;
     RECT  7.8 2.137 7.92 2.151 ;
     RECT  10.5 2.137 10.62 2.151 ;
     RECT  13.2 2.137 13.32 2.151 ;
     RECT  15.9 2.137 16.02 2.151 ;
     RECT  18.6 2.137 18.72 2.151 ;
     RECT  21.3 2.137 21.42 2.151 ;
     RECT  23.184 2.137 24.12 2.151 ;
     RECT  26.7 2.137 26.82 2.151 ;
     RECT  28.992 1.861 32.232 2.151 ;
     RECT  37.5 2.137 37.62 2.151 ;
     RECT  40.2 2.137 40.32 2.151 ;
     RECT  42.9 2.137 43.02 2.151 ;
     RECT  45.6 2.137 45.72 2.151 ;
     RECT  48.3 2.137 51.144 2.151 ;
     RECT  53.7 2.137 53.82 2.151 ;
     RECT  56.4 2.137 56.52 2.151 ;
     RECT  61.8 2.137 61.92 2.151 ;
     RECT  64.5 2.137 64.62 2.151 ;
     RECT  75.3 2.137 75.42 2.151 ;
     RECT  78 2.137 78.12 2.151 ;
     RECT  80.7 2.137 80.82 2.151 ;
     RECT  83.4 2.137 83.52 2.151 ;
     RECT  91.5 2.137 91.62 2.151 ;
     RECT  94.2 2.137 94.32 2.151 ;
     RECT  96.9 2.137 97.02 2.151 ;
     RECT  99.6 2.137 99.72 2.151 ;
     RECT  21.3 2.151 21.612 2.245 ;
     RECT  23.184 2.151 24.312 2.245 ;
     RECT  42.9 2.151 43.212 2.245 ;
     RECT  69.9 2.137 72.912 2.291 ;
     RECT  61.8 2.151 62.112 2.293 ;
     RECT  48.3 2.151 51.312 2.339 ;
     RECT  78 2.151 78.312 2.629 ;
     RECT  42.9 2.245 43.656 2.677 ;
     RECT  10.5 2.151 10.812 2.725 ;
     RECT  58.896 2.137 59.928 2.725 ;
     RECT  61.008 2.293 62.112 2.725 ;
     RECT  67.2 2.137 68.904 2.773 ;
     RECT  69.9 2.291 70.212 2.773 ;
     RECT  10.272 2.725 10.812 2.821 ;
     RECT  21.3 2.245 24.312 2.821 ;
     RECT  75.3 2.151 75.612 2.869 ;
     RECT  48.3 2.339 49.128 2.915 ;
     RECT  74.688 2.869 75.612 3.011 ;
     RECT  67.2 2.773 70.212 3.013 ;
     RECT  20.928 2.821 25.032 3.061 ;
     RECT  26.7 2.151 27.012 3.061 ;
     RECT  26.7 3.061 27.816 3.109 ;
     RECT  20.112 3.061 25.032 3.155 ;
     RECT  94.2 2.151 94.512 3.301 ;
     RECT  5.1 2.151 5.412 3.397 ;
     RECT  13.2 2.151 13.512 3.397 ;
     RECT  15.9 2.151 16.212 3.397 ;
     RECT  48.3 2.915 48.936 3.443 ;
     RECT  86.1 2.137 89.736 3.443 ;
     RECT  6.576 2.821 6.6 3.539 ;
     RECT  26.592 3.109 27.816 3.635 ;
     RECT  4.224 3.397 5.412 3.685 ;
     RECT  58.896 2.725 62.112 3.685 ;
     RECT  83.4 2.151 83.712 3.685 ;
     RECT  84.912 2.053 84.936 3.685 ;
     RECT  28.992 2.151 32.412 3.877 ;
     RECT  34.224 2.099 35.352 3.877 ;
     RECT  64.5 2.151 64.812 3.877 ;
     RECT  66.24 3.013 70.212 3.925 ;
     RECT  71.184 2.291 72.912 3.925 ;
     RECT  66.24 3.925 72.912 3.971 ;
     RECT  58.896 3.685 62.664 4.019 ;
     RECT  4.224 3.685 6.168 4.115 ;
     RECT  26.592 3.635 27.012 4.115 ;
     RECT  66.24 3.971 71.496 4.117 ;
     RECT  78 2.629 78.792 4.451 ;
     RECT  10.272 2.821 11.448 4.501 ;
     RECT  37.5 2.151 37.812 4.501 ;
     RECT  59.1 4.019 62.664 4.501 ;
     RECT  80.7 2.151 81.012 4.501 ;
     RECT  93.36 3.301 94.512 4.501 ;
     RECT  50.448 2.339 51.312 4.547 ;
     RECT  59.1 4.501 63.24 4.595 ;
     RECT  21.3 3.155 25.032 4.645 ;
     RECT  48.3 3.443 48.744 4.645 ;
     RECT  66.144 4.117 71.496 4.645 ;
     RECT  28.992 3.877 35.352 4.691 ;
     RECT  37.008 4.501 37.812 4.691 ;
     RECT  18.6 2.151 18.912 4.693 ;
     RECT  64.5 3.877 65.016 4.789 ;
     RECT  10.272 4.501 11.784 4.885 ;
     RECT  15.9 3.397 16.584 4.885 ;
     RECT  17.904 4.693 18.912 4.885 ;
     RECT  21.3 4.645 25.272 4.981 ;
     RECT  7.8 2.151 8.112 5.029 ;
     RECT  32.1 4.691 35.352 5.029 ;
     RECT  66.048 4.645 71.496 5.077 ;
     RECT  72.6 3.971 72.912 5.077 ;
     RECT  79.968 4.501 81.012 5.077 ;
     RECT  74.976 3.011 75.612 5.123 ;
     RECT  20.112 3.155 20.136 5.171 ;
     RECT  7.8 5.029 8.52 5.173 ;
     RECT  26.7 4.115 27.012 5.173 ;
     RECT  32.1 5.029 35.4 5.173 ;
     RECT  32.1 5.173 35.544 5.219 ;
     RECT  60.672 4.595 63.24 5.219 ;
     RECT  45.6 2.151 45.912 5.221 ;
     RECT  15.9 4.885 18.912 5.267 ;
     RECT  26.7 5.173 27.672 5.317 ;
     RECT  10.272 4.885 11.832 5.459 ;
     RECT  64.224 4.789 65.016 5.461 ;
     RECT  66.048 5.077 72.912 5.461 ;
     RECT  96.9 2.151 97.212 5.461 ;
     RECT  17.904 5.267 18.912 5.507 ;
     RECT  82.8 3.685 84.936 5.507 ;
     RECT  93.36 4.501 95.064 5.507 ;
     RECT  32.1 5.219 33.624 5.603 ;
     RECT  60.672 5.219 63.192 5.699 ;
     RECT  75.12 5.123 75.612 5.701 ;
     RECT  10.5 5.459 11.832 5.747 ;
     RECT  34.704 5.219 35.544 5.747 ;
     RECT  50.544 4.547 51.312 5.749 ;
     RECT  37.5 4.691 37.812 5.797 ;
     RECT  26.7 5.317 27.816 5.843 ;
     RECT  28.992 4.691 30.84 5.845 ;
     RECT  32.1 5.603 32.412 5.845 ;
     RECT  50.544 5.749 51.48 5.845 ;
     RECT  79.968 5.077 81.768 5.891 ;
     RECT  33.552 5.603 33.624 6.035 ;
     RECT  48.3 4.645 49.368 6.035 ;
     RECT  53.7 2.151 54.012 6.037 ;
     RECT  56.4 2.151 56.712 6.037 ;
     RECT  75.12 5.701 75.72 6.085 ;
     RECT  86.1 3.443 89.112 6.085 ;
     RECT  5.1 4.115 6.168 6.229 ;
     RECT  56.4 6.037 57.048 6.469 ;
     RECT  36.336 6.085 36.36 6.565 ;
     RECT  50.352 5.845 51.48 6.565 ;
     RECT  7.8 5.173 9.096 6.659 ;
     RECT  74.064 5.653 74.088 6.661 ;
     RECT  75.12 6.085 76.152 6.661 ;
     RECT  36.336 6.565 36.456 6.707 ;
     RECT  74.064 6.661 76.152 6.757 ;
     RECT  15.9 5.267 16.344 6.805 ;
     RECT  37.5 5.797 38.616 6.805 ;
     RECT  55.056 5.461 55.08 6.805 ;
     RECT  56.4 6.469 57.336 6.805 ;
     RECT  74.064 6.757 76.632 6.805 ;
     RECT  86.1 6.085 89.88 6.805 ;
     RECT  50.352 6.565 51.864 6.851 ;
     RECT  18.432 5.507 18.912 6.947 ;
     RECT  15.792 6.805 16.344 7.093 ;
     RECT  18.6 6.947 18.912 7.093 ;
     RECT  40.2 2.151 40.512 7.141 ;
     RECT  59.1 4.595 59.412 7.189 ;
     RECT  60.672 5.699 60.792 7.189 ;
     RECT  28.992 5.845 32.412 7.235 ;
     RECT  12.96 3.397 13.512 7.237 ;
     RECT  31.584 7.235 32.412 7.333 ;
     RECT  33.552 6.035 33.576 7.333 ;
     RECT  59.1 7.189 60.792 7.333 ;
     RECT  61.8 5.699 63.192 7.333 ;
     RECT  64.224 5.461 72.912 7.333 ;
     RECT  10.5 5.747 11.688 7.381 ;
     RECT  12.96 7.237 13.656 7.381 ;
     RECT  34.704 5.747 35.208 7.381 ;
     RECT  36.336 6.707 36.36 7.381 ;
     RECT  52.944 6.037 54.012 7.381 ;
     RECT  55.056 6.805 57.864 7.381 ;
     RECT  59.1 7.333 72.912 7.381 ;
     RECT  74.064 6.805 77.016 7.381 ;
     RECT  14.832 7.093 16.344 7.427 ;
     RECT  34.704 7.381 36.36 7.427 ;
     RECT  21.3 4.981 25.464 7.765 ;
     RECT  26.7 5.843 27.672 7.765 ;
     RECT  10.5 7.381 13.656 7.907 ;
     RECT  5.1 6.229 6.264 7.909 ;
     RECT  7.8 6.659 8.52 7.909 ;
     RECT  45.6 5.221 46.008 7.909 ;
     RECT  47.088 5.989 47.112 7.909 ;
     RECT  39.984 7.141 40.512 8.003 ;
     RECT  52.944 7.381 57.864 8.147 ;
     RECT  94.2 5.507 95.064 8.149 ;
     RECT  15.792 7.427 16.344 8.195 ;
     RECT  52.944 8.147 57.816 8.195 ;
     RECT  79.968 5.891 81.012 8.245 ;
     RECT  31.584 7.333 33.576 8.435 ;
     RECT  18.6 7.093 19.416 8.437 ;
     RECT  52.944 8.195 56.712 8.483 ;
     RECT  59.1 7.381 77.016 8.483 ;
     RECT  18.6 8.437 19.752 8.485 ;
     RECT  91.5 2.151 91.812 8.485 ;
     RECT  92.88 7.957 92.904 8.485 ;
     RECT  11.808 7.907 13.656 8.579 ;
     RECT  34.704 7.427 35.688 8.579 ;
     RECT  60.576 8.483 77.016 8.579 ;
     RECT  55.056 8.483 56.712 8.675 ;
     RECT  60.576 8.579 74.088 8.675 ;
     RECT  18.6 8.485 19.848 8.677 ;
     RECT  21.3 7.765 27.672 8.677 ;
     RECT  10.5 7.907 10.812 8.725 ;
     RECT  5.1 7.909 8.52 8.867 ;
     RECT  40.2 8.003 40.512 8.869 ;
     RECT  37.5 6.805 38.76 8.963 ;
     RECT  28.992 7.235 30.552 8.965 ;
     RECT  15.9 8.195 16.344 9.011 ;
     RECT  42.672 2.677 43.656 9.061 ;
     RECT  78 4.451 78.312 9.061 ;
     RECT  6.864 8.867 8.52 9.107 ;
     RECT  11.808 8.579 11.832 9.107 ;
     RECT  13.2 8.579 13.656 9.109 ;
     RECT  60.576 8.675 72.912 9.155 ;
     RECT  45.6 7.909 47.112 9.299 ;
     RECT  31.584 8.435 32.412 9.395 ;
     RECT  6.864 9.107 8.112 9.491 ;
     RECT  34.704 8.579 35.304 9.539 ;
     RECT  17.52 8.293 17.544 9.541 ;
     RECT  91.5 8.485 92.904 9.637 ;
     RECT  94.08 8.149 95.064 9.637 ;
     RECT  9.648 8.725 10.812 9.731 ;
     RECT  56.4 8.675 56.712 9.925 ;
     RECT  57.792 8.195 57.816 9.925 ;
     RECT  42.144 9.061 43.656 10.069 ;
     RECT  37.5 8.963 38.616 10.117 ;
     RECT  56.4 9.925 57.816 10.165 ;
     RECT  59.1 8.483 59.412 10.165 ;
     RECT  52.944 8.483 54.012 10.213 ;
     RECT  55.056 8.675 55.08 10.213 ;
     RECT  13.2 9.109 14.376 10.307 ;
     RECT  56.4 10.165 59.412 10.307 ;
     RECT  40.2 8.869 40.632 10.309 ;
     RECT  13.2 10.307 13.656 10.355 ;
     RECT  17.52 9.541 17.592 10.405 ;
     RECT  18.6 8.677 27.672 10.405 ;
     RECT  40.2 10.309 40.728 10.451 ;
     RECT  7.8 9.491 8.112 10.453 ;
     RECT  75.3 8.579 77.016 10.453 ;
     RECT  78 9.061 78.408 10.453 ;
     RECT  86.1 6.805 90.504 10.453 ;
     RECT  91.5 9.637 95.064 10.453 ;
     RECT  45.6 9.299 46.056 10.549 ;
     RECT  47.088 9.299 47.112 10.549 ;
     RECT  10.272 9.731 10.812 10.595 ;
     RECT  36.912 10.117 38.616 10.643 ;
     RECT  17.52 10.405 27.672 10.645 ;
     RECT  28.896 8.965 30.552 10.645 ;
     RECT  17.52 10.645 30.552 10.691 ;
     RECT  60.672 9.155 72.912 10.741 ;
     RECT  5.1 8.867 5.832 10.883 ;
     RECT  18.192 10.691 30.552 10.883 ;
     RECT  42 10.069 43.656 10.883 ;
     RECT  45.6 10.549 47.112 10.883 ;
     RECT  56.4 10.307 57.288 11.027 ;
     RECT  86.1 10.453 95.064 11.171 ;
     RECT  45.6 10.883 46.488 11.221 ;
     RECT  60.576 10.741 72.912 11.221 ;
     RECT  40.2 10.451 40.632 11.267 ;
     RECT  79.968 8.245 81.336 11.267 ;
     RECT  75.3 10.453 78.408 11.317 ;
     RECT  79.968 11.267 81.012 11.317 ;
     RECT  21.3 10.883 30.552 11.413 ;
     RECT  91.5 11.171 95.064 11.459 ;
     RECT  37.056 10.643 38.616 11.555 ;
     RECT  18.192 10.883 19.752 11.845 ;
     RECT  21.3 11.413 30.84 11.845 ;
     RECT  13.2 10.355 13.512 11.893 ;
     RECT  34.704 9.539 35.208 11.939 ;
     RECT  37.056 11.555 37.944 11.941 ;
     RECT  58.512 10.307 59.412 11.941 ;
     RECT  60.432 11.221 72.912 11.941 ;
     RECT  40.2 11.267 40.512 11.989 ;
     RECT  50.64 6.851 51.864 12.035 ;
     RECT  44.832 11.221 46.488 12.179 ;
     RECT  44.832 12.179 45.912 12.227 ;
     RECT  58.512 11.941 72.912 12.275 ;
     RECT  18.192 11.845 30.84 12.515 ;
     RECT  33.552 8.435 33.576 12.517 ;
     RECT  14.784 11.941 14.808 12.563 ;
     RECT  18.432 12.515 30.84 12.563 ;
     RECT  75.3 11.317 81.012 12.563 ;
     RECT  12.432 11.893 13.512 12.709 ;
     RECT  9.12 10.213 9.144 12.755 ;
     RECT  36.48 11.941 37.944 12.755 ;
     RECT  21.3 12.563 30.84 12.851 ;
     RECT  39.456 11.989 40.512 12.949 ;
     RECT  7.44 10.453 8.112 12.997 ;
     RECT  12.432 12.709 13.608 13.043 ;
     RECT  10.5 10.595 10.812 13.045 ;
     RECT  50.64 12.035 51.72 13.045 ;
     RECT  52.944 10.213 55.08 13.045 ;
     RECT  82.944 5.507 84.936 13.045 ;
     RECT  86.1 11.171 90.504 13.045 ;
     RECT  91.5 11.459 92.616 13.045 ;
     RECT  32.1 9.395 32.412 13.093 ;
     RECT  18.432 12.563 19.752 13.139 ;
     RECT  26.7 12.851 30.84 13.235 ;
     RECT  31.872 13.093 32.412 13.427 ;
     RECT  59.1 12.275 72.912 13.525 ;
     RECT  50.64 13.045 55.08 13.573 ;
     RECT  10.5 13.045 11.448 13.621 ;
     RECT  10.5 13.621 11.496 13.669 ;
     RECT  7.44 12.997 8.952 13.859 ;
     RECT  82.944 13.045 92.616 14.243 ;
     RECT  49.68 13.573 55.08 14.291 ;
     RECT  7.8 13.859 8.952 14.339 ;
     RECT  34.704 11.939 35.112 14.437 ;
     RECT  13.2 13.043 13.608 14.485 ;
     RECT  33.552 12.517 33.624 14.531 ;
     RECT  39.312 12.949 40.512 14.531 ;
     RECT  36.816 12.755 37.944 14.533 ;
     RECT  36.816 14.533 38.76 14.627 ;
     RECT  75.3 12.563 78.312 14.629 ;
     RECT  10.368 13.669 11.496 14.915 ;
     RECT  5.1 10.883 5.412 14.917 ;
     RECT  13.104 14.485 13.608 15.011 ;
     RECT  5.1 14.917 5.688 15.061 ;
     RECT  15.9 9.011 16.212 15.061 ;
     RECT  18.6 13.139 19.752 15.061 ;
     RECT  21.3 12.851 25.032 15.061 ;
     RECT  82.944 14.243 84.936 15.205 ;
     RECT  10.5 14.915 11.496 15.397 ;
     RECT  18.6 15.061 25.032 15.445 ;
     RECT  58.224 13.525 72.912 15.491 ;
     RECT  37.2 14.627 38.76 15.635 ;
     RECT  79.632 12.563 81.012 15.637 ;
     RECT  7.8 14.339 8.856 15.683 ;
     RECT  7.8 15.683 8.232 15.829 ;
     RECT  26.7 13.235 30.552 15.925 ;
     RECT  5.1 15.061 6.168 15.971 ;
     RECT  37.2 15.635 37.944 16.019 ;
     RECT  49.584 15.349 49.608 16.019 ;
     RECT  50.64 14.291 55.08 16.019 ;
     RECT  82.848 15.205 84.936 16.019 ;
     RECT  10.5 15.397 11.976 16.021 ;
     RECT  26.352 15.925 30.552 16.021 ;
     RECT  32.1 13.427 32.412 16.021 ;
     RECT  10.08 16.021 11.976 16.069 ;
     RECT  34.704 14.437 35.784 16.213 ;
     RECT  18.6 15.445 25.32 16.261 ;
     RECT  50.64 16.019 54.012 16.261 ;
     RECT  13.104 15.011 13.512 16.357 ;
     RECT  18.24 16.261 25.32 16.357 ;
     RECT  13.104 16.357 13.608 16.403 ;
     RECT  79.632 15.637 81.768 16.403 ;
     RECT  59.1 15.491 72.912 16.405 ;
     RECT  74.064 8.675 74.088 16.405 ;
     RECT  18.192 16.357 25.32 16.501 ;
     RECT  26.352 16.021 32.412 16.501 ;
     RECT  15.36 15.061 16.212 16.595 ;
     RECT  82.944 16.019 84.936 16.789 ;
     RECT  18.192 16.501 32.412 16.835 ;
     RECT  13.2 16.403 13.608 16.885 ;
     RECT  82.944 16.789 84.984 16.885 ;
     RECT  86.1 14.243 92.616 16.885 ;
     RECT  21.3 16.835 32.412 16.933 ;
     RECT  33.552 14.531 33.576 16.933 ;
     RECT  21.3 16.933 33.576 17.029 ;
     RECT  13.2 16.885 13.704 17.077 ;
     RECT  50.208 16.261 54.012 17.123 ;
     RECT  82.944 16.885 92.616 17.123 ;
     RECT  18.192 16.835 20.136 17.171 ;
     RECT  79.632 16.403 81.144 17.219 ;
     RECT  75.3 14.629 78.408 17.317 ;
     RECT  50.64 17.123 54.012 17.363 ;
     RECT  75.3 17.317 78.648 17.459 ;
     RECT  15.9 16.595 16.212 17.461 ;
     RECT  21.3 17.029 33.72 17.603 ;
     RECT  9.408 16.069 11.976 17.699 ;
     RECT  21.3 17.603 25.56 17.939 ;
     RECT  34.704 16.213 35.88 18.179 ;
     RECT  7.152 15.829 8.232 18.181 ;
     RECT  9.408 17.699 11.592 18.181 ;
     RECT  18.24 17.171 20.136 18.181 ;
     RECT  59.1 16.405 74.088 18.181 ;
     RECT  5.1 15.971 5.688 18.275 ;
     RECT  26.592 17.603 33.72 18.275 ;
     RECT  58.944 18.181 74.088 18.373 ;
     RECT  21.3 17.939 25.32 18.419 ;
     RECT  5.1 18.275 5.412 18.421 ;
     RECT  38.976 17.077 39 18.707 ;
     RECT  58.944 18.373 74.232 18.707 ;
     RECT  75.3 17.459 78.312 18.709 ;
     RECT  79.632 17.219 81.012 18.709 ;
     RECT  48.3 6.035 48.612 18.757 ;
     RECT  18.192 18.181 20.136 18.851 ;
     RECT  94.2 11.459 95.064 18.997 ;
     RECT  18.432 18.851 20.136 19.043 ;
     RECT  4.752 18.421 5.412 19.093 ;
     RECT  7.152 18.181 11.592 19.237 ;
     RECT  96.9 5.461 97.512 19.333 ;
     RECT  13.2 17.077 13.8 19.379 ;
     RECT  74.064 18.707 74.232 19.427 ;
     RECT  14.784 16.933 14.808 19.523 ;
     RECT  91.5 17.123 92.616 19.523 ;
     RECT  48.3 18.757 49.032 19.571 ;
     RECT  34.704 18.179 35.832 19.621 ;
     RECT  37.2 16.019 37.812 19.621 ;
     RECT  15.9 17.461 16.344 19.909 ;
     RECT  26.7 18.275 33.576 19.909 ;
     RECT  34.704 19.621 37.812 19.909 ;
     RECT  56.4 11.027 56.712 19.909 ;
     RECT  4.656 19.093 5.412 20.003 ;
     RECT  56.4 19.909 57.624 20.197 ;
     RECT  58.944 18.707 72.912 20.197 ;
     RECT  13.2 19.379 13.704 20.389 ;
     RECT  5.1 20.003 5.412 20.437 ;
     RECT  45.6 12.227 45.912 20.485 ;
     RECT  26.7 19.909 37.812 20.581 ;
     RECT  48.3 19.571 48.612 20.581 ;
     RECT  50.64 17.363 51.72 20.581 ;
     RECT  41.616 19.141 41.64 20.629 ;
     RECT  42.672 10.883 43.656 20.629 ;
     RECT  75.3 18.709 81.012 20.723 ;
     RECT  15.504 19.909 16.344 20.725 ;
     RECT  21.3 18.419 25.224 20.869 ;
     RECT  13.104 20.389 13.704 21.109 ;
     RECT  5.1 20.437 5.544 21.155 ;
     RECT  7.104 19.237 11.592 21.155 ;
     RECT  13.104 21.109 13.752 21.155 ;
     RECT  82.944 17.123 90.504 21.155 ;
     RECT  7.8 21.155 11.592 21.443 ;
     RECT  7.8 21.443 8.232 21.539 ;
     RECT  15.36 20.725 16.344 21.637 ;
     RECT  48.3 20.581 49.416 21.637 ;
     RECT  50.64 20.581 51.864 21.637 ;
     RECT  26.7 20.581 37.944 21.923 ;
     RECT  48.3 21.637 51.864 21.923 ;
     RECT  21.3 20.869 25.32 21.925 ;
     RECT  34.704 21.923 37.944 22.021 ;
     RECT  9.408 21.443 11.592 22.115 ;
     RECT  55.056 16.019 55.08 22.117 ;
     RECT  56.4 20.197 72.912 22.117 ;
     RECT  41.616 20.629 43.656 22.163 ;
     RECT  7.8 21.539 8.112 22.165 ;
     RECT  18.432 19.043 19.368 22.165 ;
     RECT  26.7 21.923 33.672 22.259 ;
     RECT  48.3 21.923 51.72 22.259 ;
     RECT  55.056 22.117 72.912 22.259 ;
     RECT  42.144 22.163 43.656 22.451 ;
     RECT  28.992 22.259 33.672 22.499 ;
     RECT  34.704 22.021 38.232 22.499 ;
     RECT  34.704 22.499 35.832 22.547 ;
     RECT  13.2 21.155 13.752 22.739 ;
     RECT  33.456 22.499 33.672 22.739 ;
     RECT  18.432 22.165 19.656 22.741 ;
     RECT  91.5 19.523 91.812 22.741 ;
     RECT  15.36 21.637 16.488 22.789 ;
     RECT  9.408 22.115 10.812 22.835 ;
     RECT  45.6 20.485 46.008 22.835 ;
     RECT  58.944 22.259 72.912 22.835 ;
     RECT  15.024 22.789 16.488 22.931 ;
     RECT  21.3 21.925 25.512 23.029 ;
     RECT  26.7 22.259 27.72 23.029 ;
     RECT  34.704 22.547 35.208 23.125 ;
     RECT  52.944 17.363 54.012 23.269 ;
     RECT  55.056 22.259 56.712 23.269 ;
     RECT  52.944 23.269 56.712 23.315 ;
     RECT  75.3 20.723 78.312 23.317 ;
     RECT  75.3 23.317 78.408 23.411 ;
     RECT  96.9 19.333 98.136 23.411 ;
     RECT  9.408 22.835 9.432 23.891 ;
     RECT  18.432 22.741 19.944 23.891 ;
     RECT  75.3 23.411 77.016 23.893 ;
     RECT  21.3 23.029 27.72 23.939 ;
     RECT  82.944 21.155 84.936 23.941 ;
     RECT  7.632 22.165 8.112 23.987 ;
     RECT  52.944 23.315 55.08 24.035 ;
     RECT  15.9 22.931 16.488 24.131 ;
     RECT  34.608 23.125 35.208 24.131 ;
     RECT  15.9 24.131 16.212 24.181 ;
     RECT  94.2 18.997 95.112 24.181 ;
     RECT  15.6 24.181 16.212 24.229 ;
     RECT  91.5 22.741 92.328 24.323 ;
     RECT  10.5 22.835 10.812 24.373 ;
     RECT  82.656 23.941 84.936 24.469 ;
     RECT  86.1 21.155 90.504 24.469 ;
     RECT  12.048 23.317 12.072 24.563 ;
     RECT  13.2 22.739 13.608 24.563 ;
     RECT  21.3 23.939 25.512 24.563 ;
     RECT  78 23.411 78.408 24.613 ;
     RECT  74.064 19.427 74.088 24.661 ;
     RECT  75.168 23.893 77.016 24.661 ;
     RECT  94.08 24.181 95.112 25.043 ;
     RECT  42.624 22.451 43.656 25.045 ;
     RECT  50.064 22.259 51.312 25.045 ;
     RECT  55.056 24.035 55.08 25.045 ;
     RECT  96.9 23.411 97.56 25.091 ;
     RECT  9.696 24.373 10.812 25.139 ;
     RECT  37.2 22.499 38.232 25.187 ;
     RECT  82.656 24.469 90.504 25.187 ;
     RECT  37.2 25.187 37.812 25.283 ;
     RECT  33.456 22.739 33.624 25.573 ;
     RECT  34.704 24.131 35.208 25.573 ;
     RECT  14.976 24.229 16.212 25.715 ;
     RECT  28.992 22.499 32.412 25.715 ;
     RECT  82.944 25.187 90.504 25.715 ;
     RECT  78 24.613 78.648 25.765 ;
     RECT  79.68 20.723 81.012 25.765 ;
     RECT  88.272 25.715 90.504 25.811 ;
     RECT  18.432 23.891 19.656 25.813 ;
     RECT  28.992 25.715 30.552 25.861 ;
     RECT  33.456 25.573 35.208 26.053 ;
     RECT  52.944 24.035 54.012 26.053 ;
     RECT  55.008 25.045 55.08 26.053 ;
     RECT  58.944 22.835 62.472 26.053 ;
     RECT  94.2 25.043 95.112 26.197 ;
     RECT  96.9 25.091 97.512 26.197 ;
     RECT  78 25.765 81.012 26.243 ;
     RECT  37.5 25.283 37.812 26.245 ;
     RECT  17.328 24.805 17.352 26.291 ;
     RECT  49.584 25.045 51.912 26.579 ;
     RECT  21.3 24.563 25.224 26.677 ;
     RECT  88.32 25.811 90.504 26.677 ;
     RECT  91.5 24.323 91.812 26.677 ;
     RECT  96.336 26.197 97.512 26.677 ;
     RECT  13.2 24.563 13.512 26.725 ;
     RECT  40.2 14.531 40.512 26.725 ;
     RECT  52.944 26.053 55.08 26.725 ;
     RECT  56.4 23.315 56.712 26.725 ;
     RECT  28.8 25.861 30.552 26.819 ;
     RECT  52.944 26.725 56.712 26.867 ;
     RECT  20.784 26.677 25.224 26.869 ;
     RECT  63.6 22.835 72.912 27.107 ;
     RECT  15.6 25.715 16.212 27.155 ;
     RECT  48.3 22.259 48.612 27.157 ;
     RECT  49.584 26.579 51.312 27.157 ;
     RECT  55.056 26.867 56.712 27.203 ;
     RECT  20.784 26.869 25.272 27.205 ;
     RECT  45.6 22.835 45.912 27.301 ;
     RECT  52.944 26.867 54.012 27.301 ;
     RECT  88.32 26.677 91.812 27.347 ;
     RECT  37.5 26.245 38.28 27.395 ;
     RECT  40.08 26.725 40.512 27.395 ;
     RECT  58.848 26.053 62.472 27.397 ;
     RECT  13.008 26.725 13.512 27.635 ;
     RECT  20.784 27.205 25.704 27.635 ;
     RECT  96.096 26.677 97.512 27.733 ;
     RECT  58.608 27.397 62.472 27.781 ;
     RECT  55.056 27.203 55.416 27.875 ;
     RECT  13.2 27.635 13.512 27.877 ;
     RECT  14.688 27.301 14.712 27.877 ;
     RECT  21.3 27.635 25.704 27.877 ;
     RECT  26.7 23.939 27.72 27.877 ;
     RECT  93.456 26.197 95.112 27.971 ;
     RECT  21.3 27.877 27.72 27.973 ;
     RECT  45.6 27.301 46.2 28.405 ;
     RECT  45.072 28.405 46.2 28.451 ;
     RECT  42.432 25.045 43.656 28.453 ;
     RECT  48.3 27.157 51.312 28.453 ;
     RECT  78 26.243 78.936 28.499 ;
     RECT  93.456 27.971 95.064 28.547 ;
     RECT  96.096 27.733 98.472 28.643 ;
     RECT  13.2 27.877 14.712 28.691 ;
     RECT  32.1 25.715 32.412 28.693 ;
     RECT  52.896 27.301 54.012 28.739 ;
     RECT  21.3 27.973 28.008 28.741 ;
     RECT  28.992 26.819 30.552 28.741 ;
     RECT  33.456 26.053 35.928 28.837 ;
     RECT  37.5 27.395 37.812 28.837 ;
     RECT  74.064 24.661 77.016 28.933 ;
     RECT  78 28.499 78.696 28.933 ;
     RECT  55.056 27.875 55.08 28.981 ;
     RECT  88.32 27.347 90.504 28.981 ;
     RECT  91.5 27.347 91.812 28.981 ;
     RECT  33.456 28.837 37.812 29.029 ;
     RECT  56.4 27.203 56.712 29.077 ;
     RECT  58.128 27.781 62.472 29.077 ;
     RECT  21.3 28.741 30.552 29.123 ;
     RECT  33.456 29.029 38.136 29.123 ;
     RECT  47.328 28.453 51.312 29.123 ;
     RECT  63.6 27.107 70.968 29.123 ;
     RECT  56.4 29.077 62.472 29.363 ;
     RECT  14.688 28.691 14.712 29.507 ;
     RECT  82.944 25.715 87.24 29.509 ;
     RECT  74.064 28.933 78.696 29.555 ;
     RECT  31.968 28.693 32.412 29.557 ;
     RECT  33.456 29.123 35.208 29.557 ;
     RECT  47.328 29.123 48.888 29.603 ;
     RECT  50.064 29.123 51.312 29.605 ;
     RECT  45.072 28.451 45.912 29.699 ;
     RECT  58.128 29.363 62.472 29.747 ;
     RECT  75.3 29.555 78.648 29.747 ;
     RECT  15.9 27.155 16.212 29.749 ;
     RECT  31.968 29.557 35.208 29.795 ;
     RECT  82.08 29.509 87.24 30.037 ;
     RECT  88.32 28.981 91.812 30.037 ;
     RECT  41.952 28.453 43.656 30.083 ;
     RECT  55.056 28.981 55.272 30.181 ;
     RECT  56.4 29.363 56.712 30.181 ;
     RECT  75.3 29.747 78.312 30.227 ;
     RECT  23.184 29.123 30.552 30.275 ;
     RECT  47.328 29.603 48.612 30.275 ;
     RECT  50.064 29.605 51.864 30.275 ;
     RECT  59.1 29.747 62.472 30.275 ;
     RECT  63.6 29.123 70.728 30.275 ;
     RECT  82.08 30.037 91.812 30.275 ;
     RECT  93.936 28.547 95.064 30.275 ;
     RECT  15.9 29.749 16.344 30.611 ;
     RECT  42.672 30.083 43.656 30.613 ;
     RECT  82.944 30.275 91.812 30.707 ;
     RECT  48.3 30.275 48.612 30.757 ;
     RECT  50.064 30.275 51.312 30.757 ;
     RECT  42.672 30.613 43.848 30.803 ;
     RECT  68.976 30.275 70.728 30.803 ;
     RECT  36.528 29.123 38.136 30.851 ;
     RECT  55.056 30.181 56.712 30.899 ;
     RECT  86.1 30.707 91.812 31.139 ;
     RECT  74.064 29.555 74.088 31.237 ;
     RECT  75.3 30.227 77.016 31.237 ;
     RECT  96.096 28.643 97.512 31.237 ;
     RECT  26.112 30.275 30.552 31.285 ;
     RECT  31.968 29.795 35.112 31.285 ;
     RECT  48.3 30.757 51.312 31.285 ;
     RECT  52.944 28.739 54.012 31.379 ;
     RECT  21.3 29.123 21.612 31.429 ;
     RECT  96.096 31.237 97.56 31.861 ;
     RECT  88.32 31.139 91.812 31.907 ;
     RECT  53.568 31.379 54.012 31.957 ;
     RECT  55.056 30.899 55.08 31.957 ;
     RECT  18.432 25.813 19.704 32.003 ;
     RECT  53.568 31.957 55.08 32.099 ;
     RECT  37.5 30.851 38.136 32.245 ;
     RECT  74.064 31.237 77.016 32.293 ;
     RECT  78 30.227 78.312 32.293 ;
     RECT  45.6 29.699 45.912 32.437 ;
     RECT  69.9 30.803 70.728 32.437 ;
     RECT  82.944 30.707 84.936 32.437 ;
     RECT  86.1 31.139 87.24 32.437 ;
     RECT  88.32 31.907 90.504 32.437 ;
     RECT  63.6 30.275 67.512 32.485 ;
     RECT  74.064 32.293 78.312 32.725 ;
     RECT  79.968 26.243 81.012 32.725 ;
     RECT  37.392 32.245 38.136 32.771 ;
     RECT  69.792 32.437 70.728 32.821 ;
     RECT  71.952 27.107 72.912 32.821 ;
     RECT  63.6 32.485 67.896 32.965 ;
     RECT  69.792 32.821 72.912 32.965 ;
     RECT  26.112 31.285 35.112 33.013 ;
     RECT  44.832 32.437 45.912 33.013 ;
     RECT  74.064 32.725 81.012 33.013 ;
     RECT  82.944 32.437 90.504 33.013 ;
     RECT  91.5 31.907 91.812 33.013 ;
     RECT  99.6 2.151 99.912 33.013 ;
     RECT  74.064 33.013 81.48 33.059 ;
     RECT  60.72 30.275 62.472 33.061 ;
     RECT  63.456 32.965 67.896 33.061 ;
     RECT  60.72 33.061 67.896 33.299 ;
     RECT  60.72 33.299 67.512 33.395 ;
     RECT  69.744 32.965 72.912 33.493 ;
     RECT  96.096 31.861 98.52 33.539 ;
     RECT  79.968 33.059 81.48 33.541 ;
     RECT  82.944 33.013 91.812 33.541 ;
     RECT  26.112 33.013 35.208 33.589 ;
     RECT  40.2 27.395 40.512 33.589 ;
     RECT  56.4 30.899 56.712 33.589 ;
     RECT  21.024 31.429 21.612 33.683 ;
     RECT  48.3 31.285 51.96 33.683 ;
     RECT  69.744 33.493 73.032 33.683 ;
     RECT  79.968 33.541 91.812 33.683 ;
     RECT  23.184 30.275 24.408 34.067 ;
     RECT  91.5 33.683 91.812 34.069 ;
     RECT  14.784 31.765 14.808 34.115 ;
     RECT  50.064 33.683 51.96 34.117 ;
     RECT  94.2 30.275 95.064 34.165 ;
     RECT  80.7 33.683 90.504 34.259 ;
     RECT  25.68 33.589 35.208 34.307 ;
     RECT  47.28 33.541 47.304 34.357 ;
     RECT  48.3 33.683 48.612 34.357 ;
     RECT  59.1 30.275 59.412 34.357 ;
     RECT  63.456 33.395 67.512 34.357 ;
     RECT  39.312 33.589 40.512 34.403 ;
     RECT  94.2 34.165 95.736 34.403 ;
     RECT  69.792 33.683 73.032 34.499 ;
     RECT  47.28 34.357 48.612 34.595 ;
     RECT  80.7 34.259 90.312 34.643 ;
     RECT  96.768 33.539 98.52 34.645 ;
     RECT  18.432 32.003 19.128 34.693 ;
     RECT  37.5 32.771 38.136 34.693 ;
     RECT  53.568 32.099 54.012 34.741 ;
     RECT  55.056 32.099 55.08 34.741 ;
     RECT  58.896 34.357 59.412 34.741 ;
     RECT  60.72 33.395 62.472 34.741 ;
     RECT  63.456 34.357 67.608 34.741 ;
     RECT  94.2 34.403 95.064 34.741 ;
     RECT  96.768 34.645 98.568 34.741 ;
     RECT  56.4 33.589 57.144 34.787 ;
     RECT  80.7 34.643 87.24 34.835 ;
     RECT  37.5 34.693 38.568 34.885 ;
     RECT  21.072 33.683 21.612 34.931 ;
     RECT  34.224 34.307 35.208 35.027 ;
     RECT  96.768 34.741 98.616 35.029 ;
     RECT  18.432 34.693 19.368 35.077 ;
     RECT  34.704 35.027 35.208 35.123 ;
     RECT  50.064 34.117 52.152 35.315 ;
     RECT  60.72 34.741 67.608 35.317 ;
     RECT  68.592 34.165 68.616 35.317 ;
     RECT  53.568 34.741 55.08 35.363 ;
     RECT  74.064 33.059 78.312 35.363 ;
     RECT  80.7 34.835 81.012 35.413 ;
     RECT  99.6 33.013 100.008 35.459 ;
     RECT  25.68 34.307 33.24 35.507 ;
     RECT  96.384 35.029 98.616 35.509 ;
     RECT  99.6 35.459 99.912 35.509 ;
     RECT  93.744 34.741 95.064 35.651 ;
     RECT  25.68 35.507 33.048 35.701 ;
     RECT  53.568 35.363 54.012 35.843 ;
     RECT  25.536 35.701 33.048 35.939 ;
     RECT  23.184 34.067 24.312 35.989 ;
     RECT  25.536 35.939 30.12 35.989 ;
     RECT  58.128 34.741 59.412 35.989 ;
     RECT  47.616 34.595 48.612 36.035 ;
     RECT  31.584 35.939 33.048 36.131 ;
     RECT  42.672 30.803 43.656 36.229 ;
     RECT  58.128 35.989 59.544 36.229 ;
     RECT  60.672 35.317 68.616 36.229 ;
     RECT  21.3 34.931 21.612 36.325 ;
     RECT  79.488 36.037 79.512 36.421 ;
     RECT  18.432 35.077 19.464 36.515 ;
     RECT  31.968 36.131 33.048 36.515 ;
     RECT  58.128 36.229 68.616 36.515 ;
     RECT  31.968 36.515 32.76 36.563 ;
     RECT  82.032 34.835 87.24 36.563 ;
     RECT  42.432 36.229 43.656 36.565 ;
     RECT  44.688 33.013 45.912 36.565 ;
     RECT  91.5 34.069 92.328 36.565 ;
     RECT  94.032 35.651 95.064 36.707 ;
     RECT  50.064 35.315 51.312 36.997 ;
     RECT  59.1 36.515 68.616 36.997 ;
     RECT  69.792 34.499 72.912 36.997 ;
     RECT  23.184 35.989 30.12 37.045 ;
     RECT  23.184 37.045 30.408 37.091 ;
     RECT  39.888 34.403 40.512 37.091 ;
     RECT  79.488 36.421 79.608 37.139 ;
     RECT  28.128 37.091 30.408 37.235 ;
     RECT  29.4 37.235 30.408 37.331 ;
     RECT  37.056 34.885 38.568 37.331 ;
     RECT  42.432 36.565 45.912 37.379 ;
     RECT  88.32 34.643 90.312 37.379 ;
     RECT  42.672 37.379 45.912 37.429 ;
     RECT  18.6 36.515 19.032 37.525 ;
     RECT  34.704 35.123 35.112 37.573 ;
     RECT  48.3 36.035 48.612 37.573 ;
     RECT  50.064 36.997 51.96 37.573 ;
     RECT  55.056 35.363 55.08 37.573 ;
     RECT  74.064 35.363 77.016 37.573 ;
     RECT  40.2 37.091 40.512 37.621 ;
     RECT  82.944 36.563 87.24 37.621 ;
     RECT  88.32 37.379 89.88 37.621 ;
     RECT  24 37.091 27.144 37.667 ;
     RECT  31.968 36.563 32.412 37.667 ;
     RECT  79.488 37.139 79.512 37.667 ;
     RECT  96.384 35.509 99.912 37.667 ;
     RECT  56.4 34.787 56.712 37.669 ;
     RECT  59.1 36.997 72.912 37.859 ;
     RECT  48.3 37.573 51.96 38.101 ;
     RECT  48.3 38.101 52.728 38.149 ;
     RECT  94.08 36.707 95.064 38.149 ;
     RECT  42.672 37.429 46.152 38.195 ;
     RECT  34.704 37.573 35.208 38.197 ;
     RECT  60.672 37.859 72.912 38.197 ;
     RECT  74.016 37.573 77.016 38.197 ;
     RECT  82.944 37.621 89.88 38.243 ;
     RECT  96.9 37.667 99.912 38.243 ;
     RECT  59.1 37.859 59.544 38.387 ;
     RECT  40.2 37.621 40.632 38.389 ;
     RECT  34.704 38.197 35.352 38.435 ;
     RECT  94.08 38.149 95.304 38.435 ;
     RECT  37.296 37.331 38.568 38.437 ;
     RECT  48.048 38.149 52.728 38.437 ;
     RECT  53.7 35.843 54.012 38.437 ;
     RECT  82.944 38.243 84.936 38.437 ;
     RECT  91.5 36.565 92.376 38.531 ;
     RECT  60.672 38.197 77.016 38.675 ;
     RECT  29.4 37.331 29.712 38.677 ;
     RECT  39.6 38.389 40.632 38.677 ;
     RECT  59.1 38.387 59.412 38.725 ;
     RECT  82.56 38.437 84.936 38.725 ;
     RECT  86.1 38.243 89.88 38.725 ;
     RECT  91.5 38.531 92.328 38.725 ;
     RECT  20.544 36.325 21.612 38.771 ;
     RECT  48.048 38.437 54.012 38.771 ;
     RECT  55.056 37.573 55.176 38.771 ;
     RECT  80.592 35.413 81.012 38.819 ;
     RECT  86.1 38.725 92.328 38.867 ;
     RECT  34.704 38.435 35.256 38.965 ;
     RECT  34.416 38.965 35.256 39.203 ;
     RECT  96.9 38.243 97.56 39.205 ;
     RECT  98.592 38.243 99.912 39.205 ;
     RECT  36.768 38.437 38.568 39.251 ;
     RECT  56.4 37.669 57.672 39.251 ;
     RECT  96.9 39.205 99.912 39.251 ;
     RECT  42.672 38.195 45.912 39.301 ;
     RECT  82.032 38.725 84.936 39.301 ;
     RECT  86.1 38.867 87.24 39.301 ;
     RECT  37.296 39.251 38.568 39.347 ;
     RECT  69.12 38.675 77.016 39.347 ;
     RECT  18.6 37.525 19.464 39.395 ;
     RECT  18.6 39.395 19.032 39.443 ;
     RECT  96.9 39.251 98.088 39.539 ;
     RECT  41.856 39.301 45.912 39.589 ;
     RECT  41.856 39.589 46.728 39.635 ;
     RECT  34.416 39.203 35.112 39.829 ;
     RECT  48.048 38.771 48.612 39.829 ;
     RECT  50.064 38.771 54.012 39.829 ;
     RECT  55.056 38.771 55.08 39.829 ;
     RECT  94.2 38.435 95.304 39.829 ;
     RECT  50.064 39.829 55.08 39.875 ;
     RECT  78 35.363 78.312 39.877 ;
     RECT  56.4 39.251 57.048 39.923 ;
     RECT  96.9 39.539 97.56 39.923 ;
     RECT  82.032 39.301 87.24 40.019 ;
     RECT  74.016 39.347 77.016 40.067 ;
     RECT  24 37.667 27.012 40.115 ;
     RECT  58.896 38.725 59.412 40.117 ;
     RECT  24 40.115 24.312 40.165 ;
     RECT  88.32 38.867 92.328 40.211 ;
     RECT  82.944 40.019 87.24 40.307 ;
     RECT  34.224 39.829 35.112 40.405 ;
     RECT  41.856 39.635 43.704 40.405 ;
     RECT  39.6 38.677 40.728 40.451 ;
     RECT  94.08 39.829 95.304 40.451 ;
     RECT  25.68 40.115 27.012 40.547 ;
     RECT  41.712 40.405 43.704 40.595 ;
     RECT  91.5 40.211 92.328 40.595 ;
     RECT  99.168 39.251 99.912 40.597 ;
     RECT  69.12 39.347 72.912 40.643 ;
     RECT  88.32 40.211 90.12 40.643 ;
     RECT  44.784 39.635 46.728 40.787 ;
     RECT  29.4 38.677 29.88 40.885 ;
     RECT  50.064 39.875 52.728 40.979 ;
     RECT  52.704 40.979 52.728 41.029 ;
     RECT  53.7 39.875 55.08 41.029 ;
     RECT  23.904 40.165 24.312 41.075 ;
     RECT  41.712 40.595 43.656 41.075 ;
     RECT  50.064 40.979 51.48 41.075 ;
     RECT  52.704 41.029 55.08 41.075 ;
     RECT  60.672 38.675 68.136 41.075 ;
     RECT  78 39.877 78.984 41.075 ;
     RECT  29.4 40.885 30.12 41.269 ;
     RECT  60.672 41.075 66.216 41.315 ;
     RECT  21.072 38.771 21.612 41.411 ;
     RECT  58.128 40.117 59.412 41.413 ;
     RECT  37.5 39.347 38.568 41.461 ;
     RECT  39.6 40.451 40.512 41.461 ;
     RECT  74.016 40.067 74.328 41.461 ;
     RECT  75.3 40.067 77.016 41.461 ;
     RECT  34.224 40.405 35.64 41.557 ;
     RECT  34.176 41.557 35.64 41.651 ;
     RECT  74.016 41.461 77.016 41.651 ;
     RECT  57.84 41.413 59.412 41.797 ;
     RECT  52.896 41.075 55.08 41.939 ;
     RECT  41.856 41.075 43.656 42.133 ;
     RECT  50.064 41.075 51.312 42.181 ;
     RECT  44.784 40.787 46.392 42.227 ;
     RECT  47.904 39.829 48.612 42.227 ;
     RECT  74.064 41.651 77.016 42.227 ;
     RECT  94.2 40.451 95.304 42.227 ;
     RECT  60.672 41.315 65.688 42.421 ;
     RECT  67.2 41.075 68.136 42.421 ;
     RECT  34.176 41.651 35.112 42.515 ;
     RECT  57.84 41.797 59.64 42.515 ;
     RECT  60.672 42.421 68.136 42.563 ;
     RECT  52.896 41.939 54.012 42.565 ;
     RECT  41.568 42.133 43.656 42.709 ;
     RECT  44.784 42.227 45.912 42.709 ;
     RECT  58.848 42.515 59.64 42.755 ;
     RECT  82.944 40.307 84.936 42.757 ;
     RECT  96.9 39.923 97.212 42.757 ;
     RECT  99.024 40.597 99.912 42.757 ;
     RECT  28.128 37.235 28.296 42.803 ;
     RECT  37.5 41.461 40.512 43.141 ;
     RECT  41.568 42.709 45.912 43.141 ;
     RECT  56.4 39.923 56.712 43.141 ;
     RECT  57.84 42.515 57.864 43.141 ;
     RECT  96.9 42.757 99.912 43.141 ;
     RECT  29.4 41.269 30.264 43.187 ;
     RECT  37.5 43.141 45.912 43.187 ;
     RECT  94.2 42.227 95.064 43.237 ;
     RECT  39.024 43.187 45.912 43.283 ;
     RECT  86.1 40.307 87.24 43.285 ;
     RECT  28.272 42.803 28.296 43.379 ;
     RECT  69.36 40.643 72.912 43.427 ;
     RECT  74.064 42.227 75.612 43.523 ;
     RECT  58.848 42.755 59.412 43.571 ;
     RECT  96.768 43.141 99.912 43.571 ;
     RECT  49.584 42.181 51.312 43.667 ;
     RECT  47.04 42.709 47.064 43.811 ;
     RECT  32.1 37.667 32.412 43.813 ;
     RECT  80.7 38.819 81.012 43.813 ;
     RECT  88.32 40.643 89.88 43.861 ;
     RECT  42.432 43.283 45.912 43.955 ;
     RECT  86.1 43.285 87.288 44.293 ;
     RECT  88.32 43.861 90.072 44.293 ;
     RECT  91.5 40.595 91.812 44.293 ;
     RECT  93.456 43.237 95.064 44.293 ;
     RECT  82.896 42.757 84.936 44.339 ;
     RECT  91.5 44.293 95.064 44.339 ;
     RECT  52.848 42.565 54.012 44.341 ;
     RECT  59.1 43.571 59.412 44.341 ;
     RECT  69.504 43.427 72.912 44.341 ;
     RECT  74.064 43.523 74.088 44.341 ;
     RECT  48.3 42.227 48.612 44.437 ;
     RECT  78 41.075 78.312 44.437 ;
     RECT  79.536 43.285 79.56 44.437 ;
     RECT  56.4 43.141 57.864 44.483 ;
     RECT  80.592 43.813 81.012 44.483 ;
     RECT  82.944 44.339 84.936 44.483 ;
     RECT  86.1 44.293 90.072 44.483 ;
     RECT  96.768 43.571 98.088 44.483 ;
     RECT  42.432 43.955 43.944 44.627 ;
     RECT  31.968 43.813 32.412 44.677 ;
     RECT  45.264 43.955 45.912 44.723 ;
     RECT  75.3 43.523 75.612 44.725 ;
     RECT  76.992 42.227 77.016 44.725 ;
     RECT  57.84 44.483 57.864 44.965 ;
     RECT  59.1 44.341 59.544 44.965 ;
     RECT  75.3 44.725 77.016 45.059 ;
     RECT  91.5 44.339 92.76 45.059 ;
     RECT  60.672 42.563 66.168 45.205 ;
     RECT  67.2 42.563 68.136 45.205 ;
     RECT  18.6 39.443 18.912 45.301 ;
     RECT  36.48 42.709 36.504 45.301 ;
     RECT  94.2 44.339 95.064 45.445 ;
     RECT  78 44.437 79.56 45.541 ;
     RECT  80.7 44.483 81.012 45.541 ;
     RECT  96.9 44.483 97.212 45.541 ;
     RECT  69.504 44.341 74.088 45.587 ;
     RECT  39.024 43.283 41.112 45.589 ;
     RECT  42.432 44.627 43.656 45.589 ;
     RECT  78 45.541 81.012 45.635 ;
     RECT  83.4 44.483 84.936 45.635 ;
     RECT  36.24 45.301 36.504 45.685 ;
     RECT  37.5 43.187 37.812 45.685 ;
     RECT  86.1 44.483 89.88 45.731 ;
     RECT  91.5 45.059 92.232 45.781 ;
     RECT  50.064 43.667 51.312 45.877 ;
     RECT  52.752 44.341 54.012 45.923 ;
     RECT  52.848 45.923 54.012 45.973 ;
     RECT  55.056 41.939 55.08 45.973 ;
     RECT  39.024 45.589 43.656 46.069 ;
     RECT  60.672 45.205 68.136 46.069 ;
     RECT  69.504 45.587 72.912 46.069 ;
     RECT  60.672 46.069 72.912 46.115 ;
     RECT  56.4 44.483 56.808 46.117 ;
     RECT  57.84 44.965 59.544 46.117 ;
     RECT  25.776 40.547 27.012 46.211 ;
     RECT  36.24 45.685 37.812 46.211 ;
     RECT  75.3 45.059 76.92 46.211 ;
     RECT  84.816 45.635 84.936 46.211 ;
     RECT  56.4 46.117 59.544 46.259 ;
     RECT  15.9 30.611 16.212 46.357 ;
     RECT  47.616 44.437 48.612 46.501 ;
     RECT  91.248 45.781 92.232 46.501 ;
     RECT  24 41.075 24.312 46.597 ;
     RECT  78 45.635 78.312 46.645 ;
     RECT  23.856 46.597 24.312 46.693 ;
     RECT  91.248 46.501 92.808 46.739 ;
     RECT  94.2 45.445 95.208 46.739 ;
     RECT  52.848 45.973 55.08 46.787 ;
     RECT  75.3 46.211 76.296 46.787 ;
     RECT  63.552 46.115 72.912 46.835 ;
     RECT  96.9 45.541 98.088 46.979 ;
     RECT  39.024 46.069 44.472 47.027 ;
     RECT  39.024 47.027 41.112 47.075 ;
     RECT  57.744 46.259 59.544 47.171 ;
     RECT  36.576 46.211 37.812 47.269 ;
     RECT  39.024 47.075 40.632 47.269 ;
     RECT  83.4 45.635 83.712 47.269 ;
     RECT  46.992 46.501 48.744 47.315 ;
     RECT  31.344 44.677 32.412 47.363 ;
     RECT  36.576 47.269 40.632 47.363 ;
     RECT  42.432 47.027 44.472 47.363 ;
     RECT  46.992 47.315 48.612 47.363 ;
     RECT  58.512 47.171 59.544 47.363 ;
     RECT  74.064 45.587 74.088 47.363 ;
     RECT  77.904 46.645 78.312 47.363 ;
     RECT  79.536 45.635 81.012 47.363 ;
     RECT  91.5 46.739 92.808 47.363 ;
     RECT  39.408 47.363 40.632 47.411 ;
     RECT  50.064 45.877 51.48 47.411 ;
     RECT  58.656 47.363 59.544 47.411 ;
     RECT  63.552 46.835 68.136 47.555 ;
     RECT  52.992 46.787 55.08 47.603 ;
     RECT  60.672 46.115 62.424 47.651 ;
     RECT  78 47.363 78.312 47.653 ;
     RECT  60.672 47.651 60.696 47.699 ;
     RECT  44.4 47.363 44.472 47.747 ;
     RECT  66.144 47.555 68.136 47.795 ;
     RECT  79.536 47.363 79.56 47.843 ;
     RECT  55.056 47.603 55.08 47.845 ;
     RECT  56.4 46.259 56.712 47.845 ;
     RECT  61.8 47.651 62.424 47.845 ;
     RECT  63.552 47.555 64.812 47.845 ;
     RECT  86.1 45.731 87.72 47.845 ;
     RECT  88.8 45.731 89.88 47.845 ;
     RECT  42.432 47.363 43.32 47.891 ;
     RECT  46.992 47.363 47.016 47.891 ;
     RECT  94.2 46.739 95.064 47.939 ;
     RECT  66.144 47.795 67.512 47.987 ;
     RECT  61.8 47.845 64.812 48.035 ;
     RECT  80.592 47.363 81.012 48.325 ;
     RECT  86.1 47.845 89.88 48.467 ;
     RECT  75.3 46.787 75.612 48.469 ;
     RECT  78 47.653 78.504 48.469 ;
     RECT  66.144 47.987 66.168 48.515 ;
     RECT  96.9 46.979 98.04 48.515 ;
     RECT  39.408 47.411 40.512 48.659 ;
     RECT  69.504 46.835 72.912 48.661 ;
     RECT  80.544 48.325 81.012 48.707 ;
     RECT  94.2 47.939 94.68 48.757 ;
     RECT  45.6 44.723 45.912 48.805 ;
     RECT  82.752 47.269 83.712 48.947 ;
     RECT  84.912 46.211 84.936 48.949 ;
     RECT  86.1 48.467 86.412 48.949 ;
     RECT  48.3 47.363 48.612 48.997 ;
     RECT  67.2 47.987 67.512 48.997 ;
     RECT  55.056 47.845 56.712 49.043 ;
     RECT  58.992 47.411 59.544 49.043 ;
     RECT  63.936 48.035 64.812 49.043 ;
     RECT  44.4 47.747 44.424 49.091 ;
     RECT  94.08 48.757 94.68 49.091 ;
     RECT  66.672 48.997 67.512 49.139 ;
     RECT  42.768 47.891 43.32 49.283 ;
     RECT  87.696 48.467 89.88 49.331 ;
     RECT  80.592 48.707 81.012 49.333 ;
     RECT  69.216 48.661 72.912 49.381 ;
     RECT  83.4 48.947 83.712 49.381 ;
     RECT  84.912 48.949 86.412 49.381 ;
     RECT  83.4 49.381 86.412 49.427 ;
     RECT  96.9 48.515 97.212 49.477 ;
     RECT  67.2 49.139 67.512 49.525 ;
     RECT  91.5 47.363 92.04 49.571 ;
     RECT  50.064 47.411 51.312 49.619 ;
     RECT  55.056 49.043 55.08 49.619 ;
     RECT  78 48.469 78.696 49.619 ;
     RECT  88.224 49.331 89.88 49.619 ;
     RECT  74.592 48.469 75.612 49.667 ;
     RECT  64.32 49.043 64.812 49.811 ;
     RECT  61.8 48.035 62.76 49.861 ;
     RECT  50.352 49.619 51.312 49.909 ;
     RECT  52.992 47.603 54.012 49.909 ;
     RECT  96.9 49.477 97.704 50.005 ;
     RECT  50.352 49.909 54.012 50.051 ;
     RECT  56.112 49.043 56.712 50.053 ;
     RECT  56.112 50.053 57 50.195 ;
     RECT  69.216 49.381 73.608 50.195 ;
     RECT  69.216 50.195 71.256 50.291 ;
     RECT  94.08 49.091 94.512 50.389 ;
     RECT  80.592 49.333 81.48 50.435 ;
     RECT  56.4 50.195 57 50.437 ;
     RECT  44.448 49.381 44.472 50.483 ;
     RECT  39.504 48.659 40.512 50.531 ;
     RECT  94.08 50.389 95.208 50.579 ;
     RECT  56.4 50.437 57.768 50.627 ;
     RECT  65.808 50.101 65.832 50.677 ;
     RECT  67.2 49.525 67.608 50.677 ;
     RECT  75.12 49.667 75.612 50.677 ;
     RECT  88.224 49.619 89.112 50.677 ;
     RECT  86.1 49.427 86.412 50.725 ;
     RECT  96.336 50.005 97.704 50.771 ;
     RECT  47.904 48.997 48.612 50.821 ;
     RECT  58.992 49.043 59.412 50.867 ;
     RECT  72.384 50.195 73.608 50.867 ;
     RECT  74.592 50.677 75.612 50.963 ;
     RECT  83.4 49.427 84.408 50.963 ;
     RECT  75.3 50.963 75.612 50.965 ;
     RECT  56.4 50.627 57 51.251 ;
     RECT  86.1 50.725 86.616 51.251 ;
     RECT  88.224 50.677 89.544 51.299 ;
     RECT  94.2 50.579 95.208 51.299 ;
     RECT  45.6 48.805 46.008 51.347 ;
     RECT  50.352 50.051 52.296 51.347 ;
     RECT  65.808 50.677 67.608 51.347 ;
     RECT  61.68 49.861 62.76 51.395 ;
     RECT  88.8 51.299 89.544 51.875 ;
     RECT  93.024 50.005 93.048 51.875 ;
     RECT  56.4 51.251 56.808 51.923 ;
     RECT  75.3 50.965 76.056 51.923 ;
     RECT  80.592 50.435 81.012 52.067 ;
     RECT  51 51.347 52.296 52.499 ;
     RECT  57.984 51.205 58.008 52.499 ;
     RECT  47.376 50.821 48.612 52.549 ;
     RECT  72.384 50.867 72.912 52.931 ;
     RECT  53.568 50.051 54.012 52.979 ;
     RECT  39.552 50.531 40.512 53.075 ;
     RECT  42.9 49.283 43.32 53.125 ;
     RECT  66.384 51.347 67.608 53.315 ;
     RECT  45.6 51.347 45.912 53.365 ;
     RECT  47.232 52.549 48.612 53.365 ;
     RECT  26.7 46.211 27.012 53.557 ;
     RECT  45.6 53.365 48.612 53.557 ;
     RECT  49.728 52.309 49.752 53.557 ;
     RECT  45.6 53.557 49.752 53.603 ;
     RECT  61.8 51.395 62.76 53.699 ;
     RECT  23.856 46.693 25.032 53.941 ;
     RECT  26.112 53.557 27.012 53.941 ;
     RECT  69.456 50.291 71.256 53.941 ;
     RECT  10.5 25.139 10.812 54.085 ;
     RECT  13.2 28.691 13.512 54.085 ;
     RECT  42.192 53.125 43.32 54.085 ;
     RECT  44.448 51.493 44.472 54.085 ;
     RECT  61.8 53.699 62.112 54.085 ;
     RECT  68.976 53.941 71.256 54.085 ;
     RECT  80.7 52.067 81.012 54.085 ;
     RECT  42.192 54.085 44.472 54.179 ;
     RECT  66.384 53.315 67.512 54.469 ;
     RECT  75.3 51.923 75.612 54.469 ;
     RECT  80.592 54.085 81.012 54.469 ;
     RECT  86.1 51.251 86.412 54.469 ;
     RECT  68.544 54.085 71.256 54.517 ;
     RECT  21.3 41.411 21.612 54.661 ;
     RECT  60.912 54.085 62.112 54.661 ;
     RECT  66.192 54.469 67.512 54.661 ;
     RECT  68.496 54.517 71.256 54.661 ;
     RECT  72.6 52.931 72.912 54.661 ;
     RECT  75.3 54.469 76.584 54.661 ;
     RECT  78 49.619 78.312 54.661 ;
     RECT  80.448 54.469 81.012 54.661 ;
     RECT  82.032 54.469 82.056 54.661 ;
     RECT  86.1 54.469 87.432 54.661 ;
     RECT  18.6 45.301 19.656 54.709 ;
     RECT  23.856 53.941 27.012 54.709 ;
     RECT  45.6 53.603 49.272 54.755 ;
     RECT  18.6 54.709 19.704 54.997 ;
     RECT  56.4 51.923 56.712 54.997 ;
     RECT  59.1 50.867 59.412 54.997 ;
     RECT  64.5 49.811 64.812 54.997 ;
     RECT  65.952 54.661 72.912 54.997 ;
     RECT  85.968 54.661 87.432 54.997 ;
     RECT  17.904 54.997 19.704 55.141 ;
     RECT  22.656 54.661 22.68 55.141 ;
     RECT  23.712 54.709 27.012 55.141 ;
     RECT  17.904 55.141 19.8 55.237 ;
     RECT  20.928 54.661 21.612 55.237 ;
     RECT  22.656 55.141 27.012 55.237 ;
     RECT  42.9 54.179 43.848 55.237 ;
     RECT  45.6 54.755 45.912 55.237 ;
     RECT  56.4 54.997 57.432 55.237 ;
     RECT  58.416 54.997 59.412 55.237 ;
     RECT  60.912 54.661 62.232 55.237 ;
     RECT  83.4 50.963 83.712 55.237 ;
     RECT  17.904 55.237 27.24 55.525 ;
     RECT  36.576 47.363 38.088 55.525 ;
     RECT  80.448 54.661 82.056 55.525 ;
     RECT  47.28 54.755 49.272 55.667 ;
     RECT  17.712 55.525 27.24 55.717 ;
     RECT  55.872 55.237 59.412 55.765 ;
     RECT  29.4 43.187 29.712 55.813 ;
     RECT  36.432 55.525 38.76 55.813 ;
     RECT  42.9 55.237 45.912 55.813 ;
     RECT  13.2 54.085 14.04 56.101 ;
     RECT  15.9 46.357 16.344 56.101 ;
     RECT  17.712 55.717 27.288 56.101 ;
     RECT  15.9 56.101 27.288 56.341 ;
     RECT  55.632 55.765 59.412 56.341 ;
     RECT  91.5 49.571 91.812 56.341 ;
     RECT  94.2 51.299 94.512 56.341 ;
     RECT  91.5 56.341 92.184 56.389 ;
     RECT  85.968 54.997 87.768 56.483 ;
     RECT  28.56 55.813 29.712 56.629 ;
     RECT  91.5 56.389 92.328 56.629 ;
     RECT  93.36 56.341 94.512 56.629 ;
     RECT  75.3 54.661 78.408 56.773 ;
     RECT  91.5 56.629 94.512 56.773 ;
     RECT  13.2 56.101 14.136 56.869 ;
     RECT  60.912 55.237 63.24 56.965 ;
     RECT  64.5 54.997 72.912 56.965 ;
     RECT  80.304 55.525 82.056 57.013 ;
     RECT  10.5 54.085 11.304 57.059 ;
     RECT  36.432 55.813 39.192 57.059 ;
     RECT  42 55.813 45.912 57.059 ;
     RECT  47.28 55.667 49.032 57.059 ;
     RECT  75.024 56.773 78.408 57.059 ;
     RECT  83.184 55.237 83.712 57.059 ;
     RECT  60.912 56.965 72.912 57.107 ;
     RECT  13.104 56.869 14.136 57.157 ;
     RECT  15.9 56.341 27.336 57.349 ;
     RECT  28.368 56.629 29.712 57.349 ;
     RECT  85.968 56.483 87.432 57.445 ;
     RECT  88.8 51.875 89.112 57.445 ;
     RECT  15.9 57.349 29.712 57.541 ;
     RECT  85.968 57.445 89.112 57.541 ;
     RECT  55.584 56.341 59.412 57.635 ;
     RECT  15.9 57.541 29.928 57.683 ;
     RECT  42 57.059 43.896 57.973 ;
     RECT  47.28 57.059 48.744 57.973 ;
     RECT  2.4 2.151 2.712 58.059 ;
     RECT  5.1 21.155 5.412 58.059 ;
     RECT  7.8 23.987 8.112 58.059 ;
     RECT  10.5 57.059 10.812 58.059 ;
     RECT  15.9 57.683 16.212 58.059 ;
     RECT  32.1 47.363 32.412 58.059 ;
     RECT  34.8 42.515 35.112 58.059 ;
     RECT  40.2 53.075 40.512 58.059 ;
     RECT  45.6 57.059 45.912 58.059 ;
     RECT  51 52.499 51.312 58.059 ;
     RECT  53.7 52.979 54.012 58.059 ;
     RECT  83.4 57.059 83.712 58.059 ;
     RECT  85.488 57.541 89.112 58.059 ;
     RECT  96.9 50.771 97.212 58.059 ;
     RECT  99.6 43.571 99.912 58.059 ;
     RECT  2.592 58.059 2.712 58.073 ;
     RECT  5.292 58.059 5.412 58.073 ;
     RECT  7.992 58.059 8.112 58.073 ;
     RECT  10.692 58.059 10.812 58.073 ;
     RECT  16.092 58.059 16.212 58.073 ;
     RECT  32.292 58.059 32.412 58.073 ;
     RECT  34.992 58.059 35.112 58.073 ;
     RECT  40.392 58.059 40.512 58.073 ;
     RECT  45.792 58.059 45.912 58.073 ;
     RECT  51.192 58.059 51.312 58.073 ;
     RECT  53.892 58.059 54.012 58.073 ;
     RECT  55.824 57.635 59.412 58.073 ;
     RECT  61.296 57.107 72.912 58.073 ;
     RECT  75.024 57.059 78.312 58.073 ;
     RECT  83.592 58.059 83.712 58.073 ;
     RECT  88.992 58.059 89.112 58.073 ;
     RECT  91.296 56.773 94.512 58.073 ;
     RECT  97.092 58.059 97.212 58.073 ;
     RECT  99.792 58.059 99.912 58.073 ;
     RECT  12.048 57.157 14.136 58.117 ;
     RECT  17.424 57.683 29.928 58.117 ;
     RECT  47.232 57.973 48.744 58.117 ;
     RECT  61.296 58.073 72.264 58.117 ;
     RECT  85.488 58.059 88.008 58.117 ;
     RECT  91.296 58.073 94.152 58.117 ;
     RECT  12.048 58.117 14.184 58.165 ;
     RECT  85.2 58.117 88.008 58.597 ;
     RECT  17.424 58.117 30.312 58.645 ;
     RECT  85.104 58.597 88.008 58.645 ;
     RECT  36.432 57.059 38.952 59.891 ;
     RECT  41.856 57.973 43.896 59.891 ;
     RECT  61.248 58.117 72.264 59.891 ;
     RECT  61.248 59.891 62.232 59.939 ;
     RECT  63.216 59.891 72.264 59.939 ;
     RECT  80.208 57.013 82.056 59.939 ;
     RECT  36.432 59.891 36.84 59.987 ;
     RECT  43.296 59.891 43.896 59.987 ;
     RECT  61.248 59.939 61.704 59.987 ;
     RECT  80.304 59.939 82.056 59.987 ;
     RECT  61.248 59.987 61.656 60.083 ;
     RECT  61.248 60.083 61.32 60.323 ;
     RECT  38.016 59.891 38.952 60.371 ;
     RECT  64.368 59.939 72.264 60.371 ;
     RECT  17.424 58.645 30.408 60.419 ;
     RECT  36.816 59.987 36.84 60.419 ;
     RECT  38.256 60.371 38.808 60.419 ;
     RECT  43.296 59.987 43.512 60.419 ;
     RECT  47.232 58.117 48.792 60.419 ;
     RECT  61.248 60.323 61.272 60.419 ;
     RECT  63.216 59.939 63.24 60.419 ;
     RECT  64.368 60.371 71.88 60.419 ;
     RECT  80.496 59.987 82.056 60.419 ;
     RECT  12.048 58.165 14.28 60.432 ;
     RECT  17.424 60.419 20.424 60.432 ;
     RECT  27.408 60.419 30.408 60.432 ;
     RECT  55.824 58.073 58.824 60.432 ;
     RECT  68.88 60.419 71.88 60.432 ;
     RECT  75.024 58.073 78.024 60.432 ;
     RECT  85.008 58.645 88.008 60.432 ;
     RECT  91.152 58.117 94.152 60.432 ;
  END
END qfd_landh0_600_NS_104x60
END LIBRARY
